VERSION 5.8 ;
BUSBITCHARS "[]" ;
DIVIDERCHAR "/" ;
UNITS
    DATABASE MICRONS 1000 ;
END UNITS

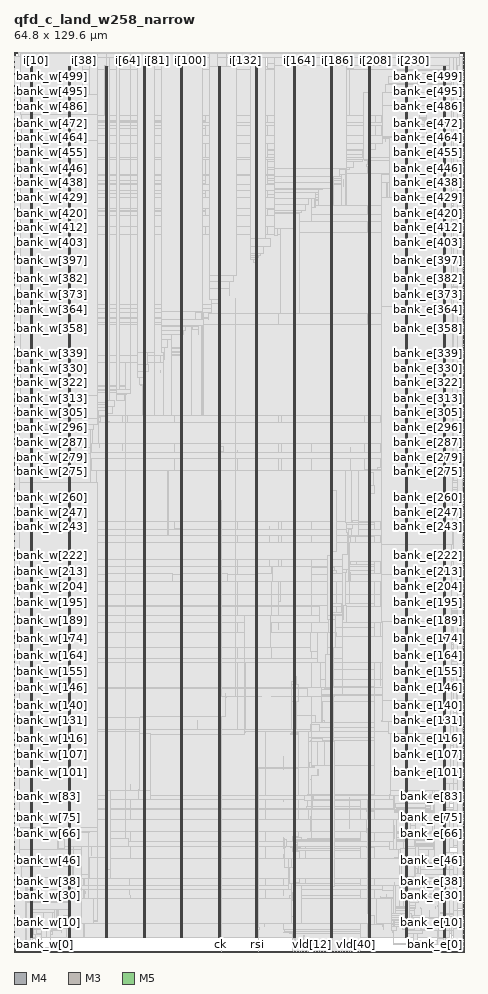
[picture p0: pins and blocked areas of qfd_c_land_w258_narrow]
MACRO qfd_c_land_w258_narrow
  FOREIGN qfd_c_land_w258_narrow 0 0 ;
  CLASS BLOCK ;
  SIZE 64.8 BY 129.6 ;
  PIN bank_e[0]
    DIRECTION OUTPUT ;
    USE SIGNAL ;
    PORT
      LAYER M4 ;
        RECT  64.716 0.672 64.8 0.696 ;
    END
  END bank_e[0]
  PIN bank_e[100]
    DIRECTION OUTPUT ;
    USE SIGNAL ;
    PORT
      LAYER M4 ;
        RECT  64.716 25.584 64.8 25.608 ;
    END
  END bank_e[100]
  PIN bank_e[101]
    DIRECTION OUTPUT ;
    USE SIGNAL ;
    PORT
      LAYER M4 ;
        RECT  64.716 25.824 64.8 25.848 ;
    END
  END bank_e[101]
  PIN bank_e[102]
    DIRECTION OUTPUT ;
    USE SIGNAL ;
    PORT
      LAYER M4 ;
        RECT  64.716 26.064 64.8 26.088 ;
    END
  END bank_e[102]
  PIN bank_e[103]
    DIRECTION OUTPUT ;
    USE SIGNAL ;
    PORT
      LAYER M4 ;
        RECT  64.716 26.304 64.8 26.328 ;
    END
  END bank_e[103]
  PIN bank_e[104]
    DIRECTION OUTPUT ;
    USE SIGNAL ;
    PORT
      LAYER M4 ;
        RECT  64.716 26.544 64.8 26.568 ;
    END
  END bank_e[104]
  PIN bank_e[105]
    DIRECTION OUTPUT ;
    USE SIGNAL ;
    PORT
      LAYER M4 ;
        RECT  64.716 26.784 64.8 26.808 ;
    END
  END bank_e[105]
  PIN bank_e[106]
    DIRECTION OUTPUT ;
    USE SIGNAL ;
    PORT
      LAYER M4 ;
        RECT  64.716 27.072 64.8 27.096 ;
    END
  END bank_e[106]
  PIN bank_e[107]
    DIRECTION OUTPUT ;
    USE SIGNAL ;
    PORT
      LAYER M4 ;
        RECT  64.716 27.312 64.8 27.336 ;
    END
  END bank_e[107]
  PIN bank_e[108]
    DIRECTION OUTPUT ;
    USE SIGNAL ;
    PORT
      LAYER M4 ;
        RECT  64.716 27.552 64.8 27.576 ;
    END
  END bank_e[108]
  PIN bank_e[109]
    DIRECTION OUTPUT ;
    USE SIGNAL ;
    PORT
      LAYER M4 ;
        RECT  64.716 27.792 64.8 27.816 ;
    END
  END bank_e[109]
  PIN bank_e[10]
    DIRECTION OUTPUT ;
    USE SIGNAL ;
    PORT
      LAYER M4 ;
        RECT  64.716 3.12 64.8 3.144 ;
    END
  END bank_e[10]
  PIN bank_e[110]
    DIRECTION OUTPUT ;
    USE SIGNAL ;
    PORT
      LAYER M4 ;
        RECT  64.716 28.032 64.8 28.056 ;
    END
  END bank_e[110]
  PIN bank_e[111]
    DIRECTION OUTPUT ;
    USE SIGNAL ;
    PORT
      LAYER M4 ;
        RECT  64.716 28.32 64.8 28.344 ;
    END
  END bank_e[111]
  PIN bank_e[112]
    DIRECTION OUTPUT ;
    USE SIGNAL ;
    PORT
      LAYER M4 ;
        RECT  64.716 28.56 64.8 28.584 ;
    END
  END bank_e[112]
  PIN bank_e[113]
    DIRECTION OUTPUT ;
    USE SIGNAL ;
    PORT
      LAYER M4 ;
        RECT  64.716 28.8 64.8 28.824 ;
    END
  END bank_e[113]
  PIN bank_e[114]
    DIRECTION OUTPUT ;
    USE SIGNAL ;
    PORT
      LAYER M4 ;
        RECT  64.716 29.04 64.8 29.064 ;
    END
  END bank_e[114]
  PIN bank_e[115]
    DIRECTION OUTPUT ;
    USE SIGNAL ;
    PORT
      LAYER M4 ;
        RECT  64.716 29.28 64.8 29.304 ;
    END
  END bank_e[115]
  PIN bank_e[116]
    DIRECTION OUTPUT ;
    USE SIGNAL ;
    PORT
      LAYER M4 ;
        RECT  64.716 29.568 64.8 29.592 ;
    END
  END bank_e[116]
  PIN bank_e[117]
    DIRECTION OUTPUT ;
    USE SIGNAL ;
    PORT
      LAYER M4 ;
        RECT  64.716 29.808 64.8 29.832 ;
    END
  END bank_e[117]
  PIN bank_e[118]
    DIRECTION OUTPUT ;
    USE SIGNAL ;
    PORT
      LAYER M4 ;
        RECT  64.716 30.048 64.8 30.072 ;
    END
  END bank_e[118]
  PIN bank_e[119]
    DIRECTION OUTPUT ;
    USE SIGNAL ;
    PORT
      LAYER M4 ;
        RECT  64.716 30.288 64.8 30.312 ;
    END
  END bank_e[119]
  PIN bank_e[11]
    DIRECTION OUTPUT ;
    USE SIGNAL ;
    PORT
      LAYER M4 ;
        RECT  64.716 3.408 64.8 3.432 ;
    END
  END bank_e[11]
  PIN bank_e[120]
    DIRECTION OUTPUT ;
    USE SIGNAL ;
    PORT
      LAYER M4 ;
        RECT  64.716 30.528 64.8 30.552 ;
    END
  END bank_e[120]
  PIN bank_e[121]
    DIRECTION OUTPUT ;
    USE SIGNAL ;
    PORT
      LAYER M4 ;
        RECT  64.716 30.768 64.8 30.792 ;
    END
  END bank_e[121]
  PIN bank_e[122]
    DIRECTION OUTPUT ;
    USE SIGNAL ;
    PORT
      LAYER M4 ;
        RECT  64.716 31.056 64.8 31.08 ;
    END
  END bank_e[122]
  PIN bank_e[123]
    DIRECTION OUTPUT ;
    USE SIGNAL ;
    PORT
      LAYER M4 ;
        RECT  64.716 31.296 64.8 31.32 ;
    END
  END bank_e[123]
  PIN bank_e[124]
    DIRECTION OUTPUT ;
    USE SIGNAL ;
    PORT
      LAYER M4 ;
        RECT  64.716 31.536 64.8 31.56 ;
    END
  END bank_e[124]
  PIN bank_e[125]
    DIRECTION OUTPUT ;
    USE SIGNAL ;
    PORT
      LAYER M4 ;
        RECT  64.716 31.776 64.8 31.8 ;
    END
  END bank_e[125]
  PIN bank_e[126]
    DIRECTION OUTPUT ;
    USE SIGNAL ;
    PORT
      LAYER M4 ;
        RECT  64.716 32.016 64.8 32.04 ;
    END
  END bank_e[126]
  PIN bank_e[127]
    DIRECTION OUTPUT ;
    USE SIGNAL ;
    PORT
      LAYER M4 ;
        RECT  64.716 32.304 64.8 32.328 ;
    END
  END bank_e[127]
  PIN bank_e[128]
    DIRECTION OUTPUT ;
    USE SIGNAL ;
    PORT
      LAYER M4 ;
        RECT  64.716 32.544 64.8 32.568 ;
    END
  END bank_e[128]
  PIN bank_e[129]
    DIRECTION OUTPUT ;
    USE SIGNAL ;
    PORT
      LAYER M4 ;
        RECT  64.716 32.784 64.8 32.808 ;
    END
  END bank_e[129]
  PIN bank_e[12]
    DIRECTION OUTPUT ;
    USE SIGNAL ;
    PORT
      LAYER M4 ;
        RECT  64.716 3.648 64.8 3.672 ;
    END
  END bank_e[12]
  PIN bank_e[130]
    DIRECTION OUTPUT ;
    USE SIGNAL ;
    PORT
      LAYER M4 ;
        RECT  64.716 33.024 64.8 33.048 ;
    END
  END bank_e[130]
  PIN bank_e[131]
    DIRECTION OUTPUT ;
    USE SIGNAL ;
    PORT
      LAYER M4 ;
        RECT  64.716 33.264 64.8 33.288 ;
    END
  END bank_e[131]
  PIN bank_e[132]
    DIRECTION OUTPUT ;
    USE SIGNAL ;
    PORT
      LAYER M4 ;
        RECT  64.716 33.552 64.8 33.576 ;
    END
  END bank_e[132]
  PIN bank_e[133]
    DIRECTION OUTPUT ;
    USE SIGNAL ;
    PORT
      LAYER M4 ;
        RECT  64.716 33.792 64.8 33.816 ;
    END
  END bank_e[133]
  PIN bank_e[134]
    DIRECTION OUTPUT ;
    USE SIGNAL ;
    PORT
      LAYER M4 ;
        RECT  64.716 34.032 64.8 34.056 ;
    END
  END bank_e[134]
  PIN bank_e[135]
    DIRECTION OUTPUT ;
    USE SIGNAL ;
    PORT
      LAYER M4 ;
        RECT  64.716 34.272 64.8 34.296 ;
    END
  END bank_e[135]
  PIN bank_e[136]
    DIRECTION OUTPUT ;
    USE SIGNAL ;
    PORT
      LAYER M4 ;
        RECT  64.716 34.512 64.8 34.536 ;
    END
  END bank_e[136]
  PIN bank_e[137]
    DIRECTION OUTPUT ;
    USE SIGNAL ;
    PORT
      LAYER M4 ;
        RECT  64.716 34.752 64.8 34.776 ;
    END
  END bank_e[137]
  PIN bank_e[138]
    DIRECTION OUTPUT ;
    USE SIGNAL ;
    PORT
      LAYER M4 ;
        RECT  64.716 35.04 64.8 35.064 ;
    END
  END bank_e[138]
  PIN bank_e[139]
    DIRECTION OUTPUT ;
    USE SIGNAL ;
    PORT
      LAYER M4 ;
        RECT  64.716 35.28 64.8 35.304 ;
    END
  END bank_e[139]
  PIN bank_e[13]
    DIRECTION OUTPUT ;
    USE SIGNAL ;
    PORT
      LAYER M4 ;
        RECT  64.716 3.888 64.8 3.912 ;
    END
  END bank_e[13]
  PIN bank_e[140]
    DIRECTION OUTPUT ;
    USE SIGNAL ;
    PORT
      LAYER M4 ;
        RECT  64.716 35.52 64.8 35.544 ;
    END
  END bank_e[140]
  PIN bank_e[141]
    DIRECTION OUTPUT ;
    USE SIGNAL ;
    PORT
      LAYER M4 ;
        RECT  64.716 35.76 64.8 35.784 ;
    END
  END bank_e[141]
  PIN bank_e[142]
    DIRECTION OUTPUT ;
    USE SIGNAL ;
    PORT
      LAYER M4 ;
        RECT  64.716 36 64.8 36.024 ;
    END
  END bank_e[142]
  PIN bank_e[143]
    DIRECTION OUTPUT ;
    USE SIGNAL ;
    PORT
      LAYER M4 ;
        RECT  64.716 36.288 64.8 36.312 ;
    END
  END bank_e[143]
  PIN bank_e[144]
    DIRECTION OUTPUT ;
    USE SIGNAL ;
    PORT
      LAYER M4 ;
        RECT  64.716 36.528 64.8 36.552 ;
    END
  END bank_e[144]
  PIN bank_e[145]
    DIRECTION OUTPUT ;
    USE SIGNAL ;
    PORT
      LAYER M4 ;
        RECT  64.716 36.768 64.8 36.792 ;
    END
  END bank_e[145]
  PIN bank_e[146]
    DIRECTION OUTPUT ;
    USE SIGNAL ;
    PORT
      LAYER M4 ;
        RECT  64.716 37.008 64.8 37.032 ;
    END
  END bank_e[146]
  PIN bank_e[147]
    DIRECTION OUTPUT ;
    USE SIGNAL ;
    PORT
      LAYER M4 ;
        RECT  64.716 37.248 64.8 37.272 ;
    END
  END bank_e[147]
  PIN bank_e[148]
    DIRECTION OUTPUT ;
    USE SIGNAL ;
    PORT
      LAYER M4 ;
        RECT  64.716 37.536 64.8 37.56 ;
    END
  END bank_e[148]
  PIN bank_e[149]
    DIRECTION OUTPUT ;
    USE SIGNAL ;
    PORT
      LAYER M4 ;
        RECT  64.716 37.776 64.8 37.8 ;
    END
  END bank_e[149]
  PIN bank_e[14]
    DIRECTION OUTPUT ;
    USE SIGNAL ;
    PORT
      LAYER M4 ;
        RECT  64.716 4.128 64.8 4.152 ;
    END
  END bank_e[14]
  PIN bank_e[150]
    DIRECTION OUTPUT ;
    USE SIGNAL ;
    PORT
      LAYER M4 ;
        RECT  64.716 38.016 64.8 38.04 ;
    END
  END bank_e[150]
  PIN bank_e[151]
    DIRECTION OUTPUT ;
    USE SIGNAL ;
    PORT
      LAYER M4 ;
        RECT  64.716 38.256 64.8 38.28 ;
    END
  END bank_e[151]
  PIN bank_e[152]
    DIRECTION OUTPUT ;
    USE SIGNAL ;
    PORT
      LAYER M4 ;
        RECT  64.716 38.496 64.8 38.52 ;
    END
  END bank_e[152]
  PIN bank_e[153]
    DIRECTION OUTPUT ;
    USE SIGNAL ;
    PORT
      LAYER M4 ;
        RECT  64.716 38.784 64.8 38.808 ;
    END
  END bank_e[153]
  PIN bank_e[154]
    DIRECTION OUTPUT ;
    USE SIGNAL ;
    PORT
      LAYER M4 ;
        RECT  64.716 39.024 64.8 39.048 ;
    END
  END bank_e[154]
  PIN bank_e[155]
    DIRECTION OUTPUT ;
    USE SIGNAL ;
    PORT
      LAYER M4 ;
        RECT  64.716 39.264 64.8 39.288 ;
    END
  END bank_e[155]
  PIN bank_e[156]
    DIRECTION OUTPUT ;
    USE SIGNAL ;
    PORT
      LAYER M4 ;
        RECT  64.716 39.504 64.8 39.528 ;
    END
  END bank_e[156]
  PIN bank_e[157]
    DIRECTION OUTPUT ;
    USE SIGNAL ;
    PORT
      LAYER M4 ;
        RECT  64.716 39.744 64.8 39.768 ;
    END
  END bank_e[157]
  PIN bank_e[158]
    DIRECTION OUTPUT ;
    USE SIGNAL ;
    PORT
      LAYER M4 ;
        RECT  64.716 39.984 64.8 40.008 ;
    END
  END bank_e[158]
  PIN bank_e[159]
    DIRECTION OUTPUT ;
    USE SIGNAL ;
    PORT
      LAYER M4 ;
        RECT  64.716 40.272 64.8 40.296 ;
    END
  END bank_e[159]
  PIN bank_e[15]
    DIRECTION OUTPUT ;
    USE SIGNAL ;
    PORT
      LAYER M4 ;
        RECT  64.716 4.368 64.8 4.392 ;
    END
  END bank_e[15]
  PIN bank_e[160]
    DIRECTION OUTPUT ;
    USE SIGNAL ;
    PORT
      LAYER M4 ;
        RECT  64.716 40.512 64.8 40.536 ;
    END
  END bank_e[160]
  PIN bank_e[161]
    DIRECTION OUTPUT ;
    USE SIGNAL ;
    PORT
      LAYER M4 ;
        RECT  64.716 40.752 64.8 40.776 ;
    END
  END bank_e[161]
  PIN bank_e[162]
    DIRECTION OUTPUT ;
    USE SIGNAL ;
    PORT
      LAYER M4 ;
        RECT  64.716 40.992 64.8 41.016 ;
    END
  END bank_e[162]
  PIN bank_e[163]
    DIRECTION OUTPUT ;
    USE SIGNAL ;
    PORT
      LAYER M4 ;
        RECT  64.716 41.232 64.8 41.256 ;
    END
  END bank_e[163]
  PIN bank_e[164]
    DIRECTION OUTPUT ;
    USE SIGNAL ;
    PORT
      LAYER M4 ;
        RECT  64.716 41.52 64.8 41.544 ;
    END
  END bank_e[164]
  PIN bank_e[165]
    DIRECTION OUTPUT ;
    USE SIGNAL ;
    PORT
      LAYER M4 ;
        RECT  64.716 41.76 64.8 41.784 ;
    END
  END bank_e[165]
  PIN bank_e[166]
    DIRECTION OUTPUT ;
    USE SIGNAL ;
    PORT
      LAYER M4 ;
        RECT  64.716 42 64.8 42.024 ;
    END
  END bank_e[166]
  PIN bank_e[167]
    DIRECTION OUTPUT ;
    USE SIGNAL ;
    PORT
      LAYER M4 ;
        RECT  64.716 42.24 64.8 42.264 ;
    END
  END bank_e[167]
  PIN bank_e[168]
    DIRECTION OUTPUT ;
    USE SIGNAL ;
    PORT
      LAYER M4 ;
        RECT  64.716 42.48 64.8 42.504 ;
    END
  END bank_e[168]
  PIN bank_e[169]
    DIRECTION OUTPUT ;
    USE SIGNAL ;
    PORT
      LAYER M4 ;
        RECT  64.716 42.768 64.8 42.792 ;
    END
  END bank_e[169]
  PIN bank_e[16]
    DIRECTION OUTPUT ;
    USE SIGNAL ;
    PORT
      LAYER M4 ;
        RECT  64.716 4.656 64.8 4.68 ;
    END
  END bank_e[16]
  PIN bank_e[170]
    DIRECTION OUTPUT ;
    USE SIGNAL ;
    PORT
      LAYER M4 ;
        RECT  64.716 43.008 64.8 43.032 ;
    END
  END bank_e[170]
  PIN bank_e[171]
    DIRECTION OUTPUT ;
    USE SIGNAL ;
    PORT
      LAYER M4 ;
        RECT  64.716 43.248 64.8 43.272 ;
    END
  END bank_e[171]
  PIN bank_e[172]
    DIRECTION OUTPUT ;
    USE SIGNAL ;
    PORT
      LAYER M4 ;
        RECT  64.716 43.488 64.8 43.512 ;
    END
  END bank_e[172]
  PIN bank_e[173]
    DIRECTION OUTPUT ;
    USE SIGNAL ;
    PORT
      LAYER M4 ;
        RECT  64.716 43.728 64.8 43.752 ;
    END
  END bank_e[173]
  PIN bank_e[174]
    DIRECTION OUTPUT ;
    USE SIGNAL ;
    PORT
      LAYER M4 ;
        RECT  64.716 43.968 64.8 43.992 ;
    END
  END bank_e[174]
  PIN bank_e[175]
    DIRECTION OUTPUT ;
    USE SIGNAL ;
    PORT
      LAYER M4 ;
        RECT  64.716 44.256 64.8 44.28 ;
    END
  END bank_e[175]
  PIN bank_e[176]
    DIRECTION OUTPUT ;
    USE SIGNAL ;
    PORT
      LAYER M4 ;
        RECT  64.716 44.496 64.8 44.52 ;
    END
  END bank_e[176]
  PIN bank_e[177]
    DIRECTION OUTPUT ;
    USE SIGNAL ;
    PORT
      LAYER M4 ;
        RECT  64.716 44.736 64.8 44.76 ;
    END
  END bank_e[177]
  PIN bank_e[178]
    DIRECTION OUTPUT ;
    USE SIGNAL ;
    PORT
      LAYER M4 ;
        RECT  64.716 44.976 64.8 45 ;
    END
  END bank_e[178]
  PIN bank_e[179]
    DIRECTION OUTPUT ;
    USE SIGNAL ;
    PORT
      LAYER M4 ;
        RECT  64.716 45.216 64.8 45.24 ;
    END
  END bank_e[179]
  PIN bank_e[17]
    DIRECTION OUTPUT ;
    USE SIGNAL ;
    PORT
      LAYER M4 ;
        RECT  64.716 4.896 64.8 4.92 ;
    END
  END bank_e[17]
  PIN bank_e[180]
    DIRECTION OUTPUT ;
    USE SIGNAL ;
    PORT
      LAYER M4 ;
        RECT  64.716 45.504 64.8 45.528 ;
    END
  END bank_e[180]
  PIN bank_e[181]
    DIRECTION OUTPUT ;
    USE SIGNAL ;
    PORT
      LAYER M4 ;
        RECT  64.716 45.744 64.8 45.768 ;
    END
  END bank_e[181]
  PIN bank_e[182]
    DIRECTION OUTPUT ;
    USE SIGNAL ;
    PORT
      LAYER M4 ;
        RECT  64.716 45.984 64.8 46.008 ;
    END
  END bank_e[182]
  PIN bank_e[183]
    DIRECTION OUTPUT ;
    USE SIGNAL ;
    PORT
      LAYER M4 ;
        RECT  64.716 46.224 64.8 46.248 ;
    END
  END bank_e[183]
  PIN bank_e[184]
    DIRECTION OUTPUT ;
    USE SIGNAL ;
    PORT
      LAYER M4 ;
        RECT  64.716 46.464 64.8 46.488 ;
    END
  END bank_e[184]
  PIN bank_e[185]
    DIRECTION OUTPUT ;
    USE SIGNAL ;
    PORT
      LAYER M4 ;
        RECT  64.716 46.752 64.8 46.776 ;
    END
  END bank_e[185]
  PIN bank_e[186]
    DIRECTION OUTPUT ;
    USE SIGNAL ;
    PORT
      LAYER M4 ;
        RECT  64.716 46.992 64.8 47.016 ;
    END
  END bank_e[186]
  PIN bank_e[187]
    DIRECTION OUTPUT ;
    USE SIGNAL ;
    PORT
      LAYER M4 ;
        RECT  64.716 47.232 64.8 47.256 ;
    END
  END bank_e[187]
  PIN bank_e[188]
    DIRECTION OUTPUT ;
    USE SIGNAL ;
    PORT
      LAYER M4 ;
        RECT  64.716 47.472 64.8 47.496 ;
    END
  END bank_e[188]
  PIN bank_e[189]
    DIRECTION OUTPUT ;
    USE SIGNAL ;
    PORT
      LAYER M4 ;
        RECT  64.716 47.712 64.8 47.736 ;
    END
  END bank_e[189]
  PIN bank_e[18]
    DIRECTION OUTPUT ;
    USE SIGNAL ;
    PORT
      LAYER M4 ;
        RECT  64.716 5.136 64.8 5.16 ;
    END
  END bank_e[18]
  PIN bank_e[190]
    DIRECTION OUTPUT ;
    USE SIGNAL ;
    PORT
      LAYER M4 ;
        RECT  64.716 48 64.8 48.024 ;
    END
  END bank_e[190]
  PIN bank_e[191]
    DIRECTION OUTPUT ;
    USE SIGNAL ;
    PORT
      LAYER M4 ;
        RECT  64.716 48.24 64.8 48.264 ;
    END
  END bank_e[191]
  PIN bank_e[192]
    DIRECTION OUTPUT ;
    USE SIGNAL ;
    PORT
      LAYER M4 ;
        RECT  64.716 48.48 64.8 48.504 ;
    END
  END bank_e[192]
  PIN bank_e[193]
    DIRECTION OUTPUT ;
    USE SIGNAL ;
    PORT
      LAYER M4 ;
        RECT  64.716 48.72 64.8 48.744 ;
    END
  END bank_e[193]
  PIN bank_e[194]
    DIRECTION OUTPUT ;
    USE SIGNAL ;
    PORT
      LAYER M4 ;
        RECT  64.716 48.96 64.8 48.984 ;
    END
  END bank_e[194]
  PIN bank_e[195]
    DIRECTION OUTPUT ;
    USE SIGNAL ;
    PORT
      LAYER M4 ;
        RECT  64.716 49.2 64.8 49.224 ;
    END
  END bank_e[195]
  PIN bank_e[196]
    DIRECTION OUTPUT ;
    USE SIGNAL ;
    PORT
      LAYER M4 ;
        RECT  64.716 49.488 64.8 49.512 ;
    END
  END bank_e[196]
  PIN bank_e[197]
    DIRECTION OUTPUT ;
    USE SIGNAL ;
    PORT
      LAYER M4 ;
        RECT  64.716 49.728 64.8 49.752 ;
    END
  END bank_e[197]
  PIN bank_e[198]
    DIRECTION OUTPUT ;
    USE SIGNAL ;
    PORT
      LAYER M4 ;
        RECT  64.716 49.968 64.8 49.992 ;
    END
  END bank_e[198]
  PIN bank_e[199]
    DIRECTION OUTPUT ;
    USE SIGNAL ;
    PORT
      LAYER M4 ;
        RECT  64.716 50.208 64.8 50.232 ;
    END
  END bank_e[199]
  PIN bank_e[19]
    DIRECTION OUTPUT ;
    USE SIGNAL ;
    PORT
      LAYER M4 ;
        RECT  64.716 5.376 64.8 5.4 ;
    END
  END bank_e[19]
  PIN bank_e[1]
    DIRECTION OUTPUT ;
    USE SIGNAL ;
    PORT
      LAYER M4 ;
        RECT  64.716 0.912 64.8 0.936 ;
    END
  END bank_e[1]
  PIN bank_e[200]
    DIRECTION OUTPUT ;
    USE SIGNAL ;
    PORT
      LAYER M4 ;
        RECT  64.716 50.448 64.8 50.472 ;
    END
  END bank_e[200]
  PIN bank_e[201]
    DIRECTION OUTPUT ;
    USE SIGNAL ;
    PORT
      LAYER M4 ;
        RECT  64.716 50.736 64.8 50.76 ;
    END
  END bank_e[201]
  PIN bank_e[202]
    DIRECTION OUTPUT ;
    USE SIGNAL ;
    PORT
      LAYER M4 ;
        RECT  64.716 50.976 64.8 51 ;
    END
  END bank_e[202]
  PIN bank_e[203]
    DIRECTION OUTPUT ;
    USE SIGNAL ;
    PORT
      LAYER M4 ;
        RECT  64.716 51.216 64.8 51.24 ;
    END
  END bank_e[203]
  PIN bank_e[204]
    DIRECTION OUTPUT ;
    USE SIGNAL ;
    PORT
      LAYER M4 ;
        RECT  64.716 51.456 64.8 51.48 ;
    END
  END bank_e[204]
  PIN bank_e[205]
    DIRECTION OUTPUT ;
    USE SIGNAL ;
    PORT
      LAYER M4 ;
        RECT  64.716 51.696 64.8 51.72 ;
    END
  END bank_e[205]
  PIN bank_e[206]
    DIRECTION OUTPUT ;
    USE SIGNAL ;
    PORT
      LAYER M4 ;
        RECT  64.716 51.984 64.8 52.008 ;
    END
  END bank_e[206]
  PIN bank_e[207]
    DIRECTION OUTPUT ;
    USE SIGNAL ;
    PORT
      LAYER M4 ;
        RECT  64.716 52.224 64.8 52.248 ;
    END
  END bank_e[207]
  PIN bank_e[208]
    DIRECTION OUTPUT ;
    USE SIGNAL ;
    PORT
      LAYER M4 ;
        RECT  64.716 52.464 64.8 52.488 ;
    END
  END bank_e[208]
  PIN bank_e[209]
    DIRECTION OUTPUT ;
    USE SIGNAL ;
    PORT
      LAYER M4 ;
        RECT  64.716 52.704 64.8 52.728 ;
    END
  END bank_e[209]
  PIN bank_e[20]
    DIRECTION OUTPUT ;
    USE SIGNAL ;
    PORT
      LAYER M4 ;
        RECT  64.716 5.616 64.8 5.64 ;
    END
  END bank_e[20]
  PIN bank_e[210]
    DIRECTION OUTPUT ;
    USE SIGNAL ;
    PORT
      LAYER M4 ;
        RECT  64.716 52.944 64.8 52.968 ;
    END
  END bank_e[210]
  PIN bank_e[211]
    DIRECTION OUTPUT ;
    USE SIGNAL ;
    PORT
      LAYER M4 ;
        RECT  64.716 53.184 64.8 53.208 ;
    END
  END bank_e[211]
  PIN bank_e[212]
    DIRECTION OUTPUT ;
    USE SIGNAL ;
    PORT
      LAYER M4 ;
        RECT  64.716 53.472 64.8 53.496 ;
    END
  END bank_e[212]
  PIN bank_e[213]
    DIRECTION OUTPUT ;
    USE SIGNAL ;
    PORT
      LAYER M4 ;
        RECT  64.716 53.712 64.8 53.736 ;
    END
  END bank_e[213]
  PIN bank_e[214]
    DIRECTION OUTPUT ;
    USE SIGNAL ;
    PORT
      LAYER M4 ;
        RECT  64.716 53.952 64.8 53.976 ;
    END
  END bank_e[214]
  PIN bank_e[215]
    DIRECTION OUTPUT ;
    USE SIGNAL ;
    PORT
      LAYER M4 ;
        RECT  64.716 54.192 64.8 54.216 ;
    END
  END bank_e[215]
  PIN bank_e[216]
    DIRECTION OUTPUT ;
    USE SIGNAL ;
    PORT
      LAYER M4 ;
        RECT  64.716 54.432 64.8 54.456 ;
    END
  END bank_e[216]
  PIN bank_e[217]
    DIRECTION OUTPUT ;
    USE SIGNAL ;
    PORT
      LAYER M4 ;
        RECT  64.716 54.72 64.8 54.744 ;
    END
  END bank_e[217]
  PIN bank_e[218]
    DIRECTION OUTPUT ;
    USE SIGNAL ;
    PORT
      LAYER M4 ;
        RECT  64.716 54.96 64.8 54.984 ;
    END
  END bank_e[218]
  PIN bank_e[219]
    DIRECTION OUTPUT ;
    USE SIGNAL ;
    PORT
      LAYER M4 ;
        RECT  64.716 55.2 64.8 55.224 ;
    END
  END bank_e[219]
  PIN bank_e[21]
    DIRECTION OUTPUT ;
    USE SIGNAL ;
    PORT
      LAYER M4 ;
        RECT  64.716 5.904 64.8 5.928 ;
    END
  END bank_e[21]
  PIN bank_e[220]
    DIRECTION OUTPUT ;
    USE SIGNAL ;
    PORT
      LAYER M4 ;
        RECT  64.716 55.44 64.8 55.464 ;
    END
  END bank_e[220]
  PIN bank_e[221]
    DIRECTION OUTPUT ;
    USE SIGNAL ;
    PORT
      LAYER M4 ;
        RECT  64.716 55.68 64.8 55.704 ;
    END
  END bank_e[221]
  PIN bank_e[222]
    DIRECTION OUTPUT ;
    USE SIGNAL ;
    PORT
      LAYER M4 ;
        RECT  64.716 55.968 64.8 55.992 ;
    END
  END bank_e[222]
  PIN bank_e[223]
    DIRECTION OUTPUT ;
    USE SIGNAL ;
    PORT
      LAYER M4 ;
        RECT  64.716 56.208 64.8 56.232 ;
    END
  END bank_e[223]
  PIN bank_e[224]
    DIRECTION OUTPUT ;
    USE SIGNAL ;
    PORT
      LAYER M4 ;
        RECT  64.716 56.448 64.8 56.472 ;
    END
  END bank_e[224]
  PIN bank_e[225]
    DIRECTION OUTPUT ;
    USE SIGNAL ;
    PORT
      LAYER M4 ;
        RECT  64.716 56.688 64.8 56.712 ;
    END
  END bank_e[225]
  PIN bank_e[226]
    DIRECTION OUTPUT ;
    USE SIGNAL ;
    PORT
      LAYER M4 ;
        RECT  64.716 56.928 64.8 56.952 ;
    END
  END bank_e[226]
  PIN bank_e[227]
    DIRECTION OUTPUT ;
    USE SIGNAL ;
    PORT
      LAYER M4 ;
        RECT  64.716 57.168 64.8 57.192 ;
    END
  END bank_e[227]
  PIN bank_e[228]
    DIRECTION OUTPUT ;
    USE SIGNAL ;
    PORT
      LAYER M4 ;
        RECT  64.716 57.456 64.8 57.48 ;
    END
  END bank_e[228]
  PIN bank_e[229]
    DIRECTION OUTPUT ;
    USE SIGNAL ;
    PORT
      LAYER M4 ;
        RECT  64.716 57.696 64.8 57.72 ;
    END
  END bank_e[229]
  PIN bank_e[22]
    DIRECTION OUTPUT ;
    USE SIGNAL ;
    PORT
      LAYER M4 ;
        RECT  64.716 6.144 64.8 6.168 ;
    END
  END bank_e[22]
  PIN bank_e[230]
    DIRECTION OUTPUT ;
    USE SIGNAL ;
    PORT
      LAYER M4 ;
        RECT  64.716 57.936 64.8 57.96 ;
    END
  END bank_e[230]
  PIN bank_e[231]
    DIRECTION OUTPUT ;
    USE SIGNAL ;
    PORT
      LAYER M4 ;
        RECT  64.716 58.176 64.8 58.2 ;
    END
  END bank_e[231]
  PIN bank_e[232]
    DIRECTION OUTPUT ;
    USE SIGNAL ;
    PORT
      LAYER M4 ;
        RECT  64.716 58.416 64.8 58.44 ;
    END
  END bank_e[232]
  PIN bank_e[233]
    DIRECTION OUTPUT ;
    USE SIGNAL ;
    PORT
      LAYER M4 ;
        RECT  64.716 58.704 64.8 58.728 ;
    END
  END bank_e[233]
  PIN bank_e[234]
    DIRECTION OUTPUT ;
    USE SIGNAL ;
    PORT
      LAYER M4 ;
        RECT  64.716 58.944 64.8 58.968 ;
    END
  END bank_e[234]
  PIN bank_e[235]
    DIRECTION OUTPUT ;
    USE SIGNAL ;
    PORT
      LAYER M4 ;
        RECT  64.716 59.184 64.8 59.208 ;
    END
  END bank_e[235]
  PIN bank_e[236]
    DIRECTION OUTPUT ;
    USE SIGNAL ;
    PORT
      LAYER M4 ;
        RECT  64.716 59.424 64.8 59.448 ;
    END
  END bank_e[236]
  PIN bank_e[237]
    DIRECTION OUTPUT ;
    USE SIGNAL ;
    PORT
      LAYER M4 ;
        RECT  64.716 59.664 64.8 59.688 ;
    END
  END bank_e[237]
  PIN bank_e[238]
    DIRECTION OUTPUT ;
    USE SIGNAL ;
    PORT
      LAYER M4 ;
        RECT  64.716 59.952 64.8 59.976 ;
    END
  END bank_e[238]
  PIN bank_e[239]
    DIRECTION OUTPUT ;
    USE SIGNAL ;
    PORT
      LAYER M4 ;
        RECT  64.716 60.192 64.8 60.216 ;
    END
  END bank_e[239]
  PIN bank_e[23]
    DIRECTION OUTPUT ;
    USE SIGNAL ;
    PORT
      LAYER M4 ;
        RECT  64.716 6.384 64.8 6.408 ;
    END
  END bank_e[23]
  PIN bank_e[240]
    DIRECTION OUTPUT ;
    USE SIGNAL ;
    PORT
      LAYER M4 ;
        RECT  64.716 60.432 64.8 60.456 ;
    END
  END bank_e[240]
  PIN bank_e[241]
    DIRECTION OUTPUT ;
    USE SIGNAL ;
    PORT
      LAYER M4 ;
        RECT  64.716 60.672 64.8 60.696 ;
    END
  END bank_e[241]
  PIN bank_e[242]
    DIRECTION OUTPUT ;
    USE SIGNAL ;
    PORT
      LAYER M4 ;
        RECT  64.716 60.912 64.8 60.936 ;
    END
  END bank_e[242]
  PIN bank_e[243]
    DIRECTION OUTPUT ;
    USE SIGNAL ;
    PORT
      LAYER M4 ;
        RECT  64.716 61.2 64.8 61.224 ;
    END
  END bank_e[243]
  PIN bank_e[244]
    DIRECTION OUTPUT ;
    USE SIGNAL ;
    PORT
      LAYER M4 ;
        RECT  64.716 61.44 64.8 61.464 ;
    END
  END bank_e[244]
  PIN bank_e[245]
    DIRECTION OUTPUT ;
    USE SIGNAL ;
    PORT
      LAYER M4 ;
        RECT  64.716 61.68 64.8 61.704 ;
    END
  END bank_e[245]
  PIN bank_e[246]
    DIRECTION OUTPUT ;
    USE SIGNAL ;
    PORT
      LAYER M4 ;
        RECT  64.716 61.92 64.8 61.944 ;
    END
  END bank_e[246]
  PIN bank_e[247]
    DIRECTION OUTPUT ;
    USE SIGNAL ;
    PORT
      LAYER M4 ;
        RECT  64.716 62.16 64.8 62.184 ;
    END
  END bank_e[247]
  PIN bank_e[248]
    DIRECTION OUTPUT ;
    USE SIGNAL ;
    PORT
      LAYER M4 ;
        RECT  64.716 62.4 64.8 62.424 ;
    END
  END bank_e[248]
  PIN bank_e[249]
    DIRECTION OUTPUT ;
    USE SIGNAL ;
    PORT
      LAYER M4 ;
        RECT  64.716 62.688 64.8 62.712 ;
    END
  END bank_e[249]
  PIN bank_e[24]
    DIRECTION OUTPUT ;
    USE SIGNAL ;
    PORT
      LAYER M4 ;
        RECT  64.716 6.624 64.8 6.648 ;
    END
  END bank_e[24]
  PIN bank_e[250]
    DIRECTION OUTPUT ;
    USE SIGNAL ;
    PORT
      LAYER M4 ;
        RECT  64.716 62.928 64.8 62.952 ;
    END
  END bank_e[250]
  PIN bank_e[251]
    DIRECTION OUTPUT ;
    USE SIGNAL ;
    PORT
      LAYER M4 ;
        RECT  64.716 63.168 64.8 63.192 ;
    END
  END bank_e[251]
  PIN bank_e[252]
    DIRECTION OUTPUT ;
    USE SIGNAL ;
    PORT
      LAYER M4 ;
        RECT  64.716 63.408 64.8 63.432 ;
    END
  END bank_e[252]
  PIN bank_e[253]
    DIRECTION OUTPUT ;
    USE SIGNAL ;
    PORT
      LAYER M4 ;
        RECT  64.716 63.648 64.8 63.672 ;
    END
  END bank_e[253]
  PIN bank_e[254]
    DIRECTION OUTPUT ;
    USE SIGNAL ;
    PORT
      LAYER M4 ;
        RECT  64.716 63.936 64.8 63.96 ;
    END
  END bank_e[254]
  PIN bank_e[255]
    DIRECTION OUTPUT ;
    USE SIGNAL ;
    PORT
      LAYER M4 ;
        RECT  64.716 64.176 64.8 64.2 ;
    END
  END bank_e[255]
  PIN bank_e[256]
    DIRECTION OUTPUT ;
    USE SIGNAL ;
    PORT
      LAYER M4 ;
        RECT  64.716 64.416 64.8 64.44 ;
    END
  END bank_e[256]
  PIN bank_e[257]
    DIRECTION OUTPUT ;
    USE SIGNAL ;
    PORT
      LAYER M4 ;
        RECT  64.716 64.656 64.8 64.68 ;
    END
  END bank_e[257]
  PIN bank_e[258]
    DIRECTION OUTPUT ;
    USE SIGNAL ;
    PORT
      LAYER M4 ;
        RECT  64.716 64.896 64.8 64.92 ;
    END
  END bank_e[258]
  PIN bank_e[259]
    DIRECTION OUTPUT ;
    USE SIGNAL ;
    PORT
      LAYER M4 ;
        RECT  64.716 65.184 64.8 65.208 ;
    END
  END bank_e[259]
  PIN bank_e[25]
    DIRECTION OUTPUT ;
    USE SIGNAL ;
    PORT
      LAYER M4 ;
        RECT  64.716 6.864 64.8 6.888 ;
    END
  END bank_e[25]
  PIN bank_e[260]
    DIRECTION OUTPUT ;
    USE SIGNAL ;
    PORT
      LAYER M4 ;
        RECT  64.716 65.424 64.8 65.448 ;
    END
  END bank_e[260]
  PIN bank_e[261]
    DIRECTION OUTPUT ;
    USE SIGNAL ;
    PORT
      LAYER M4 ;
        RECT  64.716 65.664 64.8 65.688 ;
    END
  END bank_e[261]
  PIN bank_e[262]
    DIRECTION OUTPUT ;
    USE SIGNAL ;
    PORT
      LAYER M4 ;
        RECT  64.716 65.904 64.8 65.928 ;
    END
  END bank_e[262]
  PIN bank_e[263]
    DIRECTION OUTPUT ;
    USE SIGNAL ;
    PORT
      LAYER M4 ;
        RECT  64.716 66.144 64.8 66.168 ;
    END
  END bank_e[263]
  PIN bank_e[264]
    DIRECTION OUTPUT ;
    USE SIGNAL ;
    PORT
      LAYER M4 ;
        RECT  64.716 66.384 64.8 66.408 ;
    END
  END bank_e[264]
  PIN bank_e[265]
    DIRECTION OUTPUT ;
    USE SIGNAL ;
    PORT
      LAYER M4 ;
        RECT  64.716 66.672 64.8 66.696 ;
    END
  END bank_e[265]
  PIN bank_e[266]
    DIRECTION OUTPUT ;
    USE SIGNAL ;
    PORT
      LAYER M4 ;
        RECT  64.716 66.912 64.8 66.936 ;
    END
  END bank_e[266]
  PIN bank_e[267]
    DIRECTION OUTPUT ;
    USE SIGNAL ;
    PORT
      LAYER M4 ;
        RECT  64.716 67.152 64.8 67.176 ;
    END
  END bank_e[267]
  PIN bank_e[268]
    DIRECTION OUTPUT ;
    USE SIGNAL ;
    PORT
      LAYER M4 ;
        RECT  64.716 67.392 64.8 67.416 ;
    END
  END bank_e[268]
  PIN bank_e[269]
    DIRECTION OUTPUT ;
    USE SIGNAL ;
    PORT
      LAYER M4 ;
        RECT  64.716 67.632 64.8 67.656 ;
    END
  END bank_e[269]
  PIN bank_e[26]
    DIRECTION OUTPUT ;
    USE SIGNAL ;
    PORT
      LAYER M4 ;
        RECT  64.716 7.152 64.8 7.176 ;
    END
  END bank_e[26]
  PIN bank_e[270]
    DIRECTION OUTPUT ;
    USE SIGNAL ;
    PORT
      LAYER M4 ;
        RECT  64.716 67.92 64.8 67.944 ;
    END
  END bank_e[270]
  PIN bank_e[271]
    DIRECTION OUTPUT ;
    USE SIGNAL ;
    PORT
      LAYER M4 ;
        RECT  64.716 68.16 64.8 68.184 ;
    END
  END bank_e[271]
  PIN bank_e[272]
    DIRECTION OUTPUT ;
    USE SIGNAL ;
    PORT
      LAYER M4 ;
        RECT  64.716 68.4 64.8 68.424 ;
    END
  END bank_e[272]
  PIN bank_e[273]
    DIRECTION OUTPUT ;
    USE SIGNAL ;
    PORT
      LAYER M4 ;
        RECT  64.716 68.64 64.8 68.664 ;
    END
  END bank_e[273]
  PIN bank_e[274]
    DIRECTION OUTPUT ;
    USE SIGNAL ;
    PORT
      LAYER M4 ;
        RECT  64.716 68.88 64.8 68.904 ;
    END
  END bank_e[274]
  PIN bank_e[275]
    DIRECTION OUTPUT ;
    USE SIGNAL ;
    PORT
      LAYER M4 ;
        RECT  64.716 69.168 64.8 69.192 ;
    END
  END bank_e[275]
  PIN bank_e[276]
    DIRECTION OUTPUT ;
    USE SIGNAL ;
    PORT
      LAYER M4 ;
        RECT  64.716 69.408 64.8 69.432 ;
    END
  END bank_e[276]
  PIN bank_e[277]
    DIRECTION OUTPUT ;
    USE SIGNAL ;
    PORT
      LAYER M4 ;
        RECT  64.716 69.648 64.8 69.672 ;
    END
  END bank_e[277]
  PIN bank_e[278]
    DIRECTION OUTPUT ;
    USE SIGNAL ;
    PORT
      LAYER M4 ;
        RECT  64.716 69.888 64.8 69.912 ;
    END
  END bank_e[278]
  PIN bank_e[279]
    DIRECTION OUTPUT ;
    USE SIGNAL ;
    PORT
      LAYER M4 ;
        RECT  64.716 70.128 64.8 70.152 ;
    END
  END bank_e[279]
  PIN bank_e[27]
    DIRECTION OUTPUT ;
    USE SIGNAL ;
    PORT
      LAYER M4 ;
        RECT  64.716 7.392 64.8 7.416 ;
    END
  END bank_e[27]
  PIN bank_e[280]
    DIRECTION OUTPUT ;
    USE SIGNAL ;
    PORT
      LAYER M4 ;
        RECT  64.716 70.416 64.8 70.44 ;
    END
  END bank_e[280]
  PIN bank_e[281]
    DIRECTION OUTPUT ;
    USE SIGNAL ;
    PORT
      LAYER M4 ;
        RECT  64.716 70.656 64.8 70.68 ;
    END
  END bank_e[281]
  PIN bank_e[282]
    DIRECTION OUTPUT ;
    USE SIGNAL ;
    PORT
      LAYER M4 ;
        RECT  64.716 70.896 64.8 70.92 ;
    END
  END bank_e[282]
  PIN bank_e[283]
    DIRECTION OUTPUT ;
    USE SIGNAL ;
    PORT
      LAYER M4 ;
        RECT  64.716 71.136 64.8 71.16 ;
    END
  END bank_e[283]
  PIN bank_e[284]
    DIRECTION OUTPUT ;
    USE SIGNAL ;
    PORT
      LAYER M4 ;
        RECT  64.716 71.376 64.8 71.4 ;
    END
  END bank_e[284]
  PIN bank_e[285]
    DIRECTION OUTPUT ;
    USE SIGNAL ;
    PORT
      LAYER M4 ;
        RECT  64.716 71.616 64.8 71.64 ;
    END
  END bank_e[285]
  PIN bank_e[286]
    DIRECTION OUTPUT ;
    USE SIGNAL ;
    PORT
      LAYER M4 ;
        RECT  64.716 71.904 64.8 71.928 ;
    END
  END bank_e[286]
  PIN bank_e[287]
    DIRECTION OUTPUT ;
    USE SIGNAL ;
    PORT
      LAYER M4 ;
        RECT  64.716 72.144 64.8 72.168 ;
    END
  END bank_e[287]
  PIN bank_e[288]
    DIRECTION OUTPUT ;
    USE SIGNAL ;
    PORT
      LAYER M4 ;
        RECT  64.716 72.384 64.8 72.408 ;
    END
  END bank_e[288]
  PIN bank_e[289]
    DIRECTION OUTPUT ;
    USE SIGNAL ;
    PORT
      LAYER M4 ;
        RECT  64.716 72.624 64.8 72.648 ;
    END
  END bank_e[289]
  PIN bank_e[28]
    DIRECTION OUTPUT ;
    USE SIGNAL ;
    PORT
      LAYER M4 ;
        RECT  64.716 7.632 64.8 7.656 ;
    END
  END bank_e[28]
  PIN bank_e[290]
    DIRECTION OUTPUT ;
    USE SIGNAL ;
    PORT
      LAYER M4 ;
        RECT  64.716 72.864 64.8 72.888 ;
    END
  END bank_e[290]
  PIN bank_e[291]
    DIRECTION OUTPUT ;
    USE SIGNAL ;
    PORT
      LAYER M4 ;
        RECT  64.716 73.152 64.8 73.176 ;
    END
  END bank_e[291]
  PIN bank_e[292]
    DIRECTION OUTPUT ;
    USE SIGNAL ;
    PORT
      LAYER M4 ;
        RECT  64.716 73.392 64.8 73.416 ;
    END
  END bank_e[292]
  PIN bank_e[293]
    DIRECTION OUTPUT ;
    USE SIGNAL ;
    PORT
      LAYER M4 ;
        RECT  64.716 73.632 64.8 73.656 ;
    END
  END bank_e[293]
  PIN bank_e[294]
    DIRECTION OUTPUT ;
    USE SIGNAL ;
    PORT
      LAYER M4 ;
        RECT  64.716 73.872 64.8 73.896 ;
    END
  END bank_e[294]
  PIN bank_e[295]
    DIRECTION OUTPUT ;
    USE SIGNAL ;
    PORT
      LAYER M4 ;
        RECT  64.716 74.112 64.8 74.136 ;
    END
  END bank_e[295]
  PIN bank_e[296]
    DIRECTION OUTPUT ;
    USE SIGNAL ;
    PORT
      LAYER M4 ;
        RECT  64.716 74.4 64.8 74.424 ;
    END
  END bank_e[296]
  PIN bank_e[297]
    DIRECTION OUTPUT ;
    USE SIGNAL ;
    PORT
      LAYER M4 ;
        RECT  64.716 74.64 64.8 74.664 ;
    END
  END bank_e[297]
  PIN bank_e[298]
    DIRECTION OUTPUT ;
    USE SIGNAL ;
    PORT
      LAYER M4 ;
        RECT  64.716 74.88 64.8 74.904 ;
    END
  END bank_e[298]
  PIN bank_e[299]
    DIRECTION OUTPUT ;
    USE SIGNAL ;
    PORT
      LAYER M4 ;
        RECT  64.716 75.12 64.8 75.144 ;
    END
  END bank_e[299]
  PIN bank_e[29]
    DIRECTION OUTPUT ;
    USE SIGNAL ;
    PORT
      LAYER M4 ;
        RECT  64.716 7.872 64.8 7.896 ;
    END
  END bank_e[29]
  PIN bank_e[2]
    DIRECTION OUTPUT ;
    USE SIGNAL ;
    PORT
      LAYER M4 ;
        RECT  64.716 1.152 64.8 1.176 ;
    END
  END bank_e[2]
  PIN bank_e[300]
    DIRECTION OUTPUT ;
    USE SIGNAL ;
    PORT
      LAYER M4 ;
        RECT  64.716 75.36 64.8 75.384 ;
    END
  END bank_e[300]
  PIN bank_e[301]
    DIRECTION OUTPUT ;
    USE SIGNAL ;
    PORT
      LAYER M4 ;
        RECT  64.716 75.6 64.8 75.624 ;
    END
  END bank_e[301]
  PIN bank_e[302]
    DIRECTION OUTPUT ;
    USE SIGNAL ;
    PORT
      LAYER M4 ;
        RECT  64.716 75.888 64.8 75.912 ;
    END
  END bank_e[302]
  PIN bank_e[303]
    DIRECTION OUTPUT ;
    USE SIGNAL ;
    PORT
      LAYER M4 ;
        RECT  64.716 76.128 64.8 76.152 ;
    END
  END bank_e[303]
  PIN bank_e[304]
    DIRECTION OUTPUT ;
    USE SIGNAL ;
    PORT
      LAYER M4 ;
        RECT  64.716 76.368 64.8 76.392 ;
    END
  END bank_e[304]
  PIN bank_e[305]
    DIRECTION OUTPUT ;
    USE SIGNAL ;
    PORT
      LAYER M4 ;
        RECT  64.716 76.608 64.8 76.632 ;
    END
  END bank_e[305]
  PIN bank_e[306]
    DIRECTION OUTPUT ;
    USE SIGNAL ;
    PORT
      LAYER M4 ;
        RECT  64.716 76.848 64.8 76.872 ;
    END
  END bank_e[306]
  PIN bank_e[307]
    DIRECTION OUTPUT ;
    USE SIGNAL ;
    PORT
      LAYER M4 ;
        RECT  64.716 77.136 64.8 77.16 ;
    END
  END bank_e[307]
  PIN bank_e[308]
    DIRECTION OUTPUT ;
    USE SIGNAL ;
    PORT
      LAYER M4 ;
        RECT  64.716 77.376 64.8 77.4 ;
    END
  END bank_e[308]
  PIN bank_e[309]
    DIRECTION OUTPUT ;
    USE SIGNAL ;
    PORT
      LAYER M4 ;
        RECT  64.716 77.616 64.8 77.64 ;
    END
  END bank_e[309]
  PIN bank_e[30]
    DIRECTION OUTPUT ;
    USE SIGNAL ;
    PORT
      LAYER M4 ;
        RECT  64.716 8.112 64.8 8.136 ;
    END
  END bank_e[30]
  PIN bank_e[310]
    DIRECTION OUTPUT ;
    USE SIGNAL ;
    PORT
      LAYER M4 ;
        RECT  64.716 77.856 64.8 77.88 ;
    END
  END bank_e[310]
  PIN bank_e[311]
    DIRECTION OUTPUT ;
    USE SIGNAL ;
    PORT
      LAYER M4 ;
        RECT  64.716 78.096 64.8 78.12 ;
    END
  END bank_e[311]
  PIN bank_e[312]
    DIRECTION OUTPUT ;
    USE SIGNAL ;
    PORT
      LAYER M4 ;
        RECT  64.716 78.384 64.8 78.408 ;
    END
  END bank_e[312]
  PIN bank_e[313]
    DIRECTION OUTPUT ;
    USE SIGNAL ;
    PORT
      LAYER M4 ;
        RECT  64.716 78.624 64.8 78.648 ;
    END
  END bank_e[313]
  PIN bank_e[314]
    DIRECTION OUTPUT ;
    USE SIGNAL ;
    PORT
      LAYER M4 ;
        RECT  64.716 78.864 64.8 78.888 ;
    END
  END bank_e[314]
  PIN bank_e[315]
    DIRECTION OUTPUT ;
    USE SIGNAL ;
    PORT
      LAYER M4 ;
        RECT  64.716 79.104 64.8 79.128 ;
    END
  END bank_e[315]
  PIN bank_e[316]
    DIRECTION OUTPUT ;
    USE SIGNAL ;
    PORT
      LAYER M4 ;
        RECT  64.716 79.344 64.8 79.368 ;
    END
  END bank_e[316]
  PIN bank_e[317]
    DIRECTION OUTPUT ;
    USE SIGNAL ;
    PORT
      LAYER M4 ;
        RECT  64.716 79.632 64.8 79.656 ;
    END
  END bank_e[317]
  PIN bank_e[318]
    DIRECTION OUTPUT ;
    USE SIGNAL ;
    PORT
      LAYER M4 ;
        RECT  64.716 79.872 64.8 79.896 ;
    END
  END bank_e[318]
  PIN bank_e[319]
    DIRECTION OUTPUT ;
    USE SIGNAL ;
    PORT
      LAYER M4 ;
        RECT  64.716 80.112 64.8 80.136 ;
    END
  END bank_e[319]
  PIN bank_e[31]
    DIRECTION OUTPUT ;
    USE SIGNAL ;
    PORT
      LAYER M4 ;
        RECT  64.716 8.352 64.8 8.376 ;
    END
  END bank_e[31]
  PIN bank_e[320]
    DIRECTION OUTPUT ;
    USE SIGNAL ;
    PORT
      LAYER M4 ;
        RECT  64.716 80.352 64.8 80.376 ;
    END
  END bank_e[320]
  PIN bank_e[321]
    DIRECTION OUTPUT ;
    USE SIGNAL ;
    PORT
      LAYER M4 ;
        RECT  64.716 80.592 64.8 80.616 ;
    END
  END bank_e[321]
  PIN bank_e[322]
    DIRECTION OUTPUT ;
    USE SIGNAL ;
    PORT
      LAYER M4 ;
        RECT  64.716 80.832 64.8 80.856 ;
    END
  END bank_e[322]
  PIN bank_e[323]
    DIRECTION OUTPUT ;
    USE SIGNAL ;
    PORT
      LAYER M4 ;
        RECT  64.716 81.12 64.8 81.144 ;
    END
  END bank_e[323]
  PIN bank_e[324]
    DIRECTION OUTPUT ;
    USE SIGNAL ;
    PORT
      LAYER M4 ;
        RECT  64.716 81.36 64.8 81.384 ;
    END
  END bank_e[324]
  PIN bank_e[325]
    DIRECTION OUTPUT ;
    USE SIGNAL ;
    PORT
      LAYER M4 ;
        RECT  64.716 81.6 64.8 81.624 ;
    END
  END bank_e[325]
  PIN bank_e[326]
    DIRECTION OUTPUT ;
    USE SIGNAL ;
    PORT
      LAYER M4 ;
        RECT  64.716 81.84 64.8 81.864 ;
    END
  END bank_e[326]
  PIN bank_e[327]
    DIRECTION OUTPUT ;
    USE SIGNAL ;
    PORT
      LAYER M4 ;
        RECT  64.716 82.08 64.8 82.104 ;
    END
  END bank_e[327]
  PIN bank_e[328]
    DIRECTION OUTPUT ;
    USE SIGNAL ;
    PORT
      LAYER M4 ;
        RECT  64.716 82.368 64.8 82.392 ;
    END
  END bank_e[328]
  PIN bank_e[329]
    DIRECTION OUTPUT ;
    USE SIGNAL ;
    PORT
      LAYER M4 ;
        RECT  64.716 82.608 64.8 82.632 ;
    END
  END bank_e[329]
  PIN bank_e[32]
    DIRECTION OUTPUT ;
    USE SIGNAL ;
    PORT
      LAYER M4 ;
        RECT  64.716 8.64 64.8 8.664 ;
    END
  END bank_e[32]
  PIN bank_e[330]
    DIRECTION OUTPUT ;
    USE SIGNAL ;
    PORT
      LAYER M4 ;
        RECT  64.716 82.848 64.8 82.872 ;
    END
  END bank_e[330]
  PIN bank_e[331]
    DIRECTION OUTPUT ;
    USE SIGNAL ;
    PORT
      LAYER M4 ;
        RECT  64.716 83.088 64.8 83.112 ;
    END
  END bank_e[331]
  PIN bank_e[332]
    DIRECTION OUTPUT ;
    USE SIGNAL ;
    PORT
      LAYER M4 ;
        RECT  64.716 83.328 64.8 83.352 ;
    END
  END bank_e[332]
  PIN bank_e[333]
    DIRECTION OUTPUT ;
    USE SIGNAL ;
    PORT
      LAYER M4 ;
        RECT  64.716 83.616 64.8 83.64 ;
    END
  END bank_e[333]
  PIN bank_e[334]
    DIRECTION OUTPUT ;
    USE SIGNAL ;
    PORT
      LAYER M4 ;
        RECT  64.716 83.856 64.8 83.88 ;
    END
  END bank_e[334]
  PIN bank_e[335]
    DIRECTION OUTPUT ;
    USE SIGNAL ;
    PORT
      LAYER M4 ;
        RECT  64.716 84.096 64.8 84.12 ;
    END
  END bank_e[335]
  PIN bank_e[336]
    DIRECTION OUTPUT ;
    USE SIGNAL ;
    PORT
      LAYER M4 ;
        RECT  64.716 84.336 64.8 84.36 ;
    END
  END bank_e[336]
  PIN bank_e[337]
    DIRECTION OUTPUT ;
    USE SIGNAL ;
    PORT
      LAYER M4 ;
        RECT  64.716 84.576 64.8 84.6 ;
    END
  END bank_e[337]
  PIN bank_e[338]
    DIRECTION OUTPUT ;
    USE SIGNAL ;
    PORT
      LAYER M4 ;
        RECT  64.716 84.816 64.8 84.84 ;
    END
  END bank_e[338]
  PIN bank_e[339]
    DIRECTION OUTPUT ;
    USE SIGNAL ;
    PORT
      LAYER M4 ;
        RECT  64.716 85.104 64.8 85.128 ;
    END
  END bank_e[339]
  PIN bank_e[33]
    DIRECTION OUTPUT ;
    USE SIGNAL ;
    PORT
      LAYER M4 ;
        RECT  64.716 8.88 64.8 8.904 ;
    END
  END bank_e[33]
  PIN bank_e[340]
    DIRECTION OUTPUT ;
    USE SIGNAL ;
    PORT
      LAYER M4 ;
        RECT  64.716 85.344 64.8 85.368 ;
    END
  END bank_e[340]
  PIN bank_e[341]
    DIRECTION OUTPUT ;
    USE SIGNAL ;
    PORT
      LAYER M4 ;
        RECT  64.716 85.584 64.8 85.608 ;
    END
  END bank_e[341]
  PIN bank_e[342]
    DIRECTION OUTPUT ;
    USE SIGNAL ;
    PORT
      LAYER M4 ;
        RECT  64.716 85.824 64.8 85.848 ;
    END
  END bank_e[342]
  PIN bank_e[343]
    DIRECTION OUTPUT ;
    USE SIGNAL ;
    PORT
      LAYER M4 ;
        RECT  64.716 86.064 64.8 86.088 ;
    END
  END bank_e[343]
  PIN bank_e[344]
    DIRECTION OUTPUT ;
    USE SIGNAL ;
    PORT
      LAYER M4 ;
        RECT  64.716 86.352 64.8 86.376 ;
    END
  END bank_e[344]
  PIN bank_e[345]
    DIRECTION OUTPUT ;
    USE SIGNAL ;
    PORT
      LAYER M4 ;
        RECT  64.716 86.592 64.8 86.616 ;
    END
  END bank_e[345]
  PIN bank_e[346]
    DIRECTION OUTPUT ;
    USE SIGNAL ;
    PORT
      LAYER M4 ;
        RECT  64.716 86.832 64.8 86.856 ;
    END
  END bank_e[346]
  PIN bank_e[347]
    DIRECTION OUTPUT ;
    USE SIGNAL ;
    PORT
      LAYER M4 ;
        RECT  64.716 87.072 64.8 87.096 ;
    END
  END bank_e[347]
  PIN bank_e[348]
    DIRECTION OUTPUT ;
    USE SIGNAL ;
    PORT
      LAYER M4 ;
        RECT  64.716 87.312 64.8 87.336 ;
    END
  END bank_e[348]
  PIN bank_e[349]
    DIRECTION OUTPUT ;
    USE SIGNAL ;
    PORT
      LAYER M4 ;
        RECT  64.716 87.6 64.8 87.624 ;
    END
  END bank_e[349]
  PIN bank_e[34]
    DIRECTION OUTPUT ;
    USE SIGNAL ;
    PORT
      LAYER M4 ;
        RECT  64.716 9.12 64.8 9.144 ;
    END
  END bank_e[34]
  PIN bank_e[350]
    DIRECTION OUTPUT ;
    USE SIGNAL ;
    PORT
      LAYER M4 ;
        RECT  64.716 87.84 64.8 87.864 ;
    END
  END bank_e[350]
  PIN bank_e[351]
    DIRECTION OUTPUT ;
    USE SIGNAL ;
    PORT
      LAYER M4 ;
        RECT  64.716 88.08 64.8 88.104 ;
    END
  END bank_e[351]
  PIN bank_e[352]
    DIRECTION OUTPUT ;
    USE SIGNAL ;
    PORT
      LAYER M4 ;
        RECT  64.716 88.32 64.8 88.344 ;
    END
  END bank_e[352]
  PIN bank_e[353]
    DIRECTION OUTPUT ;
    USE SIGNAL ;
    PORT
      LAYER M4 ;
        RECT  64.716 88.56 64.8 88.584 ;
    END
  END bank_e[353]
  PIN bank_e[354]
    DIRECTION OUTPUT ;
    USE SIGNAL ;
    PORT
      LAYER M4 ;
        RECT  64.716 88.8 64.8 88.824 ;
    END
  END bank_e[354]
  PIN bank_e[355]
    DIRECTION OUTPUT ;
    USE SIGNAL ;
    PORT
      LAYER M4 ;
        RECT  64.716 89.088 64.8 89.112 ;
    END
  END bank_e[355]
  PIN bank_e[356]
    DIRECTION OUTPUT ;
    USE SIGNAL ;
    PORT
      LAYER M4 ;
        RECT  64.716 89.328 64.8 89.352 ;
    END
  END bank_e[356]
  PIN bank_e[357]
    DIRECTION OUTPUT ;
    USE SIGNAL ;
    PORT
      LAYER M4 ;
        RECT  64.716 89.568 64.8 89.592 ;
    END
  END bank_e[357]
  PIN bank_e[358]
    DIRECTION OUTPUT ;
    USE SIGNAL ;
    PORT
      LAYER M4 ;
        RECT  64.716 89.808 64.8 89.832 ;
    END
  END bank_e[358]
  PIN bank_e[359]
    DIRECTION OUTPUT ;
    USE SIGNAL ;
    PORT
      LAYER M4 ;
        RECT  64.716 90.048 64.8 90.072 ;
    END
  END bank_e[359]
  PIN bank_e[35]
    DIRECTION OUTPUT ;
    USE SIGNAL ;
    PORT
      LAYER M4 ;
        RECT  64.716 9.36 64.8 9.384 ;
    END
  END bank_e[35]
  PIN bank_e[360]
    DIRECTION OUTPUT ;
    USE SIGNAL ;
    PORT
      LAYER M4 ;
        RECT  64.716 90.336 64.8 90.36 ;
    END
  END bank_e[360]
  PIN bank_e[361]
    DIRECTION OUTPUT ;
    USE SIGNAL ;
    PORT
      LAYER M4 ;
        RECT  64.716 90.576 64.8 90.6 ;
    END
  END bank_e[361]
  PIN bank_e[362]
    DIRECTION OUTPUT ;
    USE SIGNAL ;
    PORT
      LAYER M4 ;
        RECT  64.716 90.816 64.8 90.84 ;
    END
  END bank_e[362]
  PIN bank_e[363]
    DIRECTION OUTPUT ;
    USE SIGNAL ;
    PORT
      LAYER M4 ;
        RECT  64.716 91.056 64.8 91.08 ;
    END
  END bank_e[363]
  PIN bank_e[364]
    DIRECTION OUTPUT ;
    USE SIGNAL ;
    PORT
      LAYER M4 ;
        RECT  64.716 91.296 64.8 91.32 ;
    END
  END bank_e[364]
  PIN bank_e[365]
    DIRECTION OUTPUT ;
    USE SIGNAL ;
    PORT
      LAYER M4 ;
        RECT  64.716 91.584 64.8 91.608 ;
    END
  END bank_e[365]
  PIN bank_e[366]
    DIRECTION OUTPUT ;
    USE SIGNAL ;
    PORT
      LAYER M4 ;
        RECT  64.716 91.824 64.8 91.848 ;
    END
  END bank_e[366]
  PIN bank_e[367]
    DIRECTION OUTPUT ;
    USE SIGNAL ;
    PORT
      LAYER M4 ;
        RECT  64.716 92.064 64.8 92.088 ;
    END
  END bank_e[367]
  PIN bank_e[368]
    DIRECTION OUTPUT ;
    USE SIGNAL ;
    PORT
      LAYER M4 ;
        RECT  64.716 92.304 64.8 92.328 ;
    END
  END bank_e[368]
  PIN bank_e[369]
    DIRECTION OUTPUT ;
    USE SIGNAL ;
    PORT
      LAYER M4 ;
        RECT  64.716 92.544 64.8 92.568 ;
    END
  END bank_e[369]
  PIN bank_e[36]
    DIRECTION OUTPUT ;
    USE SIGNAL ;
    PORT
      LAYER M4 ;
        RECT  64.716 9.6 64.8 9.624 ;
    END
  END bank_e[36]
  PIN bank_e[370]
    DIRECTION OUTPUT ;
    USE SIGNAL ;
    PORT
      LAYER M4 ;
        RECT  64.716 92.832 64.8 92.856 ;
    END
  END bank_e[370]
  PIN bank_e[371]
    DIRECTION OUTPUT ;
    USE SIGNAL ;
    PORT
      LAYER M4 ;
        RECT  64.716 93.072 64.8 93.096 ;
    END
  END bank_e[371]
  PIN bank_e[372]
    DIRECTION OUTPUT ;
    USE SIGNAL ;
    PORT
      LAYER M4 ;
        RECT  64.716 93.312 64.8 93.336 ;
    END
  END bank_e[372]
  PIN bank_e[373]
    DIRECTION OUTPUT ;
    USE SIGNAL ;
    PORT
      LAYER M4 ;
        RECT  64.716 93.552 64.8 93.576 ;
    END
  END bank_e[373]
  PIN bank_e[374]
    DIRECTION OUTPUT ;
    USE SIGNAL ;
    PORT
      LAYER M4 ;
        RECT  64.716 93.792 64.8 93.816 ;
    END
  END bank_e[374]
  PIN bank_e[375]
    DIRECTION OUTPUT ;
    USE SIGNAL ;
    PORT
      LAYER M4 ;
        RECT  64.716 94.032 64.8 94.056 ;
    END
  END bank_e[375]
  PIN bank_e[376]
    DIRECTION OUTPUT ;
    USE SIGNAL ;
    PORT
      LAYER M4 ;
        RECT  64.716 94.32 64.8 94.344 ;
    END
  END bank_e[376]
  PIN bank_e[377]
    DIRECTION OUTPUT ;
    USE SIGNAL ;
    PORT
      LAYER M4 ;
        RECT  64.716 94.56 64.8 94.584 ;
    END
  END bank_e[377]
  PIN bank_e[378]
    DIRECTION OUTPUT ;
    USE SIGNAL ;
    PORT
      LAYER M4 ;
        RECT  64.716 94.8 64.8 94.824 ;
    END
  END bank_e[378]
  PIN bank_e[379]
    DIRECTION OUTPUT ;
    USE SIGNAL ;
    PORT
      LAYER M4 ;
        RECT  64.716 95.04 64.8 95.064 ;
    END
  END bank_e[379]
  PIN bank_e[37]
    DIRECTION OUTPUT ;
    USE SIGNAL ;
    PORT
      LAYER M4 ;
        RECT  64.716 9.888 64.8 9.912 ;
    END
  END bank_e[37]
  PIN bank_e[380]
    DIRECTION OUTPUT ;
    USE SIGNAL ;
    PORT
      LAYER M4 ;
        RECT  64.716 95.28 64.8 95.304 ;
    END
  END bank_e[380]
  PIN bank_e[381]
    DIRECTION OUTPUT ;
    USE SIGNAL ;
    PORT
      LAYER M4 ;
        RECT  64.716 95.568 64.8 95.592 ;
    END
  END bank_e[381]
  PIN bank_e[382]
    DIRECTION OUTPUT ;
    USE SIGNAL ;
    PORT
      LAYER M4 ;
        RECT  64.716 95.808 64.8 95.832 ;
    END
  END bank_e[382]
  PIN bank_e[383]
    DIRECTION OUTPUT ;
    USE SIGNAL ;
    PORT
      LAYER M4 ;
        RECT  64.716 96.048 64.8 96.072 ;
    END
  END bank_e[383]
  PIN bank_e[384]
    DIRECTION OUTPUT ;
    USE SIGNAL ;
    PORT
      LAYER M4 ;
        RECT  64.716 96.288 64.8 96.312 ;
    END
  END bank_e[384]
  PIN bank_e[385]
    DIRECTION OUTPUT ;
    USE SIGNAL ;
    PORT
      LAYER M4 ;
        RECT  64.716 96.528 64.8 96.552 ;
    END
  END bank_e[385]
  PIN bank_e[386]
    DIRECTION OUTPUT ;
    USE SIGNAL ;
    PORT
      LAYER M4 ;
        RECT  64.716 96.816 64.8 96.84 ;
    END
  END bank_e[386]
  PIN bank_e[387]
    DIRECTION OUTPUT ;
    USE SIGNAL ;
    PORT
      LAYER M4 ;
        RECT  64.716 97.056 64.8 97.08 ;
    END
  END bank_e[387]
  PIN bank_e[388]
    DIRECTION OUTPUT ;
    USE SIGNAL ;
    PORT
      LAYER M4 ;
        RECT  64.716 97.296 64.8 97.32 ;
    END
  END bank_e[388]
  PIN bank_e[389]
    DIRECTION OUTPUT ;
    USE SIGNAL ;
    PORT
      LAYER M4 ;
        RECT  64.716 97.536 64.8 97.56 ;
    END
  END bank_e[389]
  PIN bank_e[38]
    DIRECTION OUTPUT ;
    USE SIGNAL ;
    PORT
      LAYER M4 ;
        RECT  64.716 10.128 64.8 10.152 ;
    END
  END bank_e[38]
  PIN bank_e[390]
    DIRECTION OUTPUT ;
    USE SIGNAL ;
    PORT
      LAYER M4 ;
        RECT  64.716 97.776 64.8 97.8 ;
    END
  END bank_e[390]
  PIN bank_e[391]
    DIRECTION OUTPUT ;
    USE SIGNAL ;
    PORT
      LAYER M4 ;
        RECT  64.716 98.016 64.8 98.04 ;
    END
  END bank_e[391]
  PIN bank_e[392]
    DIRECTION OUTPUT ;
    USE SIGNAL ;
    PORT
      LAYER M4 ;
        RECT  64.716 98.304 64.8 98.328 ;
    END
  END bank_e[392]
  PIN bank_e[393]
    DIRECTION OUTPUT ;
    USE SIGNAL ;
    PORT
      LAYER M4 ;
        RECT  64.716 98.544 64.8 98.568 ;
    END
  END bank_e[393]
  PIN bank_e[394]
    DIRECTION OUTPUT ;
    USE SIGNAL ;
    PORT
      LAYER M4 ;
        RECT  64.716 98.784 64.8 98.808 ;
    END
  END bank_e[394]
  PIN bank_e[395]
    DIRECTION OUTPUT ;
    USE SIGNAL ;
    PORT
      LAYER M4 ;
        RECT  64.716 99.024 64.8 99.048 ;
    END
  END bank_e[395]
  PIN bank_e[396]
    DIRECTION OUTPUT ;
    USE SIGNAL ;
    PORT
      LAYER M4 ;
        RECT  64.716 99.264 64.8 99.288 ;
    END
  END bank_e[396]
  PIN bank_e[397]
    DIRECTION OUTPUT ;
    USE SIGNAL ;
    PORT
      LAYER M4 ;
        RECT  64.716 99.552 64.8 99.576 ;
    END
  END bank_e[397]
  PIN bank_e[398]
    DIRECTION OUTPUT ;
    USE SIGNAL ;
    PORT
      LAYER M4 ;
        RECT  64.716 99.792 64.8 99.816 ;
    END
  END bank_e[398]
  PIN bank_e[399]
    DIRECTION OUTPUT ;
    USE SIGNAL ;
    PORT
      LAYER M4 ;
        RECT  64.716 100.032 64.8 100.056 ;
    END
  END bank_e[399]
  PIN bank_e[39]
    DIRECTION OUTPUT ;
    USE SIGNAL ;
    PORT
      LAYER M4 ;
        RECT  64.716 10.368 64.8 10.392 ;
    END
  END bank_e[39]
  PIN bank_e[3]
    DIRECTION OUTPUT ;
    USE SIGNAL ;
    PORT
      LAYER M4 ;
        RECT  64.716 1.392 64.8 1.416 ;
    END
  END bank_e[3]
  PIN bank_e[400]
    DIRECTION OUTPUT ;
    USE SIGNAL ;
    PORT
      LAYER M4 ;
        RECT  64.716 100.272 64.8 100.296 ;
    END
  END bank_e[400]
  PIN bank_e[401]
    DIRECTION OUTPUT ;
    USE SIGNAL ;
    PORT
      LAYER M4 ;
        RECT  64.716 100.512 64.8 100.536 ;
    END
  END bank_e[401]
  PIN bank_e[402]
    DIRECTION OUTPUT ;
    USE SIGNAL ;
    PORT
      LAYER M4 ;
        RECT  64.716 100.8 64.8 100.824 ;
    END
  END bank_e[402]
  PIN bank_e[403]
    DIRECTION OUTPUT ;
    USE SIGNAL ;
    PORT
      LAYER M4 ;
        RECT  64.716 101.04 64.8 101.064 ;
    END
  END bank_e[403]
  PIN bank_e[404]
    DIRECTION OUTPUT ;
    USE SIGNAL ;
    PORT
      LAYER M4 ;
        RECT  64.716 101.28 64.8 101.304 ;
    END
  END bank_e[404]
  PIN bank_e[405]
    DIRECTION OUTPUT ;
    USE SIGNAL ;
    PORT
      LAYER M4 ;
        RECT  64.716 101.52 64.8 101.544 ;
    END
  END bank_e[405]
  PIN bank_e[406]
    DIRECTION OUTPUT ;
    USE SIGNAL ;
    PORT
      LAYER M4 ;
        RECT  64.716 101.76 64.8 101.784 ;
    END
  END bank_e[406]
  PIN bank_e[407]
    DIRECTION OUTPUT ;
    USE SIGNAL ;
    PORT
      LAYER M4 ;
        RECT  64.716 102.048 64.8 102.072 ;
    END
  END bank_e[407]
  PIN bank_e[408]
    DIRECTION OUTPUT ;
    USE SIGNAL ;
    PORT
      LAYER M4 ;
        RECT  64.716 102.288 64.8 102.312 ;
    END
  END bank_e[408]
  PIN bank_e[409]
    DIRECTION OUTPUT ;
    USE SIGNAL ;
    PORT
      LAYER M4 ;
        RECT  64.716 102.528 64.8 102.552 ;
    END
  END bank_e[409]
  PIN bank_e[40]
    DIRECTION OUTPUT ;
    USE SIGNAL ;
    PORT
      LAYER M4 ;
        RECT  64.716 10.608 64.8 10.632 ;
    END
  END bank_e[40]
  PIN bank_e[410]
    DIRECTION OUTPUT ;
    USE SIGNAL ;
    PORT
      LAYER M4 ;
        RECT  64.716 102.768 64.8 102.792 ;
    END
  END bank_e[410]
  PIN bank_e[411]
    DIRECTION OUTPUT ;
    USE SIGNAL ;
    PORT
      LAYER M4 ;
        RECT  64.716 103.008 64.8 103.032 ;
    END
  END bank_e[411]
  PIN bank_e[412]
    DIRECTION OUTPUT ;
    USE SIGNAL ;
    PORT
      LAYER M4 ;
        RECT  64.716 103.248 64.8 103.272 ;
    END
  END bank_e[412]
  PIN bank_e[413]
    DIRECTION OUTPUT ;
    USE SIGNAL ;
    PORT
      LAYER M4 ;
        RECT  64.716 103.536 64.8 103.56 ;
    END
  END bank_e[413]
  PIN bank_e[414]
    DIRECTION OUTPUT ;
    USE SIGNAL ;
    PORT
      LAYER M4 ;
        RECT  64.716 103.776 64.8 103.8 ;
    END
  END bank_e[414]
  PIN bank_e[415]
    DIRECTION OUTPUT ;
    USE SIGNAL ;
    PORT
      LAYER M4 ;
        RECT  64.716 104.016 64.8 104.04 ;
    END
  END bank_e[415]
  PIN bank_e[416]
    DIRECTION OUTPUT ;
    USE SIGNAL ;
    PORT
      LAYER M4 ;
        RECT  64.716 104.256 64.8 104.28 ;
    END
  END bank_e[416]
  PIN bank_e[417]
    DIRECTION OUTPUT ;
    USE SIGNAL ;
    PORT
      LAYER M4 ;
        RECT  64.716 104.496 64.8 104.52 ;
    END
  END bank_e[417]
  PIN bank_e[418]
    DIRECTION OUTPUT ;
    USE SIGNAL ;
    PORT
      LAYER M4 ;
        RECT  64.716 104.784 64.8 104.808 ;
    END
  END bank_e[418]
  PIN bank_e[419]
    DIRECTION OUTPUT ;
    USE SIGNAL ;
    PORT
      LAYER M4 ;
        RECT  64.716 105.024 64.8 105.048 ;
    END
  END bank_e[419]
  PIN bank_e[41]
    DIRECTION OUTPUT ;
    USE SIGNAL ;
    PORT
      LAYER M4 ;
        RECT  64.716 10.848 64.8 10.872 ;
    END
  END bank_e[41]
  PIN bank_e[420]
    DIRECTION OUTPUT ;
    USE SIGNAL ;
    PORT
      LAYER M4 ;
        RECT  64.716 105.264 64.8 105.288 ;
    END
  END bank_e[420]
  PIN bank_e[421]
    DIRECTION OUTPUT ;
    USE SIGNAL ;
    PORT
      LAYER M4 ;
        RECT  64.716 105.504 64.8 105.528 ;
    END
  END bank_e[421]
  PIN bank_e[422]
    DIRECTION OUTPUT ;
    USE SIGNAL ;
    PORT
      LAYER M4 ;
        RECT  64.716 105.744 64.8 105.768 ;
    END
  END bank_e[422]
  PIN bank_e[423]
    DIRECTION OUTPUT ;
    USE SIGNAL ;
    PORT
      LAYER M4 ;
        RECT  64.716 106.032 64.8 106.056 ;
    END
  END bank_e[423]
  PIN bank_e[424]
    DIRECTION OUTPUT ;
    USE SIGNAL ;
    PORT
      LAYER M4 ;
        RECT  64.716 106.272 64.8 106.296 ;
    END
  END bank_e[424]
  PIN bank_e[425]
    DIRECTION OUTPUT ;
    USE SIGNAL ;
    PORT
      LAYER M4 ;
        RECT  64.716 106.512 64.8 106.536 ;
    END
  END bank_e[425]
  PIN bank_e[426]
    DIRECTION OUTPUT ;
    USE SIGNAL ;
    PORT
      LAYER M4 ;
        RECT  64.716 106.752 64.8 106.776 ;
    END
  END bank_e[426]
  PIN bank_e[427]
    DIRECTION OUTPUT ;
    USE SIGNAL ;
    PORT
      LAYER M4 ;
        RECT  64.716 106.992 64.8 107.016 ;
    END
  END bank_e[427]
  PIN bank_e[428]
    DIRECTION OUTPUT ;
    USE SIGNAL ;
    PORT
      LAYER M4 ;
        RECT  64.716 107.232 64.8 107.256 ;
    END
  END bank_e[428]
  PIN bank_e[429]
    DIRECTION OUTPUT ;
    USE SIGNAL ;
    PORT
      LAYER M4 ;
        RECT  64.716 107.52 64.8 107.544 ;
    END
  END bank_e[429]
  PIN bank_e[42]
    DIRECTION OUTPUT ;
    USE SIGNAL ;
    PORT
      LAYER M4 ;
        RECT  64.716 11.136 64.8 11.16 ;
    END
  END bank_e[42]
  PIN bank_e[430]
    DIRECTION OUTPUT ;
    USE SIGNAL ;
    PORT
      LAYER M4 ;
        RECT  64.716 107.76 64.8 107.784 ;
    END
  END bank_e[430]
  PIN bank_e[431]
    DIRECTION OUTPUT ;
    USE SIGNAL ;
    PORT
      LAYER M4 ;
        RECT  64.716 108 64.8 108.024 ;
    END
  END bank_e[431]
  PIN bank_e[432]
    DIRECTION OUTPUT ;
    USE SIGNAL ;
    PORT
      LAYER M4 ;
        RECT  64.716 108.24 64.8 108.264 ;
    END
  END bank_e[432]
  PIN bank_e[433]
    DIRECTION OUTPUT ;
    USE SIGNAL ;
    PORT
      LAYER M4 ;
        RECT  64.716 108.48 64.8 108.504 ;
    END
  END bank_e[433]
  PIN bank_e[434]
    DIRECTION OUTPUT ;
    USE SIGNAL ;
    PORT
      LAYER M4 ;
        RECT  64.716 108.768 64.8 108.792 ;
    END
  END bank_e[434]
  PIN bank_e[435]
    DIRECTION OUTPUT ;
    USE SIGNAL ;
    PORT
      LAYER M4 ;
        RECT  64.716 109.008 64.8 109.032 ;
    END
  END bank_e[435]
  PIN bank_e[436]
    DIRECTION OUTPUT ;
    USE SIGNAL ;
    PORT
      LAYER M4 ;
        RECT  64.716 109.248 64.8 109.272 ;
    END
  END bank_e[436]
  PIN bank_e[437]
    DIRECTION OUTPUT ;
    USE SIGNAL ;
    PORT
      LAYER M4 ;
        RECT  64.716 109.488 64.8 109.512 ;
    END
  END bank_e[437]
  PIN bank_e[438]
    DIRECTION OUTPUT ;
    USE SIGNAL ;
    PORT
      LAYER M4 ;
        RECT  64.716 109.728 64.8 109.752 ;
    END
  END bank_e[438]
  PIN bank_e[439]
    DIRECTION OUTPUT ;
    USE SIGNAL ;
    PORT
      LAYER M4 ;
        RECT  64.716 110.016 64.8 110.04 ;
    END
  END bank_e[439]
  PIN bank_e[43]
    DIRECTION OUTPUT ;
    USE SIGNAL ;
    PORT
      LAYER M4 ;
        RECT  64.716 11.376 64.8 11.4 ;
    END
  END bank_e[43]
  PIN bank_e[440]
    DIRECTION OUTPUT ;
    USE SIGNAL ;
    PORT
      LAYER M4 ;
        RECT  64.716 110.256 64.8 110.28 ;
    END
  END bank_e[440]
  PIN bank_e[441]
    DIRECTION OUTPUT ;
    USE SIGNAL ;
    PORT
      LAYER M4 ;
        RECT  64.716 110.496 64.8 110.52 ;
    END
  END bank_e[441]
  PIN bank_e[442]
    DIRECTION OUTPUT ;
    USE SIGNAL ;
    PORT
      LAYER M4 ;
        RECT  64.716 110.736 64.8 110.76 ;
    END
  END bank_e[442]
  PIN bank_e[443]
    DIRECTION OUTPUT ;
    USE SIGNAL ;
    PORT
      LAYER M4 ;
        RECT  64.716 110.976 64.8 111 ;
    END
  END bank_e[443]
  PIN bank_e[444]
    DIRECTION OUTPUT ;
    USE SIGNAL ;
    PORT
      LAYER M4 ;
        RECT  64.716 111.264 64.8 111.288 ;
    END
  END bank_e[444]
  PIN bank_e[445]
    DIRECTION OUTPUT ;
    USE SIGNAL ;
    PORT
      LAYER M4 ;
        RECT  64.716 111.504 64.8 111.528 ;
    END
  END bank_e[445]
  PIN bank_e[446]
    DIRECTION OUTPUT ;
    USE SIGNAL ;
    PORT
      LAYER M4 ;
        RECT  64.716 111.744 64.8 111.768 ;
    END
  END bank_e[446]
  PIN bank_e[447]
    DIRECTION OUTPUT ;
    USE SIGNAL ;
    PORT
      LAYER M4 ;
        RECT  64.716 111.984 64.8 112.008 ;
    END
  END bank_e[447]
  PIN bank_e[448]
    DIRECTION OUTPUT ;
    USE SIGNAL ;
    PORT
      LAYER M4 ;
        RECT  64.716 112.224 64.8 112.248 ;
    END
  END bank_e[448]
  PIN bank_e[449]
    DIRECTION OUTPUT ;
    USE SIGNAL ;
    PORT
      LAYER M4 ;
        RECT  64.716 112.464 64.8 112.488 ;
    END
  END bank_e[449]
  PIN bank_e[44]
    DIRECTION OUTPUT ;
    USE SIGNAL ;
    PORT
      LAYER M4 ;
        RECT  64.716 11.616 64.8 11.64 ;
    END
  END bank_e[44]
  PIN bank_e[450]
    DIRECTION OUTPUT ;
    USE SIGNAL ;
    PORT
      LAYER M4 ;
        RECT  64.716 112.752 64.8 112.776 ;
    END
  END bank_e[450]
  PIN bank_e[451]
    DIRECTION OUTPUT ;
    USE SIGNAL ;
    PORT
      LAYER M4 ;
        RECT  64.716 112.992 64.8 113.016 ;
    END
  END bank_e[451]
  PIN bank_e[452]
    DIRECTION OUTPUT ;
    USE SIGNAL ;
    PORT
      LAYER M4 ;
        RECT  64.716 113.232 64.8 113.256 ;
    END
  END bank_e[452]
  PIN bank_e[453]
    DIRECTION OUTPUT ;
    USE SIGNAL ;
    PORT
      LAYER M4 ;
        RECT  64.716 113.472 64.8 113.496 ;
    END
  END bank_e[453]
  PIN bank_e[454]
    DIRECTION OUTPUT ;
    USE SIGNAL ;
    PORT
      LAYER M4 ;
        RECT  64.716 113.712 64.8 113.736 ;
    END
  END bank_e[454]
  PIN bank_e[455]
    DIRECTION OUTPUT ;
    USE SIGNAL ;
    PORT
      LAYER M4 ;
        RECT  64.716 114 64.8 114.024 ;
    END
  END bank_e[455]
  PIN bank_e[456]
    DIRECTION OUTPUT ;
    USE SIGNAL ;
    PORT
      LAYER M4 ;
        RECT  64.716 114.24 64.8 114.264 ;
    END
  END bank_e[456]
  PIN bank_e[457]
    DIRECTION OUTPUT ;
    USE SIGNAL ;
    PORT
      LAYER M4 ;
        RECT  64.716 114.48 64.8 114.504 ;
    END
  END bank_e[457]
  PIN bank_e[458]
    DIRECTION OUTPUT ;
    USE SIGNAL ;
    PORT
      LAYER M4 ;
        RECT  64.716 114.72 64.8 114.744 ;
    END
  END bank_e[458]
  PIN bank_e[459]
    DIRECTION OUTPUT ;
    USE SIGNAL ;
    PORT
      LAYER M4 ;
        RECT  64.716 114.96 64.8 114.984 ;
    END
  END bank_e[459]
  PIN bank_e[45]
    DIRECTION OUTPUT ;
    USE SIGNAL ;
    PORT
      LAYER M4 ;
        RECT  64.716 11.856 64.8 11.88 ;
    END
  END bank_e[45]
  PIN bank_e[460]
    DIRECTION OUTPUT ;
    USE SIGNAL ;
    PORT
      LAYER M4 ;
        RECT  64.716 115.248 64.8 115.272 ;
    END
  END bank_e[460]
  PIN bank_e[461]
    DIRECTION OUTPUT ;
    USE SIGNAL ;
    PORT
      LAYER M4 ;
        RECT  64.716 115.488 64.8 115.512 ;
    END
  END bank_e[461]
  PIN bank_e[462]
    DIRECTION OUTPUT ;
    USE SIGNAL ;
    PORT
      LAYER M4 ;
        RECT  64.716 115.728 64.8 115.752 ;
    END
  END bank_e[462]
  PIN bank_e[463]
    DIRECTION OUTPUT ;
    USE SIGNAL ;
    PORT
      LAYER M4 ;
        RECT  64.716 115.968 64.8 115.992 ;
    END
  END bank_e[463]
  PIN bank_e[464]
    DIRECTION OUTPUT ;
    USE SIGNAL ;
    PORT
      LAYER M4 ;
        RECT  64.716 116.208 64.8 116.232 ;
    END
  END bank_e[464]
  PIN bank_e[465]
    DIRECTION OUTPUT ;
    USE SIGNAL ;
    PORT
      LAYER M4 ;
        RECT  64.716 116.448 64.8 116.472 ;
    END
  END bank_e[465]
  PIN bank_e[466]
    DIRECTION OUTPUT ;
    USE SIGNAL ;
    PORT
      LAYER M4 ;
        RECT  64.716 116.736 64.8 116.76 ;
    END
  END bank_e[466]
  PIN bank_e[467]
    DIRECTION OUTPUT ;
    USE SIGNAL ;
    PORT
      LAYER M4 ;
        RECT  64.716 116.976 64.8 117 ;
    END
  END bank_e[467]
  PIN bank_e[468]
    DIRECTION OUTPUT ;
    USE SIGNAL ;
    PORT
      LAYER M4 ;
        RECT  64.716 117.216 64.8 117.24 ;
    END
  END bank_e[468]
  PIN bank_e[469]
    DIRECTION OUTPUT ;
    USE SIGNAL ;
    PORT
      LAYER M4 ;
        RECT  64.716 117.456 64.8 117.48 ;
    END
  END bank_e[469]
  PIN bank_e[46]
    DIRECTION OUTPUT ;
    USE SIGNAL ;
    PORT
      LAYER M4 ;
        RECT  64.716 12.096 64.8 12.12 ;
    END
  END bank_e[46]
  PIN bank_e[470]
    DIRECTION OUTPUT ;
    USE SIGNAL ;
    PORT
      LAYER M4 ;
        RECT  64.716 117.696 64.8 117.72 ;
    END
  END bank_e[470]
  PIN bank_e[471]
    DIRECTION OUTPUT ;
    USE SIGNAL ;
    PORT
      LAYER M4 ;
        RECT  64.716 117.984 64.8 118.008 ;
    END
  END bank_e[471]
  PIN bank_e[472]
    DIRECTION OUTPUT ;
    USE SIGNAL ;
    PORT
      LAYER M4 ;
        RECT  64.716 118.224 64.8 118.248 ;
    END
  END bank_e[472]
  PIN bank_e[473]
    DIRECTION OUTPUT ;
    USE SIGNAL ;
    PORT
      LAYER M4 ;
        RECT  64.716 118.464 64.8 118.488 ;
    END
  END bank_e[473]
  PIN bank_e[474]
    DIRECTION OUTPUT ;
    USE SIGNAL ;
    PORT
      LAYER M4 ;
        RECT  64.716 118.704 64.8 118.728 ;
    END
  END bank_e[474]
  PIN bank_e[475]
    DIRECTION OUTPUT ;
    USE SIGNAL ;
    PORT
      LAYER M4 ;
        RECT  64.716 118.944 64.8 118.968 ;
    END
  END bank_e[475]
  PIN bank_e[476]
    DIRECTION OUTPUT ;
    USE SIGNAL ;
    PORT
      LAYER M4 ;
        RECT  64.716 119.232 64.8 119.256 ;
    END
  END bank_e[476]
  PIN bank_e[477]
    DIRECTION OUTPUT ;
    USE SIGNAL ;
    PORT
      LAYER M4 ;
        RECT  64.716 119.472 64.8 119.496 ;
    END
  END bank_e[477]
  PIN bank_e[478]
    DIRECTION OUTPUT ;
    USE SIGNAL ;
    PORT
      LAYER M4 ;
        RECT  64.716 119.712 64.8 119.736 ;
    END
  END bank_e[478]
  PIN bank_e[479]
    DIRECTION OUTPUT ;
    USE SIGNAL ;
    PORT
      LAYER M4 ;
        RECT  64.716 119.952 64.8 119.976 ;
    END
  END bank_e[479]
  PIN bank_e[47]
    DIRECTION OUTPUT ;
    USE SIGNAL ;
    PORT
      LAYER M4 ;
        RECT  64.716 12.336 64.8 12.36 ;
    END
  END bank_e[47]
  PIN bank_e[480]
    DIRECTION OUTPUT ;
    USE SIGNAL ;
    PORT
      LAYER M4 ;
        RECT  64.716 120.192 64.8 120.216 ;
    END
  END bank_e[480]
  PIN bank_e[481]
    DIRECTION OUTPUT ;
    USE SIGNAL ;
    PORT
      LAYER M4 ;
        RECT  64.716 120.432 64.8 120.456 ;
    END
  END bank_e[481]
  PIN bank_e[482]
    DIRECTION OUTPUT ;
    USE SIGNAL ;
    PORT
      LAYER M4 ;
        RECT  64.716 120.72 64.8 120.744 ;
    END
  END bank_e[482]
  PIN bank_e[483]
    DIRECTION OUTPUT ;
    USE SIGNAL ;
    PORT
      LAYER M4 ;
        RECT  64.716 120.96 64.8 120.984 ;
    END
  END bank_e[483]
  PIN bank_e[484]
    DIRECTION OUTPUT ;
    USE SIGNAL ;
    PORT
      LAYER M4 ;
        RECT  64.716 121.2 64.8 121.224 ;
    END
  END bank_e[484]
  PIN bank_e[485]
    DIRECTION OUTPUT ;
    USE SIGNAL ;
    PORT
      LAYER M4 ;
        RECT  64.716 121.44 64.8 121.464 ;
    END
  END bank_e[485]
  PIN bank_e[486]
    DIRECTION OUTPUT ;
    USE SIGNAL ;
    PORT
      LAYER M4 ;
        RECT  64.716 121.68 64.8 121.704 ;
    END
  END bank_e[486]
  PIN bank_e[487]
    DIRECTION OUTPUT ;
    USE SIGNAL ;
    PORT
      LAYER M4 ;
        RECT  64.716 121.968 64.8 121.992 ;
    END
  END bank_e[487]
  PIN bank_e[488]
    DIRECTION OUTPUT ;
    USE SIGNAL ;
    PORT
      LAYER M4 ;
        RECT  64.716 122.208 64.8 122.232 ;
    END
  END bank_e[488]
  PIN bank_e[489]
    DIRECTION OUTPUT ;
    USE SIGNAL ;
    PORT
      LAYER M4 ;
        RECT  64.716 122.448 64.8 122.472 ;
    END
  END bank_e[489]
  PIN bank_e[48]
    DIRECTION OUTPUT ;
    USE SIGNAL ;
    PORT
      LAYER M4 ;
        RECT  64.716 12.624 64.8 12.648 ;
    END
  END bank_e[48]
  PIN bank_e[490]
    DIRECTION OUTPUT ;
    USE SIGNAL ;
    PORT
      LAYER M4 ;
        RECT  64.716 122.688 64.8 122.712 ;
    END
  END bank_e[490]
  PIN bank_e[491]
    DIRECTION OUTPUT ;
    USE SIGNAL ;
    PORT
      LAYER M4 ;
        RECT  64.716 122.928 64.8 122.952 ;
    END
  END bank_e[491]
  PIN bank_e[492]
    DIRECTION OUTPUT ;
    USE SIGNAL ;
    PORT
      LAYER M4 ;
        RECT  64.716 123.216 64.8 123.24 ;
    END
  END bank_e[492]
  PIN bank_e[493]
    DIRECTION OUTPUT ;
    USE SIGNAL ;
    PORT
      LAYER M4 ;
        RECT  64.716 123.456 64.8 123.48 ;
    END
  END bank_e[493]
  PIN bank_e[494]
    DIRECTION OUTPUT ;
    USE SIGNAL ;
    PORT
      LAYER M4 ;
        RECT  64.716 123.696 64.8 123.72 ;
    END
  END bank_e[494]
  PIN bank_e[495]
    DIRECTION OUTPUT ;
    USE SIGNAL ;
    PORT
      LAYER M4 ;
        RECT  64.716 123.936 64.8 123.96 ;
    END
  END bank_e[495]
  PIN bank_e[496]
    DIRECTION OUTPUT ;
    USE SIGNAL ;
    PORT
      LAYER M4 ;
        RECT  64.716 124.176 64.8 124.2 ;
    END
  END bank_e[496]
  PIN bank_e[497]
    DIRECTION OUTPUT ;
    USE SIGNAL ;
    PORT
      LAYER M4 ;
        RECT  64.716 124.464 64.8 124.488 ;
    END
  END bank_e[497]
  PIN bank_e[498]
    DIRECTION OUTPUT ;
    USE SIGNAL ;
    PORT
      LAYER M4 ;
        RECT  64.716 124.704 64.8 124.728 ;
    END
  END bank_e[498]
  PIN bank_e[499]
    DIRECTION OUTPUT ;
    USE SIGNAL ;
    PORT
      LAYER M4 ;
        RECT  64.716 124.944 64.8 124.968 ;
    END
  END bank_e[499]
  PIN bank_e[49]
    DIRECTION OUTPUT ;
    USE SIGNAL ;
    PORT
      LAYER M4 ;
        RECT  64.716 12.864 64.8 12.888 ;
    END
  END bank_e[49]
  PIN bank_e[4]
    DIRECTION OUTPUT ;
    USE SIGNAL ;
    PORT
      LAYER M4 ;
        RECT  64.716 1.632 64.8 1.656 ;
    END
  END bank_e[4]
  PIN bank_e[500]
    DIRECTION OUTPUT ;
    USE SIGNAL ;
    PORT
      LAYER M4 ;
        RECT  64.716 125.184 64.8 125.208 ;
    END
  END bank_e[500]
  PIN bank_e[501]
    DIRECTION OUTPUT ;
    USE SIGNAL ;
    PORT
      LAYER M4 ;
        RECT  64.716 125.424 64.8 125.448 ;
    END
  END bank_e[501]
  PIN bank_e[502]
    DIRECTION OUTPUT ;
    USE SIGNAL ;
    PORT
      LAYER M4 ;
        RECT  64.716 125.664 64.8 125.688 ;
    END
  END bank_e[502]
  PIN bank_e[503]
    DIRECTION OUTPUT ;
    USE SIGNAL ;
    PORT
      LAYER M4 ;
        RECT  64.716 125.952 64.8 125.976 ;
    END
  END bank_e[503]
  PIN bank_e[504]
    DIRECTION OUTPUT ;
    USE SIGNAL ;
    PORT
      LAYER M4 ;
        RECT  64.716 126.192 64.8 126.216 ;
    END
  END bank_e[504]
  PIN bank_e[505]
    DIRECTION OUTPUT ;
    USE SIGNAL ;
    PORT
      LAYER M4 ;
        RECT  64.716 126.432 64.8 126.456 ;
    END
  END bank_e[505]
  PIN bank_e[506]
    DIRECTION OUTPUT ;
    USE SIGNAL ;
    PORT
      LAYER M4 ;
        RECT  64.716 126.672 64.8 126.696 ;
    END
  END bank_e[506]
  PIN bank_e[507]
    DIRECTION OUTPUT ;
    USE SIGNAL ;
    PORT
      LAYER M4 ;
        RECT  64.716 126.912 64.8 126.936 ;
    END
  END bank_e[507]
  PIN bank_e[508]
    DIRECTION OUTPUT ;
    USE SIGNAL ;
    PORT
      LAYER M4 ;
        RECT  64.716 127.2 64.8 127.224 ;
    END
  END bank_e[508]
  PIN bank_e[509]
    DIRECTION OUTPUT ;
    USE SIGNAL ;
    PORT
      LAYER M4 ;
        RECT  64.716 127.44 64.8 127.464 ;
    END
  END bank_e[509]
  PIN bank_e[50]
    DIRECTION OUTPUT ;
    USE SIGNAL ;
    PORT
      LAYER M4 ;
        RECT  64.716 13.104 64.8 13.128 ;
    END
  END bank_e[50]
  PIN bank_e[510]
    DIRECTION OUTPUT ;
    USE SIGNAL ;
    PORT
      LAYER M4 ;
        RECT  64.716 127.68 64.8 127.704 ;
    END
  END bank_e[510]
  PIN bank_e[511]
    DIRECTION OUTPUT ;
    USE SIGNAL ;
    PORT
      LAYER M4 ;
        RECT  64.716 127.92 64.8 127.944 ;
    END
  END bank_e[511]
  PIN bank_e[512]
    DIRECTION OUTPUT ;
    USE SIGNAL ;
    PORT
      LAYER M4 ;
        RECT  64.716 128.16 64.8 128.184 ;
    END
  END bank_e[512]
  PIN bank_e[513]
    DIRECTION OUTPUT ;
    USE SIGNAL ;
    PORT
      LAYER M4 ;
        RECT  64.716 128.448 64.8 128.472 ;
    END
  END bank_e[513]
  PIN bank_e[514]
    DIRECTION OUTPUT ;
    USE SIGNAL ;
    PORT
      LAYER M4 ;
        RECT  64.716 128.688 64.8 128.712 ;
    END
  END bank_e[514]
  PIN bank_e[515]
    DIRECTION OUTPUT ;
    USE SIGNAL ;
    PORT
      LAYER M4 ;
        RECT  64.716 128.928 64.8 128.952 ;
    END
  END bank_e[515]
  PIN bank_e[51]
    DIRECTION OUTPUT ;
    USE SIGNAL ;
    PORT
      LAYER M4 ;
        RECT  64.716 13.344 64.8 13.368 ;
    END
  END bank_e[51]
  PIN bank_e[52]
    DIRECTION OUTPUT ;
    USE SIGNAL ;
    PORT
      LAYER M4 ;
        RECT  64.716 13.584 64.8 13.608 ;
    END
  END bank_e[52]
  PIN bank_e[53]
    DIRECTION OUTPUT ;
    USE SIGNAL ;
    PORT
      LAYER M4 ;
        RECT  64.716 13.872 64.8 13.896 ;
    END
  END bank_e[53]
  PIN bank_e[54]
    DIRECTION OUTPUT ;
    USE SIGNAL ;
    PORT
      LAYER M4 ;
        RECT  64.716 14.112 64.8 14.136 ;
    END
  END bank_e[54]
  PIN bank_e[55]
    DIRECTION OUTPUT ;
    USE SIGNAL ;
    PORT
      LAYER M4 ;
        RECT  64.716 14.352 64.8 14.376 ;
    END
  END bank_e[55]
  PIN bank_e[56]
    DIRECTION OUTPUT ;
    USE SIGNAL ;
    PORT
      LAYER M4 ;
        RECT  64.716 14.592 64.8 14.616 ;
    END
  END bank_e[56]
  PIN bank_e[57]
    DIRECTION OUTPUT ;
    USE SIGNAL ;
    PORT
      LAYER M4 ;
        RECT  64.716 14.832 64.8 14.856 ;
    END
  END bank_e[57]
  PIN bank_e[58]
    DIRECTION OUTPUT ;
    USE SIGNAL ;
    PORT
      LAYER M4 ;
        RECT  64.716 15.12 64.8 15.144 ;
    END
  END bank_e[58]
  PIN bank_e[59]
    DIRECTION OUTPUT ;
    USE SIGNAL ;
    PORT
      LAYER M4 ;
        RECT  64.716 15.36 64.8 15.384 ;
    END
  END bank_e[59]
  PIN bank_e[5]
    DIRECTION OUTPUT ;
    USE SIGNAL ;
    PORT
      LAYER M4 ;
        RECT  64.716 1.92 64.8 1.944 ;
    END
  END bank_e[5]
  PIN bank_e[60]
    DIRECTION OUTPUT ;
    USE SIGNAL ;
    PORT
      LAYER M4 ;
        RECT  64.716 15.6 64.8 15.624 ;
    END
  END bank_e[60]
  PIN bank_e[61]
    DIRECTION OUTPUT ;
    USE SIGNAL ;
    PORT
      LAYER M4 ;
        RECT  64.716 15.84 64.8 15.864 ;
    END
  END bank_e[61]
  PIN bank_e[62]
    DIRECTION OUTPUT ;
    USE SIGNAL ;
    PORT
      LAYER M4 ;
        RECT  64.716 16.08 64.8 16.104 ;
    END
  END bank_e[62]
  PIN bank_e[63]
    DIRECTION OUTPUT ;
    USE SIGNAL ;
    PORT
      LAYER M4 ;
        RECT  64.716 16.368 64.8 16.392 ;
    END
  END bank_e[63]
  PIN bank_e[64]
    DIRECTION OUTPUT ;
    USE SIGNAL ;
    PORT
      LAYER M4 ;
        RECT  64.716 16.608 64.8 16.632 ;
    END
  END bank_e[64]
  PIN bank_e[65]
    DIRECTION OUTPUT ;
    USE SIGNAL ;
    PORT
      LAYER M4 ;
        RECT  64.716 16.848 64.8 16.872 ;
    END
  END bank_e[65]
  PIN bank_e[66]
    DIRECTION OUTPUT ;
    USE SIGNAL ;
    PORT
      LAYER M4 ;
        RECT  64.716 17.088 64.8 17.112 ;
    END
  END bank_e[66]
  PIN bank_e[67]
    DIRECTION OUTPUT ;
    USE SIGNAL ;
    PORT
      LAYER M4 ;
        RECT  64.716 17.328 64.8 17.352 ;
    END
  END bank_e[67]
  PIN bank_e[68]
    DIRECTION OUTPUT ;
    USE SIGNAL ;
    PORT
      LAYER M4 ;
        RECT  64.716 17.568 64.8 17.592 ;
    END
  END bank_e[68]
  PIN bank_e[69]
    DIRECTION OUTPUT ;
    USE SIGNAL ;
    PORT
      LAYER M4 ;
        RECT  64.716 17.856 64.8 17.88 ;
    END
  END bank_e[69]
  PIN bank_e[6]
    DIRECTION OUTPUT ;
    USE SIGNAL ;
    PORT
      LAYER M4 ;
        RECT  64.716 2.16 64.8 2.184 ;
    END
  END bank_e[6]
  PIN bank_e[70]
    DIRECTION OUTPUT ;
    USE SIGNAL ;
    PORT
      LAYER M4 ;
        RECT  64.716 18.096 64.8 18.12 ;
    END
  END bank_e[70]
  PIN bank_e[71]
    DIRECTION OUTPUT ;
    USE SIGNAL ;
    PORT
      LAYER M4 ;
        RECT  64.716 18.336 64.8 18.36 ;
    END
  END bank_e[71]
  PIN bank_e[72]
    DIRECTION OUTPUT ;
    USE SIGNAL ;
    PORT
      LAYER M4 ;
        RECT  64.716 18.576 64.8 18.6 ;
    END
  END bank_e[72]
  PIN bank_e[73]
    DIRECTION OUTPUT ;
    USE SIGNAL ;
    PORT
      LAYER M4 ;
        RECT  64.716 18.816 64.8 18.84 ;
    END
  END bank_e[73]
  PIN bank_e[74]
    DIRECTION OUTPUT ;
    USE SIGNAL ;
    PORT
      LAYER M4 ;
        RECT  64.716 19.104 64.8 19.128 ;
    END
  END bank_e[74]
  PIN bank_e[75]
    DIRECTION OUTPUT ;
    USE SIGNAL ;
    PORT
      LAYER M4 ;
        RECT  64.716 19.344 64.8 19.368 ;
    END
  END bank_e[75]
  PIN bank_e[76]
    DIRECTION OUTPUT ;
    USE SIGNAL ;
    PORT
      LAYER M4 ;
        RECT  64.716 19.584 64.8 19.608 ;
    END
  END bank_e[76]
  PIN bank_e[77]
    DIRECTION OUTPUT ;
    USE SIGNAL ;
    PORT
      LAYER M4 ;
        RECT  64.716 19.824 64.8 19.848 ;
    END
  END bank_e[77]
  PIN bank_e[78]
    DIRECTION OUTPUT ;
    USE SIGNAL ;
    PORT
      LAYER M4 ;
        RECT  64.716 20.064 64.8 20.088 ;
    END
  END bank_e[78]
  PIN bank_e[79]
    DIRECTION OUTPUT ;
    USE SIGNAL ;
    PORT
      LAYER M4 ;
        RECT  64.716 20.352 64.8 20.376 ;
    END
  END bank_e[79]
  PIN bank_e[7]
    DIRECTION OUTPUT ;
    USE SIGNAL ;
    PORT
      LAYER M4 ;
        RECT  64.716 2.4 64.8 2.424 ;
    END
  END bank_e[7]
  PIN bank_e[80]
    DIRECTION OUTPUT ;
    USE SIGNAL ;
    PORT
      LAYER M4 ;
        RECT  64.716 20.592 64.8 20.616 ;
    END
  END bank_e[80]
  PIN bank_e[81]
    DIRECTION OUTPUT ;
    USE SIGNAL ;
    PORT
      LAYER M4 ;
        RECT  64.716 20.832 64.8 20.856 ;
    END
  END bank_e[81]
  PIN bank_e[82]
    DIRECTION OUTPUT ;
    USE SIGNAL ;
    PORT
      LAYER M4 ;
        RECT  64.716 21.072 64.8 21.096 ;
    END
  END bank_e[82]
  PIN bank_e[83]
    DIRECTION OUTPUT ;
    USE SIGNAL ;
    PORT
      LAYER M4 ;
        RECT  64.716 21.312 64.8 21.336 ;
    END
  END bank_e[83]
  PIN bank_e[84]
    DIRECTION OUTPUT ;
    USE SIGNAL ;
    PORT
      LAYER M4 ;
        RECT  64.716 21.552 64.8 21.576 ;
    END
  END bank_e[84]
  PIN bank_e[85]
    DIRECTION OUTPUT ;
    USE SIGNAL ;
    PORT
      LAYER M4 ;
        RECT  64.716 21.84 64.8 21.864 ;
    END
  END bank_e[85]
  PIN bank_e[86]
    DIRECTION OUTPUT ;
    USE SIGNAL ;
    PORT
      LAYER M4 ;
        RECT  64.716 22.08 64.8 22.104 ;
    END
  END bank_e[86]
  PIN bank_e[87]
    DIRECTION OUTPUT ;
    USE SIGNAL ;
    PORT
      LAYER M4 ;
        RECT  64.716 22.32 64.8 22.344 ;
    END
  END bank_e[87]
  PIN bank_e[88]
    DIRECTION OUTPUT ;
    USE SIGNAL ;
    PORT
      LAYER M4 ;
        RECT  64.716 22.56 64.8 22.584 ;
    END
  END bank_e[88]
  PIN bank_e[89]
    DIRECTION OUTPUT ;
    USE SIGNAL ;
    PORT
      LAYER M4 ;
        RECT  64.716 22.8 64.8 22.824 ;
    END
  END bank_e[89]
  PIN bank_e[8]
    DIRECTION OUTPUT ;
    USE SIGNAL ;
    PORT
      LAYER M4 ;
        RECT  64.716 2.64 64.8 2.664 ;
    END
  END bank_e[8]
  PIN bank_e[90]
    DIRECTION OUTPUT ;
    USE SIGNAL ;
    PORT
      LAYER M4 ;
        RECT  64.716 23.088 64.8 23.112 ;
    END
  END bank_e[90]
  PIN bank_e[91]
    DIRECTION OUTPUT ;
    USE SIGNAL ;
    PORT
      LAYER M4 ;
        RECT  64.716 23.328 64.8 23.352 ;
    END
  END bank_e[91]
  PIN bank_e[92]
    DIRECTION OUTPUT ;
    USE SIGNAL ;
    PORT
      LAYER M4 ;
        RECT  64.716 23.568 64.8 23.592 ;
    END
  END bank_e[92]
  PIN bank_e[93]
    DIRECTION OUTPUT ;
    USE SIGNAL ;
    PORT
      LAYER M4 ;
        RECT  64.716 23.808 64.8 23.832 ;
    END
  END bank_e[93]
  PIN bank_e[94]
    DIRECTION OUTPUT ;
    USE SIGNAL ;
    PORT
      LAYER M4 ;
        RECT  64.716 24.048 64.8 24.072 ;
    END
  END bank_e[94]
  PIN bank_e[95]
    DIRECTION OUTPUT ;
    USE SIGNAL ;
    PORT
      LAYER M4 ;
        RECT  64.716 24.336 64.8 24.36 ;
    END
  END bank_e[95]
  PIN bank_e[96]
    DIRECTION OUTPUT ;
    USE SIGNAL ;
    PORT
      LAYER M4 ;
        RECT  64.716 24.576 64.8 24.6 ;
    END
  END bank_e[96]
  PIN bank_e[97]
    DIRECTION OUTPUT ;
    USE SIGNAL ;
    PORT
      LAYER M4 ;
        RECT  64.716 24.816 64.8 24.84 ;
    END
  END bank_e[97]
  PIN bank_e[98]
    DIRECTION OUTPUT ;
    USE SIGNAL ;
    PORT
      LAYER M4 ;
        RECT  64.716 25.056 64.8 25.08 ;
    END
  END bank_e[98]
  PIN bank_e[99]
    DIRECTION OUTPUT ;
    USE SIGNAL ;
    PORT
      LAYER M4 ;
        RECT  64.716 25.296 64.8 25.32 ;
    END
  END bank_e[99]
  PIN bank_e[9]
    DIRECTION OUTPUT ;
    USE SIGNAL ;
    PORT
      LAYER M4 ;
        RECT  64.716 2.88 64.8 2.904 ;
    END
  END bank_e[9]
  PIN bank_w[0]
    DIRECTION OUTPUT ;
    USE SIGNAL ;
    PORT
      LAYER M4 ;
        RECT  0 0.672 0.084 0.696 ;
    END
  END bank_w[0]
  PIN bank_w[100]
    DIRECTION OUTPUT ;
    USE SIGNAL ;
    PORT
      LAYER M4 ;
        RECT  0 25.584 0.084 25.608 ;
    END
  END bank_w[100]
  PIN bank_w[101]
    DIRECTION OUTPUT ;
    USE SIGNAL ;
    PORT
      LAYER M4 ;
        RECT  0 25.824 0.084 25.848 ;
    END
  END bank_w[101]
  PIN bank_w[102]
    DIRECTION OUTPUT ;
    USE SIGNAL ;
    PORT
      LAYER M4 ;
        RECT  0 26.064 0.084 26.088 ;
    END
  END bank_w[102]
  PIN bank_w[103]
    DIRECTION OUTPUT ;
    USE SIGNAL ;
    PORT
      LAYER M4 ;
        RECT  0 26.304 0.084 26.328 ;
    END
  END bank_w[103]
  PIN bank_w[104]
    DIRECTION OUTPUT ;
    USE SIGNAL ;
    PORT
      LAYER M4 ;
        RECT  0 26.544 0.084 26.568 ;
    END
  END bank_w[104]
  PIN bank_w[105]
    DIRECTION OUTPUT ;
    USE SIGNAL ;
    PORT
      LAYER M4 ;
        RECT  0 26.784 0.084 26.808 ;
    END
  END bank_w[105]
  PIN bank_w[106]
    DIRECTION OUTPUT ;
    USE SIGNAL ;
    PORT
      LAYER M4 ;
        RECT  0 27.072 0.084 27.096 ;
    END
  END bank_w[106]
  PIN bank_w[107]
    DIRECTION OUTPUT ;
    USE SIGNAL ;
    PORT
      LAYER M4 ;
        RECT  0 27.312 0.084 27.336 ;
    END
  END bank_w[107]
  PIN bank_w[108]
    DIRECTION OUTPUT ;
    USE SIGNAL ;
    PORT
      LAYER M4 ;
        RECT  0 27.552 0.084 27.576 ;
    END
  END bank_w[108]
  PIN bank_w[109]
    DIRECTION OUTPUT ;
    USE SIGNAL ;
    PORT
      LAYER M4 ;
        RECT  0 27.792 0.084 27.816 ;
    END
  END bank_w[109]
  PIN bank_w[10]
    DIRECTION OUTPUT ;
    USE SIGNAL ;
    PORT
      LAYER M4 ;
        RECT  0 3.12 0.084 3.144 ;
    END
  END bank_w[10]
  PIN bank_w[110]
    DIRECTION OUTPUT ;
    USE SIGNAL ;
    PORT
      LAYER M4 ;
        RECT  0 28.032 0.084 28.056 ;
    END
  END bank_w[110]
  PIN bank_w[111]
    DIRECTION OUTPUT ;
    USE SIGNAL ;
    PORT
      LAYER M4 ;
        RECT  0 28.32 0.084 28.344 ;
    END
  END bank_w[111]
  PIN bank_w[112]
    DIRECTION OUTPUT ;
    USE SIGNAL ;
    PORT
      LAYER M4 ;
        RECT  0 28.56 0.084 28.584 ;
    END
  END bank_w[112]
  PIN bank_w[113]
    DIRECTION OUTPUT ;
    USE SIGNAL ;
    PORT
      LAYER M4 ;
        RECT  0 28.8 0.084 28.824 ;
    END
  END bank_w[113]
  PIN bank_w[114]
    DIRECTION OUTPUT ;
    USE SIGNAL ;
    PORT
      LAYER M4 ;
        RECT  0 29.04 0.084 29.064 ;
    END
  END bank_w[114]
  PIN bank_w[115]
    DIRECTION OUTPUT ;
    USE SIGNAL ;
    PORT
      LAYER M4 ;
        RECT  0 29.28 0.084 29.304 ;
    END
  END bank_w[115]
  PIN bank_w[116]
    DIRECTION OUTPUT ;
    USE SIGNAL ;
    PORT
      LAYER M4 ;
        RECT  0 29.568 0.084 29.592 ;
    END
  END bank_w[116]
  PIN bank_w[117]
    DIRECTION OUTPUT ;
    USE SIGNAL ;
    PORT
      LAYER M4 ;
        RECT  0 29.808 0.084 29.832 ;
    END
  END bank_w[117]
  PIN bank_w[118]
    DIRECTION OUTPUT ;
    USE SIGNAL ;
    PORT
      LAYER M4 ;
        RECT  0 30.048 0.084 30.072 ;
    END
  END bank_w[118]
  PIN bank_w[119]
    DIRECTION OUTPUT ;
    USE SIGNAL ;
    PORT
      LAYER M4 ;
        RECT  0 30.288 0.084 30.312 ;
    END
  END bank_w[119]
  PIN bank_w[11]
    DIRECTION OUTPUT ;
    USE SIGNAL ;
    PORT
      LAYER M4 ;
        RECT  0 3.408 0.084 3.432 ;
    END
  END bank_w[11]
  PIN bank_w[120]
    DIRECTION OUTPUT ;
    USE SIGNAL ;
    PORT
      LAYER M4 ;
        RECT  0 30.528 0.084 30.552 ;
    END
  END bank_w[120]
  PIN bank_w[121]
    DIRECTION OUTPUT ;
    USE SIGNAL ;
    PORT
      LAYER M4 ;
        RECT  0 30.768 0.084 30.792 ;
    END
  END bank_w[121]
  PIN bank_w[122]
    DIRECTION OUTPUT ;
    USE SIGNAL ;
    PORT
      LAYER M4 ;
        RECT  0 31.056 0.084 31.08 ;
    END
  END bank_w[122]
  PIN bank_w[123]
    DIRECTION OUTPUT ;
    USE SIGNAL ;
    PORT
      LAYER M4 ;
        RECT  0 31.296 0.084 31.32 ;
    END
  END bank_w[123]
  PIN bank_w[124]
    DIRECTION OUTPUT ;
    USE SIGNAL ;
    PORT
      LAYER M4 ;
        RECT  0 31.536 0.084 31.56 ;
    END
  END bank_w[124]
  PIN bank_w[125]
    DIRECTION OUTPUT ;
    USE SIGNAL ;
    PORT
      LAYER M4 ;
        RECT  0 31.776 0.084 31.8 ;
    END
  END bank_w[125]
  PIN bank_w[126]
    DIRECTION OUTPUT ;
    USE SIGNAL ;
    PORT
      LAYER M4 ;
        RECT  0 32.016 0.084 32.04 ;
    END
  END bank_w[126]
  PIN bank_w[127]
    DIRECTION OUTPUT ;
    USE SIGNAL ;
    PORT
      LAYER M4 ;
        RECT  0 32.304 0.084 32.328 ;
    END
  END bank_w[127]
  PIN bank_w[128]
    DIRECTION OUTPUT ;
    USE SIGNAL ;
    PORT
      LAYER M4 ;
        RECT  0 32.544 0.084 32.568 ;
    END
  END bank_w[128]
  PIN bank_w[129]
    DIRECTION OUTPUT ;
    USE SIGNAL ;
    PORT
      LAYER M4 ;
        RECT  0 32.784 0.084 32.808 ;
    END
  END bank_w[129]
  PIN bank_w[12]
    DIRECTION OUTPUT ;
    USE SIGNAL ;
    PORT
      LAYER M4 ;
        RECT  0 3.648 0.084 3.672 ;
    END
  END bank_w[12]
  PIN bank_w[130]
    DIRECTION OUTPUT ;
    USE SIGNAL ;
    PORT
      LAYER M4 ;
        RECT  0 33.024 0.084 33.048 ;
    END
  END bank_w[130]
  PIN bank_w[131]
    DIRECTION OUTPUT ;
    USE SIGNAL ;
    PORT
      LAYER M4 ;
        RECT  0 33.264 0.084 33.288 ;
    END
  END bank_w[131]
  PIN bank_w[132]
    DIRECTION OUTPUT ;
    USE SIGNAL ;
    PORT
      LAYER M4 ;
        RECT  0 33.552 0.084 33.576 ;
    END
  END bank_w[132]
  PIN bank_w[133]
    DIRECTION OUTPUT ;
    USE SIGNAL ;
    PORT
      LAYER M4 ;
        RECT  0 33.792 0.084 33.816 ;
    END
  END bank_w[133]
  PIN bank_w[134]
    DIRECTION OUTPUT ;
    USE SIGNAL ;
    PORT
      LAYER M4 ;
        RECT  0 34.032 0.084 34.056 ;
    END
  END bank_w[134]
  PIN bank_w[135]
    DIRECTION OUTPUT ;
    USE SIGNAL ;
    PORT
      LAYER M4 ;
        RECT  0 34.272 0.084 34.296 ;
    END
  END bank_w[135]
  PIN bank_w[136]
    DIRECTION OUTPUT ;
    USE SIGNAL ;
    PORT
      LAYER M4 ;
        RECT  0 34.512 0.084 34.536 ;
    END
  END bank_w[136]
  PIN bank_w[137]
    DIRECTION OUTPUT ;
    USE SIGNAL ;
    PORT
      LAYER M4 ;
        RECT  0 34.752 0.084 34.776 ;
    END
  END bank_w[137]
  PIN bank_w[138]
    DIRECTION OUTPUT ;
    USE SIGNAL ;
    PORT
      LAYER M4 ;
        RECT  0 35.04 0.084 35.064 ;
    END
  END bank_w[138]
  PIN bank_w[139]
    DIRECTION OUTPUT ;
    USE SIGNAL ;
    PORT
      LAYER M4 ;
        RECT  0 35.28 0.084 35.304 ;
    END
  END bank_w[139]
  PIN bank_w[13]
    DIRECTION OUTPUT ;
    USE SIGNAL ;
    PORT
      LAYER M4 ;
        RECT  0 3.888 0.084 3.912 ;
    END
  END bank_w[13]
  PIN bank_w[140]
    DIRECTION OUTPUT ;
    USE SIGNAL ;
    PORT
      LAYER M4 ;
        RECT  0 35.52 0.084 35.544 ;
    END
  END bank_w[140]
  PIN bank_w[141]
    DIRECTION OUTPUT ;
    USE SIGNAL ;
    PORT
      LAYER M4 ;
        RECT  0 35.76 0.084 35.784 ;
    END
  END bank_w[141]
  PIN bank_w[142]
    DIRECTION OUTPUT ;
    USE SIGNAL ;
    PORT
      LAYER M4 ;
        RECT  0 36 0.084 36.024 ;
    END
  END bank_w[142]
  PIN bank_w[143]
    DIRECTION OUTPUT ;
    USE SIGNAL ;
    PORT
      LAYER M4 ;
        RECT  0 36.288 0.084 36.312 ;
    END
  END bank_w[143]
  PIN bank_w[144]
    DIRECTION OUTPUT ;
    USE SIGNAL ;
    PORT
      LAYER M4 ;
        RECT  0 36.528 0.084 36.552 ;
    END
  END bank_w[144]
  PIN bank_w[145]
    DIRECTION OUTPUT ;
    USE SIGNAL ;
    PORT
      LAYER M4 ;
        RECT  0 36.768 0.084 36.792 ;
    END
  END bank_w[145]
  PIN bank_w[146]
    DIRECTION OUTPUT ;
    USE SIGNAL ;
    PORT
      LAYER M4 ;
        RECT  0 37.008 0.084 37.032 ;
    END
  END bank_w[146]
  PIN bank_w[147]
    DIRECTION OUTPUT ;
    USE SIGNAL ;
    PORT
      LAYER M4 ;
        RECT  0 37.248 0.084 37.272 ;
    END
  END bank_w[147]
  PIN bank_w[148]
    DIRECTION OUTPUT ;
    USE SIGNAL ;
    PORT
      LAYER M4 ;
        RECT  0 37.536 0.084 37.56 ;
    END
  END bank_w[148]
  PIN bank_w[149]
    DIRECTION OUTPUT ;
    USE SIGNAL ;
    PORT
      LAYER M4 ;
        RECT  0 37.776 0.084 37.8 ;
    END
  END bank_w[149]
  PIN bank_w[14]
    DIRECTION OUTPUT ;
    USE SIGNAL ;
    PORT
      LAYER M4 ;
        RECT  0 4.128 0.084 4.152 ;
    END
  END bank_w[14]
  PIN bank_w[150]
    DIRECTION OUTPUT ;
    USE SIGNAL ;
    PORT
      LAYER M4 ;
        RECT  0 38.016 0.084 38.04 ;
    END
  END bank_w[150]
  PIN bank_w[151]
    DIRECTION OUTPUT ;
    USE SIGNAL ;
    PORT
      LAYER M4 ;
        RECT  0 38.256 0.084 38.28 ;
    END
  END bank_w[151]
  PIN bank_w[152]
    DIRECTION OUTPUT ;
    USE SIGNAL ;
    PORT
      LAYER M4 ;
        RECT  0 38.496 0.084 38.52 ;
    END
  END bank_w[152]
  PIN bank_w[153]
    DIRECTION OUTPUT ;
    USE SIGNAL ;
    PORT
      LAYER M4 ;
        RECT  0 38.784 0.084 38.808 ;
    END
  END bank_w[153]
  PIN bank_w[154]
    DIRECTION OUTPUT ;
    USE SIGNAL ;
    PORT
      LAYER M4 ;
        RECT  0 39.024 0.084 39.048 ;
    END
  END bank_w[154]
  PIN bank_w[155]
    DIRECTION OUTPUT ;
    USE SIGNAL ;
    PORT
      LAYER M4 ;
        RECT  0 39.264 0.084 39.288 ;
    END
  END bank_w[155]
  PIN bank_w[156]
    DIRECTION OUTPUT ;
    USE SIGNAL ;
    PORT
      LAYER M4 ;
        RECT  0 39.504 0.084 39.528 ;
    END
  END bank_w[156]
  PIN bank_w[157]
    DIRECTION OUTPUT ;
    USE SIGNAL ;
    PORT
      LAYER M4 ;
        RECT  0 39.744 0.084 39.768 ;
    END
  END bank_w[157]
  PIN bank_w[158]
    DIRECTION OUTPUT ;
    USE SIGNAL ;
    PORT
      LAYER M4 ;
        RECT  0 39.984 0.084 40.008 ;
    END
  END bank_w[158]
  PIN bank_w[159]
    DIRECTION OUTPUT ;
    USE SIGNAL ;
    PORT
      LAYER M4 ;
        RECT  0 40.272 0.084 40.296 ;
    END
  END bank_w[159]
  PIN bank_w[15]
    DIRECTION OUTPUT ;
    USE SIGNAL ;
    PORT
      LAYER M4 ;
        RECT  0 4.368 0.084 4.392 ;
    END
  END bank_w[15]
  PIN bank_w[160]
    DIRECTION OUTPUT ;
    USE SIGNAL ;
    PORT
      LAYER M4 ;
        RECT  0 40.512 0.084 40.536 ;
    END
  END bank_w[160]
  PIN bank_w[161]
    DIRECTION OUTPUT ;
    USE SIGNAL ;
    PORT
      LAYER M4 ;
        RECT  0 40.752 0.084 40.776 ;
    END
  END bank_w[161]
  PIN bank_w[162]
    DIRECTION OUTPUT ;
    USE SIGNAL ;
    PORT
      LAYER M4 ;
        RECT  0 40.992 0.084 41.016 ;
    END
  END bank_w[162]
  PIN bank_w[163]
    DIRECTION OUTPUT ;
    USE SIGNAL ;
    PORT
      LAYER M4 ;
        RECT  0 41.232 0.084 41.256 ;
    END
  END bank_w[163]
  PIN bank_w[164]
    DIRECTION OUTPUT ;
    USE SIGNAL ;
    PORT
      LAYER M4 ;
        RECT  0 41.52 0.084 41.544 ;
    END
  END bank_w[164]
  PIN bank_w[165]
    DIRECTION OUTPUT ;
    USE SIGNAL ;
    PORT
      LAYER M4 ;
        RECT  0 41.76 0.084 41.784 ;
    END
  END bank_w[165]
  PIN bank_w[166]
    DIRECTION OUTPUT ;
    USE SIGNAL ;
    PORT
      LAYER M4 ;
        RECT  0 42 0.084 42.024 ;
    END
  END bank_w[166]
  PIN bank_w[167]
    DIRECTION OUTPUT ;
    USE SIGNAL ;
    PORT
      LAYER M4 ;
        RECT  0 42.24 0.084 42.264 ;
    END
  END bank_w[167]
  PIN bank_w[168]
    DIRECTION OUTPUT ;
    USE SIGNAL ;
    PORT
      LAYER M4 ;
        RECT  0 42.48 0.084 42.504 ;
    END
  END bank_w[168]
  PIN bank_w[169]
    DIRECTION OUTPUT ;
    USE SIGNAL ;
    PORT
      LAYER M4 ;
        RECT  0 42.768 0.084 42.792 ;
    END
  END bank_w[169]
  PIN bank_w[16]
    DIRECTION OUTPUT ;
    USE SIGNAL ;
    PORT
      LAYER M4 ;
        RECT  0 4.656 0.084 4.68 ;
    END
  END bank_w[16]
  PIN bank_w[170]
    DIRECTION OUTPUT ;
    USE SIGNAL ;
    PORT
      LAYER M4 ;
        RECT  0 43.008 0.084 43.032 ;
    END
  END bank_w[170]
  PIN bank_w[171]
    DIRECTION OUTPUT ;
    USE SIGNAL ;
    PORT
      LAYER M4 ;
        RECT  0 43.248 0.084 43.272 ;
    END
  END bank_w[171]
  PIN bank_w[172]
    DIRECTION OUTPUT ;
    USE SIGNAL ;
    PORT
      LAYER M4 ;
        RECT  0 43.488 0.084 43.512 ;
    END
  END bank_w[172]
  PIN bank_w[173]
    DIRECTION OUTPUT ;
    USE SIGNAL ;
    PORT
      LAYER M4 ;
        RECT  0 43.728 0.084 43.752 ;
    END
  END bank_w[173]
  PIN bank_w[174]
    DIRECTION OUTPUT ;
    USE SIGNAL ;
    PORT
      LAYER M4 ;
        RECT  0 43.968 0.084 43.992 ;
    END
  END bank_w[174]
  PIN bank_w[175]
    DIRECTION OUTPUT ;
    USE SIGNAL ;
    PORT
      LAYER M4 ;
        RECT  0 44.256 0.084 44.28 ;
    END
  END bank_w[175]
  PIN bank_w[176]
    DIRECTION OUTPUT ;
    USE SIGNAL ;
    PORT
      LAYER M4 ;
        RECT  0 44.496 0.084 44.52 ;
    END
  END bank_w[176]
  PIN bank_w[177]
    DIRECTION OUTPUT ;
    USE SIGNAL ;
    PORT
      LAYER M4 ;
        RECT  0 44.736 0.084 44.76 ;
    END
  END bank_w[177]
  PIN bank_w[178]
    DIRECTION OUTPUT ;
    USE SIGNAL ;
    PORT
      LAYER M4 ;
        RECT  0 44.976 0.084 45 ;
    END
  END bank_w[178]
  PIN bank_w[179]
    DIRECTION OUTPUT ;
    USE SIGNAL ;
    PORT
      LAYER M4 ;
        RECT  0 45.216 0.084 45.24 ;
    END
  END bank_w[179]
  PIN bank_w[17]
    DIRECTION OUTPUT ;
    USE SIGNAL ;
    PORT
      LAYER M4 ;
        RECT  0 4.896 0.084 4.92 ;
    END
  END bank_w[17]
  PIN bank_w[180]
    DIRECTION OUTPUT ;
    USE SIGNAL ;
    PORT
      LAYER M4 ;
        RECT  0 45.504 0.084 45.528 ;
    END
  END bank_w[180]
  PIN bank_w[181]
    DIRECTION OUTPUT ;
    USE SIGNAL ;
    PORT
      LAYER M4 ;
        RECT  0 45.744 0.084 45.768 ;
    END
  END bank_w[181]
  PIN bank_w[182]
    DIRECTION OUTPUT ;
    USE SIGNAL ;
    PORT
      LAYER M4 ;
        RECT  0 45.984 0.084 46.008 ;
    END
  END bank_w[182]
  PIN bank_w[183]
    DIRECTION OUTPUT ;
    USE SIGNAL ;
    PORT
      LAYER M4 ;
        RECT  0 46.224 0.084 46.248 ;
    END
  END bank_w[183]
  PIN bank_w[184]
    DIRECTION OUTPUT ;
    USE SIGNAL ;
    PORT
      LAYER M4 ;
        RECT  0 46.464 0.084 46.488 ;
    END
  END bank_w[184]
  PIN bank_w[185]
    DIRECTION OUTPUT ;
    USE SIGNAL ;
    PORT
      LAYER M4 ;
        RECT  0 46.752 0.084 46.776 ;
    END
  END bank_w[185]
  PIN bank_w[186]
    DIRECTION OUTPUT ;
    USE SIGNAL ;
    PORT
      LAYER M4 ;
        RECT  0 46.992 0.084 47.016 ;
    END
  END bank_w[186]
  PIN bank_w[187]
    DIRECTION OUTPUT ;
    USE SIGNAL ;
    PORT
      LAYER M4 ;
        RECT  0 47.232 0.084 47.256 ;
    END
  END bank_w[187]
  PIN bank_w[188]
    DIRECTION OUTPUT ;
    USE SIGNAL ;
    PORT
      LAYER M4 ;
        RECT  0 47.472 0.084 47.496 ;
    END
  END bank_w[188]
  PIN bank_w[189]
    DIRECTION OUTPUT ;
    USE SIGNAL ;
    PORT
      LAYER M4 ;
        RECT  0 47.712 0.084 47.736 ;
    END
  END bank_w[189]
  PIN bank_w[18]
    DIRECTION OUTPUT ;
    USE SIGNAL ;
    PORT
      LAYER M4 ;
        RECT  0 5.136 0.084 5.16 ;
    END
  END bank_w[18]
  PIN bank_w[190]
    DIRECTION OUTPUT ;
    USE SIGNAL ;
    PORT
      LAYER M4 ;
        RECT  0 48 0.084 48.024 ;
    END
  END bank_w[190]
  PIN bank_w[191]
    DIRECTION OUTPUT ;
    USE SIGNAL ;
    PORT
      LAYER M4 ;
        RECT  0 48.24 0.084 48.264 ;
    END
  END bank_w[191]
  PIN bank_w[192]
    DIRECTION OUTPUT ;
    USE SIGNAL ;
    PORT
      LAYER M4 ;
        RECT  0 48.48 0.084 48.504 ;
    END
  END bank_w[192]
  PIN bank_w[193]
    DIRECTION OUTPUT ;
    USE SIGNAL ;
    PORT
      LAYER M4 ;
        RECT  0 48.72 0.084 48.744 ;
    END
  END bank_w[193]
  PIN bank_w[194]
    DIRECTION OUTPUT ;
    USE SIGNAL ;
    PORT
      LAYER M4 ;
        RECT  0 48.96 0.084 48.984 ;
    END
  END bank_w[194]
  PIN bank_w[195]
    DIRECTION OUTPUT ;
    USE SIGNAL ;
    PORT
      LAYER M4 ;
        RECT  0 49.2 0.084 49.224 ;
    END
  END bank_w[195]
  PIN bank_w[196]
    DIRECTION OUTPUT ;
    USE SIGNAL ;
    PORT
      LAYER M4 ;
        RECT  0 49.488 0.084 49.512 ;
    END
  END bank_w[196]
  PIN bank_w[197]
    DIRECTION OUTPUT ;
    USE SIGNAL ;
    PORT
      LAYER M4 ;
        RECT  0 49.728 0.084 49.752 ;
    END
  END bank_w[197]
  PIN bank_w[198]
    DIRECTION OUTPUT ;
    USE SIGNAL ;
    PORT
      LAYER M4 ;
        RECT  0 49.968 0.084 49.992 ;
    END
  END bank_w[198]
  PIN bank_w[199]
    DIRECTION OUTPUT ;
    USE SIGNAL ;
    PORT
      LAYER M4 ;
        RECT  0 50.208 0.084 50.232 ;
    END
  END bank_w[199]
  PIN bank_w[19]
    DIRECTION OUTPUT ;
    USE SIGNAL ;
    PORT
      LAYER M4 ;
        RECT  0 5.376 0.084 5.4 ;
    END
  END bank_w[19]
  PIN bank_w[1]
    DIRECTION OUTPUT ;
    USE SIGNAL ;
    PORT
      LAYER M4 ;
        RECT  0 0.912 0.084 0.936 ;
    END
  END bank_w[1]
  PIN bank_w[200]
    DIRECTION OUTPUT ;
    USE SIGNAL ;
    PORT
      LAYER M4 ;
        RECT  0 50.448 0.084 50.472 ;
    END
  END bank_w[200]
  PIN bank_w[201]
    DIRECTION OUTPUT ;
    USE SIGNAL ;
    PORT
      LAYER M4 ;
        RECT  0 50.736 0.084 50.76 ;
    END
  END bank_w[201]
  PIN bank_w[202]
    DIRECTION OUTPUT ;
    USE SIGNAL ;
    PORT
      LAYER M4 ;
        RECT  0 50.976 0.084 51 ;
    END
  END bank_w[202]
  PIN bank_w[203]
    DIRECTION OUTPUT ;
    USE SIGNAL ;
    PORT
      LAYER M4 ;
        RECT  0 51.216 0.084 51.24 ;
    END
  END bank_w[203]
  PIN bank_w[204]
    DIRECTION OUTPUT ;
    USE SIGNAL ;
    PORT
      LAYER M4 ;
        RECT  0 51.456 0.084 51.48 ;
    END
  END bank_w[204]
  PIN bank_w[205]
    DIRECTION OUTPUT ;
    USE SIGNAL ;
    PORT
      LAYER M4 ;
        RECT  0 51.696 0.084 51.72 ;
    END
  END bank_w[205]
  PIN bank_w[206]
    DIRECTION OUTPUT ;
    USE SIGNAL ;
    PORT
      LAYER M4 ;
        RECT  0 51.984 0.084 52.008 ;
    END
  END bank_w[206]
  PIN bank_w[207]
    DIRECTION OUTPUT ;
    USE SIGNAL ;
    PORT
      LAYER M4 ;
        RECT  0 52.224 0.084 52.248 ;
    END
  END bank_w[207]
  PIN bank_w[208]
    DIRECTION OUTPUT ;
    USE SIGNAL ;
    PORT
      LAYER M4 ;
        RECT  0 52.464 0.084 52.488 ;
    END
  END bank_w[208]
  PIN bank_w[209]
    DIRECTION OUTPUT ;
    USE SIGNAL ;
    PORT
      LAYER M4 ;
        RECT  0 52.704 0.084 52.728 ;
    END
  END bank_w[209]
  PIN bank_w[20]
    DIRECTION OUTPUT ;
    USE SIGNAL ;
    PORT
      LAYER M4 ;
        RECT  0 5.616 0.084 5.64 ;
    END
  END bank_w[20]
  PIN bank_w[210]
    DIRECTION OUTPUT ;
    USE SIGNAL ;
    PORT
      LAYER M4 ;
        RECT  0 52.944 0.084 52.968 ;
    END
  END bank_w[210]
  PIN bank_w[211]
    DIRECTION OUTPUT ;
    USE SIGNAL ;
    PORT
      LAYER M4 ;
        RECT  0 53.184 0.084 53.208 ;
    END
  END bank_w[211]
  PIN bank_w[212]
    DIRECTION OUTPUT ;
    USE SIGNAL ;
    PORT
      LAYER M4 ;
        RECT  0 53.472 0.084 53.496 ;
    END
  END bank_w[212]
  PIN bank_w[213]
    DIRECTION OUTPUT ;
    USE SIGNAL ;
    PORT
      LAYER M4 ;
        RECT  0 53.712 0.084 53.736 ;
    END
  END bank_w[213]
  PIN bank_w[214]
    DIRECTION OUTPUT ;
    USE SIGNAL ;
    PORT
      LAYER M4 ;
        RECT  0 53.952 0.084 53.976 ;
    END
  END bank_w[214]
  PIN bank_w[215]
    DIRECTION OUTPUT ;
    USE SIGNAL ;
    PORT
      LAYER M4 ;
        RECT  0 54.192 0.084 54.216 ;
    END
  END bank_w[215]
  PIN bank_w[216]
    DIRECTION OUTPUT ;
    USE SIGNAL ;
    PORT
      LAYER M4 ;
        RECT  0 54.432 0.084 54.456 ;
    END
  END bank_w[216]
  PIN bank_w[217]
    DIRECTION OUTPUT ;
    USE SIGNAL ;
    PORT
      LAYER M4 ;
        RECT  0 54.72 0.084 54.744 ;
    END
  END bank_w[217]
  PIN bank_w[218]
    DIRECTION OUTPUT ;
    USE SIGNAL ;
    PORT
      LAYER M4 ;
        RECT  0 54.96 0.084 54.984 ;
    END
  END bank_w[218]
  PIN bank_w[219]
    DIRECTION OUTPUT ;
    USE SIGNAL ;
    PORT
      LAYER M4 ;
        RECT  0 55.2 0.084 55.224 ;
    END
  END bank_w[219]
  PIN bank_w[21]
    DIRECTION OUTPUT ;
    USE SIGNAL ;
    PORT
      LAYER M4 ;
        RECT  0 5.904 0.084 5.928 ;
    END
  END bank_w[21]
  PIN bank_w[220]
    DIRECTION OUTPUT ;
    USE SIGNAL ;
    PORT
      LAYER M4 ;
        RECT  0 55.44 0.084 55.464 ;
    END
  END bank_w[220]
  PIN bank_w[221]
    DIRECTION OUTPUT ;
    USE SIGNAL ;
    PORT
      LAYER M4 ;
        RECT  0 55.68 0.084 55.704 ;
    END
  END bank_w[221]
  PIN bank_w[222]
    DIRECTION OUTPUT ;
    USE SIGNAL ;
    PORT
      LAYER M4 ;
        RECT  0 55.968 0.084 55.992 ;
    END
  END bank_w[222]
  PIN bank_w[223]
    DIRECTION OUTPUT ;
    USE SIGNAL ;
    PORT
      LAYER M4 ;
        RECT  0 56.208 0.084 56.232 ;
    END
  END bank_w[223]
  PIN bank_w[224]
    DIRECTION OUTPUT ;
    USE SIGNAL ;
    PORT
      LAYER M4 ;
        RECT  0 56.448 0.084 56.472 ;
    END
  END bank_w[224]
  PIN bank_w[225]
    DIRECTION OUTPUT ;
    USE SIGNAL ;
    PORT
      LAYER M4 ;
        RECT  0 56.688 0.084 56.712 ;
    END
  END bank_w[225]
  PIN bank_w[226]
    DIRECTION OUTPUT ;
    USE SIGNAL ;
    PORT
      LAYER M4 ;
        RECT  0 56.928 0.084 56.952 ;
    END
  END bank_w[226]
  PIN bank_w[227]
    DIRECTION OUTPUT ;
    USE SIGNAL ;
    PORT
      LAYER M4 ;
        RECT  0 57.168 0.084 57.192 ;
    END
  END bank_w[227]
  PIN bank_w[228]
    DIRECTION OUTPUT ;
    USE SIGNAL ;
    PORT
      LAYER M4 ;
        RECT  0 57.456 0.084 57.48 ;
    END
  END bank_w[228]
  PIN bank_w[229]
    DIRECTION OUTPUT ;
    USE SIGNAL ;
    PORT
      LAYER M4 ;
        RECT  0 57.696 0.084 57.72 ;
    END
  END bank_w[229]
  PIN bank_w[22]
    DIRECTION OUTPUT ;
    USE SIGNAL ;
    PORT
      LAYER M4 ;
        RECT  0 6.144 0.084 6.168 ;
    END
  END bank_w[22]
  PIN bank_w[230]
    DIRECTION OUTPUT ;
    USE SIGNAL ;
    PORT
      LAYER M4 ;
        RECT  0 57.936 0.084 57.96 ;
    END
  END bank_w[230]
  PIN bank_w[231]
    DIRECTION OUTPUT ;
    USE SIGNAL ;
    PORT
      LAYER M4 ;
        RECT  0 58.176 0.084 58.2 ;
    END
  END bank_w[231]
  PIN bank_w[232]
    DIRECTION OUTPUT ;
    USE SIGNAL ;
    PORT
      LAYER M4 ;
        RECT  0 58.416 0.084 58.44 ;
    END
  END bank_w[232]
  PIN bank_w[233]
    DIRECTION OUTPUT ;
    USE SIGNAL ;
    PORT
      LAYER M4 ;
        RECT  0 58.704 0.084 58.728 ;
    END
  END bank_w[233]
  PIN bank_w[234]
    DIRECTION OUTPUT ;
    USE SIGNAL ;
    PORT
      LAYER M4 ;
        RECT  0 58.944 0.084 58.968 ;
    END
  END bank_w[234]
  PIN bank_w[235]
    DIRECTION OUTPUT ;
    USE SIGNAL ;
    PORT
      LAYER M4 ;
        RECT  0 59.184 0.084 59.208 ;
    END
  END bank_w[235]
  PIN bank_w[236]
    DIRECTION OUTPUT ;
    USE SIGNAL ;
    PORT
      LAYER M4 ;
        RECT  0 59.424 0.084 59.448 ;
    END
  END bank_w[236]
  PIN bank_w[237]
    DIRECTION OUTPUT ;
    USE SIGNAL ;
    PORT
      LAYER M4 ;
        RECT  0 59.664 0.084 59.688 ;
    END
  END bank_w[237]
  PIN bank_w[238]
    DIRECTION OUTPUT ;
    USE SIGNAL ;
    PORT
      LAYER M4 ;
        RECT  0 59.952 0.084 59.976 ;
    END
  END bank_w[238]
  PIN bank_w[239]
    DIRECTION OUTPUT ;
    USE SIGNAL ;
    PORT
      LAYER M4 ;
        RECT  0 60.192 0.084 60.216 ;
    END
  END bank_w[239]
  PIN bank_w[23]
    DIRECTION OUTPUT ;
    USE SIGNAL ;
    PORT
      LAYER M4 ;
        RECT  0 6.384 0.084 6.408 ;
    END
  END bank_w[23]
  PIN bank_w[240]
    DIRECTION OUTPUT ;
    USE SIGNAL ;
    PORT
      LAYER M4 ;
        RECT  0 60.432 0.084 60.456 ;
    END
  END bank_w[240]
  PIN bank_w[241]
    DIRECTION OUTPUT ;
    USE SIGNAL ;
    PORT
      LAYER M4 ;
        RECT  0 60.672 0.084 60.696 ;
    END
  END bank_w[241]
  PIN bank_w[242]
    DIRECTION OUTPUT ;
    USE SIGNAL ;
    PORT
      LAYER M4 ;
        RECT  0 60.912 0.084 60.936 ;
    END
  END bank_w[242]
  PIN bank_w[243]
    DIRECTION OUTPUT ;
    USE SIGNAL ;
    PORT
      LAYER M4 ;
        RECT  0 61.2 0.084 61.224 ;
    END
  END bank_w[243]
  PIN bank_w[244]
    DIRECTION OUTPUT ;
    USE SIGNAL ;
    PORT
      LAYER M4 ;
        RECT  0 61.44 0.084 61.464 ;
    END
  END bank_w[244]
  PIN bank_w[245]
    DIRECTION OUTPUT ;
    USE SIGNAL ;
    PORT
      LAYER M4 ;
        RECT  0 61.68 0.084 61.704 ;
    END
  END bank_w[245]
  PIN bank_w[246]
    DIRECTION OUTPUT ;
    USE SIGNAL ;
    PORT
      LAYER M4 ;
        RECT  0 61.92 0.084 61.944 ;
    END
  END bank_w[246]
  PIN bank_w[247]
    DIRECTION OUTPUT ;
    USE SIGNAL ;
    PORT
      LAYER M4 ;
        RECT  0 62.16 0.084 62.184 ;
    END
  END bank_w[247]
  PIN bank_w[248]
    DIRECTION OUTPUT ;
    USE SIGNAL ;
    PORT
      LAYER M4 ;
        RECT  0 62.4 0.084 62.424 ;
    END
  END bank_w[248]
  PIN bank_w[249]
    DIRECTION OUTPUT ;
    USE SIGNAL ;
    PORT
      LAYER M4 ;
        RECT  0 62.688 0.084 62.712 ;
    END
  END bank_w[249]
  PIN bank_w[24]
    DIRECTION OUTPUT ;
    USE SIGNAL ;
    PORT
      LAYER M4 ;
        RECT  0 6.624 0.084 6.648 ;
    END
  END bank_w[24]
  PIN bank_w[250]
    DIRECTION OUTPUT ;
    USE SIGNAL ;
    PORT
      LAYER M4 ;
        RECT  0 62.928 0.084 62.952 ;
    END
  END bank_w[250]
  PIN bank_w[251]
    DIRECTION OUTPUT ;
    USE SIGNAL ;
    PORT
      LAYER M4 ;
        RECT  0 63.168 0.084 63.192 ;
    END
  END bank_w[251]
  PIN bank_w[252]
    DIRECTION OUTPUT ;
    USE SIGNAL ;
    PORT
      LAYER M4 ;
        RECT  0 63.408 0.084 63.432 ;
    END
  END bank_w[252]
  PIN bank_w[253]
    DIRECTION OUTPUT ;
    USE SIGNAL ;
    PORT
      LAYER M4 ;
        RECT  0 63.648 0.084 63.672 ;
    END
  END bank_w[253]
  PIN bank_w[254]
    DIRECTION OUTPUT ;
    USE SIGNAL ;
    PORT
      LAYER M4 ;
        RECT  0 63.936 0.084 63.96 ;
    END
  END bank_w[254]
  PIN bank_w[255]
    DIRECTION OUTPUT ;
    USE SIGNAL ;
    PORT
      LAYER M4 ;
        RECT  0 64.176 0.084 64.2 ;
    END
  END bank_w[255]
  PIN bank_w[256]
    DIRECTION OUTPUT ;
    USE SIGNAL ;
    PORT
      LAYER M4 ;
        RECT  0 64.416 0.084 64.44 ;
    END
  END bank_w[256]
  PIN bank_w[257]
    DIRECTION OUTPUT ;
    USE SIGNAL ;
    PORT
      LAYER M4 ;
        RECT  0 64.656 0.084 64.68 ;
    END
  END bank_w[257]
  PIN bank_w[258]
    DIRECTION OUTPUT ;
    USE SIGNAL ;
    PORT
      LAYER M4 ;
        RECT  0 64.896 0.084 64.92 ;
    END
  END bank_w[258]
  PIN bank_w[259]
    DIRECTION OUTPUT ;
    USE SIGNAL ;
    PORT
      LAYER M4 ;
        RECT  0 65.184 0.084 65.208 ;
    END
  END bank_w[259]
  PIN bank_w[25]
    DIRECTION OUTPUT ;
    USE SIGNAL ;
    PORT
      LAYER M4 ;
        RECT  0 6.864 0.084 6.888 ;
    END
  END bank_w[25]
  PIN bank_w[260]
    DIRECTION OUTPUT ;
    USE SIGNAL ;
    PORT
      LAYER M4 ;
        RECT  0 65.424 0.084 65.448 ;
    END
  END bank_w[260]
  PIN bank_w[261]
    DIRECTION OUTPUT ;
    USE SIGNAL ;
    PORT
      LAYER M4 ;
        RECT  0 65.664 0.084 65.688 ;
    END
  END bank_w[261]
  PIN bank_w[262]
    DIRECTION OUTPUT ;
    USE SIGNAL ;
    PORT
      LAYER M4 ;
        RECT  0 65.904 0.084 65.928 ;
    END
  END bank_w[262]
  PIN bank_w[263]
    DIRECTION OUTPUT ;
    USE SIGNAL ;
    PORT
      LAYER M4 ;
        RECT  0 66.144 0.084 66.168 ;
    END
  END bank_w[263]
  PIN bank_w[264]
    DIRECTION OUTPUT ;
    USE SIGNAL ;
    PORT
      LAYER M4 ;
        RECT  0 66.384 0.084 66.408 ;
    END
  END bank_w[264]
  PIN bank_w[265]
    DIRECTION OUTPUT ;
    USE SIGNAL ;
    PORT
      LAYER M4 ;
        RECT  0 66.672 0.084 66.696 ;
    END
  END bank_w[265]
  PIN bank_w[266]
    DIRECTION OUTPUT ;
    USE SIGNAL ;
    PORT
      LAYER M4 ;
        RECT  0 66.912 0.084 66.936 ;
    END
  END bank_w[266]
  PIN bank_w[267]
    DIRECTION OUTPUT ;
    USE SIGNAL ;
    PORT
      LAYER M4 ;
        RECT  0 67.152 0.084 67.176 ;
    END
  END bank_w[267]
  PIN bank_w[268]
    DIRECTION OUTPUT ;
    USE SIGNAL ;
    PORT
      LAYER M4 ;
        RECT  0 67.392 0.084 67.416 ;
    END
  END bank_w[268]
  PIN bank_w[269]
    DIRECTION OUTPUT ;
    USE SIGNAL ;
    PORT
      LAYER M4 ;
        RECT  0 67.632 0.084 67.656 ;
    END
  END bank_w[269]
  PIN bank_w[26]
    DIRECTION OUTPUT ;
    USE SIGNAL ;
    PORT
      LAYER M4 ;
        RECT  0 7.152 0.084 7.176 ;
    END
  END bank_w[26]
  PIN bank_w[270]
    DIRECTION OUTPUT ;
    USE SIGNAL ;
    PORT
      LAYER M4 ;
        RECT  0 67.92 0.084 67.944 ;
    END
  END bank_w[270]
  PIN bank_w[271]
    DIRECTION OUTPUT ;
    USE SIGNAL ;
    PORT
      LAYER M4 ;
        RECT  0 68.16 0.084 68.184 ;
    END
  END bank_w[271]
  PIN bank_w[272]
    DIRECTION OUTPUT ;
    USE SIGNAL ;
    PORT
      LAYER M4 ;
        RECT  0 68.4 0.084 68.424 ;
    END
  END bank_w[272]
  PIN bank_w[273]
    DIRECTION OUTPUT ;
    USE SIGNAL ;
    PORT
      LAYER M4 ;
        RECT  0 68.64 0.084 68.664 ;
    END
  END bank_w[273]
  PIN bank_w[274]
    DIRECTION OUTPUT ;
    USE SIGNAL ;
    PORT
      LAYER M4 ;
        RECT  0 68.88 0.084 68.904 ;
    END
  END bank_w[274]
  PIN bank_w[275]
    DIRECTION OUTPUT ;
    USE SIGNAL ;
    PORT
      LAYER M4 ;
        RECT  0 69.168 0.084 69.192 ;
    END
  END bank_w[275]
  PIN bank_w[276]
    DIRECTION OUTPUT ;
    USE SIGNAL ;
    PORT
      LAYER M4 ;
        RECT  0 69.408 0.084 69.432 ;
    END
  END bank_w[276]
  PIN bank_w[277]
    DIRECTION OUTPUT ;
    USE SIGNAL ;
    PORT
      LAYER M4 ;
        RECT  0 69.648 0.084 69.672 ;
    END
  END bank_w[277]
  PIN bank_w[278]
    DIRECTION OUTPUT ;
    USE SIGNAL ;
    PORT
      LAYER M4 ;
        RECT  0 69.888 0.084 69.912 ;
    END
  END bank_w[278]
  PIN bank_w[279]
    DIRECTION OUTPUT ;
    USE SIGNAL ;
    PORT
      LAYER M4 ;
        RECT  0 70.128 0.084 70.152 ;
    END
  END bank_w[279]
  PIN bank_w[27]
    DIRECTION OUTPUT ;
    USE SIGNAL ;
    PORT
      LAYER M4 ;
        RECT  0 7.392 0.084 7.416 ;
    END
  END bank_w[27]
  PIN bank_w[280]
    DIRECTION OUTPUT ;
    USE SIGNAL ;
    PORT
      LAYER M4 ;
        RECT  0 70.416 0.084 70.44 ;
    END
  END bank_w[280]
  PIN bank_w[281]
    DIRECTION OUTPUT ;
    USE SIGNAL ;
    PORT
      LAYER M4 ;
        RECT  0 70.656 0.084 70.68 ;
    END
  END bank_w[281]
  PIN bank_w[282]
    DIRECTION OUTPUT ;
    USE SIGNAL ;
    PORT
      LAYER M4 ;
        RECT  0 70.896 0.084 70.92 ;
    END
  END bank_w[282]
  PIN bank_w[283]
    DIRECTION OUTPUT ;
    USE SIGNAL ;
    PORT
      LAYER M4 ;
        RECT  0 71.136 0.084 71.16 ;
    END
  END bank_w[283]
  PIN bank_w[284]
    DIRECTION OUTPUT ;
    USE SIGNAL ;
    PORT
      LAYER M4 ;
        RECT  0 71.376 0.084 71.4 ;
    END
  END bank_w[284]
  PIN bank_w[285]
    DIRECTION OUTPUT ;
    USE SIGNAL ;
    PORT
      LAYER M4 ;
        RECT  0 71.616 0.084 71.64 ;
    END
  END bank_w[285]
  PIN bank_w[286]
    DIRECTION OUTPUT ;
    USE SIGNAL ;
    PORT
      LAYER M4 ;
        RECT  0 71.904 0.084 71.928 ;
    END
  END bank_w[286]
  PIN bank_w[287]
    DIRECTION OUTPUT ;
    USE SIGNAL ;
    PORT
      LAYER M4 ;
        RECT  0 72.144 0.084 72.168 ;
    END
  END bank_w[287]
  PIN bank_w[288]
    DIRECTION OUTPUT ;
    USE SIGNAL ;
    PORT
      LAYER M4 ;
        RECT  0 72.384 0.084 72.408 ;
    END
  END bank_w[288]
  PIN bank_w[289]
    DIRECTION OUTPUT ;
    USE SIGNAL ;
    PORT
      LAYER M4 ;
        RECT  0 72.624 0.084 72.648 ;
    END
  END bank_w[289]
  PIN bank_w[28]
    DIRECTION OUTPUT ;
    USE SIGNAL ;
    PORT
      LAYER M4 ;
        RECT  0 7.632 0.084 7.656 ;
    END
  END bank_w[28]
  PIN bank_w[290]
    DIRECTION OUTPUT ;
    USE SIGNAL ;
    PORT
      LAYER M4 ;
        RECT  0 72.864 0.084 72.888 ;
    END
  END bank_w[290]
  PIN bank_w[291]
    DIRECTION OUTPUT ;
    USE SIGNAL ;
    PORT
      LAYER M4 ;
        RECT  0 73.152 0.084 73.176 ;
    END
  END bank_w[291]
  PIN bank_w[292]
    DIRECTION OUTPUT ;
    USE SIGNAL ;
    PORT
      LAYER M4 ;
        RECT  0 73.392 0.084 73.416 ;
    END
  END bank_w[292]
  PIN bank_w[293]
    DIRECTION OUTPUT ;
    USE SIGNAL ;
    PORT
      LAYER M4 ;
        RECT  0 73.632 0.084 73.656 ;
    END
  END bank_w[293]
  PIN bank_w[294]
    DIRECTION OUTPUT ;
    USE SIGNAL ;
    PORT
      LAYER M4 ;
        RECT  0 73.872 0.084 73.896 ;
    END
  END bank_w[294]
  PIN bank_w[295]
    DIRECTION OUTPUT ;
    USE SIGNAL ;
    PORT
      LAYER M4 ;
        RECT  0 74.112 0.084 74.136 ;
    END
  END bank_w[295]
  PIN bank_w[296]
    DIRECTION OUTPUT ;
    USE SIGNAL ;
    PORT
      LAYER M4 ;
        RECT  0 74.4 0.084 74.424 ;
    END
  END bank_w[296]
  PIN bank_w[297]
    DIRECTION OUTPUT ;
    USE SIGNAL ;
    PORT
      LAYER M4 ;
        RECT  0 74.64 0.084 74.664 ;
    END
  END bank_w[297]
  PIN bank_w[298]
    DIRECTION OUTPUT ;
    USE SIGNAL ;
    PORT
      LAYER M4 ;
        RECT  0 74.88 0.084 74.904 ;
    END
  END bank_w[298]
  PIN bank_w[299]
    DIRECTION OUTPUT ;
    USE SIGNAL ;
    PORT
      LAYER M4 ;
        RECT  0 75.12 0.084 75.144 ;
    END
  END bank_w[299]
  PIN bank_w[29]
    DIRECTION OUTPUT ;
    USE SIGNAL ;
    PORT
      LAYER M4 ;
        RECT  0 7.872 0.084 7.896 ;
    END
  END bank_w[29]
  PIN bank_w[2]
    DIRECTION OUTPUT ;
    USE SIGNAL ;
    PORT
      LAYER M4 ;
        RECT  0 1.152 0.084 1.176 ;
    END
  END bank_w[2]
  PIN bank_w[300]
    DIRECTION OUTPUT ;
    USE SIGNAL ;
    PORT
      LAYER M4 ;
        RECT  0 75.36 0.084 75.384 ;
    END
  END bank_w[300]
  PIN bank_w[301]
    DIRECTION OUTPUT ;
    USE SIGNAL ;
    PORT
      LAYER M4 ;
        RECT  0 75.6 0.084 75.624 ;
    END
  END bank_w[301]
  PIN bank_w[302]
    DIRECTION OUTPUT ;
    USE SIGNAL ;
    PORT
      LAYER M4 ;
        RECT  0 75.888 0.084 75.912 ;
    END
  END bank_w[302]
  PIN bank_w[303]
    DIRECTION OUTPUT ;
    USE SIGNAL ;
    PORT
      LAYER M4 ;
        RECT  0 76.128 0.084 76.152 ;
    END
  END bank_w[303]
  PIN bank_w[304]
    DIRECTION OUTPUT ;
    USE SIGNAL ;
    PORT
      LAYER M4 ;
        RECT  0 76.368 0.084 76.392 ;
    END
  END bank_w[304]
  PIN bank_w[305]
    DIRECTION OUTPUT ;
    USE SIGNAL ;
    PORT
      LAYER M4 ;
        RECT  0 76.608 0.084 76.632 ;
    END
  END bank_w[305]
  PIN bank_w[306]
    DIRECTION OUTPUT ;
    USE SIGNAL ;
    PORT
      LAYER M4 ;
        RECT  0 76.848 0.084 76.872 ;
    END
  END bank_w[306]
  PIN bank_w[307]
    DIRECTION OUTPUT ;
    USE SIGNAL ;
    PORT
      LAYER M4 ;
        RECT  0 77.136 0.084 77.16 ;
    END
  END bank_w[307]
  PIN bank_w[308]
    DIRECTION OUTPUT ;
    USE SIGNAL ;
    PORT
      LAYER M4 ;
        RECT  0 77.376 0.084 77.4 ;
    END
  END bank_w[308]
  PIN bank_w[309]
    DIRECTION OUTPUT ;
    USE SIGNAL ;
    PORT
      LAYER M4 ;
        RECT  0 77.616 0.084 77.64 ;
    END
  END bank_w[309]
  PIN bank_w[30]
    DIRECTION OUTPUT ;
    USE SIGNAL ;
    PORT
      LAYER M4 ;
        RECT  0 8.112 0.084 8.136 ;
    END
  END bank_w[30]
  PIN bank_w[310]
    DIRECTION OUTPUT ;
    USE SIGNAL ;
    PORT
      LAYER M4 ;
        RECT  0 77.856 0.084 77.88 ;
    END
  END bank_w[310]
  PIN bank_w[311]
    DIRECTION OUTPUT ;
    USE SIGNAL ;
    PORT
      LAYER M4 ;
        RECT  0 78.096 0.084 78.12 ;
    END
  END bank_w[311]
  PIN bank_w[312]
    DIRECTION OUTPUT ;
    USE SIGNAL ;
    PORT
      LAYER M4 ;
        RECT  0 78.384 0.084 78.408 ;
    END
  END bank_w[312]
  PIN bank_w[313]
    DIRECTION OUTPUT ;
    USE SIGNAL ;
    PORT
      LAYER M4 ;
        RECT  0 78.624 0.084 78.648 ;
    END
  END bank_w[313]
  PIN bank_w[314]
    DIRECTION OUTPUT ;
    USE SIGNAL ;
    PORT
      LAYER M4 ;
        RECT  0 78.864 0.084 78.888 ;
    END
  END bank_w[314]
  PIN bank_w[315]
    DIRECTION OUTPUT ;
    USE SIGNAL ;
    PORT
      LAYER M4 ;
        RECT  0 79.104 0.084 79.128 ;
    END
  END bank_w[315]
  PIN bank_w[316]
    DIRECTION OUTPUT ;
    USE SIGNAL ;
    PORT
      LAYER M4 ;
        RECT  0 79.344 0.084 79.368 ;
    END
  END bank_w[316]
  PIN bank_w[317]
    DIRECTION OUTPUT ;
    USE SIGNAL ;
    PORT
      LAYER M4 ;
        RECT  0 79.632 0.084 79.656 ;
    END
  END bank_w[317]
  PIN bank_w[318]
    DIRECTION OUTPUT ;
    USE SIGNAL ;
    PORT
      LAYER M4 ;
        RECT  0 79.872 0.084 79.896 ;
    END
  END bank_w[318]
  PIN bank_w[319]
    DIRECTION OUTPUT ;
    USE SIGNAL ;
    PORT
      LAYER M4 ;
        RECT  0 80.112 0.084 80.136 ;
    END
  END bank_w[319]
  PIN bank_w[31]
    DIRECTION OUTPUT ;
    USE SIGNAL ;
    PORT
      LAYER M4 ;
        RECT  0 8.352 0.084 8.376 ;
    END
  END bank_w[31]
  PIN bank_w[320]
    DIRECTION OUTPUT ;
    USE SIGNAL ;
    PORT
      LAYER M4 ;
        RECT  0 80.352 0.084 80.376 ;
    END
  END bank_w[320]
  PIN bank_w[321]
    DIRECTION OUTPUT ;
    USE SIGNAL ;
    PORT
      LAYER M4 ;
        RECT  0 80.592 0.084 80.616 ;
    END
  END bank_w[321]
  PIN bank_w[322]
    DIRECTION OUTPUT ;
    USE SIGNAL ;
    PORT
      LAYER M4 ;
        RECT  0 80.832 0.084 80.856 ;
    END
  END bank_w[322]
  PIN bank_w[323]
    DIRECTION OUTPUT ;
    USE SIGNAL ;
    PORT
      LAYER M4 ;
        RECT  0 81.12 0.084 81.144 ;
    END
  END bank_w[323]
  PIN bank_w[324]
    DIRECTION OUTPUT ;
    USE SIGNAL ;
    PORT
      LAYER M4 ;
        RECT  0 81.36 0.084 81.384 ;
    END
  END bank_w[324]
  PIN bank_w[325]
    DIRECTION OUTPUT ;
    USE SIGNAL ;
    PORT
      LAYER M4 ;
        RECT  0 81.6 0.084 81.624 ;
    END
  END bank_w[325]
  PIN bank_w[326]
    DIRECTION OUTPUT ;
    USE SIGNAL ;
    PORT
      LAYER M4 ;
        RECT  0 81.84 0.084 81.864 ;
    END
  END bank_w[326]
  PIN bank_w[327]
    DIRECTION OUTPUT ;
    USE SIGNAL ;
    PORT
      LAYER M4 ;
        RECT  0 82.08 0.084 82.104 ;
    END
  END bank_w[327]
  PIN bank_w[328]
    DIRECTION OUTPUT ;
    USE SIGNAL ;
    PORT
      LAYER M4 ;
        RECT  0 82.368 0.084 82.392 ;
    END
  END bank_w[328]
  PIN bank_w[329]
    DIRECTION OUTPUT ;
    USE SIGNAL ;
    PORT
      LAYER M4 ;
        RECT  0 82.608 0.084 82.632 ;
    END
  END bank_w[329]
  PIN bank_w[32]
    DIRECTION OUTPUT ;
    USE SIGNAL ;
    PORT
      LAYER M4 ;
        RECT  0 8.64 0.084 8.664 ;
    END
  END bank_w[32]
  PIN bank_w[330]
    DIRECTION OUTPUT ;
    USE SIGNAL ;
    PORT
      LAYER M4 ;
        RECT  0 82.848 0.084 82.872 ;
    END
  END bank_w[330]
  PIN bank_w[331]
    DIRECTION OUTPUT ;
    USE SIGNAL ;
    PORT
      LAYER M4 ;
        RECT  0 83.088 0.084 83.112 ;
    END
  END bank_w[331]
  PIN bank_w[332]
    DIRECTION OUTPUT ;
    USE SIGNAL ;
    PORT
      LAYER M4 ;
        RECT  0 83.328 0.084 83.352 ;
    END
  END bank_w[332]
  PIN bank_w[333]
    DIRECTION OUTPUT ;
    USE SIGNAL ;
    PORT
      LAYER M4 ;
        RECT  0 83.616 0.084 83.64 ;
    END
  END bank_w[333]
  PIN bank_w[334]
    DIRECTION OUTPUT ;
    USE SIGNAL ;
    PORT
      LAYER M4 ;
        RECT  0 83.856 0.084 83.88 ;
    END
  END bank_w[334]
  PIN bank_w[335]
    DIRECTION OUTPUT ;
    USE SIGNAL ;
    PORT
      LAYER M4 ;
        RECT  0 84.096 0.084 84.12 ;
    END
  END bank_w[335]
  PIN bank_w[336]
    DIRECTION OUTPUT ;
    USE SIGNAL ;
    PORT
      LAYER M4 ;
        RECT  0 84.336 0.084 84.36 ;
    END
  END bank_w[336]
  PIN bank_w[337]
    DIRECTION OUTPUT ;
    USE SIGNAL ;
    PORT
      LAYER M4 ;
        RECT  0 84.576 0.084 84.6 ;
    END
  END bank_w[337]
  PIN bank_w[338]
    DIRECTION OUTPUT ;
    USE SIGNAL ;
    PORT
      LAYER M4 ;
        RECT  0 84.816 0.084 84.84 ;
    END
  END bank_w[338]
  PIN bank_w[339]
    DIRECTION OUTPUT ;
    USE SIGNAL ;
    PORT
      LAYER M4 ;
        RECT  0 85.104 0.084 85.128 ;
    END
  END bank_w[339]
  PIN bank_w[33]
    DIRECTION OUTPUT ;
    USE SIGNAL ;
    PORT
      LAYER M4 ;
        RECT  0 8.88 0.084 8.904 ;
    END
  END bank_w[33]
  PIN bank_w[340]
    DIRECTION OUTPUT ;
    USE SIGNAL ;
    PORT
      LAYER M4 ;
        RECT  0 85.344 0.084 85.368 ;
    END
  END bank_w[340]
  PIN bank_w[341]
    DIRECTION OUTPUT ;
    USE SIGNAL ;
    PORT
      LAYER M4 ;
        RECT  0 85.584 0.084 85.608 ;
    END
  END bank_w[341]
  PIN bank_w[342]
    DIRECTION OUTPUT ;
    USE SIGNAL ;
    PORT
      LAYER M4 ;
        RECT  0 85.824 0.084 85.848 ;
    END
  END bank_w[342]
  PIN bank_w[343]
    DIRECTION OUTPUT ;
    USE SIGNAL ;
    PORT
      LAYER M4 ;
        RECT  0 86.064 0.084 86.088 ;
    END
  END bank_w[343]
  PIN bank_w[344]
    DIRECTION OUTPUT ;
    USE SIGNAL ;
    PORT
      LAYER M4 ;
        RECT  0 86.352 0.084 86.376 ;
    END
  END bank_w[344]
  PIN bank_w[345]
    DIRECTION OUTPUT ;
    USE SIGNAL ;
    PORT
      LAYER M4 ;
        RECT  0 86.592 0.084 86.616 ;
    END
  END bank_w[345]
  PIN bank_w[346]
    DIRECTION OUTPUT ;
    USE SIGNAL ;
    PORT
      LAYER M4 ;
        RECT  0 86.832 0.084 86.856 ;
    END
  END bank_w[346]
  PIN bank_w[347]
    DIRECTION OUTPUT ;
    USE SIGNAL ;
    PORT
      LAYER M4 ;
        RECT  0 87.072 0.084 87.096 ;
    END
  END bank_w[347]
  PIN bank_w[348]
    DIRECTION OUTPUT ;
    USE SIGNAL ;
    PORT
      LAYER M4 ;
        RECT  0 87.312 0.084 87.336 ;
    END
  END bank_w[348]
  PIN bank_w[349]
    DIRECTION OUTPUT ;
    USE SIGNAL ;
    PORT
      LAYER M4 ;
        RECT  0 87.6 0.084 87.624 ;
    END
  END bank_w[349]
  PIN bank_w[34]
    DIRECTION OUTPUT ;
    USE SIGNAL ;
    PORT
      LAYER M4 ;
        RECT  0 9.12 0.084 9.144 ;
    END
  END bank_w[34]
  PIN bank_w[350]
    DIRECTION OUTPUT ;
    USE SIGNAL ;
    PORT
      LAYER M4 ;
        RECT  0 87.84 0.084 87.864 ;
    END
  END bank_w[350]
  PIN bank_w[351]
    DIRECTION OUTPUT ;
    USE SIGNAL ;
    PORT
      LAYER M4 ;
        RECT  0 88.08 0.084 88.104 ;
    END
  END bank_w[351]
  PIN bank_w[352]
    DIRECTION OUTPUT ;
    USE SIGNAL ;
    PORT
      LAYER M4 ;
        RECT  0 88.32 0.084 88.344 ;
    END
  END bank_w[352]
  PIN bank_w[353]
    DIRECTION OUTPUT ;
    USE SIGNAL ;
    PORT
      LAYER M4 ;
        RECT  0 88.56 0.084 88.584 ;
    END
  END bank_w[353]
  PIN bank_w[354]
    DIRECTION OUTPUT ;
    USE SIGNAL ;
    PORT
      LAYER M4 ;
        RECT  0 88.8 0.084 88.824 ;
    END
  END bank_w[354]
  PIN bank_w[355]
    DIRECTION OUTPUT ;
    USE SIGNAL ;
    PORT
      LAYER M4 ;
        RECT  0 89.088 0.084 89.112 ;
    END
  END bank_w[355]
  PIN bank_w[356]
    DIRECTION OUTPUT ;
    USE SIGNAL ;
    PORT
      LAYER M4 ;
        RECT  0 89.328 0.084 89.352 ;
    END
  END bank_w[356]
  PIN bank_w[357]
    DIRECTION OUTPUT ;
    USE SIGNAL ;
    PORT
      LAYER M4 ;
        RECT  0 89.568 0.084 89.592 ;
    END
  END bank_w[357]
  PIN bank_w[358]
    DIRECTION OUTPUT ;
    USE SIGNAL ;
    PORT
      LAYER M4 ;
        RECT  0 89.808 0.084 89.832 ;
    END
  END bank_w[358]
  PIN bank_w[359]
    DIRECTION OUTPUT ;
    USE SIGNAL ;
    PORT
      LAYER M4 ;
        RECT  0 90.048 0.084 90.072 ;
    END
  END bank_w[359]
  PIN bank_w[35]
    DIRECTION OUTPUT ;
    USE SIGNAL ;
    PORT
      LAYER M4 ;
        RECT  0 9.36 0.084 9.384 ;
    END
  END bank_w[35]
  PIN bank_w[360]
    DIRECTION OUTPUT ;
    USE SIGNAL ;
    PORT
      LAYER M4 ;
        RECT  0 90.336 0.084 90.36 ;
    END
  END bank_w[360]
  PIN bank_w[361]
    DIRECTION OUTPUT ;
    USE SIGNAL ;
    PORT
      LAYER M4 ;
        RECT  0 90.576 0.084 90.6 ;
    END
  END bank_w[361]
  PIN bank_w[362]
    DIRECTION OUTPUT ;
    USE SIGNAL ;
    PORT
      LAYER M4 ;
        RECT  0 90.816 0.084 90.84 ;
    END
  END bank_w[362]
  PIN bank_w[363]
    DIRECTION OUTPUT ;
    USE SIGNAL ;
    PORT
      LAYER M4 ;
        RECT  0 91.056 0.084 91.08 ;
    END
  END bank_w[363]
  PIN bank_w[364]
    DIRECTION OUTPUT ;
    USE SIGNAL ;
    PORT
      LAYER M4 ;
        RECT  0 91.296 0.084 91.32 ;
    END
  END bank_w[364]
  PIN bank_w[365]
    DIRECTION OUTPUT ;
    USE SIGNAL ;
    PORT
      LAYER M4 ;
        RECT  0 91.584 0.084 91.608 ;
    END
  END bank_w[365]
  PIN bank_w[366]
    DIRECTION OUTPUT ;
    USE SIGNAL ;
    PORT
      LAYER M4 ;
        RECT  0 91.824 0.084 91.848 ;
    END
  END bank_w[366]
  PIN bank_w[367]
    DIRECTION OUTPUT ;
    USE SIGNAL ;
    PORT
      LAYER M4 ;
        RECT  0 92.064 0.084 92.088 ;
    END
  END bank_w[367]
  PIN bank_w[368]
    DIRECTION OUTPUT ;
    USE SIGNAL ;
    PORT
      LAYER M4 ;
        RECT  0 92.304 0.084 92.328 ;
    END
  END bank_w[368]
  PIN bank_w[369]
    DIRECTION OUTPUT ;
    USE SIGNAL ;
    PORT
      LAYER M4 ;
        RECT  0 92.544 0.084 92.568 ;
    END
  END bank_w[369]
  PIN bank_w[36]
    DIRECTION OUTPUT ;
    USE SIGNAL ;
    PORT
      LAYER M4 ;
        RECT  0 9.6 0.084 9.624 ;
    END
  END bank_w[36]
  PIN bank_w[370]
    DIRECTION OUTPUT ;
    USE SIGNAL ;
    PORT
      LAYER M4 ;
        RECT  0 92.832 0.084 92.856 ;
    END
  END bank_w[370]
  PIN bank_w[371]
    DIRECTION OUTPUT ;
    USE SIGNAL ;
    PORT
      LAYER M4 ;
        RECT  0 93.072 0.084 93.096 ;
    END
  END bank_w[371]
  PIN bank_w[372]
    DIRECTION OUTPUT ;
    USE SIGNAL ;
    PORT
      LAYER M4 ;
        RECT  0 93.312 0.084 93.336 ;
    END
  END bank_w[372]
  PIN bank_w[373]
    DIRECTION OUTPUT ;
    USE SIGNAL ;
    PORT
      LAYER M4 ;
        RECT  0 93.552 0.084 93.576 ;
    END
  END bank_w[373]
  PIN bank_w[374]
    DIRECTION OUTPUT ;
    USE SIGNAL ;
    PORT
      LAYER M4 ;
        RECT  0 93.792 0.084 93.816 ;
    END
  END bank_w[374]
  PIN bank_w[375]
    DIRECTION OUTPUT ;
    USE SIGNAL ;
    PORT
      LAYER M4 ;
        RECT  0 94.032 0.084 94.056 ;
    END
  END bank_w[375]
  PIN bank_w[376]
    DIRECTION OUTPUT ;
    USE SIGNAL ;
    PORT
      LAYER M4 ;
        RECT  0 94.32 0.084 94.344 ;
    END
  END bank_w[376]
  PIN bank_w[377]
    DIRECTION OUTPUT ;
    USE SIGNAL ;
    PORT
      LAYER M4 ;
        RECT  0 94.56 0.084 94.584 ;
    END
  END bank_w[377]
  PIN bank_w[378]
    DIRECTION OUTPUT ;
    USE SIGNAL ;
    PORT
      LAYER M4 ;
        RECT  0 94.8 0.084 94.824 ;
    END
  END bank_w[378]
  PIN bank_w[379]
    DIRECTION OUTPUT ;
    USE SIGNAL ;
    PORT
      LAYER M4 ;
        RECT  0 95.04 0.084 95.064 ;
    END
  END bank_w[379]
  PIN bank_w[37]
    DIRECTION OUTPUT ;
    USE SIGNAL ;
    PORT
      LAYER M4 ;
        RECT  0 9.888 0.084 9.912 ;
    END
  END bank_w[37]
  PIN bank_w[380]
    DIRECTION OUTPUT ;
    USE SIGNAL ;
    PORT
      LAYER M4 ;
        RECT  0 95.28 0.084 95.304 ;
    END
  END bank_w[380]
  PIN bank_w[381]
    DIRECTION OUTPUT ;
    USE SIGNAL ;
    PORT
      LAYER M4 ;
        RECT  0 95.568 0.084 95.592 ;
    END
  END bank_w[381]
  PIN bank_w[382]
    DIRECTION OUTPUT ;
    USE SIGNAL ;
    PORT
      LAYER M4 ;
        RECT  0 95.808 0.084 95.832 ;
    END
  END bank_w[382]
  PIN bank_w[383]
    DIRECTION OUTPUT ;
    USE SIGNAL ;
    PORT
      LAYER M4 ;
        RECT  0 96.048 0.084 96.072 ;
    END
  END bank_w[383]
  PIN bank_w[384]
    DIRECTION OUTPUT ;
    USE SIGNAL ;
    PORT
      LAYER M4 ;
        RECT  0 96.288 0.084 96.312 ;
    END
  END bank_w[384]
  PIN bank_w[385]
    DIRECTION OUTPUT ;
    USE SIGNAL ;
    PORT
      LAYER M4 ;
        RECT  0 96.528 0.084 96.552 ;
    END
  END bank_w[385]
  PIN bank_w[386]
    DIRECTION OUTPUT ;
    USE SIGNAL ;
    PORT
      LAYER M4 ;
        RECT  0 96.816 0.084 96.84 ;
    END
  END bank_w[386]
  PIN bank_w[387]
    DIRECTION OUTPUT ;
    USE SIGNAL ;
    PORT
      LAYER M4 ;
        RECT  0 97.056 0.084 97.08 ;
    END
  END bank_w[387]
  PIN bank_w[388]
    DIRECTION OUTPUT ;
    USE SIGNAL ;
    PORT
      LAYER M4 ;
        RECT  0 97.296 0.084 97.32 ;
    END
  END bank_w[388]
  PIN bank_w[389]
    DIRECTION OUTPUT ;
    USE SIGNAL ;
    PORT
      LAYER M4 ;
        RECT  0 97.536 0.084 97.56 ;
    END
  END bank_w[389]
  PIN bank_w[38]
    DIRECTION OUTPUT ;
    USE SIGNAL ;
    PORT
      LAYER M4 ;
        RECT  0 10.128 0.084 10.152 ;
    END
  END bank_w[38]
  PIN bank_w[390]
    DIRECTION OUTPUT ;
    USE SIGNAL ;
    PORT
      LAYER M4 ;
        RECT  0 97.776 0.084 97.8 ;
    END
  END bank_w[390]
  PIN bank_w[391]
    DIRECTION OUTPUT ;
    USE SIGNAL ;
    PORT
      LAYER M4 ;
        RECT  0 98.016 0.084 98.04 ;
    END
  END bank_w[391]
  PIN bank_w[392]
    DIRECTION OUTPUT ;
    USE SIGNAL ;
    PORT
      LAYER M4 ;
        RECT  0 98.304 0.084 98.328 ;
    END
  END bank_w[392]
  PIN bank_w[393]
    DIRECTION OUTPUT ;
    USE SIGNAL ;
    PORT
      LAYER M4 ;
        RECT  0 98.544 0.084 98.568 ;
    END
  END bank_w[393]
  PIN bank_w[394]
    DIRECTION OUTPUT ;
    USE SIGNAL ;
    PORT
      LAYER M4 ;
        RECT  0 98.784 0.084 98.808 ;
    END
  END bank_w[394]
  PIN bank_w[395]
    DIRECTION OUTPUT ;
    USE SIGNAL ;
    PORT
      LAYER M4 ;
        RECT  0 99.024 0.084 99.048 ;
    END
  END bank_w[395]
  PIN bank_w[396]
    DIRECTION OUTPUT ;
    USE SIGNAL ;
    PORT
      LAYER M4 ;
        RECT  0 99.264 0.084 99.288 ;
    END
  END bank_w[396]
  PIN bank_w[397]
    DIRECTION OUTPUT ;
    USE SIGNAL ;
    PORT
      LAYER M4 ;
        RECT  0 99.552 0.084 99.576 ;
    END
  END bank_w[397]
  PIN bank_w[398]
    DIRECTION OUTPUT ;
    USE SIGNAL ;
    PORT
      LAYER M4 ;
        RECT  0 99.792 0.084 99.816 ;
    END
  END bank_w[398]
  PIN bank_w[399]
    DIRECTION OUTPUT ;
    USE SIGNAL ;
    PORT
      LAYER M4 ;
        RECT  0 100.032 0.084 100.056 ;
    END
  END bank_w[399]
  PIN bank_w[39]
    DIRECTION OUTPUT ;
    USE SIGNAL ;
    PORT
      LAYER M4 ;
        RECT  0 10.368 0.084 10.392 ;
    END
  END bank_w[39]
  PIN bank_w[3]
    DIRECTION OUTPUT ;
    USE SIGNAL ;
    PORT
      LAYER M4 ;
        RECT  0 1.392 0.084 1.416 ;
    END
  END bank_w[3]
  PIN bank_w[400]
    DIRECTION OUTPUT ;
    USE SIGNAL ;
    PORT
      LAYER M4 ;
        RECT  0 100.272 0.084 100.296 ;
    END
  END bank_w[400]
  PIN bank_w[401]
    DIRECTION OUTPUT ;
    USE SIGNAL ;
    PORT
      LAYER M4 ;
        RECT  0 100.512 0.084 100.536 ;
    END
  END bank_w[401]
  PIN bank_w[402]
    DIRECTION OUTPUT ;
    USE SIGNAL ;
    PORT
      LAYER M4 ;
        RECT  0 100.8 0.084 100.824 ;
    END
  END bank_w[402]
  PIN bank_w[403]
    DIRECTION OUTPUT ;
    USE SIGNAL ;
    PORT
      LAYER M4 ;
        RECT  0 101.04 0.084 101.064 ;
    END
  END bank_w[403]
  PIN bank_w[404]
    DIRECTION OUTPUT ;
    USE SIGNAL ;
    PORT
      LAYER M4 ;
        RECT  0 101.28 0.084 101.304 ;
    END
  END bank_w[404]
  PIN bank_w[405]
    DIRECTION OUTPUT ;
    USE SIGNAL ;
    PORT
      LAYER M4 ;
        RECT  0 101.52 0.084 101.544 ;
    END
  END bank_w[405]
  PIN bank_w[406]
    DIRECTION OUTPUT ;
    USE SIGNAL ;
    PORT
      LAYER M4 ;
        RECT  0 101.76 0.084 101.784 ;
    END
  END bank_w[406]
  PIN bank_w[407]
    DIRECTION OUTPUT ;
    USE SIGNAL ;
    PORT
      LAYER M4 ;
        RECT  0 102.048 0.084 102.072 ;
    END
  END bank_w[407]
  PIN bank_w[408]
    DIRECTION OUTPUT ;
    USE SIGNAL ;
    PORT
      LAYER M4 ;
        RECT  0 102.288 0.084 102.312 ;
    END
  END bank_w[408]
  PIN bank_w[409]
    DIRECTION OUTPUT ;
    USE SIGNAL ;
    PORT
      LAYER M4 ;
        RECT  0 102.528 0.084 102.552 ;
    END
  END bank_w[409]
  PIN bank_w[40]
    DIRECTION OUTPUT ;
    USE SIGNAL ;
    PORT
      LAYER M4 ;
        RECT  0 10.608 0.084 10.632 ;
    END
  END bank_w[40]
  PIN bank_w[410]
    DIRECTION OUTPUT ;
    USE SIGNAL ;
    PORT
      LAYER M4 ;
        RECT  0 102.768 0.084 102.792 ;
    END
  END bank_w[410]
  PIN bank_w[411]
    DIRECTION OUTPUT ;
    USE SIGNAL ;
    PORT
      LAYER M4 ;
        RECT  0 103.008 0.084 103.032 ;
    END
  END bank_w[411]
  PIN bank_w[412]
    DIRECTION OUTPUT ;
    USE SIGNAL ;
    PORT
      LAYER M4 ;
        RECT  0 103.248 0.084 103.272 ;
    END
  END bank_w[412]
  PIN bank_w[413]
    DIRECTION OUTPUT ;
    USE SIGNAL ;
    PORT
      LAYER M4 ;
        RECT  0 103.536 0.084 103.56 ;
    END
  END bank_w[413]
  PIN bank_w[414]
    DIRECTION OUTPUT ;
    USE SIGNAL ;
    PORT
      LAYER M4 ;
        RECT  0 103.776 0.084 103.8 ;
    END
  END bank_w[414]
  PIN bank_w[415]
    DIRECTION OUTPUT ;
    USE SIGNAL ;
    PORT
      LAYER M4 ;
        RECT  0 104.016 0.084 104.04 ;
    END
  END bank_w[415]
  PIN bank_w[416]
    DIRECTION OUTPUT ;
    USE SIGNAL ;
    PORT
      LAYER M4 ;
        RECT  0 104.256 0.084 104.28 ;
    END
  END bank_w[416]
  PIN bank_w[417]
    DIRECTION OUTPUT ;
    USE SIGNAL ;
    PORT
      LAYER M4 ;
        RECT  0 104.496 0.084 104.52 ;
    END
  END bank_w[417]
  PIN bank_w[418]
    DIRECTION OUTPUT ;
    USE SIGNAL ;
    PORT
      LAYER M4 ;
        RECT  0 104.784 0.084 104.808 ;
    END
  END bank_w[418]
  PIN bank_w[419]
    DIRECTION OUTPUT ;
    USE SIGNAL ;
    PORT
      LAYER M4 ;
        RECT  0 105.024 0.084 105.048 ;
    END
  END bank_w[419]
  PIN bank_w[41]
    DIRECTION OUTPUT ;
    USE SIGNAL ;
    PORT
      LAYER M4 ;
        RECT  0 10.848 0.084 10.872 ;
    END
  END bank_w[41]
  PIN bank_w[420]
    DIRECTION OUTPUT ;
    USE SIGNAL ;
    PORT
      LAYER M4 ;
        RECT  0 105.264 0.084 105.288 ;
    END
  END bank_w[420]
  PIN bank_w[421]
    DIRECTION OUTPUT ;
    USE SIGNAL ;
    PORT
      LAYER M4 ;
        RECT  0 105.504 0.084 105.528 ;
    END
  END bank_w[421]
  PIN bank_w[422]
    DIRECTION OUTPUT ;
    USE SIGNAL ;
    PORT
      LAYER M4 ;
        RECT  0 105.744 0.084 105.768 ;
    END
  END bank_w[422]
  PIN bank_w[423]
    DIRECTION OUTPUT ;
    USE SIGNAL ;
    PORT
      LAYER M4 ;
        RECT  0 106.032 0.084 106.056 ;
    END
  END bank_w[423]
  PIN bank_w[424]
    DIRECTION OUTPUT ;
    USE SIGNAL ;
    PORT
      LAYER M4 ;
        RECT  0 106.272 0.084 106.296 ;
    END
  END bank_w[424]
  PIN bank_w[425]
    DIRECTION OUTPUT ;
    USE SIGNAL ;
    PORT
      LAYER M4 ;
        RECT  0 106.512 0.084 106.536 ;
    END
  END bank_w[425]
  PIN bank_w[426]
    DIRECTION OUTPUT ;
    USE SIGNAL ;
    PORT
      LAYER M4 ;
        RECT  0 106.752 0.084 106.776 ;
    END
  END bank_w[426]
  PIN bank_w[427]
    DIRECTION OUTPUT ;
    USE SIGNAL ;
    PORT
      LAYER M4 ;
        RECT  0 106.992 0.084 107.016 ;
    END
  END bank_w[427]
  PIN bank_w[428]
    DIRECTION OUTPUT ;
    USE SIGNAL ;
    PORT
      LAYER M4 ;
        RECT  0 107.232 0.084 107.256 ;
    END
  END bank_w[428]
  PIN bank_w[429]
    DIRECTION OUTPUT ;
    USE SIGNAL ;
    PORT
      LAYER M4 ;
        RECT  0 107.52 0.084 107.544 ;
    END
  END bank_w[429]
  PIN bank_w[42]
    DIRECTION OUTPUT ;
    USE SIGNAL ;
    PORT
      LAYER M4 ;
        RECT  0 11.136 0.084 11.16 ;
    END
  END bank_w[42]
  PIN bank_w[430]
    DIRECTION OUTPUT ;
    USE SIGNAL ;
    PORT
      LAYER M4 ;
        RECT  0 107.76 0.084 107.784 ;
    END
  END bank_w[430]
  PIN bank_w[431]
    DIRECTION OUTPUT ;
    USE SIGNAL ;
    PORT
      LAYER M4 ;
        RECT  0 108 0.084 108.024 ;
    END
  END bank_w[431]
  PIN bank_w[432]
    DIRECTION OUTPUT ;
    USE SIGNAL ;
    PORT
      LAYER M4 ;
        RECT  0 108.24 0.084 108.264 ;
    END
  END bank_w[432]
  PIN bank_w[433]
    DIRECTION OUTPUT ;
    USE SIGNAL ;
    PORT
      LAYER M4 ;
        RECT  0 108.48 0.084 108.504 ;
    END
  END bank_w[433]
  PIN bank_w[434]
    DIRECTION OUTPUT ;
    USE SIGNAL ;
    PORT
      LAYER M4 ;
        RECT  0 108.768 0.084 108.792 ;
    END
  END bank_w[434]
  PIN bank_w[435]
    DIRECTION OUTPUT ;
    USE SIGNAL ;
    PORT
      LAYER M4 ;
        RECT  0 109.008 0.084 109.032 ;
    END
  END bank_w[435]
  PIN bank_w[436]
    DIRECTION OUTPUT ;
    USE SIGNAL ;
    PORT
      LAYER M4 ;
        RECT  0 109.248 0.084 109.272 ;
    END
  END bank_w[436]
  PIN bank_w[437]
    DIRECTION OUTPUT ;
    USE SIGNAL ;
    PORT
      LAYER M4 ;
        RECT  0 109.488 0.084 109.512 ;
    END
  END bank_w[437]
  PIN bank_w[438]
    DIRECTION OUTPUT ;
    USE SIGNAL ;
    PORT
      LAYER M4 ;
        RECT  0 109.728 0.084 109.752 ;
    END
  END bank_w[438]
  PIN bank_w[439]
    DIRECTION OUTPUT ;
    USE SIGNAL ;
    PORT
      LAYER M4 ;
        RECT  0 110.016 0.084 110.04 ;
    END
  END bank_w[439]
  PIN bank_w[43]
    DIRECTION OUTPUT ;
    USE SIGNAL ;
    PORT
      LAYER M4 ;
        RECT  0 11.376 0.084 11.4 ;
    END
  END bank_w[43]
  PIN bank_w[440]
    DIRECTION OUTPUT ;
    USE SIGNAL ;
    PORT
      LAYER M4 ;
        RECT  0 110.256 0.084 110.28 ;
    END
  END bank_w[440]
  PIN bank_w[441]
    DIRECTION OUTPUT ;
    USE SIGNAL ;
    PORT
      LAYER M4 ;
        RECT  0 110.496 0.084 110.52 ;
    END
  END bank_w[441]
  PIN bank_w[442]
    DIRECTION OUTPUT ;
    USE SIGNAL ;
    PORT
      LAYER M4 ;
        RECT  0 110.736 0.084 110.76 ;
    END
  END bank_w[442]
  PIN bank_w[443]
    DIRECTION OUTPUT ;
    USE SIGNAL ;
    PORT
      LAYER M4 ;
        RECT  0 110.976 0.084 111 ;
    END
  END bank_w[443]
  PIN bank_w[444]
    DIRECTION OUTPUT ;
    USE SIGNAL ;
    PORT
      LAYER M4 ;
        RECT  0 111.264 0.084 111.288 ;
    END
  END bank_w[444]
  PIN bank_w[445]
    DIRECTION OUTPUT ;
    USE SIGNAL ;
    PORT
      LAYER M4 ;
        RECT  0 111.504 0.084 111.528 ;
    END
  END bank_w[445]
  PIN bank_w[446]
    DIRECTION OUTPUT ;
    USE SIGNAL ;
    PORT
      LAYER M4 ;
        RECT  0 111.744 0.084 111.768 ;
    END
  END bank_w[446]
  PIN bank_w[447]
    DIRECTION OUTPUT ;
    USE SIGNAL ;
    PORT
      LAYER M4 ;
        RECT  0 111.984 0.084 112.008 ;
    END
  END bank_w[447]
  PIN bank_w[448]
    DIRECTION OUTPUT ;
    USE SIGNAL ;
    PORT
      LAYER M4 ;
        RECT  0 112.224 0.084 112.248 ;
    END
  END bank_w[448]
  PIN bank_w[449]
    DIRECTION OUTPUT ;
    USE SIGNAL ;
    PORT
      LAYER M4 ;
        RECT  0 112.464 0.084 112.488 ;
    END
  END bank_w[449]
  PIN bank_w[44]
    DIRECTION OUTPUT ;
    USE SIGNAL ;
    PORT
      LAYER M4 ;
        RECT  0 11.616 0.084 11.64 ;
    END
  END bank_w[44]
  PIN bank_w[450]
    DIRECTION OUTPUT ;
    USE SIGNAL ;
    PORT
      LAYER M4 ;
        RECT  0 112.752 0.084 112.776 ;
    END
  END bank_w[450]
  PIN bank_w[451]
    DIRECTION OUTPUT ;
    USE SIGNAL ;
    PORT
      LAYER M4 ;
        RECT  0 112.992 0.084 113.016 ;
    END
  END bank_w[451]
  PIN bank_w[452]
    DIRECTION OUTPUT ;
    USE SIGNAL ;
    PORT
      LAYER M4 ;
        RECT  0 113.232 0.084 113.256 ;
    END
  END bank_w[452]
  PIN bank_w[453]
    DIRECTION OUTPUT ;
    USE SIGNAL ;
    PORT
      LAYER M4 ;
        RECT  0 113.472 0.084 113.496 ;
    END
  END bank_w[453]
  PIN bank_w[454]
    DIRECTION OUTPUT ;
    USE SIGNAL ;
    PORT
      LAYER M4 ;
        RECT  0 113.712 0.084 113.736 ;
    END
  END bank_w[454]
  PIN bank_w[455]
    DIRECTION OUTPUT ;
    USE SIGNAL ;
    PORT
      LAYER M4 ;
        RECT  0 114 0.084 114.024 ;
    END
  END bank_w[455]
  PIN bank_w[456]
    DIRECTION OUTPUT ;
    USE SIGNAL ;
    PORT
      LAYER M4 ;
        RECT  0 114.24 0.084 114.264 ;
    END
  END bank_w[456]
  PIN bank_w[457]
    DIRECTION OUTPUT ;
    USE SIGNAL ;
    PORT
      LAYER M4 ;
        RECT  0 114.48 0.084 114.504 ;
    END
  END bank_w[457]
  PIN bank_w[458]
    DIRECTION OUTPUT ;
    USE SIGNAL ;
    PORT
      LAYER M4 ;
        RECT  0 114.72 0.084 114.744 ;
    END
  END bank_w[458]
  PIN bank_w[459]
    DIRECTION OUTPUT ;
    USE SIGNAL ;
    PORT
      LAYER M4 ;
        RECT  0 114.96 0.084 114.984 ;
    END
  END bank_w[459]
  PIN bank_w[45]
    DIRECTION OUTPUT ;
    USE SIGNAL ;
    PORT
      LAYER M4 ;
        RECT  0 11.856 0.084 11.88 ;
    END
  END bank_w[45]
  PIN bank_w[460]
    DIRECTION OUTPUT ;
    USE SIGNAL ;
    PORT
      LAYER M4 ;
        RECT  0 115.248 0.084 115.272 ;
    END
  END bank_w[460]
  PIN bank_w[461]
    DIRECTION OUTPUT ;
    USE SIGNAL ;
    PORT
      LAYER M4 ;
        RECT  0 115.488 0.084 115.512 ;
    END
  END bank_w[461]
  PIN bank_w[462]
    DIRECTION OUTPUT ;
    USE SIGNAL ;
    PORT
      LAYER M4 ;
        RECT  0 115.728 0.084 115.752 ;
    END
  END bank_w[462]
  PIN bank_w[463]
    DIRECTION OUTPUT ;
    USE SIGNAL ;
    PORT
      LAYER M4 ;
        RECT  0 115.968 0.084 115.992 ;
    END
  END bank_w[463]
  PIN bank_w[464]
    DIRECTION OUTPUT ;
    USE SIGNAL ;
    PORT
      LAYER M4 ;
        RECT  0 116.208 0.084 116.232 ;
    END
  END bank_w[464]
  PIN bank_w[465]
    DIRECTION OUTPUT ;
    USE SIGNAL ;
    PORT
      LAYER M4 ;
        RECT  0 116.448 0.084 116.472 ;
    END
  END bank_w[465]
  PIN bank_w[466]
    DIRECTION OUTPUT ;
    USE SIGNAL ;
    PORT
      LAYER M4 ;
        RECT  0 116.736 0.084 116.76 ;
    END
  END bank_w[466]
  PIN bank_w[467]
    DIRECTION OUTPUT ;
    USE SIGNAL ;
    PORT
      LAYER M4 ;
        RECT  0 116.976 0.084 117 ;
    END
  END bank_w[467]
  PIN bank_w[468]
    DIRECTION OUTPUT ;
    USE SIGNAL ;
    PORT
      LAYER M4 ;
        RECT  0 117.216 0.084 117.24 ;
    END
  END bank_w[468]
  PIN bank_w[469]
    DIRECTION OUTPUT ;
    USE SIGNAL ;
    PORT
      LAYER M4 ;
        RECT  0 117.456 0.084 117.48 ;
    END
  END bank_w[469]
  PIN bank_w[46]
    DIRECTION OUTPUT ;
    USE SIGNAL ;
    PORT
      LAYER M4 ;
        RECT  0 12.096 0.084 12.12 ;
    END
  END bank_w[46]
  PIN bank_w[470]
    DIRECTION OUTPUT ;
    USE SIGNAL ;
    PORT
      LAYER M4 ;
        RECT  0 117.696 0.084 117.72 ;
    END
  END bank_w[470]
  PIN bank_w[471]
    DIRECTION OUTPUT ;
    USE SIGNAL ;
    PORT
      LAYER M4 ;
        RECT  0 117.984 0.084 118.008 ;
    END
  END bank_w[471]
  PIN bank_w[472]
    DIRECTION OUTPUT ;
    USE SIGNAL ;
    PORT
      LAYER M4 ;
        RECT  0 118.224 0.084 118.248 ;
    END
  END bank_w[472]
  PIN bank_w[473]
    DIRECTION OUTPUT ;
    USE SIGNAL ;
    PORT
      LAYER M4 ;
        RECT  0 118.464 0.084 118.488 ;
    END
  END bank_w[473]
  PIN bank_w[474]
    DIRECTION OUTPUT ;
    USE SIGNAL ;
    PORT
      LAYER M4 ;
        RECT  0 118.704 0.084 118.728 ;
    END
  END bank_w[474]
  PIN bank_w[475]
    DIRECTION OUTPUT ;
    USE SIGNAL ;
    PORT
      LAYER M4 ;
        RECT  0 118.944 0.084 118.968 ;
    END
  END bank_w[475]
  PIN bank_w[476]
    DIRECTION OUTPUT ;
    USE SIGNAL ;
    PORT
      LAYER M4 ;
        RECT  0 119.232 0.084 119.256 ;
    END
  END bank_w[476]
  PIN bank_w[477]
    DIRECTION OUTPUT ;
    USE SIGNAL ;
    PORT
      LAYER M4 ;
        RECT  0 119.472 0.084 119.496 ;
    END
  END bank_w[477]
  PIN bank_w[478]
    DIRECTION OUTPUT ;
    USE SIGNAL ;
    PORT
      LAYER M4 ;
        RECT  0 119.712 0.084 119.736 ;
    END
  END bank_w[478]
  PIN bank_w[479]
    DIRECTION OUTPUT ;
    USE SIGNAL ;
    PORT
      LAYER M4 ;
        RECT  0 119.952 0.084 119.976 ;
    END
  END bank_w[479]
  PIN bank_w[47]
    DIRECTION OUTPUT ;
    USE SIGNAL ;
    PORT
      LAYER M4 ;
        RECT  0 12.336 0.084 12.36 ;
    END
  END bank_w[47]
  PIN bank_w[480]
    DIRECTION OUTPUT ;
    USE SIGNAL ;
    PORT
      LAYER M4 ;
        RECT  0 120.192 0.084 120.216 ;
    END
  END bank_w[480]
  PIN bank_w[481]
    DIRECTION OUTPUT ;
    USE SIGNAL ;
    PORT
      LAYER M4 ;
        RECT  0 120.432 0.084 120.456 ;
    END
  END bank_w[481]
  PIN bank_w[482]
    DIRECTION OUTPUT ;
    USE SIGNAL ;
    PORT
      LAYER M4 ;
        RECT  0 120.72 0.084 120.744 ;
    END
  END bank_w[482]
  PIN bank_w[483]
    DIRECTION OUTPUT ;
    USE SIGNAL ;
    PORT
      LAYER M4 ;
        RECT  0 120.96 0.084 120.984 ;
    END
  END bank_w[483]
  PIN bank_w[484]
    DIRECTION OUTPUT ;
    USE SIGNAL ;
    PORT
      LAYER M4 ;
        RECT  0 121.2 0.084 121.224 ;
    END
  END bank_w[484]
  PIN bank_w[485]
    DIRECTION OUTPUT ;
    USE SIGNAL ;
    PORT
      LAYER M4 ;
        RECT  0 121.44 0.084 121.464 ;
    END
  END bank_w[485]
  PIN bank_w[486]
    DIRECTION OUTPUT ;
    USE SIGNAL ;
    PORT
      LAYER M4 ;
        RECT  0 121.68 0.084 121.704 ;
    END
  END bank_w[486]
  PIN bank_w[487]
    DIRECTION OUTPUT ;
    USE SIGNAL ;
    PORT
      LAYER M4 ;
        RECT  0 121.968 0.084 121.992 ;
    END
  END bank_w[487]
  PIN bank_w[488]
    DIRECTION OUTPUT ;
    USE SIGNAL ;
    PORT
      LAYER M4 ;
        RECT  0 122.208 0.084 122.232 ;
    END
  END bank_w[488]
  PIN bank_w[489]
    DIRECTION OUTPUT ;
    USE SIGNAL ;
    PORT
      LAYER M4 ;
        RECT  0 122.448 0.084 122.472 ;
    END
  END bank_w[489]
  PIN bank_w[48]
    DIRECTION OUTPUT ;
    USE SIGNAL ;
    PORT
      LAYER M4 ;
        RECT  0 12.624 0.084 12.648 ;
    END
  END bank_w[48]
  PIN bank_w[490]
    DIRECTION OUTPUT ;
    USE SIGNAL ;
    PORT
      LAYER M4 ;
        RECT  0 122.688 0.084 122.712 ;
    END
  END bank_w[490]
  PIN bank_w[491]
    DIRECTION OUTPUT ;
    USE SIGNAL ;
    PORT
      LAYER M4 ;
        RECT  0 122.928 0.084 122.952 ;
    END
  END bank_w[491]
  PIN bank_w[492]
    DIRECTION OUTPUT ;
    USE SIGNAL ;
    PORT
      LAYER M4 ;
        RECT  0 123.216 0.084 123.24 ;
    END
  END bank_w[492]
  PIN bank_w[493]
    DIRECTION OUTPUT ;
    USE SIGNAL ;
    PORT
      LAYER M4 ;
        RECT  0 123.456 0.084 123.48 ;
    END
  END bank_w[493]
  PIN bank_w[494]
    DIRECTION OUTPUT ;
    USE SIGNAL ;
    PORT
      LAYER M4 ;
        RECT  0 123.696 0.084 123.72 ;
    END
  END bank_w[494]
  PIN bank_w[495]
    DIRECTION OUTPUT ;
    USE SIGNAL ;
    PORT
      LAYER M4 ;
        RECT  0 123.936 0.084 123.96 ;
    END
  END bank_w[495]
  PIN bank_w[496]
    DIRECTION OUTPUT ;
    USE SIGNAL ;
    PORT
      LAYER M4 ;
        RECT  0 124.176 0.084 124.2 ;
    END
  END bank_w[496]
  PIN bank_w[497]
    DIRECTION OUTPUT ;
    USE SIGNAL ;
    PORT
      LAYER M4 ;
        RECT  0 124.464 0.084 124.488 ;
    END
  END bank_w[497]
  PIN bank_w[498]
    DIRECTION OUTPUT ;
    USE SIGNAL ;
    PORT
      LAYER M4 ;
        RECT  0 124.704 0.084 124.728 ;
    END
  END bank_w[498]
  PIN bank_w[499]
    DIRECTION OUTPUT ;
    USE SIGNAL ;
    PORT
      LAYER M4 ;
        RECT  0 124.944 0.084 124.968 ;
    END
  END bank_w[499]
  PIN bank_w[49]
    DIRECTION OUTPUT ;
    USE SIGNAL ;
    PORT
      LAYER M4 ;
        RECT  0 12.864 0.084 12.888 ;
    END
  END bank_w[49]
  PIN bank_w[4]
    DIRECTION OUTPUT ;
    USE SIGNAL ;
    PORT
      LAYER M4 ;
        RECT  0 1.632 0.084 1.656 ;
    END
  END bank_w[4]
  PIN bank_w[500]
    DIRECTION OUTPUT ;
    USE SIGNAL ;
    PORT
      LAYER M4 ;
        RECT  0 125.184 0.084 125.208 ;
    END
  END bank_w[500]
  PIN bank_w[501]
    DIRECTION OUTPUT ;
    USE SIGNAL ;
    PORT
      LAYER M4 ;
        RECT  0 125.424 0.084 125.448 ;
    END
  END bank_w[501]
  PIN bank_w[502]
    DIRECTION OUTPUT ;
    USE SIGNAL ;
    PORT
      LAYER M4 ;
        RECT  0 125.664 0.084 125.688 ;
    END
  END bank_w[502]
  PIN bank_w[503]
    DIRECTION OUTPUT ;
    USE SIGNAL ;
    PORT
      LAYER M4 ;
        RECT  0 125.952 0.084 125.976 ;
    END
  END bank_w[503]
  PIN bank_w[504]
    DIRECTION OUTPUT ;
    USE SIGNAL ;
    PORT
      LAYER M4 ;
        RECT  0 126.192 0.084 126.216 ;
    END
  END bank_w[504]
  PIN bank_w[505]
    DIRECTION OUTPUT ;
    USE SIGNAL ;
    PORT
      LAYER M4 ;
        RECT  0 126.432 0.084 126.456 ;
    END
  END bank_w[505]
  PIN bank_w[506]
    DIRECTION OUTPUT ;
    USE SIGNAL ;
    PORT
      LAYER M4 ;
        RECT  0 126.672 0.084 126.696 ;
    END
  END bank_w[506]
  PIN bank_w[507]
    DIRECTION OUTPUT ;
    USE SIGNAL ;
    PORT
      LAYER M4 ;
        RECT  0 126.912 0.084 126.936 ;
    END
  END bank_w[507]
  PIN bank_w[508]
    DIRECTION OUTPUT ;
    USE SIGNAL ;
    PORT
      LAYER M4 ;
        RECT  0 127.2 0.084 127.224 ;
    END
  END bank_w[508]
  PIN bank_w[509]
    DIRECTION OUTPUT ;
    USE SIGNAL ;
    PORT
      LAYER M4 ;
        RECT  0 127.44 0.084 127.464 ;
    END
  END bank_w[509]
  PIN bank_w[50]
    DIRECTION OUTPUT ;
    USE SIGNAL ;
    PORT
      LAYER M4 ;
        RECT  0 13.104 0.084 13.128 ;
    END
  END bank_w[50]
  PIN bank_w[510]
    DIRECTION OUTPUT ;
    USE SIGNAL ;
    PORT
      LAYER M4 ;
        RECT  0 127.68 0.084 127.704 ;
    END
  END bank_w[510]
  PIN bank_w[511]
    DIRECTION OUTPUT ;
    USE SIGNAL ;
    PORT
      LAYER M4 ;
        RECT  0 127.92 0.084 127.944 ;
    END
  END bank_w[511]
  PIN bank_w[512]
    DIRECTION OUTPUT ;
    USE SIGNAL ;
    PORT
      LAYER M4 ;
        RECT  0 128.16 0.084 128.184 ;
    END
  END bank_w[512]
  PIN bank_w[513]
    DIRECTION OUTPUT ;
    USE SIGNAL ;
    PORT
      LAYER M4 ;
        RECT  0 128.448 0.084 128.472 ;
    END
  END bank_w[513]
  PIN bank_w[514]
    DIRECTION OUTPUT ;
    USE SIGNAL ;
    PORT
      LAYER M4 ;
        RECT  0 128.688 0.084 128.712 ;
    END
  END bank_w[514]
  PIN bank_w[515]
    DIRECTION OUTPUT ;
    USE SIGNAL ;
    PORT
      LAYER M4 ;
        RECT  0 128.928 0.084 128.952 ;
    END
  END bank_w[515]
  PIN bank_w[51]
    DIRECTION OUTPUT ;
    USE SIGNAL ;
    PORT
      LAYER M4 ;
        RECT  0 13.344 0.084 13.368 ;
    END
  END bank_w[51]
  PIN bank_w[52]
    DIRECTION OUTPUT ;
    USE SIGNAL ;
    PORT
      LAYER M4 ;
        RECT  0 13.584 0.084 13.608 ;
    END
  END bank_w[52]
  PIN bank_w[53]
    DIRECTION OUTPUT ;
    USE SIGNAL ;
    PORT
      LAYER M4 ;
        RECT  0 13.872 0.084 13.896 ;
    END
  END bank_w[53]
  PIN bank_w[54]
    DIRECTION OUTPUT ;
    USE SIGNAL ;
    PORT
      LAYER M4 ;
        RECT  0 14.112 0.084 14.136 ;
    END
  END bank_w[54]
  PIN bank_w[55]
    DIRECTION OUTPUT ;
    USE SIGNAL ;
    PORT
      LAYER M4 ;
        RECT  0 14.352 0.084 14.376 ;
    END
  END bank_w[55]
  PIN bank_w[56]
    DIRECTION OUTPUT ;
    USE SIGNAL ;
    PORT
      LAYER M4 ;
        RECT  0 14.592 0.084 14.616 ;
    END
  END bank_w[56]
  PIN bank_w[57]
    DIRECTION OUTPUT ;
    USE SIGNAL ;
    PORT
      LAYER M4 ;
        RECT  0 14.832 0.084 14.856 ;
    END
  END bank_w[57]
  PIN bank_w[58]
    DIRECTION OUTPUT ;
    USE SIGNAL ;
    PORT
      LAYER M4 ;
        RECT  0 15.12 0.084 15.144 ;
    END
  END bank_w[58]
  PIN bank_w[59]
    DIRECTION OUTPUT ;
    USE SIGNAL ;
    PORT
      LAYER M4 ;
        RECT  0 15.36 0.084 15.384 ;
    END
  END bank_w[59]
  PIN bank_w[5]
    DIRECTION OUTPUT ;
    USE SIGNAL ;
    PORT
      LAYER M4 ;
        RECT  0 1.92 0.084 1.944 ;
    END
  END bank_w[5]
  PIN bank_w[60]
    DIRECTION OUTPUT ;
    USE SIGNAL ;
    PORT
      LAYER M4 ;
        RECT  0 15.6 0.084 15.624 ;
    END
  END bank_w[60]
  PIN bank_w[61]
    DIRECTION OUTPUT ;
    USE SIGNAL ;
    PORT
      LAYER M4 ;
        RECT  0 15.84 0.084 15.864 ;
    END
  END bank_w[61]
  PIN bank_w[62]
    DIRECTION OUTPUT ;
    USE SIGNAL ;
    PORT
      LAYER M4 ;
        RECT  0 16.08 0.084 16.104 ;
    END
  END bank_w[62]
  PIN bank_w[63]
    DIRECTION OUTPUT ;
    USE SIGNAL ;
    PORT
      LAYER M4 ;
        RECT  0 16.368 0.084 16.392 ;
    END
  END bank_w[63]
  PIN bank_w[64]
    DIRECTION OUTPUT ;
    USE SIGNAL ;
    PORT
      LAYER M4 ;
        RECT  0 16.608 0.084 16.632 ;
    END
  END bank_w[64]
  PIN bank_w[65]
    DIRECTION OUTPUT ;
    USE SIGNAL ;
    PORT
      LAYER M4 ;
        RECT  0 16.848 0.084 16.872 ;
    END
  END bank_w[65]
  PIN bank_w[66]
    DIRECTION OUTPUT ;
    USE SIGNAL ;
    PORT
      LAYER M4 ;
        RECT  0 17.088 0.084 17.112 ;
    END
  END bank_w[66]
  PIN bank_w[67]
    DIRECTION OUTPUT ;
    USE SIGNAL ;
    PORT
      LAYER M4 ;
        RECT  0 17.328 0.084 17.352 ;
    END
  END bank_w[67]
  PIN bank_w[68]
    DIRECTION OUTPUT ;
    USE SIGNAL ;
    PORT
      LAYER M4 ;
        RECT  0 17.568 0.084 17.592 ;
    END
  END bank_w[68]
  PIN bank_w[69]
    DIRECTION OUTPUT ;
    USE SIGNAL ;
    PORT
      LAYER M4 ;
        RECT  0 17.856 0.084 17.88 ;
    END
  END bank_w[69]
  PIN bank_w[6]
    DIRECTION OUTPUT ;
    USE SIGNAL ;
    PORT
      LAYER M4 ;
        RECT  0 2.16 0.084 2.184 ;
    END
  END bank_w[6]
  PIN bank_w[70]
    DIRECTION OUTPUT ;
    USE SIGNAL ;
    PORT
      LAYER M4 ;
        RECT  0 18.096 0.084 18.12 ;
    END
  END bank_w[70]
  PIN bank_w[71]
    DIRECTION OUTPUT ;
    USE SIGNAL ;
    PORT
      LAYER M4 ;
        RECT  0 18.336 0.084 18.36 ;
    END
  END bank_w[71]
  PIN bank_w[72]
    DIRECTION OUTPUT ;
    USE SIGNAL ;
    PORT
      LAYER M4 ;
        RECT  0 18.576 0.084 18.6 ;
    END
  END bank_w[72]
  PIN bank_w[73]
    DIRECTION OUTPUT ;
    USE SIGNAL ;
    PORT
      LAYER M4 ;
        RECT  0 18.816 0.084 18.84 ;
    END
  END bank_w[73]
  PIN bank_w[74]
    DIRECTION OUTPUT ;
    USE SIGNAL ;
    PORT
      LAYER M4 ;
        RECT  0 19.104 0.084 19.128 ;
    END
  END bank_w[74]
  PIN bank_w[75]
    DIRECTION OUTPUT ;
    USE SIGNAL ;
    PORT
      LAYER M4 ;
        RECT  0 19.344 0.084 19.368 ;
    END
  END bank_w[75]
  PIN bank_w[76]
    DIRECTION OUTPUT ;
    USE SIGNAL ;
    PORT
      LAYER M4 ;
        RECT  0 19.584 0.084 19.608 ;
    END
  END bank_w[76]
  PIN bank_w[77]
    DIRECTION OUTPUT ;
    USE SIGNAL ;
    PORT
      LAYER M4 ;
        RECT  0 19.824 0.084 19.848 ;
    END
  END bank_w[77]
  PIN bank_w[78]
    DIRECTION OUTPUT ;
    USE SIGNAL ;
    PORT
      LAYER M4 ;
        RECT  0 20.064 0.084 20.088 ;
    END
  END bank_w[78]
  PIN bank_w[79]
    DIRECTION OUTPUT ;
    USE SIGNAL ;
    PORT
      LAYER M4 ;
        RECT  0 20.352 0.084 20.376 ;
    END
  END bank_w[79]
  PIN bank_w[7]
    DIRECTION OUTPUT ;
    USE SIGNAL ;
    PORT
      LAYER M4 ;
        RECT  0 2.4 0.084 2.424 ;
    END
  END bank_w[7]
  PIN bank_w[80]
    DIRECTION OUTPUT ;
    USE SIGNAL ;
    PORT
      LAYER M4 ;
        RECT  0 20.592 0.084 20.616 ;
    END
  END bank_w[80]
  PIN bank_w[81]
    DIRECTION OUTPUT ;
    USE SIGNAL ;
    PORT
      LAYER M4 ;
        RECT  0 20.832 0.084 20.856 ;
    END
  END bank_w[81]
  PIN bank_w[82]
    DIRECTION OUTPUT ;
    USE SIGNAL ;
    PORT
      LAYER M4 ;
        RECT  0 21.072 0.084 21.096 ;
    END
  END bank_w[82]
  PIN bank_w[83]
    DIRECTION OUTPUT ;
    USE SIGNAL ;
    PORT
      LAYER M4 ;
        RECT  0 21.312 0.084 21.336 ;
    END
  END bank_w[83]
  PIN bank_w[84]
    DIRECTION OUTPUT ;
    USE SIGNAL ;
    PORT
      LAYER M4 ;
        RECT  0 21.552 0.084 21.576 ;
    END
  END bank_w[84]
  PIN bank_w[85]
    DIRECTION OUTPUT ;
    USE SIGNAL ;
    PORT
      LAYER M4 ;
        RECT  0 21.84 0.084 21.864 ;
    END
  END bank_w[85]
  PIN bank_w[86]
    DIRECTION OUTPUT ;
    USE SIGNAL ;
    PORT
      LAYER M4 ;
        RECT  0 22.08 0.084 22.104 ;
    END
  END bank_w[86]
  PIN bank_w[87]
    DIRECTION OUTPUT ;
    USE SIGNAL ;
    PORT
      LAYER M4 ;
        RECT  0 22.32 0.084 22.344 ;
    END
  END bank_w[87]
  PIN bank_w[88]
    DIRECTION OUTPUT ;
    USE SIGNAL ;
    PORT
      LAYER M4 ;
        RECT  0 22.56 0.084 22.584 ;
    END
  END bank_w[88]
  PIN bank_w[89]
    DIRECTION OUTPUT ;
    USE SIGNAL ;
    PORT
      LAYER M4 ;
        RECT  0 22.8 0.084 22.824 ;
    END
  END bank_w[89]
  PIN bank_w[8]
    DIRECTION OUTPUT ;
    USE SIGNAL ;
    PORT
      LAYER M4 ;
        RECT  0 2.64 0.084 2.664 ;
    END
  END bank_w[8]
  PIN bank_w[90]
    DIRECTION OUTPUT ;
    USE SIGNAL ;
    PORT
      LAYER M4 ;
        RECT  0 23.088 0.084 23.112 ;
    END
  END bank_w[90]
  PIN bank_w[91]
    DIRECTION OUTPUT ;
    USE SIGNAL ;
    PORT
      LAYER M4 ;
        RECT  0 23.328 0.084 23.352 ;
    END
  END bank_w[91]
  PIN bank_w[92]
    DIRECTION OUTPUT ;
    USE SIGNAL ;
    PORT
      LAYER M4 ;
        RECT  0 23.568 0.084 23.592 ;
    END
  END bank_w[92]
  PIN bank_w[93]
    DIRECTION OUTPUT ;
    USE SIGNAL ;
    PORT
      LAYER M4 ;
        RECT  0 23.808 0.084 23.832 ;
    END
  END bank_w[93]
  PIN bank_w[94]
    DIRECTION OUTPUT ;
    USE SIGNAL ;
    PORT
      LAYER M4 ;
        RECT  0 24.048 0.084 24.072 ;
    END
  END bank_w[94]
  PIN bank_w[95]
    DIRECTION OUTPUT ;
    USE SIGNAL ;
    PORT
      LAYER M4 ;
        RECT  0 24.336 0.084 24.36 ;
    END
  END bank_w[95]
  PIN bank_w[96]
    DIRECTION OUTPUT ;
    USE SIGNAL ;
    PORT
      LAYER M4 ;
        RECT  0 24.576 0.084 24.6 ;
    END
  END bank_w[96]
  PIN bank_w[97]
    DIRECTION OUTPUT ;
    USE SIGNAL ;
    PORT
      LAYER M4 ;
        RECT  0 24.816 0.084 24.84 ;
    END
  END bank_w[97]
  PIN bank_w[98]
    DIRECTION OUTPUT ;
    USE SIGNAL ;
    PORT
      LAYER M4 ;
        RECT  0 25.056 0.084 25.08 ;
    END
  END bank_w[98]
  PIN bank_w[99]
    DIRECTION OUTPUT ;
    USE SIGNAL ;
    PORT
      LAYER M4 ;
        RECT  0 25.296 0.084 25.32 ;
    END
  END bank_w[99]
  PIN bank_w[9]
    DIRECTION OUTPUT ;
    USE SIGNAL ;
    PORT
      LAYER M4 ;
        RECT  0 2.88 0.084 2.904 ;
    END
  END bank_w[9]
  PIN ck
    DIRECTION INPUT ;
    USE SIGNAL ;
    PORT
      LAYER M3 ;
        RECT  29.7 0 29.718 0.038 ;
    END
  END ck
  PIN i[0]
    DIRECTION INPUT ;
    USE SIGNAL ;
    PORT
      LAYER M3 ;
        RECT  0.648 129.562 0.666 129.6 ;
    END
  END i[0]
  PIN i[100]
    DIRECTION INPUT ;
    USE SIGNAL ;
    PORT
      LAYER M3 ;
        RECT  25.344 129.562 25.362 129.6 ;
    END
  END i[100]
  PIN i[101]
    DIRECTION INPUT ;
    USE SIGNAL ;
    PORT
      LAYER M5 ;
        RECT  25.584 129.516 25.608 129.6 ;
    END
  END i[101]
  PIN i[102]
    DIRECTION INPUT ;
    USE SIGNAL ;
    PORT
      LAYER M3 ;
        RECT  25.848 129.562 25.866 129.6 ;
    END
  END i[102]
  PIN i[103]
    DIRECTION INPUT ;
    USE SIGNAL ;
    PORT
      LAYER M5 ;
        RECT  26.112 129.516 26.136 129.6 ;
    END
  END i[103]
  PIN i[104]
    DIRECTION INPUT ;
    USE SIGNAL ;
    PORT
      LAYER M3 ;
        RECT  26.352 129.562 26.37 129.6 ;
    END
  END i[104]
  PIN i[105]
    DIRECTION INPUT ;
    USE SIGNAL ;
    PORT
      LAYER M5 ;
        RECT  26.592 129.516 26.616 129.6 ;
    END
  END i[105]
  PIN i[106]
    DIRECTION INPUT ;
    USE SIGNAL ;
    PORT
      LAYER M3 ;
        RECT  26.82 129.562 26.838 129.6 ;
    END
  END i[106]
  PIN i[107]
    DIRECTION INPUT ;
    USE SIGNAL ;
    PORT
      LAYER M5 ;
        RECT  27.072 129.516 27.096 129.6 ;
    END
  END i[107]
  PIN i[108]
    DIRECTION INPUT ;
    USE SIGNAL ;
    PORT
      LAYER M3 ;
        RECT  27.324 129.562 27.342 129.6 ;
    END
  END i[108]
  PIN i[109]
    DIRECTION INPUT ;
    USE SIGNAL ;
    PORT
      LAYER M5 ;
        RECT  27.552 129.516 27.576 129.6 ;
    END
  END i[109]
  PIN i[10]
    DIRECTION INPUT ;
    USE SIGNAL ;
    PORT
      LAYER M3 ;
        RECT  3.132 129.562 3.15 129.6 ;
    END
  END i[10]
  PIN i[110]
    DIRECTION INPUT ;
    USE SIGNAL ;
    PORT
      LAYER M3 ;
        RECT  27.828 129.562 27.846 129.6 ;
    END
  END i[110]
  PIN i[111]
    DIRECTION INPUT ;
    USE SIGNAL ;
    PORT
      LAYER M5 ;
        RECT  28.08 129.516 28.104 129.6 ;
    END
  END i[111]
  PIN i[112]
    DIRECTION INPUT ;
    USE SIGNAL ;
    PORT
      LAYER M3 ;
        RECT  28.332 129.562 28.35 129.6 ;
    END
  END i[112]
  PIN i[113]
    DIRECTION INPUT ;
    USE SIGNAL ;
    PORT
      LAYER M5 ;
        RECT  28.56 129.516 28.584 129.6 ;
    END
  END i[113]
  PIN i[114]
    DIRECTION INPUT ;
    USE SIGNAL ;
    PORT
      LAYER M3 ;
        RECT  28.8 129.562 28.818 129.6 ;
    END
  END i[114]
  PIN i[115]
    DIRECTION INPUT ;
    USE SIGNAL ;
    PORT
      LAYER M5 ;
        RECT  29.04 129.516 29.064 129.6 ;
    END
  END i[115]
  PIN i[116]
    DIRECTION INPUT ;
    USE SIGNAL ;
    PORT
      LAYER M3 ;
        RECT  29.304 129.562 29.322 129.6 ;
    END
  END i[116]
  PIN i[117]
    DIRECTION INPUT ;
    USE SIGNAL ;
    PORT
      LAYER M5 ;
        RECT  29.568 129.516 29.592 129.6 ;
    END
  END i[117]
  PIN i[118]
    DIRECTION INPUT ;
    USE SIGNAL ;
    PORT
      LAYER M3 ;
        RECT  29.808 129.562 29.826 129.6 ;
    END
  END i[118]
  PIN i[119]
    DIRECTION INPUT ;
    USE SIGNAL ;
    PORT
      LAYER M5 ;
        RECT  30.048 129.516 30.072 129.6 ;
    END
  END i[119]
  PIN i[11]
    DIRECTION INPUT ;
    USE SIGNAL ;
    PORT
      LAYER M5 ;
        RECT  3.36 129.516 3.384 129.6 ;
    END
  END i[11]
  PIN i[120]
    DIRECTION INPUT ;
    USE SIGNAL ;
    PORT
      LAYER M3 ;
        RECT  30.276 129.562 30.294 129.6 ;
    END
  END i[120]
  PIN i[121]
    DIRECTION INPUT ;
    USE SIGNAL ;
    PORT
      LAYER M5 ;
        RECT  30.528 129.516 30.552 129.6 ;
    END
  END i[121]
  PIN i[122]
    DIRECTION INPUT ;
    USE SIGNAL ;
    PORT
      LAYER M3 ;
        RECT  30.78 129.562 30.798 129.6 ;
    END
  END i[122]
  PIN i[123]
    DIRECTION INPUT ;
    USE SIGNAL ;
    PORT
      LAYER M5 ;
        RECT  31.008 129.516 31.032 129.6 ;
    END
  END i[123]
  PIN i[124]
    DIRECTION INPUT ;
    USE SIGNAL ;
    PORT
      LAYER M3 ;
        RECT  31.284 129.562 31.302 129.6 ;
    END
  END i[124]
  PIN i[125]
    DIRECTION INPUT ;
    USE SIGNAL ;
    PORT
      LAYER M5 ;
        RECT  31.536 129.516 31.56 129.6 ;
    END
  END i[125]
  PIN i[126]
    DIRECTION INPUT ;
    USE SIGNAL ;
    PORT
      LAYER M3 ;
        RECT  31.788 129.562 31.806 129.6 ;
    END
  END i[126]
  PIN i[127]
    DIRECTION INPUT ;
    USE SIGNAL ;
    PORT
      LAYER M5 ;
        RECT  32.016 129.516 32.04 129.6 ;
    END
  END i[127]
  PIN i[128]
    DIRECTION INPUT ;
    USE SIGNAL ;
    PORT
      LAYER M3 ;
        RECT  32.256 129.562 32.274 129.6 ;
    END
  END i[128]
  PIN i[129]
    DIRECTION INPUT ;
    USE SIGNAL ;
    PORT
      LAYER M5 ;
        RECT  32.496 129.516 32.52 129.6 ;
    END
  END i[129]
  PIN i[12]
    DIRECTION INPUT ;
    USE SIGNAL ;
    PORT
      LAYER M3 ;
        RECT  3.636 129.562 3.654 129.6 ;
    END
  END i[12]
  PIN i[130]
    DIRECTION INPUT ;
    USE SIGNAL ;
    PORT
      LAYER M3 ;
        RECT  32.76 129.562 32.778 129.6 ;
    END
  END i[130]
  PIN i[131]
    DIRECTION INPUT ;
    USE SIGNAL ;
    PORT
      LAYER M5 ;
        RECT  33.024 129.516 33.048 129.6 ;
    END
  END i[131]
  PIN i[132]
    DIRECTION INPUT ;
    USE SIGNAL ;
    PORT
      LAYER M3 ;
        RECT  33.264 129.562 33.282 129.6 ;
    END
  END i[132]
  PIN i[133]
    DIRECTION INPUT ;
    USE SIGNAL ;
    PORT
      LAYER M5 ;
        RECT  33.504 129.516 33.528 129.6 ;
    END
  END i[133]
  PIN i[134]
    DIRECTION INPUT ;
    USE SIGNAL ;
    PORT
      LAYER M3 ;
        RECT  33.732 129.562 33.75 129.6 ;
    END
  END i[134]
  PIN i[135]
    DIRECTION INPUT ;
    USE SIGNAL ;
    PORT
      LAYER M5 ;
        RECT  33.984 129.516 34.008 129.6 ;
    END
  END i[135]
  PIN i[136]
    DIRECTION INPUT ;
    USE SIGNAL ;
    PORT
      LAYER M3 ;
        RECT  34.236 129.562 34.254 129.6 ;
    END
  END i[136]
  PIN i[137]
    DIRECTION INPUT ;
    USE SIGNAL ;
    PORT
      LAYER M5 ;
        RECT  34.464 129.516 34.488 129.6 ;
    END
  END i[137]
  PIN i[138]
    DIRECTION INPUT ;
    USE SIGNAL ;
    PORT
      LAYER M3 ;
        RECT  34.74 129.562 34.758 129.6 ;
    END
  END i[138]
  PIN i[139]
    DIRECTION INPUT ;
    USE SIGNAL ;
    PORT
      LAYER M5 ;
        RECT  34.992 129.516 35.016 129.6 ;
    END
  END i[139]
  PIN i[13]
    DIRECTION INPUT ;
    USE SIGNAL ;
    PORT
      LAYER M5 ;
        RECT  3.84 129.516 3.864 129.6 ;
    END
  END i[13]
  PIN i[140]
    DIRECTION INPUT ;
    USE SIGNAL ;
    PORT
      LAYER M3 ;
        RECT  35.244 129.562 35.262 129.6 ;
    END
  END i[140]
  PIN i[141]
    DIRECTION INPUT ;
    USE SIGNAL ;
    PORT
      LAYER M5 ;
        RECT  35.472 129.516 35.496 129.6 ;
    END
  END i[141]
  PIN i[142]
    DIRECTION INPUT ;
    USE SIGNAL ;
    PORT
      LAYER M3 ;
        RECT  35.712 129.562 35.73 129.6 ;
    END
  END i[142]
  PIN i[143]
    DIRECTION INPUT ;
    USE SIGNAL ;
    PORT
      LAYER M5 ;
        RECT  35.952 129.516 35.976 129.6 ;
    END
  END i[143]
  PIN i[144]
    DIRECTION INPUT ;
    USE SIGNAL ;
    PORT
      LAYER M3 ;
        RECT  36.216 129.562 36.234 129.6 ;
    END
  END i[144]
  PIN i[145]
    DIRECTION INPUT ;
    USE SIGNAL ;
    PORT
      LAYER M5 ;
        RECT  36.48 129.516 36.504 129.6 ;
    END
  END i[145]
  PIN i[146]
    DIRECTION INPUT ;
    USE SIGNAL ;
    PORT
      LAYER M3 ;
        RECT  36.72 129.562 36.738 129.6 ;
    END
  END i[146]
  PIN i[147]
    DIRECTION INPUT ;
    USE SIGNAL ;
    PORT
      LAYER M5 ;
        RECT  36.96 129.516 36.984 129.6 ;
    END
  END i[147]
  PIN i[148]
    DIRECTION INPUT ;
    USE SIGNAL ;
    PORT
      LAYER M3 ;
        RECT  37.224 129.562 37.242 129.6 ;
    END
  END i[148]
  PIN i[149]
    DIRECTION INPUT ;
    USE SIGNAL ;
    PORT
      LAYER M5 ;
        RECT  37.44 129.516 37.464 129.6 ;
    END
  END i[149]
  PIN i[14]
    DIRECTION INPUT ;
    USE SIGNAL ;
    PORT
      LAYER M3 ;
        RECT  4.104 129.562 4.122 129.6 ;
    END
  END i[14]
  PIN i[150]
    DIRECTION INPUT ;
    USE SIGNAL ;
    PORT
      LAYER M3 ;
        RECT  37.692 129.562 37.71 129.6 ;
    END
  END i[150]
  PIN i[151]
    DIRECTION INPUT ;
    USE SIGNAL ;
    PORT
      LAYER M5 ;
        RECT  37.968 129.516 37.992 129.6 ;
    END
  END i[151]
  PIN i[152]
    DIRECTION INPUT ;
    USE SIGNAL ;
    PORT
      LAYER M3 ;
        RECT  38.196 129.562 38.214 129.6 ;
    END
  END i[152]
  PIN i[153]
    DIRECTION INPUT ;
    USE SIGNAL ;
    PORT
      LAYER M5 ;
        RECT  38.448 129.516 38.472 129.6 ;
    END
  END i[153]
  PIN i[154]
    DIRECTION INPUT ;
    USE SIGNAL ;
    PORT
      LAYER M3 ;
        RECT  38.7 129.562 38.718 129.6 ;
    END
  END i[154]
  PIN i[155]
    DIRECTION INPUT ;
    USE SIGNAL ;
    PORT
      LAYER M5 ;
        RECT  38.928 129.516 38.952 129.6 ;
    END
  END i[155]
  PIN i[156]
    DIRECTION INPUT ;
    USE SIGNAL ;
    PORT
      LAYER M3 ;
        RECT  39.168 129.562 39.186 129.6 ;
    END
  END i[156]
  PIN i[157]
    DIRECTION INPUT ;
    USE SIGNAL ;
    PORT
      LAYER M5 ;
        RECT  39.408 129.516 39.432 129.6 ;
    END
  END i[157]
  PIN i[158]
    DIRECTION INPUT ;
    USE SIGNAL ;
    PORT
      LAYER M3 ;
        RECT  39.672 129.562 39.69 129.6 ;
    END
  END i[158]
  PIN i[159]
    DIRECTION INPUT ;
    USE SIGNAL ;
    PORT
      LAYER M5 ;
        RECT  39.936 129.516 39.96 129.6 ;
    END
  END i[159]
  PIN i[15]
    DIRECTION INPUT ;
    USE SIGNAL ;
    PORT
      LAYER M5 ;
        RECT  4.368 129.516 4.392 129.6 ;
    END
  END i[15]
  PIN i[160]
    DIRECTION INPUT ;
    USE SIGNAL ;
    PORT
      LAYER M3 ;
        RECT  40.176 129.562 40.194 129.6 ;
    END
  END i[160]
  PIN i[161]
    DIRECTION INPUT ;
    USE SIGNAL ;
    PORT
      LAYER M5 ;
        RECT  40.416 129.516 40.44 129.6 ;
    END
  END i[161]
  PIN i[162]
    DIRECTION INPUT ;
    USE SIGNAL ;
    PORT
      LAYER M3 ;
        RECT  40.68 129.562 40.698 129.6 ;
    END
  END i[162]
  PIN i[163]
    DIRECTION INPUT ;
    USE SIGNAL ;
    PORT
      LAYER M5 ;
        RECT  40.896 129.516 40.92 129.6 ;
    END
  END i[163]
  PIN i[164]
    DIRECTION INPUT ;
    USE SIGNAL ;
    PORT
      LAYER M3 ;
        RECT  41.148 129.562 41.166 129.6 ;
    END
  END i[164]
  PIN i[165]
    DIRECTION INPUT ;
    USE SIGNAL ;
    PORT
      LAYER M5 ;
        RECT  41.424 129.516 41.448 129.6 ;
    END
  END i[165]
  PIN i[166]
    DIRECTION INPUT ;
    USE SIGNAL ;
    PORT
      LAYER M3 ;
        RECT  41.652 129.562 41.67 129.6 ;
    END
  END i[166]
  PIN i[167]
    DIRECTION INPUT ;
    USE SIGNAL ;
    PORT
      LAYER M5 ;
        RECT  41.904 129.516 41.928 129.6 ;
    END
  END i[167]
  PIN i[168]
    DIRECTION INPUT ;
    USE SIGNAL ;
    PORT
      LAYER M3 ;
        RECT  42.156 129.562 42.174 129.6 ;
    END
  END i[168]
  PIN i[169]
    DIRECTION INPUT ;
    USE SIGNAL ;
    PORT
      LAYER M5 ;
        RECT  42.384 129.516 42.408 129.6 ;
    END
  END i[169]
  PIN i[16]
    DIRECTION INPUT ;
    USE SIGNAL ;
    PORT
      LAYER M3 ;
        RECT  4.608 129.562 4.626 129.6 ;
    END
  END i[16]
  PIN i[170]
    DIRECTION INPUT ;
    USE SIGNAL ;
    PORT
      LAYER M3 ;
        RECT  42.624 129.562 42.642 129.6 ;
    END
  END i[170]
  PIN i[171]
    DIRECTION INPUT ;
    USE SIGNAL ;
    PORT
      LAYER M5 ;
        RECT  42.864 129.516 42.888 129.6 ;
    END
  END i[171]
  PIN i[172]
    DIRECTION INPUT ;
    USE SIGNAL ;
    PORT
      LAYER M3 ;
        RECT  43.128 129.562 43.146 129.6 ;
    END
  END i[172]
  PIN i[173]
    DIRECTION INPUT ;
    USE SIGNAL ;
    PORT
      LAYER M5 ;
        RECT  43.392 129.516 43.416 129.6 ;
    END
  END i[173]
  PIN i[174]
    DIRECTION INPUT ;
    USE SIGNAL ;
    PORT
      LAYER M3 ;
        RECT  43.632 129.562 43.65 129.6 ;
    END
  END i[174]
  PIN i[175]
    DIRECTION INPUT ;
    USE SIGNAL ;
    PORT
      LAYER M5 ;
        RECT  43.872 129.516 43.896 129.6 ;
    END
  END i[175]
  PIN i[176]
    DIRECTION INPUT ;
    USE SIGNAL ;
    PORT
      LAYER M3 ;
        RECT  44.136 129.562 44.154 129.6 ;
    END
  END i[176]
  PIN i[177]
    DIRECTION INPUT ;
    USE SIGNAL ;
    PORT
      LAYER M5 ;
        RECT  44.352 129.516 44.376 129.6 ;
    END
  END i[177]
  PIN i[178]
    DIRECTION INPUT ;
    USE SIGNAL ;
    PORT
      LAYER M3 ;
        RECT  44.604 129.562 44.622 129.6 ;
    END
  END i[178]
  PIN i[179]
    DIRECTION INPUT ;
    USE SIGNAL ;
    PORT
      LAYER M5 ;
        RECT  44.88 129.516 44.904 129.6 ;
    END
  END i[179]
  PIN i[17]
    DIRECTION INPUT ;
    USE SIGNAL ;
    PORT
      LAYER M5 ;
        RECT  4.848 129.516 4.872 129.6 ;
    END
  END i[17]
  PIN i[180]
    DIRECTION INPUT ;
    USE SIGNAL ;
    PORT
      LAYER M3 ;
        RECT  45.108 129.562 45.126 129.6 ;
    END
  END i[180]
  PIN i[181]
    DIRECTION INPUT ;
    USE SIGNAL ;
    PORT
      LAYER M5 ;
        RECT  45.36 129.516 45.384 129.6 ;
    END
  END i[181]
  PIN i[182]
    DIRECTION INPUT ;
    USE SIGNAL ;
    PORT
      LAYER M3 ;
        RECT  45.612 129.562 45.63 129.6 ;
    END
  END i[182]
  PIN i[183]
    DIRECTION INPUT ;
    USE SIGNAL ;
    PORT
      LAYER M5 ;
        RECT  45.84 129.516 45.864 129.6 ;
    END
  END i[183]
  PIN i[184]
    DIRECTION INPUT ;
    USE SIGNAL ;
    PORT
      LAYER M3 ;
        RECT  46.116 129.562 46.134 129.6 ;
    END
  END i[184]
  PIN i[185]
    DIRECTION INPUT ;
    USE SIGNAL ;
    PORT
      LAYER M5 ;
        RECT  46.32 129.516 46.344 129.6 ;
    END
  END i[185]
  PIN i[186]
    DIRECTION INPUT ;
    USE SIGNAL ;
    PORT
      LAYER M3 ;
        RECT  46.584 129.562 46.602 129.6 ;
    END
  END i[186]
  PIN i[187]
    DIRECTION INPUT ;
    USE SIGNAL ;
    PORT
      LAYER M5 ;
        RECT  46.848 129.516 46.872 129.6 ;
    END
  END i[187]
  PIN i[188]
    DIRECTION INPUT ;
    USE SIGNAL ;
    PORT
      LAYER M3 ;
        RECT  47.088 129.562 47.106 129.6 ;
    END
  END i[188]
  PIN i[189]
    DIRECTION INPUT ;
    USE SIGNAL ;
    PORT
      LAYER M5 ;
        RECT  47.328 129.516 47.352 129.6 ;
    END
  END i[189]
  PIN i[18]
    DIRECTION INPUT ;
    USE SIGNAL ;
    PORT
      LAYER M3 ;
        RECT  5.112 129.562 5.13 129.6 ;
    END
  END i[18]
  PIN i[190]
    DIRECTION INPUT ;
    USE SIGNAL ;
    PORT
      LAYER M3 ;
        RECT  47.592 129.562 47.61 129.6 ;
    END
  END i[190]
  PIN i[191]
    DIRECTION INPUT ;
    USE SIGNAL ;
    PORT
      LAYER M5 ;
        RECT  47.808 129.516 47.832 129.6 ;
    END
  END i[191]
  PIN i[192]
    DIRECTION INPUT ;
    USE SIGNAL ;
    PORT
      LAYER M3 ;
        RECT  48.06 129.562 48.078 129.6 ;
    END
  END i[192]
  PIN i[193]
    DIRECTION INPUT ;
    USE SIGNAL ;
    PORT
      LAYER M5 ;
        RECT  48.336 129.516 48.36 129.6 ;
    END
  END i[193]
  PIN i[194]
    DIRECTION INPUT ;
    USE SIGNAL ;
    PORT
      LAYER M3 ;
        RECT  48.564 129.562 48.582 129.6 ;
    END
  END i[194]
  PIN i[195]
    DIRECTION INPUT ;
    USE SIGNAL ;
    PORT
      LAYER M5 ;
        RECT  48.816 129.516 48.84 129.6 ;
    END
  END i[195]
  PIN i[196]
    DIRECTION INPUT ;
    USE SIGNAL ;
    PORT
      LAYER M3 ;
        RECT  49.068 129.562 49.086 129.6 ;
    END
  END i[196]
  PIN i[197]
    DIRECTION INPUT ;
    USE SIGNAL ;
    PORT
      LAYER M5 ;
        RECT  49.296 129.516 49.32 129.6 ;
    END
  END i[197]
  PIN i[198]
    DIRECTION INPUT ;
    USE SIGNAL ;
    PORT
      LAYER M3 ;
        RECT  49.572 129.562 49.59 129.6 ;
    END
  END i[198]
  PIN i[199]
    DIRECTION INPUT ;
    USE SIGNAL ;
    PORT
      LAYER M5 ;
        RECT  49.824 129.516 49.848 129.6 ;
    END
  END i[199]
  PIN i[19]
    DIRECTION INPUT ;
    USE SIGNAL ;
    PORT
      LAYER M5 ;
        RECT  5.328 129.516 5.352 129.6 ;
    END
  END i[19]
  PIN i[1]
    DIRECTION INPUT ;
    USE SIGNAL ;
    PORT
      LAYER M5 ;
        RECT  0.912 129.516 0.936 129.6 ;
    END
  END i[1]
  PIN i[200]
    DIRECTION INPUT ;
    USE SIGNAL ;
    PORT
      LAYER M3 ;
        RECT  50.04 129.562 50.058 129.6 ;
    END
  END i[200]
  PIN i[201]
    DIRECTION INPUT ;
    USE SIGNAL ;
    PORT
      LAYER M5 ;
        RECT  50.304 129.516 50.328 129.6 ;
    END
  END i[201]
  PIN i[202]
    DIRECTION INPUT ;
    USE SIGNAL ;
    PORT
      LAYER M3 ;
        RECT  50.544 129.562 50.562 129.6 ;
    END
  END i[202]
  PIN i[203]
    DIRECTION INPUT ;
    USE SIGNAL ;
    PORT
      LAYER M5 ;
        RECT  50.784 129.516 50.808 129.6 ;
    END
  END i[203]
  PIN i[204]
    DIRECTION INPUT ;
    USE SIGNAL ;
    PORT
      LAYER M3 ;
        RECT  51.048 129.562 51.066 129.6 ;
    END
  END i[204]
  PIN i[205]
    DIRECTION INPUT ;
    USE SIGNAL ;
    PORT
      LAYER M5 ;
        RECT  51.264 129.516 51.288 129.6 ;
    END
  END i[205]
  PIN i[206]
    DIRECTION INPUT ;
    USE SIGNAL ;
    PORT
      LAYER M3 ;
        RECT  51.516 129.562 51.534 129.6 ;
    END
  END i[206]
  PIN i[207]
    DIRECTION INPUT ;
    USE SIGNAL ;
    PORT
      LAYER M5 ;
        RECT  51.792 129.516 51.816 129.6 ;
    END
  END i[207]
  PIN i[208]
    DIRECTION INPUT ;
    USE SIGNAL ;
    PORT
      LAYER M3 ;
        RECT  52.02 129.562 52.038 129.6 ;
    END
  END i[208]
  PIN i[209]
    DIRECTION INPUT ;
    USE SIGNAL ;
    PORT
      LAYER M5 ;
        RECT  52.272 129.516 52.296 129.6 ;
    END
  END i[209]
  PIN i[20]
    DIRECTION INPUT ;
    USE SIGNAL ;
    PORT
      LAYER M3 ;
        RECT  5.58 129.562 5.598 129.6 ;
    END
  END i[20]
  PIN i[210]
    DIRECTION INPUT ;
    USE SIGNAL ;
    PORT
      LAYER M3 ;
        RECT  52.524 129.562 52.542 129.6 ;
    END
  END i[210]
  PIN i[211]
    DIRECTION INPUT ;
    USE SIGNAL ;
    PORT
      LAYER M5 ;
        RECT  52.752 129.516 52.776 129.6 ;
    END
  END i[211]
  PIN i[212]
    DIRECTION INPUT ;
    USE SIGNAL ;
    PORT
      LAYER M3 ;
        RECT  53.028 129.562 53.046 129.6 ;
    END
  END i[212]
  PIN i[213]
    DIRECTION INPUT ;
    USE SIGNAL ;
    PORT
      LAYER M5 ;
        RECT  53.28 129.516 53.304 129.6 ;
    END
  END i[213]
  PIN i[214]
    DIRECTION INPUT ;
    USE SIGNAL ;
    PORT
      LAYER M3 ;
        RECT  53.496 129.562 53.514 129.6 ;
    END
  END i[214]
  PIN i[215]
    DIRECTION INPUT ;
    USE SIGNAL ;
    PORT
      LAYER M5 ;
        RECT  53.76 129.516 53.784 129.6 ;
    END
  END i[215]
  PIN i[216]
    DIRECTION INPUT ;
    USE SIGNAL ;
    PORT
      LAYER M3 ;
        RECT  54 129.562 54.018 129.6 ;
    END
  END i[216]
  PIN i[217]
    DIRECTION INPUT ;
    USE SIGNAL ;
    PORT
      LAYER M5 ;
        RECT  54.24 129.516 54.264 129.6 ;
    END
  END i[217]
  PIN i[218]
    DIRECTION INPUT ;
    USE SIGNAL ;
    PORT
      LAYER M3 ;
        RECT  54.504 129.562 54.522 129.6 ;
    END
  END i[218]
  PIN i[219]
    DIRECTION INPUT ;
    USE SIGNAL ;
    PORT
      LAYER M5 ;
        RECT  54.72 129.516 54.744 129.6 ;
    END
  END i[219]
  PIN i[21]
    DIRECTION INPUT ;
    USE SIGNAL ;
    PORT
      LAYER M5 ;
        RECT  5.856 129.516 5.88 129.6 ;
    END
  END i[21]
  PIN i[220]
    DIRECTION INPUT ;
    USE SIGNAL ;
    PORT
      LAYER M3 ;
        RECT  54.972 129.562 54.99 129.6 ;
    END
  END i[220]
  PIN i[221]
    DIRECTION INPUT ;
    USE SIGNAL ;
    PORT
      LAYER M5 ;
        RECT  55.248 129.516 55.272 129.6 ;
    END
  END i[221]
  PIN i[222]
    DIRECTION INPUT ;
    USE SIGNAL ;
    PORT
      LAYER M3 ;
        RECT  55.476 129.562 55.494 129.6 ;
    END
  END i[222]
  PIN i[223]
    DIRECTION INPUT ;
    USE SIGNAL ;
    PORT
      LAYER M5 ;
        RECT  55.728 129.516 55.752 129.6 ;
    END
  END i[223]
  PIN i[224]
    DIRECTION INPUT ;
    USE SIGNAL ;
    PORT
      LAYER M3 ;
        RECT  55.98 129.562 55.998 129.6 ;
    END
  END i[224]
  PIN i[225]
    DIRECTION INPUT ;
    USE SIGNAL ;
    PORT
      LAYER M5 ;
        RECT  56.208 129.516 56.232 129.6 ;
    END
  END i[225]
  PIN i[226]
    DIRECTION INPUT ;
    USE SIGNAL ;
    PORT
      LAYER M3 ;
        RECT  56.484 129.562 56.502 129.6 ;
    END
  END i[226]
  PIN i[227]
    DIRECTION INPUT ;
    USE SIGNAL ;
    PORT
      LAYER M5 ;
        RECT  56.736 129.516 56.76 129.6 ;
    END
  END i[227]
  PIN i[228]
    DIRECTION INPUT ;
    USE SIGNAL ;
    PORT
      LAYER M3 ;
        RECT  56.952 129.562 56.97 129.6 ;
    END
  END i[228]
  PIN i[229]
    DIRECTION INPUT ;
    USE SIGNAL ;
    PORT
      LAYER M5 ;
        RECT  57.216 129.516 57.24 129.6 ;
    END
  END i[229]
  PIN i[22]
    DIRECTION INPUT ;
    USE SIGNAL ;
    PORT
      LAYER M3 ;
        RECT  6.084 129.562 6.102 129.6 ;
    END
  END i[22]
  PIN i[230]
    DIRECTION INPUT ;
    USE SIGNAL ;
    PORT
      LAYER M3 ;
        RECT  57.456 129.562 57.474 129.6 ;
    END
  END i[230]
  PIN i[231]
    DIRECTION INPUT ;
    USE SIGNAL ;
    PORT
      LAYER M5 ;
        RECT  57.696 129.516 57.72 129.6 ;
    END
  END i[231]
  PIN i[232]
    DIRECTION INPUT ;
    USE SIGNAL ;
    PORT
      LAYER M3 ;
        RECT  57.96 129.562 57.978 129.6 ;
    END
  END i[232]
  PIN i[233]
    DIRECTION INPUT ;
    USE SIGNAL ;
    PORT
      LAYER M5 ;
        RECT  58.176 129.516 58.2 129.6 ;
    END
  END i[233]
  PIN i[234]
    DIRECTION INPUT ;
    USE SIGNAL ;
    PORT
      LAYER M3 ;
        RECT  58.464 129.562 58.482 129.6 ;
    END
  END i[234]
  PIN i[235]
    DIRECTION INPUT ;
    USE SIGNAL ;
    PORT
      LAYER M5 ;
        RECT  58.704 129.516 58.728 129.6 ;
    END
  END i[235]
  PIN i[236]
    DIRECTION INPUT ;
    USE SIGNAL ;
    PORT
      LAYER M3 ;
        RECT  58.932 129.562 58.95 129.6 ;
    END
  END i[236]
  PIN i[237]
    DIRECTION INPUT ;
    USE SIGNAL ;
    PORT
      LAYER M5 ;
        RECT  59.184 129.516 59.208 129.6 ;
    END
  END i[237]
  PIN i[238]
    DIRECTION INPUT ;
    USE SIGNAL ;
    PORT
      LAYER M3 ;
        RECT  59.436 129.562 59.454 129.6 ;
    END
  END i[238]
  PIN i[239]
    DIRECTION INPUT ;
    USE SIGNAL ;
    PORT
      LAYER M5 ;
        RECT  59.664 129.516 59.688 129.6 ;
    END
  END i[239]
  PIN i[23]
    DIRECTION INPUT ;
    USE SIGNAL ;
    PORT
      LAYER M5 ;
        RECT  6.336 129.516 6.36 129.6 ;
    END
  END i[23]
  PIN i[240]
    DIRECTION INPUT ;
    USE SIGNAL ;
    PORT
      LAYER M3 ;
        RECT  59.94 129.562 59.958 129.6 ;
    END
  END i[240]
  PIN i[241]
    DIRECTION INPUT ;
    USE SIGNAL ;
    PORT
      LAYER M5 ;
        RECT  60.192 129.516 60.216 129.6 ;
    END
  END i[241]
  PIN i[242]
    DIRECTION INPUT ;
    USE SIGNAL ;
    PORT
      LAYER M3 ;
        RECT  60.408 129.562 60.426 129.6 ;
    END
  END i[242]
  PIN i[243]
    DIRECTION INPUT ;
    USE SIGNAL ;
    PORT
      LAYER M5 ;
        RECT  60.672 129.516 60.696 129.6 ;
    END
  END i[243]
  PIN i[244]
    DIRECTION INPUT ;
    USE SIGNAL ;
    PORT
      LAYER M3 ;
        RECT  60.912 129.562 60.93 129.6 ;
    END
  END i[244]
  PIN i[245]
    DIRECTION INPUT ;
    USE SIGNAL ;
    PORT
      LAYER M5 ;
        RECT  61.152 129.516 61.176 129.6 ;
    END
  END i[245]
  PIN i[246]
    DIRECTION INPUT ;
    USE SIGNAL ;
    PORT
      LAYER M3 ;
        RECT  61.416 129.562 61.434 129.6 ;
    END
  END i[246]
  PIN i[247]
    DIRECTION INPUT ;
    USE SIGNAL ;
    PORT
      LAYER M5 ;
        RECT  61.632 129.516 61.656 129.6 ;
    END
  END i[247]
  PIN i[248]
    DIRECTION INPUT ;
    USE SIGNAL ;
    PORT
      LAYER M3 ;
        RECT  61.92 129.562 61.938 129.6 ;
    END
  END i[248]
  PIN i[249]
    DIRECTION INPUT ;
    USE SIGNAL ;
    PORT
      LAYER M5 ;
        RECT  62.16 129.516 62.184 129.6 ;
    END
  END i[249]
  PIN i[24]
    DIRECTION INPUT ;
    USE SIGNAL ;
    PORT
      LAYER M3 ;
        RECT  6.588 129.562 6.606 129.6 ;
    END
  END i[24]
  PIN i[250]
    DIRECTION INPUT ;
    USE SIGNAL ;
    PORT
      LAYER M3 ;
        RECT  62.388 129.562 62.406 129.6 ;
    END
  END i[250]
  PIN i[251]
    DIRECTION INPUT ;
    USE SIGNAL ;
    PORT
      LAYER M5 ;
        RECT  62.64 129.516 62.664 129.6 ;
    END
  END i[251]
  PIN i[252]
    DIRECTION INPUT ;
    USE SIGNAL ;
    PORT
      LAYER M3 ;
        RECT  62.892 129.562 62.91 129.6 ;
    END
  END i[252]
  PIN i[253]
    DIRECTION INPUT ;
    USE SIGNAL ;
    PORT
      LAYER M5 ;
        RECT  63.12 129.516 63.144 129.6 ;
    END
  END i[253]
  PIN i[254]
    DIRECTION INPUT ;
    USE SIGNAL ;
    PORT
      LAYER M3 ;
        RECT  63.396 129.562 63.414 129.6 ;
    END
  END i[254]
  PIN i[255]
    DIRECTION INPUT ;
    USE SIGNAL ;
    PORT
      LAYER M5 ;
        RECT  63.648 129.516 63.672 129.6 ;
    END
  END i[255]
  PIN i[256]
    DIRECTION INPUT ;
    USE SIGNAL ;
    PORT
      LAYER M3 ;
        RECT  63.864 129.562 63.882 129.6 ;
    END
  END i[256]
  PIN i[257]
    DIRECTION INPUT ;
    USE SIGNAL ;
    PORT
      LAYER M5 ;
        RECT  64.128 129.516 64.152 129.6 ;
    END
  END i[257]
  PIN i[25]
    DIRECTION INPUT ;
    USE SIGNAL ;
    PORT
      LAYER M5 ;
        RECT  6.816 129.516 6.84 129.6 ;
    END
  END i[25]
  PIN i[26]
    DIRECTION INPUT ;
    USE SIGNAL ;
    PORT
      LAYER M3 ;
        RECT  7.092 129.562 7.11 129.6 ;
    END
  END i[26]
  PIN i[27]
    DIRECTION INPUT ;
    USE SIGNAL ;
    PORT
      LAYER M5 ;
        RECT  7.344 129.516 7.368 129.6 ;
    END
  END i[27]
  PIN i[28]
    DIRECTION INPUT ;
    USE SIGNAL ;
    PORT
      LAYER M3 ;
        RECT  7.56 129.562 7.578 129.6 ;
    END
  END i[28]
  PIN i[29]
    DIRECTION INPUT ;
    USE SIGNAL ;
    PORT
      LAYER M5 ;
        RECT  7.824 129.516 7.848 129.6 ;
    END
  END i[29]
  PIN i[2]
    DIRECTION INPUT ;
    USE SIGNAL ;
    PORT
      LAYER M3 ;
        RECT  1.152 129.562 1.17 129.6 ;
    END
  END i[2]
  PIN i[30]
    DIRECTION INPUT ;
    USE SIGNAL ;
    PORT
      LAYER M3 ;
        RECT  8.064 129.562 8.082 129.6 ;
    END
  END i[30]
  PIN i[31]
    DIRECTION INPUT ;
    USE SIGNAL ;
    PORT
      LAYER M5 ;
        RECT  8.304 129.516 8.328 129.6 ;
    END
  END i[31]
  PIN i[32]
    DIRECTION INPUT ;
    USE SIGNAL ;
    PORT
      LAYER M3 ;
        RECT  8.568 129.562 8.586 129.6 ;
    END
  END i[32]
  PIN i[33]
    DIRECTION INPUT ;
    USE SIGNAL ;
    PORT
      LAYER M5 ;
        RECT  8.784 129.516 8.808 129.6 ;
    END
  END i[33]
  PIN i[34]
    DIRECTION INPUT ;
    USE SIGNAL ;
    PORT
      LAYER M3 ;
        RECT  9.036 129.562 9.054 129.6 ;
    END
  END i[34]
  PIN i[35]
    DIRECTION INPUT ;
    USE SIGNAL ;
    PORT
      LAYER M5 ;
        RECT  9.312 129.516 9.336 129.6 ;
    END
  END i[35]
  PIN i[36]
    DIRECTION INPUT ;
    USE SIGNAL ;
    PORT
      LAYER M3 ;
        RECT  9.54 129.562 9.558 129.6 ;
    END
  END i[36]
  PIN i[37]
    DIRECTION INPUT ;
    USE SIGNAL ;
    PORT
      LAYER M5 ;
        RECT  9.792 129.516 9.816 129.6 ;
    END
  END i[37]
  PIN i[38]
    DIRECTION INPUT ;
    USE SIGNAL ;
    PORT
      LAYER M3 ;
        RECT  10.044 129.562 10.062 129.6 ;
    END
  END i[38]
  PIN i[39]
    DIRECTION INPUT ;
    USE SIGNAL ;
    PORT
      LAYER M5 ;
        RECT  10.272 129.516 10.296 129.6 ;
    END
  END i[39]
  PIN i[3]
    DIRECTION INPUT ;
    USE SIGNAL ;
    PORT
      LAYER M5 ;
        RECT  1.392 129.516 1.416 129.6 ;
    END
  END i[3]
  PIN i[40]
    DIRECTION INPUT ;
    USE SIGNAL ;
    PORT
      LAYER M3 ;
        RECT  10.548 129.562 10.566 129.6 ;
    END
  END i[40]
  PIN i[41]
    DIRECTION INPUT ;
    USE SIGNAL ;
    PORT
      LAYER M5 ;
        RECT  10.8 129.516 10.824 129.6 ;
    END
  END i[41]
  PIN i[42]
    DIRECTION INPUT ;
    USE SIGNAL ;
    PORT
      LAYER M3 ;
        RECT  11.016 129.562 11.034 129.6 ;
    END
  END i[42]
  PIN i[43]
    DIRECTION INPUT ;
    USE SIGNAL ;
    PORT
      LAYER M5 ;
        RECT  11.28 129.516 11.304 129.6 ;
    END
  END i[43]
  PIN i[44]
    DIRECTION INPUT ;
    USE SIGNAL ;
    PORT
      LAYER M3 ;
        RECT  11.52 129.562 11.538 129.6 ;
    END
  END i[44]
  PIN i[45]
    DIRECTION INPUT ;
    USE SIGNAL ;
    PORT
      LAYER M5 ;
        RECT  11.76 129.516 11.784 129.6 ;
    END
  END i[45]
  PIN i[46]
    DIRECTION INPUT ;
    USE SIGNAL ;
    PORT
      LAYER M3 ;
        RECT  12.024 129.562 12.042 129.6 ;
    END
  END i[46]
  PIN i[47]
    DIRECTION INPUT ;
    USE SIGNAL ;
    PORT
      LAYER M5 ;
        RECT  12.24 129.516 12.264 129.6 ;
    END
  END i[47]
  PIN i[48]
    DIRECTION INPUT ;
    USE SIGNAL ;
    PORT
      LAYER M3 ;
        RECT  12.492 129.562 12.51 129.6 ;
    END
  END i[48]
  PIN i[49]
    DIRECTION INPUT ;
    USE SIGNAL ;
    PORT
      LAYER M5 ;
        RECT  12.768 129.516 12.792 129.6 ;
    END
  END i[49]
  PIN i[4]
    DIRECTION INPUT ;
    USE SIGNAL ;
    PORT
      LAYER M3 ;
        RECT  1.656 129.562 1.674 129.6 ;
    END
  END i[4]
  PIN i[50]
    DIRECTION INPUT ;
    USE SIGNAL ;
    PORT
      LAYER M3 ;
        RECT  12.996 129.562 13.014 129.6 ;
    END
  END i[50]
  PIN i[51]
    DIRECTION INPUT ;
    USE SIGNAL ;
    PORT
      LAYER M5 ;
        RECT  13.248 129.516 13.272 129.6 ;
    END
  END i[51]
  PIN i[52]
    DIRECTION INPUT ;
    USE SIGNAL ;
    PORT
      LAYER M3 ;
        RECT  13.5 129.562 13.518 129.6 ;
    END
  END i[52]
  PIN i[53]
    DIRECTION INPUT ;
    USE SIGNAL ;
    PORT
      LAYER M5 ;
        RECT  13.728 129.516 13.752 129.6 ;
    END
  END i[53]
  PIN i[54]
    DIRECTION INPUT ;
    USE SIGNAL ;
    PORT
      LAYER M3 ;
        RECT  14.004 129.562 14.022 129.6 ;
    END
  END i[54]
  PIN i[55]
    DIRECTION INPUT ;
    USE SIGNAL ;
    PORT
      LAYER M5 ;
        RECT  14.256 129.516 14.28 129.6 ;
    END
  END i[55]
  PIN i[56]
    DIRECTION INPUT ;
    USE SIGNAL ;
    PORT
      LAYER M3 ;
        RECT  14.472 129.562 14.49 129.6 ;
    END
  END i[56]
  PIN i[57]
    DIRECTION INPUT ;
    USE SIGNAL ;
    PORT
      LAYER M5 ;
        RECT  14.736 129.516 14.76 129.6 ;
    END
  END i[57]
  PIN i[58]
    DIRECTION INPUT ;
    USE SIGNAL ;
    PORT
      LAYER M3 ;
        RECT  14.976 129.562 14.994 129.6 ;
    END
  END i[58]
  PIN i[59]
    DIRECTION INPUT ;
    USE SIGNAL ;
    PORT
      LAYER M5 ;
        RECT  15.216 129.516 15.24 129.6 ;
    END
  END i[59]
  PIN i[5]
    DIRECTION INPUT ;
    USE SIGNAL ;
    PORT
      LAYER M5 ;
        RECT  1.872 129.516 1.896 129.6 ;
    END
  END i[5]
  PIN i[60]
    DIRECTION INPUT ;
    USE SIGNAL ;
    PORT
      LAYER M3 ;
        RECT  15.48 129.562 15.498 129.6 ;
    END
  END i[60]
  PIN i[61]
    DIRECTION INPUT ;
    USE SIGNAL ;
    PORT
      LAYER M5 ;
        RECT  15.696 129.516 15.72 129.6 ;
    END
  END i[61]
  PIN i[62]
    DIRECTION INPUT ;
    USE SIGNAL ;
    PORT
      LAYER M3 ;
        RECT  15.984 129.562 16.002 129.6 ;
    END
  END i[62]
  PIN i[63]
    DIRECTION INPUT ;
    USE SIGNAL ;
    PORT
      LAYER M5 ;
        RECT  16.224 129.516 16.248 129.6 ;
    END
  END i[63]
  PIN i[64]
    DIRECTION INPUT ;
    USE SIGNAL ;
    PORT
      LAYER M3 ;
        RECT  16.452 129.562 16.47 129.6 ;
    END
  END i[64]
  PIN i[65]
    DIRECTION INPUT ;
    USE SIGNAL ;
    PORT
      LAYER M5 ;
        RECT  16.704 129.516 16.728 129.6 ;
    END
  END i[65]
  PIN i[66]
    DIRECTION INPUT ;
    USE SIGNAL ;
    PORT
      LAYER M3 ;
        RECT  16.956 129.562 16.974 129.6 ;
    END
  END i[66]
  PIN i[67]
    DIRECTION INPUT ;
    USE SIGNAL ;
    PORT
      LAYER M5 ;
        RECT  17.184 129.516 17.208 129.6 ;
    END
  END i[67]
  PIN i[68]
    DIRECTION INPUT ;
    USE SIGNAL ;
    PORT
      LAYER M3 ;
        RECT  17.46 129.562 17.478 129.6 ;
    END
  END i[68]
  PIN i[69]
    DIRECTION INPUT ;
    USE SIGNAL ;
    PORT
      LAYER M5 ;
        RECT  17.712 129.516 17.736 129.6 ;
    END
  END i[69]
  PIN i[6]
    DIRECTION INPUT ;
    USE SIGNAL ;
    PORT
      LAYER M3 ;
        RECT  2.124 129.562 2.142 129.6 ;
    END
  END i[6]
  PIN i[70]
    DIRECTION INPUT ;
    USE SIGNAL ;
    PORT
      LAYER M3 ;
        RECT  17.928 129.562 17.946 129.6 ;
    END
  END i[70]
  PIN i[71]
    DIRECTION INPUT ;
    USE SIGNAL ;
    PORT
      LAYER M5 ;
        RECT  18.192 129.516 18.216 129.6 ;
    END
  END i[71]
  PIN i[72]
    DIRECTION INPUT ;
    USE SIGNAL ;
    PORT
      LAYER M3 ;
        RECT  18.432 129.562 18.45 129.6 ;
    END
  END i[72]
  PIN i[73]
    DIRECTION INPUT ;
    USE SIGNAL ;
    PORT
      LAYER M5 ;
        RECT  18.672 129.516 18.696 129.6 ;
    END
  END i[73]
  PIN i[74]
    DIRECTION INPUT ;
    USE SIGNAL ;
    PORT
      LAYER M3 ;
        RECT  18.936 129.562 18.954 129.6 ;
    END
  END i[74]
  PIN i[75]
    DIRECTION INPUT ;
    USE SIGNAL ;
    PORT
      LAYER M5 ;
        RECT  19.152 129.516 19.176 129.6 ;
    END
  END i[75]
  PIN i[76]
    DIRECTION INPUT ;
    USE SIGNAL ;
    PORT
      LAYER M3 ;
        RECT  19.44 129.562 19.458 129.6 ;
    END
  END i[76]
  PIN i[77]
    DIRECTION INPUT ;
    USE SIGNAL ;
    PORT
      LAYER M5 ;
        RECT  19.68 129.516 19.704 129.6 ;
    END
  END i[77]
  PIN i[78]
    DIRECTION INPUT ;
    USE SIGNAL ;
    PORT
      LAYER M3 ;
        RECT  19.908 129.562 19.926 129.6 ;
    END
  END i[78]
  PIN i[79]
    DIRECTION INPUT ;
    USE SIGNAL ;
    PORT
      LAYER M5 ;
        RECT  20.16 129.516 20.184 129.6 ;
    END
  END i[79]
  PIN i[7]
    DIRECTION INPUT ;
    USE SIGNAL ;
    PORT
      LAYER M5 ;
        RECT  2.4 129.516 2.424 129.6 ;
    END
  END i[7]
  PIN i[80]
    DIRECTION INPUT ;
    USE SIGNAL ;
    PORT
      LAYER M3 ;
        RECT  20.412 129.562 20.43 129.6 ;
    END
  END i[80]
  PIN i[81]
    DIRECTION INPUT ;
    USE SIGNAL ;
    PORT
      LAYER M5 ;
        RECT  20.64 129.516 20.664 129.6 ;
    END
  END i[81]
  PIN i[82]
    DIRECTION INPUT ;
    USE SIGNAL ;
    PORT
      LAYER M3 ;
        RECT  20.916 129.562 20.934 129.6 ;
    END
  END i[82]
  PIN i[83]
    DIRECTION INPUT ;
    USE SIGNAL ;
    PORT
      LAYER M5 ;
        RECT  21.168 129.516 21.192 129.6 ;
    END
  END i[83]
  PIN i[84]
    DIRECTION INPUT ;
    USE SIGNAL ;
    PORT
      LAYER M3 ;
        RECT  21.384 129.562 21.402 129.6 ;
    END
  END i[84]
  PIN i[85]
    DIRECTION INPUT ;
    USE SIGNAL ;
    PORT
      LAYER M5 ;
        RECT  21.648 129.516 21.672 129.6 ;
    END
  END i[85]
  PIN i[86]
    DIRECTION INPUT ;
    USE SIGNAL ;
    PORT
      LAYER M3 ;
        RECT  21.888 129.562 21.906 129.6 ;
    END
  END i[86]
  PIN i[87]
    DIRECTION INPUT ;
    USE SIGNAL ;
    PORT
      LAYER M5 ;
        RECT  22.128 129.516 22.152 129.6 ;
    END
  END i[87]
  PIN i[88]
    DIRECTION INPUT ;
    USE SIGNAL ;
    PORT
      LAYER M3 ;
        RECT  22.392 129.562 22.41 129.6 ;
    END
  END i[88]
  PIN i[89]
    DIRECTION INPUT ;
    USE SIGNAL ;
    PORT
      LAYER M5 ;
        RECT  22.656 129.516 22.68 129.6 ;
    END
  END i[89]
  PIN i[8]
    DIRECTION INPUT ;
    USE SIGNAL ;
    PORT
      LAYER M3 ;
        RECT  2.628 129.562 2.646 129.6 ;
    END
  END i[8]
  PIN i[90]
    DIRECTION INPUT ;
    USE SIGNAL ;
    PORT
      LAYER M3 ;
        RECT  22.896 129.562 22.914 129.6 ;
    END
  END i[90]
  PIN i[91]
    DIRECTION INPUT ;
    USE SIGNAL ;
    PORT
      LAYER M5 ;
        RECT  23.136 129.516 23.16 129.6 ;
    END
  END i[91]
  PIN i[92]
    DIRECTION INPUT ;
    USE SIGNAL ;
    PORT
      LAYER M3 ;
        RECT  23.364 129.562 23.382 129.6 ;
    END
  END i[92]
  PIN i[93]
    DIRECTION INPUT ;
    USE SIGNAL ;
    PORT
      LAYER M5 ;
        RECT  23.616 129.516 23.64 129.6 ;
    END
  END i[93]
  PIN i[94]
    DIRECTION INPUT ;
    USE SIGNAL ;
    PORT
      LAYER M3 ;
        RECT  23.868 129.562 23.886 129.6 ;
    END
  END i[94]
  PIN i[95]
    DIRECTION INPUT ;
    USE SIGNAL ;
    PORT
      LAYER M5 ;
        RECT  24.096 129.516 24.12 129.6 ;
    END
  END i[95]
  PIN i[96]
    DIRECTION INPUT ;
    USE SIGNAL ;
    PORT
      LAYER M3 ;
        RECT  24.372 129.562 24.39 129.6 ;
    END
  END i[96]
  PIN i[97]
    DIRECTION INPUT ;
    USE SIGNAL ;
    PORT
      LAYER M5 ;
        RECT  24.624 129.516 24.648 129.6 ;
    END
  END i[97]
  PIN i[98]
    DIRECTION INPUT ;
    USE SIGNAL ;
    PORT
      LAYER M3 ;
        RECT  24.876 129.562 24.894 129.6 ;
    END
  END i[98]
  PIN i[99]
    DIRECTION INPUT ;
    USE SIGNAL ;
    PORT
      LAYER M5 ;
        RECT  25.104 129.516 25.128 129.6 ;
    END
  END i[99]
  PIN i[9]
    DIRECTION INPUT ;
    USE SIGNAL ;
    PORT
      LAYER M5 ;
        RECT  2.88 129.516 2.904 129.6 ;
    END
  END i[9]
  PIN rsi
    DIRECTION INPUT ;
    USE SIGNAL ;
    PORT
      LAYER M3 ;
        RECT  35.1 0 35.118 0.038 ;
    END
  END rsi
  PIN vld[0]
    DIRECTION OUTPUT ;
    USE SIGNAL ;
    PORT
      LAYER M3 ;
        RECT  40.104 0 40.122 0.038 ;
    END
  END vld[0]
  PIN vld[10]
    DIRECTION OUTPUT ;
    USE SIGNAL ;
    PORT
      LAYER M3 ;
        RECT  42.372 0 42.39 0.038 ;
    END
  END vld[10]
  PIN vld[11]
    DIRECTION OUTPUT ;
    USE SIGNAL ;
    PORT
      LAYER M5 ;
        RECT  42.624 0 42.648 0.084 ;
    END
  END vld[11]
  PIN vld[12]
    DIRECTION OUTPUT ;
    USE SIGNAL ;
    PORT
      LAYER M3 ;
        RECT  42.84 0 42.858 0.038 ;
    END
  END vld[12]
  PIN vld[13]
    DIRECTION OUTPUT ;
    USE SIGNAL ;
    PORT
      LAYER M5 ;
        RECT  43.056 0 43.08 0.084 ;
    END
  END vld[13]
  PIN vld[14]
    DIRECTION OUTPUT ;
    USE SIGNAL ;
    PORT
      LAYER M3 ;
        RECT  43.272 0 43.29 0.038 ;
    END
  END vld[14]
  PIN vld[15]
    DIRECTION OUTPUT ;
    USE SIGNAL ;
    PORT
      LAYER M5 ;
        RECT  43.488 0 43.512 0.084 ;
    END
  END vld[15]
  PIN vld[16]
    DIRECTION OUTPUT ;
    USE SIGNAL ;
    PORT
      LAYER M3 ;
        RECT  43.74 0 43.758 0.038 ;
    END
  END vld[16]
  PIN vld[17]
    DIRECTION OUTPUT ;
    USE SIGNAL ;
    PORT
      LAYER M5 ;
        RECT  43.968 0 43.992 0.084 ;
    END
  END vld[17]
  PIN vld[18]
    DIRECTION OUTPUT ;
    USE SIGNAL ;
    PORT
      LAYER M3 ;
        RECT  44.208 0 44.226 0.038 ;
    END
  END vld[18]
  PIN vld[19]
    DIRECTION OUTPUT ;
    USE SIGNAL ;
    PORT
      LAYER M5 ;
        RECT  44.4 0 44.424 0.084 ;
    END
  END vld[19]
  PIN vld[1]
    DIRECTION OUTPUT ;
    USE SIGNAL ;
    PORT
      LAYER M5 ;
        RECT  40.32 0 40.344 0.084 ;
    END
  END vld[1]
  PIN vld[20]
    DIRECTION OUTPUT ;
    USE SIGNAL ;
    PORT
      LAYER M3 ;
        RECT  44.64 0 44.658 0.038 ;
    END
  END vld[20]
  PIN vld[21]
    DIRECTION OUTPUT ;
    USE SIGNAL ;
    PORT
      LAYER M5 ;
        RECT  44.88 0 44.904 0.084 ;
    END
  END vld[21]
  PIN vld[22]
    DIRECTION OUTPUT ;
    USE SIGNAL ;
    PORT
      LAYER M3 ;
        RECT  45.108 0 45.126 0.038 ;
    END
  END vld[22]
  PIN vld[23]
    DIRECTION OUTPUT ;
    USE SIGNAL ;
    PORT
      LAYER M5 ;
        RECT  45.312 0 45.336 0.084 ;
    END
  END vld[23]
  PIN vld[24]
    DIRECTION OUTPUT ;
    USE SIGNAL ;
    PORT
      LAYER M3 ;
        RECT  45.576 0 45.594 0.038 ;
    END
  END vld[24]
  PIN vld[25]
    DIRECTION OUTPUT ;
    USE SIGNAL ;
    PORT
      LAYER M5 ;
        RECT  45.792 0 45.816 0.084 ;
    END
  END vld[25]
  PIN vld[26]
    DIRECTION OUTPUT ;
    USE SIGNAL ;
    PORT
      LAYER M3 ;
        RECT  46.008 0 46.026 0.038 ;
    END
  END vld[26]
  PIN vld[27]
    DIRECTION OUTPUT ;
    USE SIGNAL ;
    PORT
      LAYER M5 ;
        RECT  46.224 0 46.248 0.084 ;
    END
  END vld[27]
  PIN vld[28]
    DIRECTION OUTPUT ;
    USE SIGNAL ;
    PORT
      LAYER M3 ;
        RECT  46.476 0 46.494 0.038 ;
    END
  END vld[28]
  PIN vld[29]
    DIRECTION OUTPUT ;
    USE SIGNAL ;
    PORT
      LAYER M5 ;
        RECT  46.704 0 46.728 0.084 ;
    END
  END vld[29]
  PIN vld[2]
    DIRECTION OUTPUT ;
    USE SIGNAL ;
    PORT
      LAYER M3 ;
        RECT  40.572 0 40.59 0.038 ;
    END
  END vld[2]
  PIN vld[30]
    DIRECTION OUTPUT ;
    USE SIGNAL ;
    PORT
      LAYER M3 ;
        RECT  46.908 0 46.926 0.038 ;
    END
  END vld[30]
  PIN vld[31]
    DIRECTION OUTPUT ;
    USE SIGNAL ;
    PORT
      LAYER M5 ;
        RECT  47.136 0 47.16 0.084 ;
    END
  END vld[31]
  PIN vld[32]
    DIRECTION OUTPUT ;
    USE SIGNAL ;
    PORT
      LAYER M3 ;
        RECT  47.376 0 47.394 0.038 ;
    END
  END vld[32]
  PIN vld[33]
    DIRECTION OUTPUT ;
    USE SIGNAL ;
    PORT
      LAYER M5 ;
        RECT  47.616 0 47.64 0.084 ;
    END
  END vld[33]
  PIN vld[34]
    DIRECTION OUTPUT ;
    USE SIGNAL ;
    PORT
      LAYER M3 ;
        RECT  47.844 0 47.862 0.038 ;
    END
  END vld[34]
  PIN vld[35]
    DIRECTION OUTPUT ;
    USE SIGNAL ;
    PORT
      LAYER M5 ;
        RECT  48.048 0 48.072 0.084 ;
    END
  END vld[35]
  PIN vld[36]
    DIRECTION OUTPUT ;
    USE SIGNAL ;
    PORT
      LAYER M3 ;
        RECT  48.276 0 48.294 0.038 ;
    END
  END vld[36]
  PIN vld[37]
    DIRECTION OUTPUT ;
    USE SIGNAL ;
    PORT
      LAYER M5 ;
        RECT  48.528 0 48.552 0.084 ;
    END
  END vld[37]
  PIN vld[38]
    DIRECTION OUTPUT ;
    USE SIGNAL ;
    PORT
      LAYER M3 ;
        RECT  48.744 0 48.762 0.038 ;
    END
  END vld[38]
  PIN vld[39]
    DIRECTION OUTPUT ;
    USE SIGNAL ;
    PORT
      LAYER M5 ;
        RECT  48.96 0 48.984 0.084 ;
    END
  END vld[39]
  PIN vld[3]
    DIRECTION OUTPUT ;
    USE SIGNAL ;
    PORT
      LAYER M5 ;
        RECT  40.8 0 40.824 0.084 ;
    END
  END vld[3]
  PIN vld[40]
    DIRECTION OUTPUT ;
    USE SIGNAL ;
    PORT
      LAYER M3 ;
        RECT  49.212 0 49.23 0.038 ;
    END
  END vld[40]
  PIN vld[41]
    DIRECTION OUTPUT ;
    USE SIGNAL ;
    PORT
      LAYER M5 ;
        RECT  49.44 0 49.464 0.084 ;
    END
  END vld[41]
  PIN vld[42]
    DIRECTION OUTPUT ;
    USE SIGNAL ;
    PORT
      LAYER M3 ;
        RECT  49.644 0 49.662 0.038 ;
    END
  END vld[42]
  PIN vld[43]
    DIRECTION OUTPUT ;
    USE SIGNAL ;
    PORT
      LAYER M5 ;
        RECT  49.872 0 49.896 0.084 ;
    END
  END vld[43]
  PIN vld[4]
    DIRECTION OUTPUT ;
    USE SIGNAL ;
    PORT
      LAYER M3 ;
        RECT  41.004 0 41.022 0.038 ;
    END
  END vld[4]
  PIN vld[5]
    DIRECTION OUTPUT ;
    USE SIGNAL ;
    PORT
      LAYER M5 ;
        RECT  41.232 0 41.256 0.084 ;
    END
  END vld[5]
  PIN vld[6]
    DIRECTION OUTPUT ;
    USE SIGNAL ;
    PORT
      LAYER M3 ;
        RECT  41.472 0 41.49 0.038 ;
    END
  END vld[6]
  PIN vld[7]
    DIRECTION OUTPUT ;
    USE SIGNAL ;
    PORT
      LAYER M5 ;
        RECT  41.712 0 41.736 0.084 ;
    END
  END vld[7]
  PIN vld[8]
    DIRECTION OUTPUT ;
    USE SIGNAL ;
    PORT
      LAYER M3 ;
        RECT  41.94 0 41.958 0.038 ;
    END
  END vld[8]
  PIN vld[9]
    DIRECTION OUTPUT ;
    USE SIGNAL ;
    PORT
      LAYER M5 ;
        RECT  42.144 0 42.168 0.084 ;
    END
  END vld[9]
  PIN VDD
    DIRECTION INOUT ;
    USE POWER ;
    PORT
      LAYER M5 ;
        RECT  61.992 2.151 62.112 127.449 ;
        RECT  56.592 2.151 56.712 127.449 ;
        RECT  51.192 2.151 51.312 127.449 ;
        RECT  45.792 2.151 45.912 127.449 ;
        RECT  40.392 2.151 40.512 127.449 ;
        RECT  34.992 2.151 35.112 127.449 ;
        RECT  29.592 2.151 29.712 127.449 ;
        RECT  24.192 2.151 24.312 127.449 ;
        RECT  18.792 2.151 18.912 127.449 ;
        RECT  13.392 2.151 13.512 127.449 ;
        RECT  7.992 2.151 8.112 127.449 ;
        RECT  2.592 2.151 2.712 127.449 ;
    END
  END VDD
  PIN VSS
    DIRECTION INOUT ;
    USE GROUND ;
    PORT
      LAYER M5 ;
        RECT  61.8 2.137 61.92 127.463 ;
        RECT  56.4 2.137 56.52 127.463 ;
        RECT  51 2.137 51.12 127.463 ;
        RECT  45.6 2.137 45.72 127.463 ;
        RECT  40.2 2.137 40.32 127.463 ;
        RECT  34.8 2.137 34.92 127.463 ;
        RECT  29.4 2.137 29.52 127.463 ;
        RECT  24 2.137 24.12 127.463 ;
        RECT  18.6 2.137 18.72 127.463 ;
        RECT  13.2 2.137 13.32 127.463 ;
        RECT  7.8 2.137 7.92 127.463 ;
        RECT  2.4 2.137 2.52 127.463 ;
    END
  END VSS
  OBS
    LAYER RVTN ;
     RECT  2.16 2.16 62.64 2.295 ;
     RECT  2.16 2.565 62.64 2.835 ;
     RECT  2.16 3.105 62.64 3.375 ;
     RECT  2.16 3.645 62.64 3.915 ;
     RECT  2.16 4.185 62.64 4.455 ;
     RECT  2.16 4.725 62.64 4.995 ;
     RECT  2.16 5.265 62.64 5.535 ;
     RECT  2.16 5.805 62.64 6.075 ;
     RECT  2.16 6.345 62.64 6.615 ;
     RECT  2.16 6.885 62.64 7.155 ;
     RECT  2.16 7.425 62.64 7.695 ;
     RECT  2.16 7.965 62.64 8.235 ;
     RECT  2.16 8.505 62.64 8.775 ;
     RECT  2.16 9.045 62.64 9.315 ;
     RECT  2.16 9.585 62.64 9.855 ;
     RECT  2.16 10.125 62.64 10.395 ;
     RECT  2.16 10.665 62.64 10.935 ;
     RECT  2.16 11.205 62.64 11.475 ;
     RECT  2.16 11.745 62.64 12.015 ;
     RECT  2.16 12.285 62.64 12.555 ;
     RECT  2.16 12.825 62.64 13.095 ;
     RECT  2.16 13.365 62.64 13.635 ;
     RECT  2.16 13.905 62.64 14.175 ;
     RECT  2.16 14.445 62.64 14.715 ;
     RECT  2.16 14.985 62.64 15.255 ;
     RECT  2.16 15.525 62.64 15.795 ;
     RECT  2.16 16.065 62.64 16.335 ;
     RECT  2.16 16.605 62.64 16.875 ;
     RECT  2.16 17.145 62.64 17.415 ;
     RECT  2.16 17.685 62.64 17.955 ;
     RECT  2.16 18.225 62.64 18.495 ;
     RECT  2.16 18.765 62.64 19.035 ;
     RECT  2.16 19.305 62.64 19.575 ;
     RECT  2.16 19.845 62.64 20.115 ;
     RECT  2.16 20.385 62.64 20.655 ;
     RECT  2.16 20.925 62.64 21.195 ;
     RECT  2.16 21.465 62.64 21.735 ;
     RECT  2.16 22.005 62.64 22.275 ;
     RECT  2.16 22.545 62.64 22.815 ;
     RECT  2.16 23.085 62.64 23.355 ;
     RECT  2.16 23.625 62.64 23.895 ;
     RECT  2.16 24.165 62.64 24.435 ;
     RECT  2.16 24.705 62.64 24.975 ;
     RECT  2.16 25.245 62.64 25.515 ;
     RECT  2.16 25.785 62.64 26.055 ;
     RECT  2.16 26.325 62.64 26.595 ;
     RECT  2.16 26.865 62.64 27.135 ;
     RECT  2.16 27.405 62.64 27.675 ;
     RECT  2.16 27.945 62.64 28.215 ;
     RECT  2.16 28.485 62.64 28.755 ;
     RECT  2.16 29.025 62.64 29.295 ;
     RECT  2.16 29.565 62.64 29.835 ;
     RECT  2.16 30.105 62.64 30.375 ;
     RECT  2.16 30.645 62.64 30.915 ;
     RECT  2.16 31.185 62.64 31.455 ;
     RECT  2.16 31.725 62.64 31.995 ;
     RECT  2.16 32.265 62.64 32.535 ;
     RECT  2.16 32.805 62.64 33.075 ;
     RECT  2.16 33.345 62.64 33.615 ;
     RECT  2.16 33.885 62.64 34.155 ;
     RECT  2.16 34.425 62.64 34.695 ;
     RECT  2.16 34.965 62.64 35.235 ;
     RECT  2.16 35.505 62.64 35.775 ;
     RECT  2.16 36.045 62.64 36.315 ;
     RECT  2.16 36.585 62.64 36.855 ;
     RECT  2.16 37.125 62.64 37.395 ;
     RECT  2.16 37.665 62.64 37.935 ;
     RECT  2.16 38.205 62.64 38.475 ;
     RECT  2.16 38.745 62.64 39.015 ;
     RECT  2.16 39.285 62.64 39.555 ;
     RECT  2.16 39.825 62.64 40.095 ;
     RECT  2.16 40.365 62.64 40.635 ;
     RECT  2.16 40.905 62.64 41.175 ;
     RECT  2.16 41.445 62.64 41.715 ;
     RECT  2.16 41.985 62.64 42.255 ;
     RECT  2.16 42.525 62.64 42.795 ;
     RECT  2.16 43.065 62.64 43.335 ;
     RECT  2.16 43.605 62.64 43.875 ;
     RECT  2.16 44.145 62.64 44.415 ;
     RECT  2.16 44.685 62.64 44.955 ;
     RECT  2.16 45.225 62.64 45.495 ;
     RECT  2.16 45.765 62.64 46.035 ;
     RECT  2.16 46.305 62.64 46.575 ;
     RECT  2.16 46.845 62.64 47.115 ;
     RECT  2.16 47.385 62.64 47.655 ;
     RECT  2.16 47.925 62.64 48.195 ;
     RECT  2.16 48.465 62.64 48.735 ;
     RECT  2.16 49.005 62.64 49.275 ;
     RECT  2.16 49.545 62.64 49.815 ;
     RECT  2.16 50.085 62.64 50.355 ;
     RECT  2.16 50.625 62.64 50.895 ;
     RECT  2.16 51.165 62.64 51.435 ;
     RECT  2.16 51.705 62.64 51.975 ;
     RECT  2.16 52.245 62.64 52.515 ;
     RECT  2.16 52.785 62.64 53.055 ;
     RECT  2.16 53.325 62.64 53.595 ;
     RECT  2.16 53.865 62.64 54.135 ;
     RECT  2.16 54.405 62.64 54.675 ;
     RECT  2.16 54.945 62.64 55.215 ;
     RECT  2.16 55.485 62.64 55.755 ;
     RECT  2.16 56.025 62.64 56.295 ;
     RECT  2.16 56.565 62.64 56.835 ;
     RECT  2.16 57.105 62.64 57.375 ;
     RECT  2.16 57.645 62.64 57.915 ;
     RECT  2.16 58.185 62.64 58.455 ;
     RECT  2.16 58.725 62.64 58.995 ;
     RECT  2.16 59.265 62.64 59.535 ;
     RECT  2.16 59.805 62.64 60.075 ;
     RECT  2.16 60.345 62.64 60.615 ;
     RECT  2.16 60.885 62.64 61.155 ;
     RECT  2.16 61.425 62.64 61.695 ;
     RECT  2.16 61.965 62.64 62.235 ;
     RECT  2.16 62.505 62.64 62.775 ;
     RECT  2.16 63.045 62.64 63.315 ;
     RECT  2.16 63.585 62.64 63.855 ;
     RECT  2.16 64.125 62.64 64.395 ;
     RECT  2.16 64.665 62.64 64.935 ;
     RECT  2.16 65.205 62.64 65.475 ;
     RECT  2.16 65.745 62.64 66.015 ;
     RECT  2.16 66.285 62.64 66.555 ;
     RECT  2.16 66.825 62.64 67.095 ;
     RECT  2.16 67.365 62.64 67.635 ;
     RECT  2.16 67.905 62.64 68.175 ;
     RECT  2.16 68.445 62.64 68.715 ;
     RECT  2.16 68.985 62.64 69.255 ;
     RECT  2.16 69.525 62.64 69.795 ;
     RECT  2.16 70.065 62.64 70.335 ;
     RECT  2.16 70.605 62.64 70.875 ;
     RECT  2.16 71.145 62.64 71.415 ;
     RECT  2.16 71.685 62.64 71.955 ;
     RECT  2.16 72.225 62.64 72.495 ;
     RECT  2.16 72.765 62.64 73.035 ;
     RECT  2.16 73.305 62.64 73.575 ;
     RECT  2.16 73.845 62.64 74.115 ;
     RECT  2.16 74.385 62.64 74.655 ;
     RECT  2.16 74.925 62.64 75.195 ;
     RECT  2.16 75.465 62.64 75.735 ;
     RECT  2.16 76.005 62.64 76.275 ;
     RECT  2.16 76.545 62.64 76.815 ;
     RECT  2.16 77.085 62.64 77.355 ;
     RECT  2.16 77.625 62.64 77.895 ;
     RECT  2.16 78.165 62.64 78.435 ;
     RECT  2.16 78.705 62.64 78.975 ;
     RECT  2.16 79.245 62.64 79.515 ;
     RECT  2.16 79.785 62.64 80.055 ;
     RECT  2.16 80.325 62.64 80.595 ;
     RECT  2.16 80.865 62.64 81.135 ;
     RECT  2.16 81.405 62.64 81.675 ;
     RECT  2.16 81.945 62.64 82.215 ;
     RECT  2.16 82.485 62.64 82.755 ;
     RECT  2.16 83.025 62.64 83.295 ;
     RECT  2.16 83.565 62.64 83.835 ;
     RECT  2.16 84.105 62.64 84.375 ;
     RECT  2.16 84.645 62.64 84.915 ;
     RECT  2.16 85.185 62.64 85.455 ;
     RECT  2.16 85.725 62.64 85.995 ;
     RECT  2.16 86.265 62.64 86.535 ;
     RECT  2.16 86.805 62.64 87.075 ;
     RECT  2.16 87.345 62.64 87.615 ;
     RECT  2.16 87.885 62.64 88.155 ;
     RECT  2.16 88.425 62.64 88.695 ;
     RECT  2.16 88.965 62.64 89.235 ;
     RECT  2.16 89.505 62.64 89.775 ;
     RECT  2.16 90.045 62.64 90.315 ;
     RECT  2.16 90.585 62.64 90.855 ;
     RECT  2.16 91.125 62.64 91.395 ;
     RECT  2.16 91.665 62.64 91.935 ;
     RECT  2.16 92.205 62.64 92.475 ;
     RECT  2.16 92.745 62.64 93.015 ;
     RECT  2.16 93.285 62.64 93.555 ;
     RECT  2.16 93.825 62.64 94.095 ;
     RECT  2.16 94.365 62.64 94.635 ;
     RECT  2.16 94.905 62.64 95.175 ;
     RECT  2.16 95.445 62.64 95.715 ;
     RECT  2.16 95.985 62.64 96.255 ;
     RECT  2.16 96.525 62.64 96.795 ;
     RECT  2.16 97.065 62.64 97.335 ;
     RECT  2.16 97.605 62.64 97.875 ;
     RECT  2.16 98.145 62.64 98.415 ;
     RECT  2.16 98.685 62.64 98.955 ;
     RECT  2.16 99.225 62.64 99.495 ;
     RECT  2.16 99.765 62.64 100.035 ;
     RECT  2.16 100.305 62.64 100.575 ;
     RECT  2.16 100.845 62.64 101.115 ;
     RECT  2.16 101.385 62.64 101.655 ;
     RECT  2.16 101.925 62.64 102.195 ;
     RECT  2.16 102.465 62.64 102.735 ;
     RECT  2.16 103.005 62.64 103.275 ;
     RECT  2.16 103.545 62.64 103.815 ;
     RECT  2.16 104.085 62.64 104.355 ;
     RECT  2.16 104.625 62.64 104.895 ;
     RECT  2.16 105.165 62.64 105.435 ;
     RECT  2.16 105.705 62.64 105.975 ;
     RECT  2.16 106.245 62.64 106.515 ;
     RECT  2.16 106.785 62.64 107.055 ;
     RECT  2.16 107.325 62.64 107.595 ;
     RECT  2.16 107.865 62.64 108.135 ;
     RECT  2.16 108.405 62.64 108.675 ;
     RECT  2.16 108.945 62.64 109.215 ;
     RECT  2.16 109.485 62.64 109.755 ;
     RECT  2.16 110.025 62.64 110.295 ;
     RECT  2.16 110.565 62.64 110.835 ;
     RECT  2.16 111.105 62.64 111.375 ;
     RECT  2.16 111.645 62.64 111.915 ;
     RECT  2.16 112.185 62.64 112.455 ;
     RECT  2.16 112.725 62.64 112.995 ;
     RECT  2.16 113.265 62.64 113.535 ;
     RECT  2.16 113.805 62.64 114.075 ;
     RECT  2.16 114.345 62.64 114.615 ;
     RECT  2.16 114.885 62.64 115.155 ;
     RECT  2.16 115.425 62.64 115.695 ;
     RECT  2.16 115.965 62.64 116.235 ;
     RECT  2.16 116.505 62.64 116.775 ;
     RECT  2.16 117.045 62.64 117.315 ;
     RECT  2.16 117.585 62.64 117.855 ;
     RECT  2.16 118.125 62.64 118.395 ;
     RECT  2.16 118.665 62.64 118.935 ;
     RECT  2.16 119.205 62.64 119.475 ;
     RECT  2.16 119.745 62.64 120.015 ;
     RECT  2.16 120.285 62.64 120.555 ;
     RECT  2.16 120.825 62.64 121.095 ;
     RECT  2.16 121.365 62.64 121.635 ;
     RECT  2.16 121.905 62.64 122.175 ;
     RECT  2.16 122.445 62.64 122.715 ;
     RECT  2.16 122.985 62.64 123.255 ;
     RECT  2.16 123.525 62.64 123.795 ;
     RECT  2.16 124.065 62.64 124.335 ;
     RECT  2.16 124.605 62.64 124.875 ;
     RECT  2.16 125.145 62.64 125.415 ;
     RECT  2.16 125.685 62.64 125.955 ;
     RECT  2.16 126.225 62.64 126.495 ;
     RECT  2.16 126.765 62.64 127.035 ;
     RECT  2.16 127.305 62.64 127.44 ;
    LAYER RVTP ;
     RECT  2.16 2.295 62.64 2.565 ;
     RECT  2.16 2.835 62.64 3.105 ;
     RECT  2.16 3.375 62.64 3.645 ;
     RECT  2.16 3.915 62.64 4.185 ;
     RECT  2.16 4.455 62.64 4.725 ;
     RECT  2.16 4.995 62.64 5.265 ;
     RECT  2.16 5.535 62.64 5.805 ;
     RECT  2.16 6.075 62.64 6.345 ;
     RECT  2.16 6.615 62.64 6.885 ;
     RECT  2.16 7.155 62.64 7.425 ;
     RECT  2.16 7.695 62.64 7.965 ;
     RECT  2.16 8.235 62.64 8.505 ;
     RECT  2.16 8.775 62.64 9.045 ;
     RECT  2.16 9.315 62.64 9.585 ;
     RECT  2.16 9.855 62.64 10.125 ;
     RECT  2.16 10.395 62.64 10.665 ;
     RECT  2.16 10.935 62.64 11.205 ;
     RECT  2.16 11.475 62.64 11.745 ;
     RECT  2.16 12.015 62.64 12.285 ;
     RECT  2.16 12.555 62.64 12.825 ;
     RECT  2.16 13.095 62.64 13.365 ;
     RECT  2.16 13.635 62.64 13.905 ;
     RECT  2.16 14.175 62.64 14.445 ;
     RECT  2.16 14.715 62.64 14.985 ;
     RECT  2.16 15.255 62.64 15.525 ;
     RECT  2.16 15.795 62.64 16.065 ;
     RECT  2.16 16.335 62.64 16.605 ;
     RECT  2.16 16.875 62.64 17.145 ;
     RECT  2.16 17.415 62.64 17.685 ;
     RECT  2.16 17.955 62.64 18.225 ;
     RECT  2.16 18.495 62.64 18.765 ;
     RECT  2.16 19.035 62.64 19.305 ;
     RECT  2.16 19.575 62.64 19.845 ;
     RECT  2.16 20.115 62.64 20.385 ;
     RECT  2.16 20.655 62.64 20.925 ;
     RECT  2.16 21.195 62.64 21.465 ;
     RECT  2.16 21.735 62.64 22.005 ;
     RECT  2.16 22.275 62.64 22.545 ;
     RECT  2.16 22.815 62.64 23.085 ;
     RECT  2.16 23.355 62.64 23.625 ;
     RECT  2.16 23.895 62.64 24.165 ;
     RECT  2.16 24.435 62.64 24.705 ;
     RECT  2.16 24.975 62.64 25.245 ;
     RECT  2.16 25.515 62.64 25.785 ;
     RECT  2.16 26.055 62.64 26.325 ;
     RECT  2.16 26.595 62.64 26.865 ;
     RECT  2.16 27.135 62.64 27.405 ;
     RECT  2.16 27.675 62.64 27.945 ;
     RECT  2.16 28.215 62.64 28.485 ;
     RECT  2.16 28.755 62.64 29.025 ;
     RECT  2.16 29.295 62.64 29.565 ;
     RECT  2.16 29.835 62.64 30.105 ;
     RECT  2.16 30.375 62.64 30.645 ;
     RECT  2.16 30.915 62.64 31.185 ;
     RECT  2.16 31.455 62.64 31.725 ;
     RECT  2.16 31.995 62.64 32.265 ;
     RECT  2.16 32.535 62.64 32.805 ;
     RECT  2.16 33.075 62.64 33.345 ;
     RECT  2.16 33.615 62.64 33.885 ;
     RECT  2.16 34.155 62.64 34.425 ;
     RECT  2.16 34.695 62.64 34.965 ;
     RECT  2.16 35.235 62.64 35.505 ;
     RECT  2.16 35.775 62.64 36.045 ;
     RECT  2.16 36.315 62.64 36.585 ;
     RECT  2.16 36.855 62.64 37.125 ;
     RECT  2.16 37.395 62.64 37.665 ;
     RECT  2.16 37.935 62.64 38.205 ;
     RECT  2.16 38.475 62.64 38.745 ;
     RECT  2.16 39.015 62.64 39.285 ;
     RECT  2.16 39.555 62.64 39.825 ;
     RECT  2.16 40.095 62.64 40.365 ;
     RECT  2.16 40.635 62.64 40.905 ;
     RECT  2.16 41.175 62.64 41.445 ;
     RECT  2.16 41.715 62.64 41.985 ;
     RECT  2.16 42.255 62.64 42.525 ;
     RECT  2.16 42.795 62.64 43.065 ;
     RECT  2.16 43.335 62.64 43.605 ;
     RECT  2.16 43.875 62.64 44.145 ;
     RECT  2.16 44.415 62.64 44.685 ;
     RECT  2.16 44.955 62.64 45.225 ;
     RECT  2.16 45.495 62.64 45.765 ;
     RECT  2.16 46.035 62.64 46.305 ;
     RECT  2.16 46.575 62.64 46.845 ;
     RECT  2.16 47.115 62.64 47.385 ;
     RECT  2.16 47.655 62.64 47.925 ;
     RECT  2.16 48.195 62.64 48.465 ;
     RECT  2.16 48.735 62.64 49.005 ;
     RECT  2.16 49.275 62.64 49.545 ;
     RECT  2.16 49.815 62.64 50.085 ;
     RECT  2.16 50.355 62.64 50.625 ;
     RECT  2.16 50.895 62.64 51.165 ;
     RECT  2.16 51.435 62.64 51.705 ;
     RECT  2.16 51.975 62.64 52.245 ;
     RECT  2.16 52.515 62.64 52.785 ;
     RECT  2.16 53.055 62.64 53.325 ;
     RECT  2.16 53.595 62.64 53.865 ;
     RECT  2.16 54.135 62.64 54.405 ;
     RECT  2.16 54.675 62.64 54.945 ;
     RECT  2.16 55.215 62.64 55.485 ;
     RECT  2.16 55.755 62.64 56.025 ;
     RECT  2.16 56.295 62.64 56.565 ;
     RECT  2.16 56.835 62.64 57.105 ;
     RECT  2.16 57.375 62.64 57.645 ;
     RECT  2.16 57.915 62.64 58.185 ;
     RECT  2.16 58.455 62.64 58.725 ;
     RECT  2.16 58.995 62.64 59.265 ;
     RECT  2.16 59.535 62.64 59.805 ;
     RECT  2.16 60.075 62.64 60.345 ;
     RECT  2.16 60.615 62.64 60.885 ;
     RECT  2.16 61.155 62.64 61.425 ;
     RECT  2.16 61.695 62.64 61.965 ;
     RECT  2.16 62.235 62.64 62.505 ;
     RECT  2.16 62.775 62.64 63.045 ;
     RECT  2.16 63.315 62.64 63.585 ;
     RECT  2.16 63.855 62.64 64.125 ;
     RECT  2.16 64.395 62.64 64.665 ;
     RECT  2.16 64.935 62.64 65.205 ;
     RECT  2.16 65.475 62.64 65.745 ;
     RECT  2.16 66.015 62.64 66.285 ;
     RECT  2.16 66.555 62.64 66.825 ;
     RECT  2.16 67.095 62.64 67.365 ;
     RECT  2.16 67.635 62.64 67.905 ;
     RECT  2.16 68.175 62.64 68.445 ;
     RECT  2.16 68.715 62.64 68.985 ;
     RECT  2.16 69.255 62.64 69.525 ;
     RECT  2.16 69.795 62.64 70.065 ;
     RECT  2.16 70.335 62.64 70.605 ;
     RECT  2.16 70.875 62.64 71.145 ;
     RECT  2.16 71.415 62.64 71.685 ;
     RECT  2.16 71.955 62.64 72.225 ;
     RECT  2.16 72.495 62.64 72.765 ;
     RECT  2.16 73.035 62.64 73.305 ;
     RECT  2.16 73.575 62.64 73.845 ;
     RECT  2.16 74.115 62.64 74.385 ;
     RECT  2.16 74.655 62.64 74.925 ;
     RECT  2.16 75.195 62.64 75.465 ;
     RECT  2.16 75.735 62.64 76.005 ;
     RECT  2.16 76.275 62.64 76.545 ;
     RECT  2.16 76.815 62.64 77.085 ;
     RECT  2.16 77.355 62.64 77.625 ;
     RECT  2.16 77.895 62.64 78.165 ;
     RECT  2.16 78.435 62.64 78.705 ;
     RECT  2.16 78.975 62.64 79.245 ;
     RECT  2.16 79.515 62.64 79.785 ;
     RECT  2.16 80.055 62.64 80.325 ;
     RECT  2.16 80.595 62.64 80.865 ;
     RECT  2.16 81.135 62.64 81.405 ;
     RECT  2.16 81.675 62.64 81.945 ;
     RECT  2.16 82.215 62.64 82.485 ;
     RECT  2.16 82.755 62.64 83.025 ;
     RECT  2.16 83.295 62.64 83.565 ;
     RECT  2.16 83.835 62.64 84.105 ;
     RECT  2.16 84.375 62.64 84.645 ;
     RECT  2.16 84.915 62.64 85.185 ;
     RECT  2.16 85.455 62.64 85.725 ;
     RECT  2.16 85.995 62.64 86.265 ;
     RECT  2.16 86.535 62.64 86.805 ;
     RECT  2.16 87.075 62.64 87.345 ;
     RECT  2.16 87.615 62.64 87.885 ;
     RECT  2.16 88.155 62.64 88.425 ;
     RECT  2.16 88.695 62.64 88.965 ;
     RECT  2.16 89.235 62.64 89.505 ;
     RECT  2.16 89.775 62.64 90.045 ;
     RECT  2.16 90.315 62.64 90.585 ;
     RECT  2.16 90.855 62.64 91.125 ;
     RECT  2.16 91.395 62.64 91.665 ;
     RECT  2.16 91.935 62.64 92.205 ;
     RECT  2.16 92.475 62.64 92.745 ;
     RECT  2.16 93.015 62.64 93.285 ;
     RECT  2.16 93.555 62.64 93.825 ;
     RECT  2.16 94.095 62.64 94.365 ;
     RECT  2.16 94.635 62.64 94.905 ;
     RECT  2.16 95.175 62.64 95.445 ;
     RECT  2.16 95.715 62.64 95.985 ;
     RECT  2.16 96.255 62.64 96.525 ;
     RECT  2.16 96.795 62.64 97.065 ;
     RECT  2.16 97.335 62.64 97.605 ;
     RECT  2.16 97.875 62.64 98.145 ;
     RECT  2.16 98.415 62.64 98.685 ;
     RECT  2.16 98.955 62.64 99.225 ;
     RECT  2.16 99.495 62.64 99.765 ;
     RECT  2.16 100.035 62.64 100.305 ;
     RECT  2.16 100.575 62.64 100.845 ;
     RECT  2.16 101.115 62.64 101.385 ;
     RECT  2.16 101.655 62.64 101.925 ;
     RECT  2.16 102.195 62.64 102.465 ;
     RECT  2.16 102.735 62.64 103.005 ;
     RECT  2.16 103.275 62.64 103.545 ;
     RECT  2.16 103.815 62.64 104.085 ;
     RECT  2.16 104.355 62.64 104.625 ;
     RECT  2.16 104.895 62.64 105.165 ;
     RECT  2.16 105.435 62.64 105.705 ;
     RECT  2.16 105.975 62.64 106.245 ;
     RECT  2.16 106.515 62.64 106.785 ;
     RECT  2.16 107.055 62.64 107.325 ;
     RECT  2.16 107.595 62.64 107.865 ;
     RECT  2.16 108.135 62.64 108.405 ;
     RECT  2.16 108.675 62.64 108.945 ;
     RECT  2.16 109.215 62.64 109.485 ;
     RECT  2.16 109.755 62.64 110.025 ;
     RECT  2.16 110.295 62.64 110.565 ;
     RECT  2.16 110.835 62.64 111.105 ;
     RECT  2.16 111.375 62.64 111.645 ;
     RECT  2.16 111.915 62.64 112.185 ;
     RECT  2.16 112.455 62.64 112.725 ;
     RECT  2.16 112.995 62.64 113.265 ;
     RECT  2.16 113.535 62.64 113.805 ;
     RECT  2.16 114.075 62.64 114.345 ;
     RECT  2.16 114.615 62.64 114.885 ;
     RECT  2.16 115.155 62.64 115.425 ;
     RECT  2.16 115.695 62.64 115.965 ;
     RECT  2.16 116.235 62.64 116.505 ;
     RECT  2.16 116.775 62.64 117.045 ;
     RECT  2.16 117.315 62.64 117.585 ;
     RECT  2.16 117.855 62.64 118.125 ;
     RECT  2.16 118.395 62.64 118.665 ;
     RECT  2.16 118.935 62.64 119.205 ;
     RECT  2.16 119.475 62.64 119.745 ;
     RECT  2.16 120.015 62.64 120.285 ;
     RECT  2.16 120.555 62.64 120.825 ;
     RECT  2.16 121.095 62.64 121.365 ;
     RECT  2.16 121.635 62.64 121.905 ;
     RECT  2.16 122.175 62.64 122.445 ;
     RECT  2.16 122.715 62.64 122.985 ;
     RECT  2.16 123.255 62.64 123.525 ;
     RECT  2.16 123.795 62.64 124.065 ;
     RECT  2.16 124.335 62.64 124.605 ;
     RECT  2.16 124.875 62.64 125.145 ;
     RECT  2.16 125.415 62.64 125.685 ;
     RECT  2.16 125.955 62.64 126.225 ;
     RECT  2.16 126.495 62.64 126.765 ;
     RECT  2.16 127.035 62.64 127.305 ;
    LAYER M1 ;
     RECT  2.16 2.151 62.64 127.449 ;
    LAYER M2 ;
     RECT  0.031 8.82 0.103 8.838 ;
     RECT  0.103 60.696 0.139 60.714 ;
     RECT  0.103 22.788 0.463 22.806 ;
     RECT  0.103 44.586 0.463 44.604 ;
     RECT  0.103 46.926 0.463 46.944 ;
     RECT  0.103 48.276 0.463 48.294 ;
     RECT  0.103 80.604 0.463 80.622 ;
     RECT  0.463 26.37 0.535 26.388 ;
     RECT  0.463 42.336 0.535 42.354 ;
     RECT  0.463 54.261 0.535 54.279 ;
     RECT  0.103 67.104 0.535 67.122 ;
     RECT  0.103 69.336 0.535 69.354 ;
     RECT  0.463 70.236 0.535 70.254 ;
     RECT  0.463 79.956 0.535 80.622 ;
     RECT  0.103 101.826 0.535 101.844 ;
     RECT  0.499 115.596 0.535 115.614 ;
     RECT  0.499 117.756 0.535 117.774 ;
     RECT  0.499 119.016 0.535 119.034 ;
     RECT  0.103 121.176 0.535 121.194 ;
     RECT  0.499 123.534 0.535 123.552 ;
     RECT  0.535 26.064 0.563 26.388 ;
     RECT  0.463 40.986 0.563 41.004 ;
     RECT  0.535 42.156 0.563 42.354 ;
     RECT  0.463 44.586 0.563 45.054 ;
     RECT  0.463 46.926 0.563 48.294 ;
     RECT  0.463 53.028 0.563 53.046 ;
     RECT  0.535 54.036 0.563 54.279 ;
     RECT  0.535 69.336 0.563 70.254 ;
     RECT  0.463 76.986 0.563 77.004 ;
     RECT  0.535 79.686 0.563 80.622 ;
     RECT  0.535 20.664 0.571 20.682 ;
     RECT  0.535 90.594 1.075 91.188 ;
     RECT  0.463 22.788 1.111 22.842 ;
     RECT  0.563 69.336 1.147 69.786 ;
     RECT  1.147 68.994 1.247 69.786 ;
     RECT  0.535 123.534 1.399 125.208 ;
     RECT  1.075 28.458 1.687 28.476 ;
     RECT  1.075 90.594 1.687 91.35 ;
     RECT  1.247 68.994 1.939 69.624 ;
     RECT  0.563 79.686 2.047 79.704 ;
     RECT  0.535 83.268 2.047 83.286 ;
     RECT  1.111 86.238 2.047 86.256 ;
     RECT  0.535 87.084 2.047 87.102 ;
     RECT  0.535 95.148 2.047 95.166 ;
     RECT  2.083 70.956 2.155 70.974 ;
     RECT  1.543 3.186 2.16 3.204 ;
     RECT  0.535 6.156 2.16 6.174 ;
     RECT  0.103 8.046 2.16 8.064 ;
     RECT  0.103 8.82 2.16 8.874 ;
     RECT  0.103 12.636 2.16 12.654 ;
     RECT  0.571 20.664 2.16 21.294 ;
     RECT  1.111 22.788 2.16 23.076 ;
     RECT  0.535 25.056 2.16 25.074 ;
     RECT  0.563 26.064 2.16 26.082 ;
     RECT  1.687 28.458 2.16 29.052 ;
     RECT  0.103 31.896 2.16 31.914 ;
     RECT  0.103 36.126 2.16 36.144 ;
     RECT  0.563 42.156 2.16 42.174 ;
     RECT  0.563 44.586 2.16 44.604 ;
     RECT  0.563 46.926 2.16 47.304 ;
     RECT  0.563 48.276 2.16 48.294 ;
     RECT  0.563 54.036 2.16 54.054 ;
     RECT  0.103 55.224 2.16 55.242 ;
     RECT  0.103 56.916 2.16 56.934 ;
     RECT  0.139 60.696 2.16 60.984 ;
     RECT  0.103 61.776 2.16 61.794 ;
     RECT  0.103 64.746 2.16 66.114 ;
     RECT  0.535 67.104 2.16 67.824 ;
     RECT  1.939 68.724 2.16 69.624 ;
     RECT  2.155 70.65 2.16 70.974 ;
     RECT  1.723 74.088 2.16 74.106 ;
     RECT  1.723 75.006 2.16 75.024 ;
     RECT  1.831 76.086 2.16 76.104 ;
     RECT  2.047 79.524 2.16 79.704 ;
     RECT  0.563 80.604 2.16 80.622 ;
     RECT  2.047 82.656 2.16 83.286 ;
     RECT  0.535 84.276 2.16 84.294 ;
     RECT  2.047 86.238 2.16 87.102 ;
     RECT  0.535 88.326 2.16 88.344 ;
     RECT  0.535 89.316 2.16 89.334 ;
     RECT  1.687 90.594 2.16 91.494 ;
     RECT  2.047 94.536 2.16 95.202 ;
     RECT  0.535 97.416 2.16 97.434 ;
     RECT  0.535 99.036 2.16 99.054 ;
     RECT  0.535 100.116 2.16 100.134 ;
     RECT  0.535 101.394 2.16 101.844 ;
     RECT  0.535 103.716 2.16 103.734 ;
     RECT  0.535 105.984 2.16 106.002 ;
     RECT  0.535 107.676 2.16 107.694 ;
     RECT  0.535 108.846 2.16 109.854 ;
     RECT  0.535 113.886 2.16 116.262 ;
     RECT  0.535 117.126 2.16 117.954 ;
     RECT  0.535 119.016 2.16 120.204 ;
     RECT  0.535 121.176 2.16 121.932 ;
     RECT  1.399 123.534 2.16 125.946 ;
     RECT  1.687 126.774 2.16 126.792 ;
     RECT  2.16 2.151 2.263 127.449 ;
     RECT  2.263 2.151 4.631 127.944 ;
     RECT  4.631 2.151 7.555 127.449 ;
     RECT  7.555 2.151 8.059 127.719 ;
     RECT  8.563 128.781 9.095 128.799 ;
     RECT  8.059 2.151 10.039 127.764 ;
     RECT  10.039 2.151 10.139 127.8 ;
     RECT  15.871 128.826 16.007 128.844 ;
     RECT  30.739 128.826 30.803 128.844 ;
     RECT  35.095 0.036 35.195 0.054 ;
     RECT  38.083 128.826 38.219 128.844 ;
     RECT  41.107 0.036 41.963 0.054 ;
     RECT  10.139 2.151 45.607 127.449 ;
     RECT  45.607 2.151 45.779 127.53 ;
     RECT  47.335 0.036 47.399 0.054 ;
     RECT  45.779 2.151 50.935 127.449 ;
     RECT  50.935 2.151 51.071 127.53 ;
     RECT  56.479 129.546 56.579 129.564 ;
     RECT  51.071 2.151 61.159 127.449 ;
     RECT  61.159 2.151 62.64 127.566 ;
     RECT  62.64 15.03 62.699 66.474 ;
     RECT  62.64 85.536 62.699 121.464 ;
     RECT  62.64 122.454 62.699 127.566 ;
     RECT  62.699 15.03 62.735 30.096 ;
     RECT  62.699 30.96 62.735 44.064 ;
     RECT  62.699 45.036 62.735 51.894 ;
     RECT  62.64 73.854 62.735 81.234 ;
     RECT  62.64 82.296 62.735 84.744 ;
     RECT  62.699 85.536 62.735 110.016 ;
     RECT  62.735 89.316 62.771 101.448 ;
     RECT  62.735 48.816 62.807 51.894 ;
     RECT  62.64 2.646 63.275 12.474 ;
     RECT  62.735 15.03 63.275 20.376 ;
     RECT  62.735 21.366 63.275 30.096 ;
     RECT  62.735 31.086 63.275 44.064 ;
     RECT  62.807 48.906 63.275 51.894 ;
     RECT  62.699 53.226 63.275 66.474 ;
     RECT  62.64 67.266 63.275 69.444 ;
     RECT  62.64 70.416 63.275 72.594 ;
     RECT  62.735 82.296 63.275 84.366 ;
     RECT  62.771 89.316 63.275 99.864 ;
     RECT  63.275 22.356 63.311 29.286 ;
     RECT  63.275 31.086 63.311 33.678 ;
     RECT  63.275 34.776 63.311 43.794 ;
     RECT  62.735 45.036 63.311 48.024 ;
     RECT  62.735 75.204 63.311 81.234 ;
     RECT  62.735 85.806 63.311 88.074 ;
     RECT  63.275 89.316 63.311 91.188 ;
     RECT  63.275 92.016 63.311 93.852 ;
     RECT  62.735 102.204 63.311 107.424 ;
     RECT  62.735 108.414 63.311 109.674 ;
     RECT  62.699 110.844 63.311 121.464 ;
     RECT  62.699 122.454 63.311 127.494 ;
     RECT  63.311 111.006 63.347 111.024 ;
     RECT  63.311 112.626 63.347 121.464 ;
     RECT  63.311 39.681 63.383 43.794 ;
     RECT  63.311 78.516 63.383 78.696 ;
     RECT  63.311 92.286 63.383 93.852 ;
     RECT  63.275 94.608 63.383 99.864 ;
     RECT  63.311 124.506 63.383 125.712 ;
     RECT  63.275 2.646 63.815 11.304 ;
     RECT  63.275 12.294 63.815 12.474 ;
     RECT  62.64 13.266 63.815 13.824 ;
     RECT  63.275 60.966 63.815 66.474 ;
     RECT  63.815 2.646 63.851 8.064 ;
     RECT  63.815 9.216 63.851 11.304 ;
     RECT  63.815 12.294 63.851 12.312 ;
     RECT  63.815 13.266 63.851 13.734 ;
     RECT  63.275 15.03 63.851 20.214 ;
     RECT  63.275 21.366 63.851 21.564 ;
     RECT  63.311 22.356 63.851 28.854 ;
     RECT  63.275 30.078 63.851 30.096 ;
     RECT  63.311 31.086 63.851 32.454 ;
     RECT  63.311 33.282 63.851 33.678 ;
     RECT  63.311 34.776 63.851 36.882 ;
     RECT  63.311 37.71 63.851 38.934 ;
     RECT  63.383 39.726 63.851 43.794 ;
     RECT  63.311 45.036 63.851 45.324 ;
     RECT  63.311 46.386 63.851 48.024 ;
     RECT  63.275 49.176 63.851 49.608 ;
     RECT  63.275 53.334 63.851 59.994 ;
     RECT  63.815 60.966 63.851 63.144 ;
     RECT  63.815 64.026 63.851 66.474 ;
     RECT  63.275 67.266 63.851 69.354 ;
     RECT  62.735 73.854 63.851 74.448 ;
     RECT  63.311 75.204 63.851 75.384 ;
     RECT  63.311 89.856 63.851 91.188 ;
     RECT  63.383 92.286 63.851 92.304 ;
     RECT  63.383 94.608 63.851 97.704 ;
     RECT  63.383 98.586 63.851 99.864 ;
     RECT  63.311 102.366 63.851 107.01 ;
     RECT  63.347 113.616 63.851 120.474 ;
     RECT  63.311 122.454 63.851 122.472 ;
     RECT  63.383 124.506 63.851 125.334 ;
     RECT  63.851 10.836 63.887 11.304 ;
     RECT  63.851 15.966 63.887 18.864 ;
     RECT  63.851 23.526 63.887 23.724 ;
     RECT  63.851 25.29 63.887 26.964 ;
     RECT  63.851 31.896 63.887 31.914 ;
     RECT  63.851 33.426 63.887 33.678 ;
     RECT  63.851 36.054 63.887 36.234 ;
     RECT  63.851 39.726 63.887 41.436 ;
     RECT  63.851 43.308 63.887 43.794 ;
     RECT  63.851 47.466 63.887 48.024 ;
     RECT  63.851 53.334 63.887 54.594 ;
     RECT  63.851 55.386 63.887 59.994 ;
     RECT  63.851 67.338 63.887 69.282 ;
     RECT  63.311 76.176 63.887 76.194 ;
     RECT  63.311 77.094 63.887 77.769 ;
     RECT  63.383 78.516 63.887 78.534 ;
     RECT  63.311 79.686 63.887 81.234 ;
     RECT  63.275 83.034 63.887 84.366 ;
     RECT  63.311 87.696 63.887 87.984 ;
     RECT  63.851 90.936 63.887 91.188 ;
     RECT  63.383 93.096 63.887 93.852 ;
     RECT  63.851 94.608 63.887 95.508 ;
     RECT  63.851 96.426 63.887 96.444 ;
     RECT  63.851 97.686 63.887 97.704 ;
     RECT  63.851 99.306 63.887 99.864 ;
     RECT  62.771 100.746 63.887 101.448 ;
     RECT  63.851 103.626 63.887 105.354 ;
     RECT  63.851 106.29 63.887 107.01 ;
     RECT  63.311 109.026 63.887 109.674 ;
     RECT  63.347 112.626 63.887 112.644 ;
     RECT  63.851 113.616 63.887 116.064 ;
     RECT  63.851 116.856 63.887 118.89 ;
     RECT  63.851 120.186 63.887 120.204 ;
     RECT  63.347 121.446 63.887 121.464 ;
     RECT  63.311 123.228 63.887 123.714 ;
     RECT  63.851 125.316 63.887 125.334 ;
     RECT  63.311 127.206 63.887 127.494 ;
     RECT  63.887 84.348 63.895 84.366 ;
     RECT  63.887 56.106 63.923 59.994 ;
     RECT  63.851 64.566 63.923 66.474 ;
     RECT  63.887 104.436 63.923 105.354 ;
     RECT  63.887 118.872 63.923 118.89 ;
     RECT  63.887 123.426 63.923 123.444 ;
     RECT  63.851 124.506 63.923 124.524 ;
     RECT  63.887 40.536 63.959 41.436 ;
     RECT  63.851 102.546 63.959 102.654 ;
     RECT  63.887 103.626 63.959 103.644 ;
     RECT  63.923 104.436 63.959 104.454 ;
     RECT  63.887 127.476 63.959 127.494 ;
     RECT  63.859 128.241 63.959 128.259 ;
     RECT  63.923 64.566 63.995 65.394 ;
     RECT  63.895 84.348 63.995 84.942 ;
     RECT  63.887 94.608 63.995 94.626 ;
     RECT  63.959 102.636 63.995 102.654 ;
     RECT  63.923 105.336 63.995 105.354 ;
     RECT  63.887 77.634 64.067 77.769 ;
     RECT  63.995 84.348 64.067 84.87 ;
     RECT  63.851 3.006 64.643 5.364 ;
     RECT  64.643 3.006 64.679 4.014 ;
     RECT  64.643 4.896 64.679 5.364 ;
     RECT  63.851 6.318 64.679 8.064 ;
     RECT  63.887 10.836 64.679 11.034 ;
     RECT  63.851 15.03 64.679 15.174 ;
     RECT  63.887 15.966 64.679 16.164 ;
     RECT  63.887 17.082 64.679 18.864 ;
     RECT  63.851 20.088 64.679 20.214 ;
     RECT  63.959 41.382 64.679 41.436 ;
     RECT  63.851 49.446 64.679 49.608 ;
     RECT  63.851 61.2 64.679 63.108 ;
     RECT  63.923 66.186 64.679 66.474 ;
     RECT  63.275 72.036 64.679 72.594 ;
     RECT  64.679 3.456 64.715 4.014 ;
     RECT  64.679 4.896 64.715 4.914 ;
     RECT  64.679 6.318 64.715 7.074 ;
     RECT  64.679 8.046 64.715 8.064 ;
     RECT  63.851 9.864 64.715 9.882 ;
     RECT  64.679 11.016 64.715 11.034 ;
     RECT  64.679 15.156 64.715 15.174 ;
     RECT  64.679 15.966 64.715 15.984 ;
     RECT  64.679 17.082 64.715 18.684 ;
     RECT  64.679 20.196 64.715 20.214 ;
     RECT  63.851 21.366 64.715 21.384 ;
     RECT  63.851 22.356 64.715 22.374 ;
     RECT  63.887 23.526 64.715 23.544 ;
     RECT  63.887 26.37 64.715 26.964 ;
     RECT  63.851 28.566 64.715 28.854 ;
     RECT  63.851 31.086 64.715 31.104 ;
     RECT  63.887 36.054 64.715 36.072 ;
     RECT  63.851 37.71 64.715 38.16 ;
     RECT  63.959 40.536 64.715 40.554 ;
     RECT  64.679 41.418 64.715 41.436 ;
     RECT  63.887 43.776 64.715 43.794 ;
     RECT  63.851 45.306 64.715 45.324 ;
     RECT  64.679 49.446 64.715 49.464 ;
     RECT  63.275 50.436 64.715 51.894 ;
     RECT  63.887 54.036 64.715 54.594 ;
     RECT  63.923 56.106 64.715 56.52 ;
     RECT  63.923 57.546 64.715 59.994 ;
     RECT  64.679 61.2 64.715 61.884 ;
     RECT  64.679 62.631 64.715 62.649 ;
     RECT  63.995 64.566 64.715 64.584 ;
     RECT  63.995 65.376 64.715 65.394 ;
     RECT  64.679 66.456 64.715 66.474 ;
     RECT  63.887 68.886 64.715 68.904 ;
     RECT  63.275 70.416 64.715 70.434 ;
     RECT  64.679 72.036 64.715 72.252 ;
     RECT  63.851 73.854 64.715 73.872 ;
     RECT  63.851 75.204 64.715 75.222 ;
     RECT  63.887 83.106 64.715 83.124 ;
     RECT  64.067 84.348 64.715 84.366 ;
     RECT  63.311 86.346 64.715 86.904 ;
     RECT  63.887 91.17 64.715 91.188 ;
     RECT  63.887 93.096 64.715 93.114 ;
     RECT  63.887 99.81 64.715 99.828 ;
     RECT  63.887 101.43 64.715 101.448 ;
     RECT  63.887 106.29 64.715 106.308 ;
     RECT  63.887 114.516 64.715 114.534 ;
     RECT  63.887 117.324 64.715 117.342 ;
    LAYER M3 ;
     RECT  35.1 0.012 35.118 0.031 ;
     RECT  35.1 0.031 35.19 0.059 ;
     RECT  40.104 0.012 49.662 0.091 ;
     RECT  29.7 0.012 29.718 0.125 ;
     RECT  58.104 1.387 58.122 1.627 ;
     RECT  2.304 1.627 2.322 1.915 ;
     RECT  3.132 0.907 3.15 1.915 ;
     RECT  35.172 0.059 35.19 2.143 ;
     RECT  1.548 1.147 1.566 2.155 ;
     RECT  2.304 1.915 3.15 2.155 ;
     RECT  62.964 0.907 62.982 2.395 ;
     RECT  63.828 2.155 63.846 2.395 ;
     RECT  7.815 2.143 7.905 2.413 ;
     RECT  13.215 2.143 13.305 2.413 ;
     RECT  18.615 2.143 18.705 2.413 ;
     RECT  24.015 2.143 24.105 2.413 ;
     RECT  29.415 2.143 29.505 2.413 ;
     RECT  51.015 2.143 51.105 2.413 ;
     RECT  56.415 2.143 56.505 2.413 ;
     RECT  61.815 2.143 61.905 2.413 ;
     RECT  1.548 2.155 3.15 2.491 ;
     RECT  3.924 1.387 3.942 2.491 ;
     RECT  0.108 2.395 0.126 2.525 ;
     RECT  5.292 0.667 5.31 2.533 ;
     RECT  40.104 0.091 49.914 2.605 ;
     RECT  56.415 2.413 56.697 2.605 ;
     RECT  57.528 1.627 58.122 2.605 ;
     RECT  64.692 0.667 64.71 2.635 ;
     RECT  56.415 2.605 58.122 2.641 ;
     RECT  1.548 2.491 3.942 2.669 ;
     RECT  54.612 1.147 54.63 2.803 ;
     RECT  5.292 2.533 5.526 2.911 ;
     RECT  38.88 2.827 38.898 3.001 ;
     RECT  39.672 2.605 49.914 3.001 ;
     RECT  56.415 2.641 58.77 3.029 ;
     RECT  60.948 1.915 60.966 3.029 ;
     RECT  64.656 2.635 64.71 3.029 ;
     RECT  54.504 2.803 54.63 3.073 ;
     RECT  5.292 2.911 5.598 3.109 ;
     RECT  5.076 3.109 5.598 3.145 ;
     RECT  6.804 2.803 6.822 3.145 ;
     RECT  54.504 3.073 55.098 3.145 ;
     RECT  58.572 3.029 58.77 3.145 ;
     RECT  2.415 2.669 3.942 3.181 ;
     RECT  5.076 3.145 6.822 3.181 ;
     RECT  34.815 2.143 35.19 3.181 ;
     RECT  38.88 3.001 49.914 3.181 ;
     RECT  1.548 2.669 1.566 3.209 ;
     RECT  56.415 3.029 57.654 3.271 ;
     RECT  58.572 3.145 59.274 3.299 ;
     RECT  2.415 3.181 6.93 3.403 ;
     RECT  53.136 3.271 53.154 3.451 ;
     RECT  61.815 2.413 62.097 3.451 ;
     RECT  34.815 3.181 35.298 3.569 ;
     RECT  61.815 3.451 62.19 3.569 ;
     RECT  62.964 2.395 63.846 3.569 ;
     RECT  2.304 3.403 6.966 3.677 ;
     RECT  58.572 3.299 58.734 3.677 ;
     RECT  2.34 3.677 6.966 3.685 ;
     RECT  7.815 2.413 8.097 3.685 ;
     RECT  53.136 3.451 53.262 3.721 ;
     RECT  54.396 3.145 55.098 3.721 ;
     RECT  55.872 3.271 57.654 3.721 ;
     RECT  64.692 3.029 64.71 3.883 ;
     RECT  2.34 3.685 8.097 3.947 ;
     RECT  34.815 3.569 35.154 3.965 ;
     RECT  52.2 3.931 52.218 3.991 ;
     RECT  53.1 3.721 53.262 3.991 ;
     RECT  54.396 3.721 57.654 3.991 ;
     RECT  58.572 3.677 58.626 3.991 ;
     RECT  52.2 3.991 53.262 4.081 ;
     RECT  62.964 3.569 63.27 4.109 ;
     RECT  61.815 3.569 62.097 4.189 ;
     RECT  38.808 3.181 49.914 4.219 ;
     RECT  52.2 4.081 53.622 4.225 ;
     RECT  54.396 3.991 58.626 4.225 ;
     RECT  51.015 2.413 51.297 4.261 ;
     RECT  61.416 4.189 62.097 4.289 ;
     RECT  64.656 3.883 64.71 4.363 ;
     RECT  36.036 3.721 36.054 4.379 ;
     RECT  62.964 4.109 62.982 4.379 ;
     RECT  52.2 4.225 58.626 4.495 ;
     RECT  16.74 4.423 16.974 4.523 ;
     RECT  38.772 4.219 49.914 4.621 ;
     RECT  50.724 4.261 51.297 4.621 ;
     RECT  52.092 4.495 58.626 4.621 ;
     RECT  9.252 4.459 9.27 4.649 ;
     RECT  64.62 4.363 64.71 4.649 ;
     RECT  34.815 3.965 35.097 4.699 ;
     RECT  8.964 4.693 8.982 4.729 ;
     RECT  13.215 2.413 13.497 4.792 ;
     RECT  24.015 2.413 24.297 4.792 ;
     RECT  34.776 4.699 35.097 4.792 ;
     RECT  8.892 4.729 8.982 4.829 ;
     RECT  13.104 4.792 13.497 4.829 ;
     RECT  23.904 4.792 24.297 4.829 ;
     RECT  34.704 4.792 35.097 4.829 ;
     RECT  64.656 4.649 64.71 4.919 ;
     RECT  38.448 4.621 49.914 4.942 ;
     RECT  50.724 4.621 58.626 4.973 ;
     RECT  2.376 3.947 8.097 5.131 ;
     RECT  61.815 4.289 62.097 5.131 ;
     RECT  50.94 4.973 58.626 5.189 ;
     RECT  53.028 5.189 57.69 5.261 ;
     RECT  59.868 4.765 59.886 5.341 ;
     RECT  39.06 4.942 49.914 5.369 ;
     RECT  64.656 4.919 64.674 5.369 ;
     RECT  61.815 5.131 62.694 5.371 ;
     RECT  63.828 4.651 63.846 5.371 ;
     RECT  59.796 5.341 59.886 5.459 ;
     RECT  0.108 4.363 0.126 5.501 ;
     RECT  61.815 5.371 63.846 5.503 ;
     RECT  61.416 5.503 63.846 5.567 ;
     RECT  61.416 5.567 62.097 5.639 ;
     RECT  2.304 5.131 8.097 5.881 ;
     RECT  59.868 5.459 59.886 5.909 ;
     RECT  2.268 5.881 8.097 5.933 ;
     RECT  63.252 5.567 63.846 5.999 ;
     RECT  50.94 5.189 52.11 6.007 ;
     RECT  50.94 6.007 52.326 6.043 ;
     RECT  53.136 5.261 57.69 6.043 ;
     RECT  50.724 6.043 57.69 6.241 ;
     RECT  58.608 5.189 58.626 6.241 ;
     RECT  58.536 6.241 58.626 6.269 ;
     RECT  63.252 5.999 63.27 6.269 ;
     RECT  0.54 6.151 0.558 6.413 ;
     RECT  58.536 6.269 58.554 6.413 ;
     RECT  50.724 6.241 57.762 6.421 ;
     RECT  60.696 6.313 60.714 6.539 ;
     RECT  50.724 6.421 57.834 6.701 ;
     RECT  0.108 6.619 0.126 6.715 ;
     RECT  2.304 5.933 8.097 6.719 ;
     RECT  60.948 6.547 60.966 6.719 ;
     RECT  0.036 6.715 0.126 6.749 ;
     RECT  2.34 6.719 8.097 6.809 ;
     RECT  64.692 6.139 64.71 6.859 ;
     RECT  51.015 6.701 57.834 7.195 ;
     RECT  51.015 7.195 58.194 7.349 ;
     RECT  63.828 7.147 63.846 7.387 ;
     RECT  64.656 6.859 64.71 7.529 ;
     RECT  63.252 7.387 63.846 7.619 ;
     RECT  51.015 7.349 57.33 7.691 ;
     RECT  60.336 7.501 60.354 7.735 ;
     RECT  61.815 5.639 62.097 7.735 ;
     RECT  60.12 7.735 61.074 7.861 ;
     RECT  0.036 6.749 0.054 7.867 ;
     RECT  52.74 7.691 57.33 7.889 ;
     RECT  52.74 7.889 52.758 7.925 ;
     RECT  2.415 6.809 8.097 8.041 ;
     RECT  8.964 4.829 8.982 8.041 ;
     RECT  58.176 7.349 58.194 8.041 ;
     RECT  59.4 7.861 61.074 8.041 ;
     RECT  64.692 7.529 64.71 8.069 ;
     RECT  16.74 4.523 16.758 8.159 ;
     RECT  39.6 5.369 49.914 8.159 ;
     RECT  54.684 7.889 57.33 8.159 ;
     RECT  63.252 7.619 63.27 8.159 ;
     RECT  38.808 8.167 38.826 8.239 ;
     RECT  58.176 8.041 61.074 8.275 ;
     RECT  61.815 7.735 62.298 8.275 ;
     RECT  53.604 7.889 53.694 8.303 ;
     RECT  54.684 8.159 54.774 8.333 ;
     RECT  57.852 8.275 62.298 8.339 ;
     RECT  0.036 7.867 0.126 8.347 ;
     RECT  0.036 8.347 0.162 8.477 ;
     RECT  57.852 8.339 62.154 8.525 ;
     RECT  38.772 8.239 38.826 8.537 ;
     RECT  54.72 8.333 54.738 8.537 ;
     RECT  2.415 8.041 8.982 8.635 ;
     RECT  10.26 8.437 10.278 8.699 ;
     RECT  0.036 8.477 0.126 8.843 ;
     RECT  55.548 8.159 57.114 8.971 ;
     RECT  57.852 8.525 62.097 8.971 ;
     RECT  53.028 8.827 53.046 9.053 ;
     RECT  39.924 8.159 49.914 9.067 ;
     RECT  55.548 8.971 62.097 9.149 ;
     RECT  55.62 9.149 62.097 9.239 ;
     RECT  0.108 8.843 0.126 9.293 ;
     RECT  59.868 9.239 62.097 9.355 ;
     RECT  39.852 9.067 49.914 9.499 ;
     RECT  59.868 9.355 62.298 9.509 ;
     RECT  2.304 8.635 8.982 9.617 ;
     RECT  2.412 9.617 8.982 9.653 ;
     RECT  55.62 9.239 59.13 9.779 ;
     RECT  39.6 9.499 49.914 9.815 ;
     RECT  38.808 8.537 38.826 9.859 ;
     RECT  5.724 9.653 8.982 9.931 ;
     RECT  54.792 9.787 54.81 9.931 ;
     RECT  38.772 9.859 38.826 9.959 ;
     RECT  39.6 9.815 41.13 9.965 ;
     RECT  54.72 9.931 54.81 10.049 ;
     RECT  56.415 9.779 59.13 10.093 ;
     RECT  59.868 9.509 62.226 10.093 ;
     RECT  63.792 8.347 63.846 10.319 ;
     RECT  36.252 4.531 36.27 10.471 ;
     RECT  36.216 10.471 36.27 10.589 ;
     RECT  56.415 10.093 62.226 10.589 ;
     RECT  64.692 9.595 64.71 10.603 ;
     RECT  34.815 4.829 35.097 10.705 ;
     RECT  5.724 9.931 9.018 10.741 ;
     RECT  10.188 8.851 10.206 10.741 ;
     RECT  56.415 10.589 62.097 10.741 ;
     RECT  2.412 9.653 4.77 10.831 ;
     RECT  64.656 10.603 64.71 10.859 ;
     RECT  2.304 10.831 4.77 10.867 ;
     RECT  5.724 10.741 10.206 10.867 ;
     RECT  2.304 10.867 10.206 10.903 ;
     RECT  34.815 10.705 35.37 10.931 ;
     RECT  2.304 10.903 10.818 11.039 ;
     RECT  64.692 10.859 64.71 11.039 ;
     RECT  63.828 10.319 63.846 11.131 ;
     RECT  56.304 10.741 62.097 11.165 ;
     RECT  55.296 10.669 55.314 11.237 ;
     RECT  63.252 11.131 63.846 11.281 ;
     RECT  63.252 11.281 63.882 11.405 ;
     RECT  36.252 10.589 36.27 11.407 ;
     RECT  36.18 11.407 36.27 11.435 ;
     RECT  14.868 11.641 14.886 11.749 ;
     RECT  13.215 4.829 13.497 11.821 ;
     RECT  56.415 11.165 62.097 11.821 ;
     RECT  63.252 11.405 63.846 11.821 ;
     RECT  56.415 11.821 63.846 11.885 ;
     RECT  14.868 11.749 14.922 11.911 ;
     RECT  14.868 11.911 14.958 11.939 ;
     RECT  16.596 8.275 16.614 11.975 ;
     RECT  14.94 11.939 14.958 11.981 ;
     RECT  37.764 10.741 37.782 12.187 ;
     RECT  37.62 12.187 37.782 12.209 ;
     RECT  37.62 12.209 37.638 12.245 ;
     RECT  38.808 9.959 38.826 12.289 ;
     RECT  2.304 11.039 10.206 12.317 ;
     RECT  38.808 12.289 39.15 12.389 ;
     RECT  63.252 11.885 63.846 12.389 ;
     RECT  2.34 12.317 10.206 12.479 ;
     RECT  56.415 11.885 62.298 12.523 ;
     RECT  0.108 11.611 0.126 12.659 ;
     RECT  55.692 12.523 62.298 12.749 ;
     RECT  54.72 12.361 54.738 12.757 ;
     RECT  55.692 12.749 62.097 12.757 ;
     RECT  2.415 12.479 10.206 13.099 ;
     RECT  11.376 12.757 11.394 13.099 ;
     RECT  2.415 13.099 11.394 13.127 ;
     RECT  54.72 12.757 62.097 13.325 ;
     RECT  13.215 11.821 14.094 13.469 ;
     RECT  2.415 13.127 10.89 13.559 ;
     RECT  54.72 13.325 55.422 13.631 ;
     RECT  5.616 13.559 10.89 13.661 ;
     RECT  63.792 12.389 63.846 13.739 ;
     RECT  56.16 13.325 62.097 13.829 ;
     RECT  63.792 13.739 63.81 13.829 ;
     RECT  38.808 12.389 38.826 13.973 ;
     RECT  2.415 13.559 4.77 14.347 ;
     RECT  61.815 13.829 62.097 14.347 ;
     RECT  56.16 13.829 61.002 14.369 ;
     RECT  40.215 9.965 41.13 14.485 ;
     RECT  55.404 13.631 55.422 14.521 ;
     RECT  40.032 14.485 41.13 14.611 ;
     RECT  42.012 9.815 49.914 14.611 ;
     RECT  56.268 14.369 61.002 14.639 ;
     RECT  61.815 14.347 62.19 14.765 ;
     RECT  2.304 14.347 4.77 14.791 ;
     RECT  5.616 13.661 10.206 14.791 ;
     RECT  64.692 14.587 64.71 14.827 ;
     RECT  54.108 14.827 54.126 14.881 ;
     RECT  55.332 14.521 55.422 14.881 ;
     RECT  40.032 14.611 49.914 14.945 ;
     RECT  0.108 14.827 0.126 15.005 ;
     RECT  64.656 14.827 64.71 15.053 ;
     RECT  38.88 14.875 38.898 15.061 ;
     RECT  40.032 14.945 41.202 15.061 ;
     RECT  51.015 7.691 51.966 15.061 ;
     RECT  39.816 15.061 41.202 15.215 ;
     RECT  56.268 14.639 60.462 15.223 ;
     RECT  38.88 15.061 39.042 15.259 ;
     RECT  37.296 15.259 37.314 15.331 ;
     RECT  54.108 14.881 55.422 15.331 ;
     RECT  56.16 15.223 60.462 15.331 ;
     RECT  63.828 15.115 63.846 15.355 ;
     RECT  40.032 15.215 41.202 15.359 ;
     RECT  63.252 15.355 63.846 15.359 ;
     RECT  2.304 14.791 10.206 15.421 ;
     RECT  11.088 13.945 11.106 15.421 ;
     RECT  54.108 15.331 60.462 15.493 ;
     RECT  53.964 15.493 60.462 15.533 ;
     RECT  2.304 15.421 11.106 15.629 ;
     RECT  54.072 15.533 60.462 15.629 ;
     RECT  37.296 15.331 37.386 15.691 ;
     RECT  38.664 15.259 39.042 15.691 ;
     RECT  37.224 15.691 39.042 15.719 ;
     RECT  50.724 15.061 51.966 15.719 ;
     RECT  38.052 15.719 39.042 15.755 ;
     RECT  64.692 15.053 64.71 15.835 ;
     RECT  2.415 15.629 11.106 15.863 ;
     RECT  37.224 15.719 37.242 15.899 ;
     RECT  64.656 15.835 64.71 15.989 ;
     RECT  40.104 15.359 41.202 16.069 ;
     RECT  41.94 14.945 49.914 16.069 ;
     RECT  54.72 15.629 60.462 16.105 ;
     RECT  61.815 14.765 62.097 16.105 ;
     RECT  40.104 16.069 49.914 16.133 ;
     RECT  38.772 15.755 39.042 16.169 ;
     RECT  64.656 15.989 64.674 16.169 ;
     RECT  38.844 16.169 39.042 16.219 ;
     RECT  38.844 16.219 39.222 16.259 ;
     RECT  42.192 16.133 49.914 16.259 ;
     RECT  54.72 16.105 62.097 16.259 ;
     RECT  42.228 16.259 49.914 16.331 ;
     RECT  61.092 16.259 62.097 16.363 ;
     RECT  63.252 15.359 63.27 16.363 ;
     RECT  38.844 16.259 38.934 16.367 ;
     RECT  40.104 16.133 41.454 16.439 ;
     RECT  61.092 16.363 63.27 16.439 ;
     RECT  38.844 16.367 38.862 16.529 ;
     RECT  61.092 16.439 62.694 16.529 ;
     RECT  54.72 16.259 60.282 16.555 ;
     RECT  2.415 15.863 10.206 16.603 ;
     RECT  40.104 16.439 40.914 16.637 ;
     RECT  63.864 16.807 63.882 16.877 ;
     RECT  54.612 16.555 60.282 17.069 ;
     RECT  61.092 16.529 62.097 17.077 ;
     RECT  51.015 15.719 51.966 17.179 ;
     RECT  54.612 17.069 60.21 17.179 ;
     RECT  1.116 17.083 1.134 17.213 ;
     RECT  13.215 13.469 13.497 17.227 ;
     RECT  24.015 4.829 24.297 17.311 ;
     RECT  34.815 10.931 35.097 17.311 ;
     RECT  60.948 17.077 62.097 17.323 ;
     RECT  13.104 17.227 13.497 17.339 ;
     RECT  23.904 17.311 24.297 17.357 ;
     RECT  34.704 17.311 35.097 17.357 ;
     RECT  54.144 17.179 60.21 17.375 ;
     RECT  60.948 17.323 62.694 17.609 ;
     RECT  60.948 17.609 62.097 17.645 ;
     RECT  42.84 16.331 49.914 17.689 ;
     RECT  50.724 17.179 51.966 17.789 ;
     RECT  50.796 17.789 51.966 17.915 ;
     RECT  42.768 17.689 49.914 18.121 ;
     RECT  54.18 17.375 60.21 18.149 ;
     RECT  54.252 18.149 60.21 18.185 ;
     RECT  61.092 17.645 62.097 18.329 ;
     RECT  64.692 17.077 64.71 18.571 ;
     RECT  64.656 18.571 64.71 18.689 ;
     RECT  0.108 17.083 0.126 18.749 ;
     RECT  54.72 18.185 60.21 18.761 ;
     RECT  55.188 18.761 55.422 18.797 ;
     RECT  56.232 18.761 60.21 18.841 ;
     RECT  64.656 18.689 64.674 18.869 ;
     RECT  56.232 18.841 60.786 18.959 ;
     RECT  2.304 16.603 10.206 18.967 ;
     RECT  11.088 15.863 11.106 18.967 ;
     RECT  63.828 18.331 63.846 19.099 ;
     RECT  2.304 18.967 11.106 19.139 ;
     RECT  63.792 19.099 63.846 19.229 ;
     RECT  61.815 18.329 62.097 19.345 ;
     RECT  2.415 19.139 11.106 19.373 ;
     RECT  61.524 19.345 62.097 19.499 ;
     RECT  63.828 19.229 63.846 20.039 ;
     RECT  56.415 18.959 60.678 20.047 ;
     RECT  2.415 19.373 10.206 20.059 ;
     RECT  64.692 19.579 64.71 20.059 ;
     RECT  55.404 18.797 55.422 20.083 ;
     RECT  61.815 19.499 62.097 20.083 ;
     RECT  64.656 20.059 64.71 20.111 ;
     RECT  51.015 17.915 51.966 20.191 ;
     RECT  56.415 20.047 60.858 20.191 ;
     RECT  64.692 20.111 64.71 20.219 ;
     RECT  54.72 20.083 55.422 20.281 ;
     RECT  56.304 20.191 60.858 20.281 ;
     RECT  63.252 20.344 63.27 20.381 ;
     RECT  54.72 20.281 60.858 20.389 ;
     RECT  61.815 20.083 62.154 20.389 ;
     RECT  50.724 20.191 51.966 20.417 ;
     RECT  42.444 18.121 49.914 20.461 ;
     RECT  54.72 20.389 60.966 20.489 ;
     RECT  41.796 20.461 49.914 20.525 ;
     RECT  61.74 20.389 62.154 20.581 ;
     RECT  54.72 20.489 60.678 20.624 ;
     RECT  61.74 20.581 62.73 20.861 ;
     RECT  54.756 20.624 60.678 20.885 ;
     RECT  42.084 20.525 49.914 20.957 ;
     RECT  61.74 20.861 62.097 20.965 ;
     RECT  0.54 20.659 0.558 21.067 ;
     RECT  54.756 20.885 60.57 21.101 ;
     RECT  55.152 21.101 60.57 21.119 ;
     RECT  61.524 20.965 62.097 21.119 ;
     RECT  55.404 21.119 60.57 21.155 ;
     RECT  0.54 21.067 0.594 21.299 ;
     RECT  63.828 21.307 63.846 21.547 ;
     RECT  2.304 20.059 10.206 21.695 ;
     RECT  42.192 20.957 49.914 21.787 ;
     RECT  41.904 21.787 49.914 21.839 ;
     RECT  38.772 21.739 38.79 21.965 ;
     RECT  0.54 21.299 0.558 21.979 ;
     RECT  11.088 19.373 11.106 22.045 ;
     RECT  55.404 21.155 60.534 22.045 ;
     RECT  41.976 21.839 49.914 22.205 ;
     RECT  2.376 21.695 10.206 22.271 ;
     RECT  55.404 22.045 60.678 22.279 ;
     RECT  64.692 21.067 64.71 22.379 ;
     RECT  42.192 22.205 49.914 22.441 ;
     RECT  51.015 20.417 51.966 22.441 ;
     RECT  55.152 22.279 60.678 22.459 ;
     RECT  55.044 22.459 60.678 22.505 ;
     RECT  2.376 22.271 9.918 22.555 ;
     RECT  61.815 21.119 62.097 22.555 ;
     RECT  63.252 21.547 63.846 22.577 ;
     RECT  55.188 22.505 60.678 22.585 ;
     RECT  61.815 22.555 62.154 22.649 ;
     RECT  61.815 22.649 62.097 22.711 ;
     RECT  42.192 22.441 51.966 22.739 ;
     RECT  55.188 22.585 60.822 22.739 ;
     RECT  61.776 22.711 62.097 22.747 ;
     RECT  0.108 21.979 0.558 22.829 ;
     RECT  60.984 22.747 62.097 23.009 ;
     RECT  0.468 22.829 0.558 23.053 ;
     RECT  18.615 2.413 18.897 23.161 ;
     RECT  17.964 23.161 18.897 23.357 ;
     RECT  55.404 22.739 60.246 23.521 ;
     RECT  60.984 23.009 61.002 23.521 ;
     RECT  64.692 23.323 64.71 23.549 ;
     RECT  55.404 23.521 61.002 23.665 ;
     RECT  63.828 22.577 63.846 23.701 ;
     RECT  11.088 22.045 11.43 23.819 ;
     RECT  63.828 23.701 63.882 23.837 ;
     RECT  55.368 23.665 61.002 23.855 ;
     RECT  55.404 23.855 61.002 23.971 ;
     RECT  16.74 12.091 16.758 24.089 ;
     RECT  61.815 23.009 62.097 24.241 ;
     RECT  55.404 23.971 61.038 24.503 ;
     RECT  59.256 24.503 61.038 24.701 ;
     RECT  2.304 22.555 9.918 24.809 ;
     RECT  0.468 23.053 1.134 24.811 ;
     RECT  61.815 24.241 62.73 24.811 ;
     RECT  63.828 23.837 63.846 24.811 ;
     RECT  0.108 24.811 1.134 24.989 ;
     RECT  55.404 24.503 58.158 25.007 ;
     RECT  61.815 24.811 63.846 25.051 ;
     RECT  0.18 24.989 1.134 25.085 ;
     RECT  61.56 25.051 63.846 25.085 ;
     RECT  56.16 25.007 58.158 25.102 ;
     RECT  59.256 24.701 60.75 25.285 ;
     RECT  63.252 25.085 63.846 25.285 ;
     RECT  56.415 25.102 58.158 25.321 ;
     RECT  58.932 25.285 60.75 25.321 ;
     RECT  0.468 25.085 1.134 25.483 ;
     RECT  56.415 25.321 60.75 25.519 ;
     RECT  61.56 25.085 62.097 25.519 ;
     RECT  0.468 25.483 1.17 25.613 ;
     RECT  63.252 25.285 63.882 25.709 ;
     RECT  2.415 24.809 9.918 25.861 ;
     RECT  2.376 25.861 9.918 26.015 ;
     RECT  56.415 25.519 62.097 26.123 ;
     RECT  38.844 26.221 38.862 26.329 ;
     RECT  58.716 26.123 62.097 26.329 ;
     RECT  63.828 25.709 63.882 26.333 ;
     RECT  0.468 25.613 1.134 26.393 ;
     RECT  34.815 17.357 35.097 26.401 ;
     RECT  38.808 26.329 38.862 26.401 ;
     RECT  63.828 26.333 63.846 26.429 ;
     RECT  40.176 16.637 40.914 26.491 ;
     RECT  37.548 26.491 37.566 26.555 ;
     RECT  55.404 25.007 55.422 26.563 ;
     RECT  58.716 26.329 62.73 26.573 ;
     RECT  34.776 26.401 35.097 26.591 ;
     RECT  38.664 26.401 38.862 26.591 ;
     RECT  40.104 26.491 40.914 26.621 ;
     RECT  38.772 26.591 38.862 26.699 ;
     RECT  54.792 26.563 55.422 26.699 ;
     RECT  42.444 22.739 51.966 26.789 ;
     RECT  58.716 26.573 62.298 26.825 ;
     RECT  43.668 26.789 43.758 26.861 ;
     RECT  2.412 26.015 9.918 26.905 ;
     RECT  56.415 26.123 57.942 26.941 ;
     RECT  58.716 26.825 58.734 26.941 ;
     RECT  64.692 26.059 64.71 26.969 ;
     RECT  63.288 27.061 63.306 27.307 ;
     RECT  59.508 26.825 62.298 27.329 ;
     RECT  63.288 27.307 63.846 27.547 ;
     RECT  59.508 27.329 62.097 27.643 ;
     RECT  56.415 26.941 58.734 27.751 ;
     RECT  59.472 27.643 62.097 27.751 ;
     RECT  63.252 27.547 63.846 27.869 ;
     RECT  56.415 27.751 62.097 27.931 ;
     RECT  63.252 27.869 63.27 28.139 ;
     RECT  38.844 26.699 38.862 28.175 ;
     RECT  56.376 27.931 62.097 28.409 ;
     RECT  56.415 28.409 62.097 28.525 ;
     RECT  2.304 26.905 9.918 28.552 ;
     RECT  64.692 28.315 64.71 28.555 ;
     RECT  64.656 28.555 64.71 28.751 ;
     RECT  56.415 28.525 62.694 28.859 ;
     RECT  64.692 28.751 64.71 28.859 ;
     RECT  0.54 26.393 1.134 29.029 ;
     RECT  2.268 28.552 9.918 29.029 ;
     RECT  63.252 29.029 63.306 29.309 ;
     RECT  63.252 29.309 63.27 29.597 ;
     RECT  56.415 28.859 62.097 29.797 ;
     RECT  56.415 29.797 62.73 29.837 ;
     RECT  63.828 30.043 63.846 30.101 ;
     RECT  43.704 26.861 43.722 30.415 ;
     RECT  44.64 26.789 51.966 30.415 ;
     RECT  0.54 29.029 9.918 30.523 ;
     RECT  56.415 29.837 62.694 30.569 ;
     RECT  56.415 30.569 60.534 30.749 ;
     RECT  56.415 30.749 60.426 30.845 ;
     RECT  61.272 30.569 62.694 30.875 ;
     RECT  42.444 26.789 42.894 30.955 ;
     RECT  43.704 30.415 51.966 30.955 ;
     RECT  61.815 30.875 62.694 30.955 ;
     RECT  63.828 30.859 63.846 31.051 ;
     RECT  64.692 30.523 64.71 31.109 ;
     RECT  40.176 26.621 40.914 31.351 ;
     RECT  25.74 31.381 25.758 31.421 ;
     RECT  56.415 30.845 60.21 31.472 ;
     RECT  39.816 31.351 40.914 31.523 ;
     RECT  26.676 31.351 26.694 31.531 ;
     RECT  26.424 31.531 26.694 31.559 ;
     RECT  61.815 30.955 62.73 31.559 ;
     RECT  33.084 31.387 33.102 31.621 ;
     RECT  56.376 31.472 60.21 31.621 ;
     RECT  63.792 31.051 63.846 31.621 ;
     RECT  33.084 31.621 33.318 31.649 ;
     RECT  36.18 11.435 36.198 31.649 ;
     RECT  39.996 31.523 40.914 31.649 ;
     RECT  56.34 31.621 60.21 31.661 ;
     RECT  42.444 30.955 51.966 31.721 ;
     RECT  63.288 31.621 63.846 31.805 ;
     RECT  63.828 31.805 63.846 31.891 ;
     RECT  56.376 31.661 60.21 31.999 ;
     RECT  61.815 31.559 62.097 31.999 ;
     RECT  0.108 30.523 9.918 32.045 ;
     RECT  63.828 31.891 63.882 32.045 ;
     RECT  42.768 31.721 51.966 32.333 ;
     RECT  56.376 31.999 62.097 32.341 ;
     RECT  56.376 32.341 62.262 32.431 ;
     RECT  63.828 32.045 63.846 32.459 ;
     RECT  56.304 32.431 62.262 32.539 ;
     RECT  55.404 26.699 55.422 32.575 ;
     RECT  56.304 32.539 62.694 32.575 ;
     RECT  55.404 32.575 62.694 32.773 ;
     RECT  55.404 32.773 63.306 32.813 ;
     RECT  42.804 32.333 51.966 32.999 ;
     RECT  55.404 32.813 62.73 32.999 ;
     RECT  42.804 32.999 44.658 33.035 ;
     RECT  44.316 33.035 44.658 33.053 ;
     RECT  55.404 32.999 60.678 33.053 ;
     RECT  61.452 32.999 62.73 33.053 ;
     RECT  26.424 31.559 26.442 33.305 ;
     RECT  44.352 33.053 44.658 33.305 ;
     RECT  63.828 33.259 63.846 33.305 ;
     RECT  44.352 33.305 44.406 33.449 ;
     RECT  61.452 33.053 62.694 33.611 ;
     RECT  0.54 32.045 9.918 33.643 ;
     RECT  55.404 33.053 60.606 33.787 ;
     RECT  63.864 33.421 63.882 33.821 ;
     RECT  54.72 33.787 60.606 33.917 ;
     RECT  61.632 33.611 62.694 33.989 ;
     RECT  42.804 33.035 43.47 34.079 ;
     RECT  41.472 34.051 41.49 34.109 ;
     RECT  42.804 34.079 42.894 34.109 ;
     RECT  0.108 33.643 9.918 34.157 ;
     RECT  55.404 33.917 60.606 34.159 ;
     RECT  61.632 33.989 62.097 34.465 ;
     RECT  55.404 34.159 60.678 34.501 ;
     RECT  61.524 34.465 62.097 34.501 ;
     RECT  55.404 34.501 62.097 34.619 ;
     RECT  63.252 34.027 63.27 34.619 ;
     RECT  55.404 34.619 61.038 34.691 ;
     RECT  61.815 34.619 62.097 34.771 ;
     RECT  56.304 34.691 61.038 35.473 ;
     RECT  61.815 34.771 62.694 35.473 ;
     RECT  55.404 34.691 55.422 35.581 ;
     RECT  56.304 35.473 62.694 35.581 ;
     RECT  63.792 34.747 63.846 35.609 ;
     RECT  55.404 35.581 62.694 35.735 ;
     RECT  55.404 35.735 61.074 36.077 ;
     RECT  64.692 35.995 64.71 36.077 ;
     RECT  0.54 34.157 9.918 36.121 ;
     RECT  39.996 31.649 40.734 36.121 ;
     RECT  44.388 33.449 44.406 36.121 ;
     RECT  45.54 32.999 51.966 36.121 ;
     RECT  63.828 35.609 63.846 36.211 ;
     RECT  55.404 36.077 60.642 36.235 ;
     RECT  0.108 36.121 9.918 36.317 ;
     RECT  63.828 36.211 63.882 36.317 ;
     RECT  61.815 35.735 62.694 36.355 ;
     RECT  54.72 36.235 60.642 36.365 ;
     RECT  42.876 34.109 42.894 36.517 ;
     RECT  0.54 36.317 9.918 36.625 ;
     RECT  29.415 2.413 29.697 36.751 ;
     RECT  30.492 36.715 30.51 36.751 ;
     RECT  34.815 26.591 35.097 36.751 ;
     RECT  56.16 36.365 60.642 36.779 ;
     RECT  37.116 36.751 37.134 36.797 ;
     RECT  29.415 36.751 30.51 36.845 ;
     RECT  34.815 36.751 35.586 36.845 ;
     RECT  63.828 36.317 63.846 36.887 ;
     RECT  44.28 36.121 51.966 36.895 ;
     RECT  56.304 36.779 60.642 36.895 ;
     RECT  61.815 36.355 62.838 36.895 ;
     RECT  0.54 36.625 10.17 37.021 ;
     RECT  11.088 23.819 11.106 37.021 ;
     RECT  54.72 36.365 55.422 37.037 ;
     RECT  56.304 36.895 62.838 37.037 ;
     RECT  43.992 36.895 51.966 37.049 ;
     RECT  42.768 36.517 42.894 37.057 ;
     RECT  42.264 37.057 42.894 37.133 ;
     RECT  62.82 37.037 62.838 37.201 ;
     RECT  30.492 36.845 30.51 37.229 ;
     RECT  62.82 37.201 63.306 37.277 ;
     RECT  0.54 37.021 11.106 37.319 ;
     RECT  0.54 37.319 10.17 37.589 ;
     RECT  56.304 37.037 62.097 37.939 ;
     RECT  62.82 37.277 62.838 37.939 ;
     RECT  56.304 37.939 62.838 38.005 ;
     RECT  44.136 37.049 51.966 38.129 ;
     RECT  44.928 38.129 51.966 38.165 ;
     RECT  64.692 37.531 64.71 38.165 ;
     RECT  45.108 38.165 51.966 38.189 ;
     RECT  39.996 36.121 41.022 38.471 ;
     RECT  56.304 38.005 63.306 38.491 ;
     RECT  56.304 38.491 63.846 38.669 ;
     RECT  39.996 38.471 40.734 38.939 ;
     RECT  61.815 38.669 63.846 38.939 ;
     RECT  44.136 38.129 44.154 39.211 ;
     RECT  45.36 38.189 51.966 39.211 ;
     RECT  56.304 38.669 61.038 39.211 ;
     RECT  44.136 39.211 51.966 39.251 ;
     RECT  56.232 39.211 61.038 39.251 ;
     RECT  0.54 37.589 10.098 39.317 ;
     RECT  56.304 39.251 61.038 39.595 ;
     RECT  61.815 38.939 63.378 39.595 ;
     RECT  40.215 38.939 40.734 39.623 ;
     RECT  56.304 39.595 63.378 39.721 ;
     RECT  56.304 39.721 63.882 40.301 ;
     RECT  54 38.911 54.018 40.531 ;
     RECT  55.404 37.037 55.422 40.531 ;
     RECT  56.304 40.301 63.306 40.603 ;
     RECT  54 40.531 55.422 40.675 ;
     RECT  56.16 40.603 63.306 40.675 ;
     RECT  45.36 39.251 51.966 40.739 ;
     RECT  54 40.675 63.306 40.739 ;
     RECT  0.54 39.317 9.954 40.891 ;
     RECT  0.108 40.891 9.954 41.021 ;
     RECT  55.404 40.739 63.306 41.215 ;
     RECT  55.404 41.215 63.954 41.227 ;
     RECT  64.692 40.507 64.71 41.227 ;
     RECT  55.404 41.227 64.71 41.405 ;
     RECT  64.692 41.405 64.71 41.441 ;
     RECT  55.404 41.405 63.954 41.783 ;
     RECT  56.232 41.783 63.954 41.789 ;
     RECT  44.136 39.251 44.154 42.053 ;
     RECT  33.3 31.649 33.318 42.139 ;
     RECT  33.156 42.139 33.318 42.151 ;
     RECT  34.815 36.845 35.097 42.151 ;
     RECT  33.156 42.151 35.097 42.179 ;
     RECT  36.072 42.025 36.09 42.179 ;
     RECT  33.696 42.179 35.097 42.251 ;
     RECT  0.468 41.021 9.954 42.359 ;
     RECT  56.304 41.789 63.954 42.755 ;
     RECT  42.876 37.133 42.894 43.231 ;
     RECT  43.704 42.763 43.722 43.259 ;
     RECT  42.768 43.231 42.894 43.325 ;
     RECT  55.404 41.783 55.422 43.645 ;
     RECT  56.304 42.755 60.714 43.645 ;
     RECT  61.452 42.755 63.954 43.645 ;
     RECT  0.54 42.359 9.954 43.723 ;
     RECT  64.692 43.243 64.71 43.799 ;
     RECT  11.088 37.319 11.106 44.587 ;
     RECT  0.108 43.723 9.954 44.609 ;
     RECT  64.692 44.971 64.71 45.329 ;
     RECT  45.615 40.739 51.966 45.455 ;
     RECT  45.615 45.455 46.53 45.491 ;
     RECT  55.404 43.645 63.954 45.595 ;
     RECT  0.468 44.609 9.954 45.733 ;
     RECT  10.8 44.587 11.106 45.733 ;
     RECT  45.615 45.491 46.422 45.931 ;
     RECT  45.108 45.931 46.422 45.959 ;
     RECT  45.108 45.959 46.35 45.995 ;
     RECT  45.615 45.995 46.35 46.013 ;
     RECT  45.615 46.013 46.206 46.031 ;
     RECT  0.468 45.733 11.106 46.139 ;
     RECT  54.9 45.595 63.954 46.229 ;
     RECT  0.468 46.139 10.314 46.301 ;
     RECT  37.008 42.061 37.026 46.381 ;
     RECT  45.615 46.031 46.17 46.499 ;
     RECT  36.72 46.381 37.026 46.571 ;
     RECT  0.468 46.301 9.954 46.747 ;
     RECT  47.34 45.455 51.966 46.747 ;
     RECT  0.108 46.747 9.954 46.949 ;
     RECT  0.144 46.949 9.954 47.021 ;
     RECT  54 40.739 54.018 47.461 ;
     RECT  55.368 46.229 63.954 47.461 ;
     RECT  47.268 46.747 51.966 47.659 ;
     RECT  54 47.461 63.954 47.759 ;
     RECT  55.296 47.759 63.954 47.789 ;
     RECT  45.615 46.499 45.897 47.821 ;
     RECT  46.764 47.659 51.966 47.821 ;
     RECT  0.468 47.021 9.954 48.235 ;
     RECT  0.108 48.235 9.954 48.299 ;
     RECT  45.615 47.821 51.966 48.475 ;
     RECT  45 48.475 51.966 48.659 ;
     RECT  44.064 48.805 44.082 48.811 ;
     RECT  44.064 48.811 44.226 48.845 ;
     RECT  54 47.759 54.018 48.901 ;
     RECT  55.404 47.789 63.954 48.901 ;
     RECT  44.208 48.845 44.226 48.929 ;
     RECT  45.615 48.659 51.966 48.929 ;
     RECT  0.54 48.299 9.954 48.937 ;
     RECT  11.088 46.139 11.106 48.937 ;
     RECT  54 48.901 54.27 49.081 ;
     RECT  55.332 48.901 63.954 49.081 ;
     RECT  54 49.081 63.954 49.109 ;
     RECT  54 49.109 60.282 49.207 ;
     RECT  53.64 49.207 60.282 49.243 ;
     RECT  53.532 49.243 60.282 49.28 ;
     RECT  53.64 49.28 60.282 49.379 ;
     RECT  61.38 49.109 63.954 49.468 ;
     RECT  64.692 49.195 64.71 49.468 ;
     RECT  61.38 49.468 64.71 49.469 ;
     RECT  53.712 49.379 60.282 49.505 ;
     RECT  61.38 49.469 64.674 49.613 ;
     RECT  53.964 49.505 60.282 49.649 ;
     RECT  13.215 17.339 13.497 49.711 ;
     RECT  24.015 17.357 24.297 49.711 ;
     RECT  34.815 42.251 35.097 49.711 ;
     RECT  45.615 48.929 46.458 49.711 ;
     RECT  47.196 48.929 51.966 49.711 ;
     RECT  13.104 49.711 13.497 49.757 ;
     RECT  23.904 49.711 24.297 49.757 ;
     RECT  34.704 49.711 35.097 49.757 ;
     RECT  45.504 49.711 51.966 49.757 ;
     RECT  61.38 49.613 63.954 49.775 ;
     RECT  0.54 48.937 11.106 49.867 ;
     RECT  42.876 43.325 42.894 49.891 ;
     RECT  0.108 49.867 11.106 49.997 ;
     RECT  42.804 49.891 42.894 50.081 ;
     RECT  45.615 49.757 51.966 50.117 ;
     RECT  45.615 50.117 47.394 50.141 ;
     RECT  38.016 46.381 38.034 50.431 ;
     RECT  47.376 50.141 47.394 50.459 ;
     RECT  54 49.649 60.282 50.935 ;
     RECT  54 50.935 60.462 51.601 ;
     RECT  61.452 49.775 63.954 51.601 ;
     RECT  64.692 50.203 64.71 51.899 ;
     RECT  54 51.601 63.954 52.583 ;
     RECT  0.54 49.997 11.106 53.023 ;
     RECT  54 52.583 60.282 53.365 ;
     RECT  0.468 53.023 11.106 53.371 ;
     RECT  0.108 53.371 11.106 53.501 ;
     RECT  48.276 50.117 51.966 53.563 ;
     RECT  47.88 53.563 51.966 53.635 ;
     RECT  54 53.365 60.462 53.699 ;
     RECT  47.736 53.635 51.966 53.755 ;
     RECT  45.615 50.141 46.422 53.941 ;
     RECT  0.468 53.501 11.106 54.059 ;
     RECT  47.556 53.755 51.966 54.095 ;
     RECT  54 53.699 60.282 54.103 ;
     RECT  42.876 50.081 42.894 54.379 ;
     RECT  10.836 54.059 11.106 54.509 ;
     RECT  22.824 54.379 22.842 54.509 ;
     RECT  30.78 54.379 30.798 54.509 ;
     RECT  42.768 54.379 42.894 54.509 ;
     RECT  45.615 53.941 46.782 54.509 ;
     RECT  64.692 53.947 64.71 54.599 ;
     RECT  45.615 54.509 46.422 54.869 ;
     RECT  47.736 54.095 51.966 54.869 ;
     RECT  0.468 54.059 9.954 54.949 ;
     RECT  34.815 49.757 35.097 54.949 ;
     RECT  38.016 50.431 38.43 54.949 ;
     RECT  0.468 54.949 10.098 54.955 ;
     RECT  37.008 46.571 37.026 54.985 ;
     RECT  38.016 54.949 38.574 54.985 ;
     RECT  37.008 54.985 38.574 55.021 ;
     RECT  34.776 54.949 35.097 55.139 ;
     RECT  37.008 55.021 38.61 55.211 ;
     RECT  0.108 54.955 10.098 55.247 ;
     RECT  53.604 54.103 60.282 55.255 ;
     RECT  61.452 52.583 63.954 55.255 ;
     RECT  53.604 55.255 63.954 55.319 ;
     RECT  45.615 54.869 46.17 55.381 ;
     RECT  45.036 55.381 46.17 55.409 ;
     RECT  47.772 54.869 51.966 55.445 ;
     RECT  45.036 55.409 45.897 55.469 ;
     RECT  37.008 55.211 38.538 55.489 ;
     RECT  36.756 55.489 38.538 55.517 ;
     RECT  0.54 55.247 10.098 55.525 ;
     RECT  11.088 54.509 11.106 55.525 ;
     RECT  0.54 55.525 11.106 55.751 ;
     RECT  47.916 55.445 51.966 55.751 ;
     RECT  0.54 55.751 10.242 55.859 ;
     RECT  45.18 55.469 45.897 55.985 ;
     RECT  47.916 55.751 48.51 55.985 ;
     RECT  47.916 55.985 48.438 56.129 ;
     RECT  54 55.319 63.954 56.335 ;
     RECT  13.215 49.757 13.497 56.632 ;
     RECT  24.015 49.757 24.297 56.632 ;
     RECT  34.815 55.139 35.097 56.632 ;
     RECT  13.104 56.632 13.497 56.669 ;
     RECT  23.904 56.632 24.297 56.669 ;
     RECT  34.704 56.632 35.097 56.669 ;
     RECT  45.504 55.985 45.897 56.669 ;
     RECT  0.54 55.859 10.098 56.911 ;
     RECT  0.108 56.911 10.098 56.957 ;
     RECT  45.615 56.669 45.897 57.115 ;
     RECT  0.54 56.957 10.098 57.403 ;
     RECT  11.088 55.751 11.106 57.403 ;
     RECT  52.74 38.443 52.758 57.403 ;
     RECT  53.748 56.335 63.954 57.403 ;
     RECT  0.54 57.403 11.106 57.581 ;
     RECT  45.615 57.115 46.422 57.677 ;
     RECT  46.764 57.835 46.782 57.965 ;
     RECT  52.74 57.403 63.954 58.157 ;
     RECT  11.088 57.581 11.106 58.555 ;
     RECT  49.284 55.751 51.966 58.693 ;
     RECT  53.748 58.157 63.954 58.721 ;
     RECT  0.54 57.581 10.098 58.843 ;
     RECT  10.836 58.555 11.106 58.843 ;
     RECT  0.54 58.843 11.106 58.973 ;
     RECT  0.54 58.973 10.098 59.659 ;
     RECT  48.42 56.129 48.438 59.707 ;
     RECT  47.988 59.707 48.438 59.845 ;
     RECT  49.212 58.693 51.966 59.845 ;
     RECT  64.692 55.963 64.71 59.999 ;
     RECT  47.988 59.845 51.966 60.475 ;
     RECT  46.872 60.427 46.89 60.539 ;
     RECT  47.808 60.475 51.966 60.539 ;
     RECT  24.015 56.669 24.297 60.547 ;
     RECT  23.76 60.547 24.297 60.583 ;
     RECT  18.615 23.357 18.897 60.691 ;
     RECT  23.364 60.583 24.297 60.691 ;
     RECT  0.108 59.659 10.098 60.781 ;
     RECT  11.088 58.973 11.106 60.781 ;
     RECT  18.615 60.691 18.954 60.809 ;
     RECT  46.764 60.691 46.782 60.881 ;
     RECT  23.292 60.691 24.297 60.925 ;
     RECT  53.748 58.721 63.918 61.123 ;
     RECT  36.756 55.517 36.774 61.259 ;
     RECT  22.284 61.231 22.302 61.349 ;
     RECT  45.615 57.677 45.897 61.357 ;
     RECT  48.312 60.539 51.966 61.501 ;
     RECT  22.14 61.501 22.158 61.565 ;
     RECT  48.276 61.501 51.966 61.867 ;
     RECT  47.772 61.867 51.966 61.889 ;
     RECT  64.692 60.907 64.71 61.915 ;
     RECT  47.772 61.889 48.87 61.925 ;
     RECT  49.644 61.889 51.966 62.159 ;
     RECT  48.276 61.925 48.726 62.189 ;
     RECT  48.276 62.189 48.582 62.195 ;
     RECT  49.644 62.159 49.662 62.195 ;
     RECT  0.108 60.781 11.106 62.477 ;
     RECT  64.656 61.915 64.71 62.654 ;
     RECT  53.496 61.123 63.918 62.707 ;
     RECT  64.656 62.654 64.674 62.707 ;
     RECT  0.108 62.477 10.134 62.843 ;
     RECT  53.496 62.707 64.674 63.113 ;
     RECT  13.215 56.669 13.497 63.643 ;
     RECT  13.104 63.643 13.497 63.689 ;
     RECT  23.04 60.925 24.297 63.751 ;
     RECT  45.615 61.357 46.206 63.779 ;
     RECT  52.74 58.157 52.758 63.787 ;
     RECT  53.496 63.113 63.954 63.787 ;
     RECT  23.04 63.751 24.318 63.821 ;
     RECT  25.128 63.781 25.146 63.821 ;
     RECT  52.74 63.787 63.954 63.824 ;
     RECT  54 63.824 63.954 64.975 ;
     RECT  64.692 64.411 64.71 64.975 ;
     RECT  32.184 31.657 32.202 64.987 ;
     RECT  52.74 63.824 52.758 65.011 ;
     RECT  54 64.975 64.71 65.011 ;
     RECT  31.5 64.987 32.202 65.129 ;
     RECT  50.436 62.159 51.966 65.245 ;
     RECT  52.74 65.011 64.71 65.245 ;
     RECT  13.215 63.689 13.497 65.272 ;
     RECT  34.815 56.669 35.097 65.272 ;
     RECT  45.615 63.779 45.897 65.272 ;
     RECT  50.436 65.245 64.71 65.399 ;
     RECT  0.108 62.843 10.098 65.515 ;
     RECT  11.088 62.477 11.106 65.515 ;
     RECT  13.104 65.272 13.497 65.849 ;
     RECT  34.704 65.272 35.097 65.849 ;
     RECT  45.504 65.272 45.897 65.849 ;
     RECT  0.108 65.515 11.106 66.173 ;
     RECT  50.436 65.399 64.674 66.245 ;
     RECT  48.276 62.195 48.438 66.479 ;
     RECT  64.692 66.379 64.71 66.479 ;
     RECT  46.8 66.475 46.818 66.487 ;
     RECT  46.8 66.487 47.142 66.515 ;
     RECT  50.436 66.245 63.954 66.551 ;
     RECT  47.124 66.515 47.142 66.557 ;
     RECT  50.436 66.551 60.534 66.701 ;
     RECT  0.468 66.173 11.106 66.907 ;
     RECT  58.644 66.701 60.534 66.929 ;
     RECT  0.108 66.907 11.106 67.127 ;
     RECT  58.68 66.929 60.534 67.441 ;
     RECT  34.815 65.849 35.097 67.525 ;
     RECT  13.215 65.849 13.497 67.531 ;
     RECT  45.615 65.849 45.897 67.531 ;
     RECT  34.704 67.525 35.097 67.565 ;
     RECT  58.68 67.441 60.642 67.567 ;
     RECT  61.524 66.551 63.954 67.567 ;
     RECT  13.104 67.531 13.497 67.568 ;
     RECT  45.504 67.531 45.897 67.568 ;
     RECT  58.68 67.567 63.954 67.949 ;
     RECT  64.692 68.872 64.71 68.909 ;
     RECT  58.68 67.949 60.786 68.917 ;
     RECT  61.524 67.949 63.954 68.917 ;
     RECT  0.468 67.127 11.106 69.163 ;
     RECT  50.436 66.701 57.906 69.251 ;
     RECT  0.108 69.163 11.106 69.359 ;
     RECT  0.144 69.359 11.106 69.437 ;
     RECT  50.436 69.251 53.19 69.521 ;
     RECT  53.928 69.251 57.906 69.719 ;
     RECT  52.38 69.521 53.19 69.755 ;
     RECT  52.74 69.755 53.19 69.989 ;
     RECT  52.74 69.989 53.082 70.025 ;
     RECT  54 69.719 57.906 70.105 ;
     RECT  58.68 68.917 63.954 70.105 ;
     RECT  0.468 69.437 11.106 70.259 ;
     RECT  64.692 70.411 64.71 70.448 ;
     RECT  0.54 70.259 11.106 71.611 ;
     RECT  54 70.105 63.954 71.725 ;
     RECT  29.415 36.845 29.697 72.031 ;
     RECT  32.184 65.129 32.202 72.149 ;
     RECT  53.604 71.725 63.954 72.257 ;
     RECT  0.108 71.611 11.106 72.509 ;
     RECT  54 72.257 63.954 72.571 ;
     RECT  64.692 72.031 64.71 72.571 ;
     RECT  54 72.571 64.71 72.653 ;
     RECT  48.42 66.479 48.438 72.689 ;
     RECT  29.415 72.031 30.222 72.797 ;
     RECT  54 72.653 64.674 72.893 ;
     RECT  0.54 72.509 11.106 73.075 ;
     RECT  0.54 73.075 11.178 73.229 ;
     RECT  23.04 63.821 24.297 73.345 ;
     RECT  13.215 67.568 13.497 73.471 ;
     RECT  15.66 72.157 15.678 73.471 ;
     RECT  34.815 67.565 35.097 73.471 ;
     RECT  45.615 67.568 45.897 73.471 ;
     RECT  22.824 73.345 24.297 73.499 ;
     RECT  30.78 73.345 30.798 73.499 ;
     RECT  42.876 54.509 42.894 73.499 ;
     RECT  13.104 73.471 13.497 73.517 ;
     RECT  34.704 73.471 35.097 73.517 ;
     RECT  45.504 73.471 45.897 73.517 ;
     RECT  64.692 73.849 64.71 73.901 ;
     RECT  0.54 73.229 10.854 74.929 ;
     RECT  64.692 75.199 64.71 75.389 ;
     RECT  13.215 73.517 13.497 75.541 ;
     RECT  0.54 74.929 11.466 76.027 ;
     RECT  12.348 72.697 12.366 76.075 ;
     RECT  0.108 76.027 11.466 76.157 ;
     RECT  0.54 76.157 11.466 76.315 ;
     RECT  12.348 76.075 12.402 76.315 ;
     RECT  0.54 76.315 12.402 76.351 ;
     RECT  13.215 75.541 13.698 76.379 ;
     RECT  54 72.893 63.954 76.445 ;
     RECT  58.68 76.445 63.954 76.505 ;
     RECT  0.54 76.351 12.438 76.981 ;
     RECT  0.468 76.981 12.438 77.125 ;
     RECT  13.215 76.379 13.497 77.125 ;
     RECT  54 76.445 57.942 77.251 ;
     RECT  58.68 76.505 60.426 77.251 ;
     RECT  52.74 70.025 52.758 77.279 ;
     RECT  54 77.251 60.426 77.395 ;
     RECT  61.452 76.505 63.954 77.395 ;
     RECT  50.436 69.521 51.297 77.431 ;
     RECT  54 77.395 63.954 77.611 ;
     RECT  53.964 77.611 63.954 77.629 ;
     RECT  0.468 77.125 13.497 77.645 ;
     RECT  53.964 77.629 64.062 77.657 ;
     RECT  4.068 77.645 13.497 77.659 ;
     RECT  54 77.657 64.062 77.774 ;
     RECT  50.436 77.431 51.894 77.819 ;
     RECT  54 77.774 64.026 77.891 ;
     RECT  4.068 77.659 13.842 77.963 ;
     RECT  54 77.891 60.498 78.089 ;
     RECT  4.14 77.963 13.842 78.367 ;
     RECT  15.66 73.471 16.326 78.403 ;
     RECT  15.372 78.403 16.326 78.439 ;
     RECT  54.144 78.089 60.498 78.637 ;
     RECT  61.452 77.891 64.026 78.637 ;
     RECT  54.144 78.637 64.026 78.667 ;
     RECT  0.468 77.645 3.258 78.673 ;
     RECT  54.144 78.667 64.638 78.701 ;
     RECT  0.468 78.673 3.33 78.781 ;
     RECT  4.14 78.367 14.166 78.781 ;
     RECT  15.156 78.439 16.326 78.781 ;
     RECT  61.452 78.701 64.638 78.893 ;
     RECT  54.144 78.701 60.498 78.899 ;
     RECT  0.468 78.781 16.326 79.099 ;
     RECT  0.108 79.099 16.326 79.229 ;
     RECT  0.18 79.229 16.326 79.373 ;
     RECT  0.468 79.373 16.326 79.475 ;
     RECT  4.104 79.475 16.326 79.709 ;
     RECT  4.14 79.709 16.326 80.329 ;
     RECT  0.468 79.475 3.33 80.587 ;
     RECT  0.108 80.587 3.33 80.627 ;
     RECT  0.54 80.627 3.33 80.797 ;
     RECT  4.14 80.329 16.434 80.797 ;
     RECT  0.54 80.797 16.434 81.019 ;
     RECT  0.54 81.019 16.866 81.067 ;
     RECT  18.615 60.809 18.897 81.307 ;
     RECT  0.54 81.067 17.334 81.403 ;
     RECT  18.615 81.307 18.99 81.437 ;
     RECT  0.54 81.403 17.658 81.509 ;
     RECT  0.54 81.509 17.55 81.629 ;
     RECT  54.144 78.899 60.426 81.679 ;
     RECT  61.452 78.893 63.99 81.679 ;
     RECT  54.144 81.679 63.99 81.779 ;
     RECT  54.144 81.779 60.426 81.841 ;
     RECT  18.615 81.437 18.897 82.111 ;
     RECT  53.604 81.841 60.426 82.139 ;
     RECT  4.14 81.629 17.55 82.255 ;
     RECT  18.432 82.111 18.897 82.255 ;
     RECT  0.54 81.629 3.33 82.267 ;
     RECT  0.108 82.267 3.33 82.397 ;
     RECT  54.144 82.139 60.426 82.561 ;
     RECT  61.452 81.779 63.99 82.843 ;
     RECT  4.14 82.255 18.897 82.939 ;
     RECT  19.944 82.921 19.962 82.939 ;
     RECT  50.436 77.819 51.297 82.949 ;
     RECT  0.54 82.397 3.33 83.029 ;
     RECT  4.14 82.939 19.962 83.029 ;
     RECT  54.144 82.561 60.462 83.029 ;
     RECT  61.452 82.843 64.71 83.029 ;
     RECT  54.144 83.029 64.71 83.129 ;
     RECT  0.54 83.029 19.962 83.275 ;
     RECT  0.54 83.275 20.07 83.291 ;
     RECT  0.648 83.291 20.07 83.611 ;
     RECT  21.06 83.323 21.078 83.611 ;
     RECT  54.144 83.129 63.99 83.759 ;
     RECT  54.144 83.759 60.642 83.795 ;
     RECT  0.648 83.611 21.078 84.001 ;
     RECT  0.648 84.001 21.654 84.077 ;
     RECT  0.648 84.077 21.078 84.271 ;
     RECT  34.815 73.517 35.097 84.271 ;
     RECT  45.615 73.517 45.897 84.271 ;
     RECT  34.704 84.271 35.097 84.317 ;
     RECT  45.504 84.271 45.897 84.317 ;
     RECT  61.452 83.759 63.99 84.343 ;
     RECT  0.54 84.271 21.078 84.605 ;
     RECT  61.452 84.343 64.71 84.605 ;
     RECT  54.144 83.795 60.57 84.883 ;
     RECT  61.452 84.605 64.062 84.883 ;
     RECT  61.416 84.883 64.062 84.941 ;
     RECT  54.144 84.883 60.642 84.991 ;
     RECT  61.416 84.941 63.99 84.991 ;
     RECT  54.144 84.991 63.99 85.517 ;
     RECT  23.04 73.499 24.297 85.915 ;
     RECT  21.816 84.811 21.834 86.059 ;
     RECT  22.86 85.915 24.297 86.059 ;
     RECT  0.648 84.605 21.078 86.299 ;
     RECT  21.816 86.059 24.297 86.299 ;
     RECT  54.144 85.517 60.57 86.305 ;
     RECT  0.648 86.299 24.297 86.333 ;
     RECT  54.144 86.305 60.606 86.341 ;
     RECT  61.452 85.517 63.99 86.341 ;
     RECT  4.032 86.333 24.297 86.431 ;
     RECT  34.815 84.317 35.097 86.431 ;
     RECT  45.615 84.317 45.897 86.431 ;
     RECT  4.032 86.431 24.498 86.467 ;
     RECT  51.015 82.949 51.297 86.827 ;
     RECT  54.144 86.341 60.714 86.845 ;
     RECT  61.452 86.341 64.71 86.845 ;
     RECT  4.032 86.467 24.57 86.875 ;
     RECT  54.144 86.845 64.71 86.909 ;
     RECT  34.704 86.431 35.097 87.005 ;
     RECT  50.904 86.827 51.297 87.005 ;
     RECT  45.504 86.431 45.897 87.008 ;
     RECT  0.648 86.333 3.258 87.079 ;
     RECT  26.748 86.971 26.766 87.101 ;
     RECT  4.032 86.875 24.606 87.151 ;
     RECT  0.54 87.079 3.258 87.341 ;
     RECT  3.996 87.151 24.606 87.511 ;
     RECT  3.996 87.511 25.074 87.581 ;
     RECT  54.144 86.909 63.99 87.683 ;
     RECT  0.648 87.341 3.258 87.781 ;
     RECT  3.996 87.581 24.606 87.781 ;
     RECT  0.648 87.781 24.606 87.821 ;
     RECT  0.648 87.821 24.498 88.321 ;
     RECT  54.144 87.683 60.426 88.429 ;
     RECT  61.452 87.683 63.99 88.429 ;
     RECT  38.016 55.517 38.538 88.529 ;
     RECT  0.54 88.321 24.498 88.651 ;
     RECT  0.144 88.651 24.498 88.663 ;
     RECT  25.632 88.591 25.65 88.663 ;
     RECT  26.712 88.699 26.73 88.771 ;
     RECT  0.144 88.663 25.65 88.829 ;
     RECT  26.712 88.771 26.802 88.891 ;
     RECT  26.532 88.891 26.802 88.925 ;
     RECT  34.815 87.005 35.097 89.125 ;
     RECT  0.54 88.829 25.65 89.131 ;
     RECT  26.532 88.925 26.55 89.131 ;
     RECT  45.615 87.008 45.897 89.131 ;
     RECT  34.704 89.125 35.097 89.165 ;
     RECT  45.504 89.131 45.897 89.168 ;
     RECT  27.324 89.401 27.342 89.453 ;
     RECT  0.54 89.131 26.55 89.597 ;
     RECT  0.648 89.597 26.55 90.013 ;
     RECT  0.648 90.013 27.09 90.077 ;
     RECT  30.744 89.947 30.762 90.077 ;
     RECT  27.864 90.043 27.882 90.149 ;
     RECT  0.648 90.077 27.018 90.589 ;
     RECT  54.144 88.429 63.99 91.165 ;
     RECT  0.54 90.589 27.018 91.195 ;
     RECT  27.936 91.129 27.954 91.195 ;
     RECT  0.54 91.195 27.954 91.325 ;
     RECT  54.144 91.165 64.71 91.325 ;
     RECT  0.648 91.325 27.954 91.435 ;
     RECT  0.648 91.435 28.026 91.499 ;
     RECT  2.088 91.499 28.026 91.903 ;
     RECT  0.648 91.499 1.17 92.059 ;
     RECT  0.108 92.059 1.17 92.237 ;
     RECT  2.088 91.903 28.674 92.713 ;
     RECT  29.415 72.797 29.697 92.713 ;
     RECT  54.144 91.325 63.99 92.827 ;
     RECT  34.815 89.165 35.097 92.911 ;
     RECT  45.615 89.168 45.897 92.911 ;
     RECT  54.144 92.827 64.71 93.119 ;
     RECT  2.088 92.713 29.697 93.181 ;
     RECT  45.504 92.911 45.897 93.389 ;
     RECT  2.088 93.181 30.222 93.451 ;
     RECT  34.704 92.911 35.097 93.485 ;
     RECT  2.088 93.451 30.762 93.739 ;
     RECT  2.088 93.739 30.87 93.785 ;
     RECT  34.815 93.485 35.097 93.991 ;
     RECT  2.088 93.785 30.222 94.061 ;
     RECT  33.444 94.075 33.462 94.289 ;
     RECT  34.815 93.991 35.19 94.301 ;
     RECT  31.068 94.261 31.266 94.411 ;
     RECT  2.088 94.061 27.594 94.531 ;
     RECT  28.332 94.061 30.222 94.603 ;
     RECT  31.068 94.411 31.338 94.603 ;
     RECT  54.144 93.119 63.99 94.631 ;
     RECT  0.648 92.237 1.17 95.143 ;
     RECT  2.052 94.531 27.594 95.207 ;
     RECT  28.332 94.603 31.338 95.227 ;
     RECT  28.332 95.227 31.374 95.341 ;
     RECT  51.015 87.005 51.297 95.371 ;
     RECT  42.768 95.419 42.786 95.549 ;
     RECT  34.815 94.301 35.097 95.605 ;
     RECT  45.615 93.389 45.897 95.611 ;
     RECT  54.144 94.631 60.426 95.611 ;
     RECT  50.904 95.371 51.297 95.645 ;
     RECT  54.144 95.611 60.498 95.719 ;
     RECT  61.452 94.631 63.954 95.719 ;
     RECT  0.54 95.143 1.17 95.803 ;
     RECT  0.108 95.803 1.17 95.981 ;
     RECT  45.504 95.611 45.897 96.089 ;
     RECT  34.704 95.605 35.097 96.125 ;
     RECT  28.332 95.341 31.95 96.331 ;
     RECT  34.815 96.125 35.097 96.427 ;
     RECT  51.015 95.645 51.297 96.427 ;
     RECT  34.815 96.427 35.19 96.557 ;
     RECT  50.724 96.427 51.297 96.557 ;
     RECT  28.332 96.331 32.238 96.601 ;
     RECT  33.012 95.647 33.03 96.601 ;
     RECT  34.815 96.557 35.097 96.997 ;
     RECT  28.332 96.601 33.03 97.003 ;
     RECT  28.332 97.003 33.102 97.051 ;
     RECT  28.332 97.051 33.606 97.141 ;
     RECT  0.648 95.981 1.17 97.411 ;
     RECT  34.74 96.997 35.097 97.501 ;
     RECT  28.332 97.141 33.966 97.573 ;
     RECT  34.704 97.501 35.097 97.573 ;
     RECT  64.692 97.771 64.71 97.901 ;
     RECT  0.54 97.411 1.17 97.915 ;
     RECT  28.332 97.573 35.097 98.041 ;
     RECT  28.332 98.041 35.334 98.609 ;
     RECT  0.108 97.915 1.17 98.813 ;
     RECT  0.54 98.813 1.17 99.293 ;
     RECT  28.332 98.609 35.19 99.463 ;
     RECT  36.504 99.391 36.522 99.547 ;
     RECT  36.504 99.547 36.918 99.571 ;
     RECT  28.332 99.463 35.442 99.661 ;
     RECT  36.216 99.571 36.918 99.661 ;
     RECT  28.332 99.661 36.918 99.689 ;
     RECT  64.692 99.787 64.71 99.833 ;
     RECT  54.144 95.719 63.954 100.103 ;
     RECT  0.648 99.293 1.17 100.111 ;
     RECT  28.332 99.689 36.522 100.507 ;
     RECT  0.54 100.111 1.17 100.541 ;
     RECT  28.332 100.507 37.026 100.544 ;
     RECT  54.144 100.103 60.642 100.921 ;
     RECT  61.452 100.103 63.954 100.921 ;
     RECT  38.016 88.529 38.034 101.191 ;
     RECT  2.124 95.207 27.594 101.213 ;
     RECT  28.332 100.544 36.702 101.317 ;
     RECT  0.648 100.541 1.17 101.389 ;
     RECT  64.692 101.275 64.71 101.453 ;
     RECT  37.944 101.191 38.754 101.461 ;
     RECT  54.144 100.921 63.954 101.549 ;
     RECT  45.615 96.089 45.897 101.551 ;
     RECT  54.144 101.549 62.514 101.579 ;
     RECT  0.54 101.389 1.17 101.755 ;
     RECT  28.332 101.317 37.026 101.821 ;
     RECT  37.836 101.461 38.754 101.821 ;
     RECT  3.708 101.213 27.594 101.965 ;
     RECT  28.332 101.821 38.754 102.029 ;
     RECT  51.015 96.557 51.297 102.091 ;
     RECT  45.504 101.551 45.897 102.128 ;
     RECT  0.108 101.755 1.17 102.221 ;
     RECT  2.124 101.213 2.898 102.271 ;
     RECT  3.672 101.965 27.594 102.271 ;
     RECT  54.144 101.579 62.298 102.361 ;
     RECT  63.288 101.549 63.954 102.361 ;
     RECT  50.904 102.091 51.297 102.413 ;
     RECT  54.144 102.361 63.954 102.533 ;
     RECT  63.252 102.533 63.954 102.631 ;
     RECT  63.252 102.631 63.99 102.803 ;
     RECT  36.468 102.029 38.754 102.901 ;
     RECT  2.124 102.271 27.594 102.929 ;
     RECT  36.468 102.901 39.33 103.009 ;
     RECT  40.215 39.623 40.497 103.009 ;
     RECT  54.144 102.533 62.19 103.28 ;
     RECT  63.828 102.803 63.99 103.531 ;
     RECT  63.252 103.531 63.99 103.577 ;
     RECT  0.648 102.221 1.17 103.711 ;
     RECT  54.144 103.28 62.154 104.009 ;
     RECT  0.54 103.711 1.17 104.395 ;
     RECT  36.468 103.009 40.497 104.521 ;
     RECT  63.288 103.577 63.99 104.525 ;
     RECT  36.468 104.521 41.13 104.573 ;
     RECT  2.124 102.929 2.862 104.701 ;
     RECT  3.744 102.929 27.594 104.701 ;
     RECT  2.124 104.701 27.594 104.855 ;
     RECT  54.144 104.009 62.097 104.875 ;
     RECT  0.108 104.395 1.17 105.053 ;
     RECT  41.58 105.211 41.598 105.241 ;
     RECT  63.864 104.525 63.99 105.359 ;
     RECT  41.58 105.241 42.03 105.403 ;
     RECT  2.124 104.855 3.186 105.437 ;
     RECT  41.58 105.403 42.642 105.44 ;
     RECT  63.864 105.359 63.918 105.499 ;
     RECT  2.124 105.437 2.898 105.503 ;
     RECT  54.144 104.875 62.406 105.511 ;
     RECT  63.252 105.499 63.918 105.511 ;
     RECT  3.996 104.855 27.594 105.595 ;
     RECT  3.924 105.595 27.594 105.637 ;
     RECT  36.468 104.573 40.806 105.673 ;
     RECT  41.58 105.44 42.03 105.673 ;
     RECT  54.144 105.511 63.918 105.773 ;
     RECT  61.815 105.773 63.918 105.809 ;
     RECT  3.816 105.637 27.594 105.869 ;
     RECT  61.815 105.809 62.154 105.935 ;
     RECT  0.648 105.053 1.17 105.979 ;
     RECT  54.144 105.773 61.074 106.169 ;
     RECT  54.144 106.169 61.002 106.205 ;
     RECT  64.692 106.267 64.71 106.313 ;
     RECT  3.924 105.869 27.594 106.681 ;
     RECT  61.815 105.935 62.097 106.681 ;
     RECT  63.288 105.809 63.918 106.681 ;
     RECT  54.144 106.205 60.822 106.753 ;
     RECT  0.54 105.979 1.17 106.795 ;
     RECT  2.124 105.503 2.862 106.825 ;
     RECT  3.888 106.681 27.594 106.825 ;
     RECT  36.468 105.673 42.03 106.951 ;
     RECT  53.64 106.753 60.822 106.979 ;
     RECT  0.144 106.795 1.17 107.021 ;
     RECT  36.468 106.951 42.786 107.221 ;
     RECT  54.144 106.979 60.822 107.221 ;
     RECT  54.144 107.221 61.038 107.329 ;
     RECT  61.815 106.681 63.918 107.329 ;
     RECT  54.144 107.329 63.918 107.429 ;
     RECT  61.815 107.429 63.918 107.549 ;
     RECT  36.468 107.221 43.398 107.761 ;
     RECT  0.54 107.021 1.17 108.029 ;
     RECT  54.144 107.429 61.038 108.131 ;
     RECT  46.728 108.043 46.746 108.173 ;
     RECT  61.02 108.131 61.038 108.239 ;
     RECT  36.468 107.761 43.758 108.283 ;
     RECT  61.815 107.549 62.73 108.409 ;
     RECT  63.9 107.549 63.918 108.409 ;
     RECT  2.124 106.825 27.594 108.473 ;
     RECT  36.468 108.283 43.83 108.619 ;
     RECT  36.468 108.619 44.082 108.679 ;
     RECT  0.648 108.029 1.17 108.841 ;
     RECT  61.815 108.409 63.918 109.037 ;
     RECT  54.144 108.131 60.282 109.111 ;
     RECT  36.468 108.679 44.37 109.147 ;
     RECT  45.615 102.128 45.897 109.147 ;
     RECT  54.144 109.111 60.318 109.183 ;
     RECT  54.144 109.183 60.354 109.219 ;
     RECT  2.124 108.473 4.374 109.255 ;
     RECT  5.112 108.473 27.594 109.255 ;
     RECT  61.815 109.037 62.097 109.291 ;
     RECT  54.144 109.219 60.534 109.417 ;
     RECT  61.272 109.291 62.097 109.417 ;
     RECT  0.54 108.841 1.17 109.531 ;
     RECT  0.144 109.531 1.17 109.757 ;
     RECT  63.288 109.037 63.918 109.757 ;
     RECT  2.124 109.255 27.594 109.787 ;
     RECT  36.468 109.147 45.897 109.819 ;
     RECT  54.144 109.417 62.097 109.831 ;
     RECT  0.54 109.757 1.17 110.045 ;
     RECT  2.124 109.787 2.898 110.399 ;
     RECT  36.468 109.819 46.026 110.461 ;
     RECT  54.144 109.831 62.73 110.525 ;
     RECT  3.708 109.787 27.594 110.641 ;
     RECT  36.468 110.461 46.782 110.641 ;
     RECT  63.864 109.757 63.918 110.731 ;
     RECT  3.636 110.641 27.594 111.065 ;
     RECT  36.468 110.641 47.286 111.163 ;
     RECT  54.144 110.525 62.097 111.299 ;
     RECT  0.648 110.045 1.17 111.403 ;
     RECT  36.468 111.163 47.502 111.451 ;
     RECT  61.308 111.299 62.097 111.451 ;
     RECT  63.252 110.731 63.918 111.451 ;
     RECT  0.108 111.403 1.17 111.533 ;
     RECT  51.015 102.413 51.297 111.613 ;
     RECT  50.724 111.613 51.297 111.713 ;
     RECT  36.468 111.451 48.186 111.839 ;
     RECT  54.144 111.299 60.462 111.839 ;
     RECT  0.144 111.533 1.17 111.965 ;
     RECT  61.308 111.451 63.918 111.983 ;
     RECT  2.124 110.399 2.862 111.991 ;
     RECT  3.708 111.065 27.594 111.991 ;
     RECT  58.68 111.839 59.166 112.145 ;
     RECT  60.264 111.839 60.462 112.531 ;
     RECT  60.264 112.531 60.642 112.685 ;
     RECT  36.468 111.839 47.934 112.693 ;
     RECT  54.144 111.839 57.474 112.801 ;
     RECT  58.68 112.145 58.698 112.801 ;
     RECT  36.468 112.693 48.294 112.999 ;
     RECT  54.144 112.801 58.698 113.027 ;
     RECT  36.468 112.999 48.618 113.035 ;
     RECT  51.015 111.713 51.297 113.161 ;
     RECT  50.724 113.161 51.297 113.333 ;
     RECT  61.815 111.983 63.918 113.501 ;
     RECT  36.468 113.035 48.906 113.845 ;
     RECT  49.644 113.809 49.662 113.845 ;
     RECT  0.648 111.965 1.17 113.881 ;
     RECT  36.468 113.845 49.662 113.881 ;
     RECT  54.216 113.027 58.698 113.971 ;
     RECT  60.264 112.685 60.282 113.995 ;
     RECT  63.288 113.501 63.918 114.029 ;
     RECT  54.216 113.971 59.346 114.035 ;
     RECT  61.815 113.501 62.154 114.043 ;
     RECT  61.56 114.043 62.154 114.269 ;
     RECT  54.252 114.035 59.346 114.305 ;
     RECT  54.288 114.305 59.346 114.376 ;
     RECT  60.264 113.995 60.426 114.376 ;
     RECT  0.54 113.881 1.17 114.379 ;
     RECT  54.288 114.376 60.426 114.413 ;
     RECT  0.108 114.379 1.17 114.509 ;
     RECT  64.692 114.475 64.71 114.539 ;
     RECT  61.815 114.269 62.154 114.691 ;
     RECT  61.815 114.691 62.73 114.749 ;
     RECT  36.468 113.881 50.13 114.781 ;
     RECT  59.796 114.413 60.426 114.809 ;
     RECT  51.015 113.333 51.297 114.925 ;
     RECT  54.288 114.413 58.878 115.079 ;
     RECT  51.015 114.925 51.318 115.123 ;
     RECT  61.815 114.749 62.154 115.147 ;
     RECT  0.144 114.509 1.17 115.277 ;
     RECT  36.468 114.781 50.202 115.393 ;
     RECT  51.015 115.123 51.354 115.393 ;
     RECT  36.468 115.393 51.354 115.501 ;
     RECT  61.632 115.147 62.154 115.663 ;
     RECT  54.288 115.079 58.806 115.691 ;
     RECT  61.308 115.663 62.154 115.709 ;
     RECT  63.864 114.029 63.918 115.963 ;
     RECT  0.504 115.277 1.17 115.997 ;
     RECT  54.324 115.691 58.806 116.041 ;
     RECT  63.828 115.963 63.918 116.159 ;
     RECT  54.324 116.041 59.274 116.299 ;
     RECT  60.408 114.809 60.426 116.311 ;
     RECT  61.815 115.709 62.154 116.401 ;
     RECT  36.468 115.501 52.038 116.437 ;
     RECT  61.815 116.401 62.694 116.477 ;
     RECT  54.324 116.299 59.382 116.509 ;
     RECT  54.288 116.509 59.382 116.699 ;
     RECT  54.288 116.699 58.986 116.843 ;
     RECT  60.408 116.311 60.786 116.851 ;
     RECT  60.192 116.851 60.966 116.879 ;
     RECT  53.424 116.707 53.442 117.085 ;
     RECT  60.948 116.879 60.966 117.113 ;
     RECT  61.815 116.477 62.478 117.239 ;
     RECT  54.288 116.843 56.697 117.247 ;
     RECT  61.815 117.239 62.37 117.247 ;
     RECT  64.692 117.211 64.71 117.347 ;
     RECT  2.124 111.991 27.594 117.581 ;
     RECT  52.884 117.085 53.442 117.589 ;
     RECT  54.18 117.247 56.697 117.589 ;
     RECT  2.124 117.581 4.302 117.653 ;
     RECT  63.864 116.159 63.918 117.661 ;
     RECT  0.54 115.997 1.17 117.751 ;
     RECT  52.884 117.589 56.697 117.787 ;
     RECT  57.564 116.843 58.986 117.787 ;
     RECT  52.884 117.787 58.986 117.859 ;
     RECT  61.38 117.247 62.37 117.979 ;
     RECT  61.38 117.979 62.514 118.129 ;
     RECT  0.504 117.751 1.17 118.253 ;
     RECT  60.192 116.879 60.21 118.291 ;
     RECT  61.02 118.129 62.514 118.291 ;
     RECT  60.192 118.291 62.514 118.327 ;
     RECT  63.288 117.661 63.918 118.327 ;
     RECT  52.884 117.859 59.094 118.355 ;
     RECT  60.192 118.327 63.918 118.435 ;
     RECT  2.124 117.653 4.158 118.499 ;
     RECT  5.112 117.581 27.594 118.597 ;
     RECT  60.156 118.435 63.918 118.597 ;
     RECT  4.788 118.597 27.594 118.637 ;
     RECT  59.868 118.597 63.918 118.733 ;
     RECT  59.868 118.733 62.097 118.859 ;
     RECT  57.852 118.355 59.094 118.895 ;
     RECT  63.252 118.733 63.918 118.895 ;
     RECT  0.648 118.253 1.17 119.011 ;
     RECT  2.124 118.499 4.05 119.129 ;
     RECT  58.068 118.895 59.094 119.129 ;
     RECT  58.14 119.129 59.094 119.137 ;
     RECT  2.124 119.129 2.898 119.309 ;
     RECT  3.636 119.129 4.05 119.479 ;
     RECT  52.884 118.355 56.826 119.479 ;
     RECT  0.504 119.011 1.17 119.501 ;
     RECT  3.636 119.479 4.194 119.551 ;
     RECT  5.112 118.637 27.594 119.551 ;
     RECT  3.636 119.551 27.594 119.669 ;
     RECT  3.636 119.669 4.266 119.705 ;
     RECT  58.14 119.137 59.13 119.707 ;
     RECT  59.94 118.859 62.097 119.707 ;
     RECT  3.636 119.705 4.23 119.741 ;
     RECT  63.252 118.895 63.846 119.741 ;
     RECT  58.14 119.707 62.097 119.821 ;
     RECT  52.884 119.479 57.186 119.983 ;
     RECT  52.884 119.983 57.222 120.019 ;
     RECT  58.14 119.821 62.766 120.019 ;
     RECT  63.828 119.741 63.846 120.181 ;
     RECT  52.884 120.019 62.766 120.221 ;
     RECT  3.636 119.741 4.194 120.631 ;
     RECT  5.112 119.669 27.594 120.631 ;
     RECT  52.884 120.221 62.73 120.989 ;
     RECT  63.828 120.181 63.882 121.099 ;
     RECT  0.54 119.501 1.17 121.171 ;
     RECT  0.108 121.171 1.17 121.229 ;
     RECT  63.288 121.099 63.882 121.229 ;
     RECT  3.636 120.631 27.594 121.469 ;
     RECT  63.324 121.229 63.882 121.469 ;
     RECT  63.864 121.469 63.882 121.709 ;
     RECT  52.884 120.989 62.514 121.997 ;
     RECT  0.54 121.229 1.17 122.237 ;
     RECT  63.252 122.203 63.27 122.44 ;
     RECT  63.252 122.44 63.846 122.477 ;
     RECT  5.004 121.469 27.594 122.485 ;
     RECT  3.636 121.469 4.05 122.611 ;
     RECT  63.252 122.477 63.306 122.639 ;
     RECT  52.884 121.997 62.334 122.717 ;
     RECT  3.636 122.611 4.122 122.791 ;
     RECT  4.932 122.485 27.594 122.791 ;
     RECT  63.288 122.639 63.306 123.223 ;
     RECT  63.288 123.223 63.882 123.245 ;
     RECT  2.124 119.309 2.862 123.295 ;
     RECT  3.636 122.791 27.594 123.295 ;
     RECT  63.864 123.245 63.882 123.421 ;
     RECT  0.648 122.237 1.17 123.529 ;
     RECT  52.884 122.717 62.097 123.601 ;
     RECT  2.124 123.295 27.594 123.629 ;
     RECT  0.504 123.529 1.17 123.965 ;
     RECT  52.884 123.601 62.298 124.105 ;
     RECT  63.864 123.421 63.918 124.141 ;
     RECT  63.288 124.141 63.918 124.205 ;
     RECT  52.848 124.105 62.298 124.411 ;
     RECT  2.124 123.629 2.862 124.609 ;
     RECT  3.636 123.629 27.594 124.609 ;
     RECT  36.468 116.437 52.074 124.645 ;
     RECT  52.848 124.411 62.514 124.645 ;
     RECT  36.468 124.645 62.514 124.681 ;
     RECT  36.468 124.681 62.73 124.733 ;
     RECT  2.124 124.609 27.594 124.835 ;
     RECT  36.468 124.733 62.514 124.973 ;
     RECT  63.864 124.205 63.918 125.179 ;
     RECT  63.828 125.179 63.918 125.185 ;
     RECT  63.324 125.185 63.918 125.453 ;
     RECT  2.124 124.835 2.862 125.689 ;
     RECT  0.54 123.965 1.17 125.693 ;
     RECT  63.324 125.453 63.882 125.693 ;
     RECT  36.468 124.973 62.097 125.725 ;
     RECT  63.324 125.693 63.378 125.725 ;
     RECT  2.124 125.689 2.898 125.761 ;
     RECT  3.636 124.835 27.594 125.761 ;
     RECT  0.648 125.693 1.17 125.923 ;
     RECT  2.124 125.761 27.594 125.923 ;
     RECT  36.468 125.725 63.378 126.461 ;
     RECT  0.648 125.923 27.594 126.535 ;
     RECT  28.332 102.029 35.73 126.535 ;
     RECT  0.648 126.535 35.73 126.811 ;
     RECT  0.108 126.811 35.73 126.941 ;
     RECT  0.648 126.941 35.73 127.103 ;
     RECT  0.648 127.103 8.097 127.187 ;
     RECT  36.468 126.461 63.306 127.201 ;
     RECT  36.468 127.201 63.882 127.229 ;
     RECT  64.62 127.195 64.638 127.291 ;
     RECT  64.62 127.291 64.71 127.469 ;
     RECT  61.164 127.229 63.882 127.471 ;
     RECT  64.62 127.469 64.638 127.471 ;
     RECT  61.164 127.471 64.638 127.517 ;
     RECT  61.164 127.517 63.954 127.535 ;
     RECT  61.164 127.535 61.182 127.571 ;
     RECT  0.648 127.187 8.082 127.709 ;
     RECT  61.92 127.535 63.954 127.757 ;
     RECT  36.468 127.229 60.426 127.949 ;
     RECT  63.864 127.757 63.954 128.264 ;
     RECT  0.648 127.709 2.358 128.717 ;
     RECT  3.132 127.709 8.082 128.776 ;
     RECT  9.036 127.103 35.73 128.776 ;
     RECT  2.124 128.717 2.358 128.827 ;
     RECT  3.132 128.776 35.73 128.827 ;
     RECT  36.468 127.949 58.95 128.827 ;
     RECT  59.94 127.949 60.426 128.827 ;
     RECT  61.92 127.757 62.91 128.875 ;
     RECT  63.864 128.264 63.882 128.875 ;
     RECT  0.648 128.717 1.17 129.499 ;
     RECT  2.124 128.827 35.73 129.499 ;
     RECT  36.468 128.827 60.93 129.499 ;
     RECT  61.92 128.875 63.882 129.499 ;
     RECT  0.648 129.499 63.882 129.581 ;
    LAYER M4 ;
     RECT  0.025 6.72 0.06 6.744 ;
     RECT  0.06 0.672 1.645 128.952 ;
     RECT  1.645 0.672 1.763 129.528 ;
     RECT  1.763 0.672 2.435 129.48 ;
     RECT  2.435 0.672 2.657 128.952 ;
     RECT  2.657 0.672 2.704 127.944 ;
     RECT  2.704 0.672 2.729 5.736 ;
     RECT  2.729 2.496 2.765 5.736 ;
     RECT  2.704 58.176 2.765 119.736 ;
     RECT  2.704 125.184 2.765 127.944 ;
     RECT  2.704 21.984 2.819 56.76 ;
     RECT  2.704 6.72 2.837 16.392 ;
     RECT  2.819 21.984 2.86 27.816 ;
     RECT  2.765 85.104 2.867 119.736 ;
     RECT  2.86 21.984 2.945 27.72 ;
     RECT  2.819 28.8 2.963 56.76 ;
     RECT  2.837 6.72 2.981 16.248 ;
     RECT  2.867 85.104 3.196 117.816 ;
     RECT  2.765 2.496 3.269 3.288 ;
     RECT  2.704 17.376 3.269 20.856 ;
     RECT  2.945 26.64 3.395 27.72 ;
     RECT  2.657 128.928 3.413 128.952 ;
     RECT  3.269 3.264 3.449 3.288 ;
     RECT  2.765 127.92 3.557 127.944 ;
     RECT  2.981 6.72 3.58 11.304 ;
     RECT  3.196 87.6 3.665 117.816 ;
     RECT  3.269 19.584 3.781 20.856 ;
     RECT  2.945 21.984 3.781 25.608 ;
     RECT  2.765 4.416 3.829 5.736 ;
     RECT  2.765 125.184 3.845 126.84 ;
     RECT  3.781 19.584 3.917 25.608 ;
     RECT  2.963 37.152 3.917 56.76 ;
     RECT  3.829 3.408 3.925 5.736 ;
     RECT  3.58 6.72 3.925 7.656 ;
     RECT  2.729 0.672 3.953 1.416 ;
     RECT  3.665 87.6 3.953 117.672 ;
     RECT  2.765 58.176 3.98 84.12 ;
     RECT  3.196 85.104 3.98 85.992 ;
     RECT  3.917 19.584 3.989 23.928 ;
     RECT  3.917 40.08 4.025 54.744 ;
     RECT  3.917 56.208 4.025 56.76 ;
     RECT  3.953 108.384 4.025 117.672 ;
     RECT  2.704 120.768 4.025 124.152 ;
     RECT  4.025 122.448 4.061 124.152 ;
     RECT  3.98 58.176 4.165 85.992 ;
     RECT  2.867 118.944 4.241 119.736 ;
     RECT  4.165 58.176 4.261 86.616 ;
     RECT  3.953 87.6 4.261 107.304 ;
     RECT  3.58 9.264 4.309 11.304 ;
     RECT  2.981 12.288 4.309 16.248 ;
     RECT  3.917 24.96 4.313 25.608 ;
     RECT  2.963 28.8 4.345 36.072 ;
     RECT  3.917 37.152 4.345 39.048 ;
     RECT  3.269 17.376 4.357 18.216 ;
     RECT  3.989 19.584 4.357 23.88 ;
     RECT  4.025 108.384 4.385 117.624 ;
     RECT  4.309 9.264 4.457 16.248 ;
     RECT  4.357 17.376 4.547 23.88 ;
     RECT  4.313 25.104 4.547 25.608 ;
     RECT  4.025 120.768 4.565 121.464 ;
     RECT  4.261 58.176 4.601 107.304 ;
     RECT  4.601 101.376 4.637 107.304 ;
     RECT  4.547 25.44 4.705 25.608 ;
     RECT  3.395 26.736 4.705 27.72 ;
     RECT  4.025 45.552 4.709 54.744 ;
     RECT  4.241 118.944 4.748 119.64 ;
     RECT  4.061 123.648 4.777 124.152 ;
     RECT  3.845 125.184 4.777 126.696 ;
     RECT  4.025 56.736 4.789 56.76 ;
     RECT  4.601 58.176 4.789 100.296 ;
     RECT  4.777 123.648 4.849 126.696 ;
     RECT  4.705 25.44 4.883 27.72 ;
     RECT  4.385 109.68 4.889 117.624 ;
     RECT  4.883 26.784 4.921 27.72 ;
     RECT  4.345 28.8 4.921 39.048 ;
     RECT  4.565 121.008 4.993 121.464 ;
     RECT  4.061 122.448 4.993 122.472 ;
     RECT  4.921 26.784 5.069 39.048 ;
     RECT  4.547 17.376 5.101 17.928 ;
     RECT  4.547 19.248 5.101 23.88 ;
     RECT  4.385 108.384 5.101 108.408 ;
     RECT  5.101 19.248 5.105 24.072 ;
     RECT  4.457 10.656 5.123 16.248 ;
     RECT  4.993 121.008 5.137 122.472 ;
     RECT  4.849 123.648 5.137 126.792 ;
     RECT  4.789 56.736 5.141 100.296 ;
     RECT  4.025 40.08 5.171 44.424 ;
     RECT  5.105 23.568 5.177 24.072 ;
     RECT  5.069 26.784 5.177 37.032 ;
     RECT  5.141 56.736 5.177 94.056 ;
     RECT  4.889 109.728 5.177 114.456 ;
     RECT  4.748 118.608 5.177 119.64 ;
     RECT  5.177 119.616 5.209 119.64 ;
     RECT  4.457 9.264 5.245 9.624 ;
     RECT  4.889 115.824 5.245 117.624 ;
     RECT  5.177 26.784 5.249 28.824 ;
     RECT  5.177 56.736 5.267 92.136 ;
     RECT  5.069 38.016 5.281 39.048 ;
     RECT  5.171 40.08 5.281 44.376 ;
     RECT  3.953 0.672 5.321 0.696 ;
     RECT  5.245 115.824 5.357 118.584 ;
     RECT  5.281 38.016 5.393 44.376 ;
     RECT  5.177 30.672 5.459 37.032 ;
     RECT  5.393 41.424 5.507 44.376 ;
     RECT  3.925 3.408 5.605 7.656 ;
     RECT  5.459 34.944 5.609 37.032 ;
     RECT  4.709 46.08 5.609 54.744 ;
     RECT  5.267 56.736 5.609 73.416 ;
     RECT  5.609 56.736 5.677 73.368 ;
     RECT  4.883 25.44 5.681 25.464 ;
     RECT  5.245 9.024 5.701 9.624 ;
     RECT  5.123 10.656 5.701 13.608 ;
     RECT  4.637 101.376 5.713 103.32 ;
     RECT  5.177 109.728 5.717 112.056 ;
     RECT  5.677 55.872 5.749 73.368 ;
     RECT  5.713 101.376 5.749 103.56 ;
     RECT  5.749 55.728 5.753 73.368 ;
     RECT  5.101 108.288 5.753 108.408 ;
     RECT  5.101 17.328 5.789 17.928 ;
     RECT  5.141 95.088 5.797 100.296 ;
     RECT  5.749 101.328 5.797 103.56 ;
     RECT  5.137 121.008 5.825 126.792 ;
     RECT  5.209 119.616 5.845 120.024 ;
     RECT  5.825 121.008 5.845 122.76 ;
     RECT  5.177 24.048 5.893 24.072 ;
     RECT  5.249 26.784 5.893 28.776 ;
     RECT  5.393 38.016 5.933 40.44 ;
     RECT  5.845 119.616 5.933 122.76 ;
     RECT  5.797 95.088 5.965 103.56 ;
     RECT  4.637 104.592 5.965 107.304 ;
     RECT  5.753 108.384 6.001 108.408 ;
     RECT  5.717 109.728 6.001 110.568 ;
     RECT  5.507 41.424 6.005 44.232 ;
     RECT  5.357 115.824 6.005 117.624 ;
     RECT  5.221 129.456 6.035 129.48 ;
     RECT  5.105 19.248 6.109 22.344 ;
     RECT  5.701 9.024 6.113 13.608 ;
     RECT  5.605 3.408 6.14 7.704 ;
     RECT  6.113 9.024 6.14 13.416 ;
     RECT  5.893 25.968 6.217 28.776 ;
     RECT  5.177 93.552 6.217 94.056 ;
     RECT  5.965 95.088 6.217 107.304 ;
     RECT  6.14 3.408 6.227 13.416 ;
     RECT  5.123 14.832 6.256 16.248 ;
     RECT  5.933 119.616 6.289 120.024 ;
     RECT  6.005 117.504 6.325 117.624 ;
     RECT  6.289 119.088 6.325 120.024 ;
     RECT  6.325 117.504 6.329 120.024 ;
     RECT  5.825 123.984 6.329 126.792 ;
     RECT  6.227 3.408 6.365 7.896 ;
     RECT  6.217 25.968 6.371 29.496 ;
     RECT  6.217 93.552 6.373 107.304 ;
     RECT  5.933 38.16 6.397 40.44 ;
     RECT  6.005 41.424 6.397 41.448 ;
     RECT  5.609 37.008 6.401 37.032 ;
     RECT  6.005 42.432 6.401 44.232 ;
     RECT  6.256 14.784 6.419 16.248 ;
     RECT  6.371 27.312 6.419 29.496 ;
     RECT  5.789 17.52 6.433 17.928 ;
     RECT  5.609 49.488 6.433 54.744 ;
     RECT  5.753 55.728 6.433 58.728 ;
     RECT  5.459 30.672 6.505 33.96 ;
     RECT  5.177 113.472 6.505 114.456 ;
     RECT  6.005 115.824 6.541 116.472 ;
     RECT  6.505 113.424 6.563 114.456 ;
     RECT  5.717 111.552 6.581 112.056 ;
     RECT  6.329 123.984 6.581 126.696 ;
     RECT  6.505 30.48 6.611 33.96 ;
     RECT  5.609 46.08 6.661 48.36 ;
     RECT  6.419 27.312 6.707 29.352 ;
     RECT  5.267 74.976 6.716 92.136 ;
     RECT  6.373 93.216 6.716 107.304 ;
     RECT  6.661 45.312 6.719 48.36 ;
     RECT  6.433 49.488 6.719 58.728 ;
     RECT  6.433 17.52 6.721 17.976 ;
     RECT  6.707 27.744 6.761 29.352 ;
     RECT  6.721 17.52 6.793 18.264 ;
     RECT  6.371 25.968 6.797 26.184 ;
     RECT  6.761 29.04 6.803 29.352 ;
     RECT  6.719 45.312 6.803 58.728 ;
     RECT  6.109 19.248 6.829 22.488 ;
     RECT  5.893 24.048 6.829 24.12 ;
     RECT  6.829 24.048 6.853 24.168 ;
     RECT  6.793 17.424 6.865 18.264 ;
     RECT  5.753 59.76 6.865 73.368 ;
     RECT  6.865 17.376 6.901 18.264 ;
     RECT  6.829 19.248 6.901 22.824 ;
     RECT  6.853 24.048 6.937 24.504 ;
     RECT  6.797 25.968 6.937 26.04 ;
     RECT  6.716 74.976 6.937 107.304 ;
     RECT  6.541 115.68 6.973 116.472 ;
     RECT  5.609 34.944 7.004 36.024 ;
     RECT  6.937 74.688 7.009 107.304 ;
     RECT  6.611 31.344 7.045 33.96 ;
     RECT  7.004 34.944 7.045 36.696 ;
     RECT  6.865 59.76 7.045 73.56 ;
     RECT  7.009 74.592 7.045 107.304 ;
     RECT  6.227 8.976 7.081 13.416 ;
     RECT  6.563 113.424 7.081 114.36 ;
     RECT  6.397 38.16 7.093 41.448 ;
     RECT  6.401 42.432 7.093 42.792 ;
     RECT  6.001 108.384 7.093 110.568 ;
     RECT  6.581 111.552 7.093 112.008 ;
     RECT  6.803 49.728 7.189 58.728 ;
     RECT  5.933 121.008 7.333 122.76 ;
     RECT  7.189 49.728 7.369 58.776 ;
     RECT  7.045 59.76 7.369 107.304 ;
     RECT  7.093 108.384 7.369 112.008 ;
     RECT  7.093 38.16 7.397 42.792 ;
     RECT  6.401 43.824 7.397 44.232 ;
     RECT  6.419 14.88 7.405 16.248 ;
     RECT  7.405 14.832 7.477 16.248 ;
     RECT  6.901 17.376 7.477 22.824 ;
     RECT  7.397 38.16 7.477 44.232 ;
     RECT  7.477 38.112 7.549 44.232 ;
     RECT  6.803 45.312 7.549 48.696 ;
     RECT  6.973 115.44 7.549 116.472 ;
     RECT  6.329 117.504 7.549 119.544 ;
     RECT  7.333 120.528 7.621 122.76 ;
     RECT  6.581 123.984 7.621 126.6 ;
     RECT  6.365 3.408 7.808 7.704 ;
     RECT  7.081 8.976 7.808 13.656 ;
     RECT  7.477 14.832 7.808 22.824 ;
     RECT  6.937 24.048 7.808 26.04 ;
     RECT  6.761 27.744 7.808 27.768 ;
     RECT  6.803 29.328 7.808 29.352 ;
     RECT  7.045 31.344 7.808 36.696 ;
     RECT  7.549 38.112 7.808 48.696 ;
     RECT  7.369 49.728 7.808 112.008 ;
     RECT  7.081 113.28 7.808 114.36 ;
     RECT  7.549 115.44 7.808 119.544 ;
     RECT  7.621 120.528 7.808 126.6 ;
     RECT  7.808 2.148 7.912 127.452 ;
     RECT  7.912 2.418 8.104 127.182 ;
     RECT  8.104 43.824 8.201 46.056 ;
     RECT  8.104 113.28 8.201 114.36 ;
     RECT  8.104 14.64 8.243 19.368 ;
     RECT  8.104 31.68 8.273 35.304 ;
     RECT  8.104 23.76 8.281 26.04 ;
     RECT  7.813 128.784 8.293 128.808 ;
     RECT  8.104 109.68 8.309 111.912 ;
     RECT  8.243 15.264 8.339 19.368 ;
     RECT  8.104 10.656 8.531 13.656 ;
     RECT  8.281 23.76 8.561 25.032 ;
     RECT  8.104 70.56 8.561 90.312 ;
     RECT  8.561 23.856 8.572 25.032 ;
     RECT  8.572 23.856 8.597 24.168 ;
     RECT  8.561 70.56 8.705 84.84 ;
     RECT  8.104 116.448 8.705 119.544 ;
     RECT  8.104 55.488 8.957 69.48 ;
     RECT  8.339 15.264 9.029 19.32 ;
     RECT  9.029 17.376 9.059 19.32 ;
     RECT  8.309 111.648 9.065 111.912 ;
     RECT  8.104 120.816 9.097 126.792 ;
     RECT  8.705 73.296 9.137 84.84 ;
     RECT  8.957 55.488 9.155 69.288 ;
     RECT  8.705 70.56 9.203 71.976 ;
     RECT  8.705 116.448 9.203 119.496 ;
     RECT  8.293 128.208 9.205 128.808 ;
     RECT  9.137 73.296 9.209 80.52 ;
     RECT  9.155 55.488 9.251 58.872 ;
     RECT  9.097 120.48 9.313 126.792 ;
     RECT  8.273 31.68 9.491 33.96 ;
     RECT  8.104 47.424 9.493 48.408 ;
     RECT  8.104 49.728 9.493 49.848 ;
     RECT  9.203 118.944 9.497 119.496 ;
     RECT  8.104 30.192 9.587 30.216 ;
     RECT  8.104 37.584 9.635 38.52 ;
     RECT  9.209 73.344 9.635 80.52 ;
     RECT  9.155 60 9.683 69.288 ;
     RECT  8.104 94.848 9.685 99.48 ;
     RECT  8.104 100.56 9.685 103.32 ;
     RECT  8.273 35.28 9.731 35.304 ;
     RECT  8.104 51.456 9.749 52.344 ;
     RECT  9.205 128.208 9.749 129.48 ;
     RECT  9.493 47.424 9.821 49.848 ;
     RECT  8.104 104.544 9.857 108.648 ;
     RECT  9.491 31.728 9.875 33.96 ;
     RECT  8.104 39.84 9.923 39.864 ;
     RECT  9.635 37.968 9.971 38.52 ;
     RECT  9.749 128.208 10.001 128.232 ;
     RECT  8.104 41.424 10.019 42.216 ;
     RECT  8.597 24.096 10.067 24.168 ;
     RECT  9.971 37.968 10.115 38.184 ;
     RECT  9.203 71.088 10.261 71.976 ;
     RECT  9.635 73.344 10.261 76.632 ;
     RECT  9.875 31.728 10.307 33.816 ;
     RECT  9.749 129.456 10.348 129.48 ;
     RECT  9.685 94.848 10.357 103.32 ;
     RECT  8.104 20.592 10.403 22.488 ;
     RECT  10.307 31.728 10.499 32.28 ;
     RECT  8.104 93.216 10.501 93.576 ;
     RECT  10.357 94.56 10.501 103.32 ;
     RECT  10.499 31.776 10.547 32.28 ;
     RECT  9.683 60 10.685 66.36 ;
     RECT  10.685 61.968 10.691 66.36 ;
     RECT  10.261 70.704 10.691 71.976 ;
     RECT  9.635 77.664 10.691 80.52 ;
     RECT  9.059 17.376 10.739 19.272 ;
     RECT  9.029 15.264 10.789 16.344 ;
     RECT  10.739 17.376 10.789 19.032 ;
     RECT  9.251 56.496 10.789 58.872 ;
     RECT  8.531 10.656 10.825 13.608 ;
     RECT  10.691 79.152 10.825 80.52 ;
     RECT  8.104 53.328 10.865 54.504 ;
     RECT  10.067 24.096 10.883 24.12 ;
     RECT  8.281 26.016 11.075 26.04 ;
     RECT  10.261 73.248 11.257 76.632 ;
     RECT  10.691 77.664 11.257 77.928 ;
     RECT  8.104 4.128 11.459 7.704 ;
     RECT  10.691 61.968 11.941 66.264 ;
     RECT  9.683 67.536 11.941 69.288 ;
     RECT  11.257 73.248 12.097 77.928 ;
     RECT  12.037 129.456 12.809 129.48 ;
     RECT  9.313 120.48 13.057 127.032 ;
     RECT  11.459 4.176 13.208 7.704 ;
     RECT  8.104 9.024 13.208 9.624 ;
     RECT  10.825 10.656 13.208 13.656 ;
     RECT  10.789 15.264 13.208 19.032 ;
     RECT  10.403 20.592 13.208 20.616 ;
     RECT  10.403 21.936 13.208 22.488 ;
     RECT  10.547 31.776 13.208 31.992 ;
     RECT  10.307 33.792 13.208 33.816 ;
     RECT  10.115 37.968 13.208 38.136 ;
     RECT  10.019 41.664 13.208 42.216 ;
     RECT  8.201 43.824 13.208 46.008 ;
     RECT  9.821 47.424 13.208 48.408 ;
     RECT  9.821 49.728 13.208 49.848 ;
     RECT  9.749 51.456 13.208 51.528 ;
     RECT  10.865 53.328 13.208 54.408 ;
     RECT  9.251 55.488 13.208 55.512 ;
     RECT  10.789 56.496 13.208 58.968 ;
     RECT  10.685 60 13.208 60.84 ;
     RECT  11.941 61.968 13.208 69.288 ;
     RECT  10.691 71.088 13.208 71.976 ;
     RECT  12.097 73.248 13.208 76.248 ;
     RECT  12.097 77.328 13.208 77.928 ;
     RECT  10.825 79.152 13.208 80.616 ;
     RECT  9.137 81.648 13.208 84.84 ;
     RECT  8.561 85.92 13.208 90.312 ;
     RECT  8.104 91.44 13.208 92.136 ;
     RECT  10.501 93.216 13.208 103.32 ;
     RECT  9.857 104.544 13.208 106.056 ;
     RECT  9.857 107.04 13.208 108.648 ;
     RECT  8.309 109.68 13.208 110.52 ;
     RECT  9.065 111.84 13.208 111.912 ;
     RECT  8.201 114.096 13.208 114.36 ;
     RECT  9.203 116.448 13.208 117.624 ;
     RECT  9.497 118.992 13.208 119.496 ;
     RECT  13.057 120.48 13.208 127.704 ;
     RECT  13.208 2.148 13.283 127.704 ;
     RECT  13.283 2.148 13.312 127.452 ;
     RECT  13.312 2.418 13.504 127.182 ;
     RECT  13.504 10.656 13.955 13.656 ;
     RECT  14.204 128.832 14.291 128.856 ;
     RECT  13.504 77.328 16.124 80.52 ;
     RECT  13.504 81.648 16.124 84.84 ;
     RECT  13.504 15.264 16.547 16.344 ;
     RECT  15.677 129.456 17.237 129.48 ;
     RECT  13.504 21.936 17.953 23.304 ;
     RECT  13.504 33.792 18.181 33.816 ;
     RECT  16.124 77.328 18.469 84.84 ;
     RECT  13.504 4.176 18.608 7.704 ;
     RECT  13.504 9.024 18.608 9.624 ;
     RECT  13.955 10.656 18.608 13.416 ;
     RECT  16.547 15.264 18.608 15.864 ;
     RECT  13.504 17.328 18.608 19.032 ;
     RECT  13.504 20.592 18.608 20.616 ;
     RECT  17.953 21.936 18.608 23.352 ;
     RECT  13.504 31.776 18.608 31.992 ;
     RECT  18.181 33.792 18.608 33.912 ;
     RECT  13.504 37.968 18.608 38.136 ;
     RECT  13.504 41.664 18.608 42.216 ;
     RECT  13.504 43.824 18.608 46.008 ;
     RECT  13.504 47.424 18.608 48.408 ;
     RECT  13.504 49.728 18.608 49.848 ;
     RECT  13.504 51.456 18.608 51.528 ;
     RECT  13.504 53.328 18.608 54.504 ;
     RECT  13.504 55.488 18.608 55.512 ;
     RECT  13.504 56.496 18.608 58.968 ;
     RECT  13.504 60 18.608 60.84 ;
     RECT  13.504 61.968 18.608 69.288 ;
     RECT  13.504 71.088 18.608 71.976 ;
     RECT  13.504 73.248 18.608 76.248 ;
     RECT  18.469 77.328 18.608 84.888 ;
     RECT  13.504 85.92 18.608 90.312 ;
     RECT  13.504 91.44 18.608 92.136 ;
     RECT  13.504 93.216 18.608 103.32 ;
     RECT  13.504 104.544 18.608 106.056 ;
     RECT  13.504 107.04 18.608 108.648 ;
     RECT  13.504 109.68 18.608 110.52 ;
     RECT  13.504 111.84 18.608 111.912 ;
     RECT  13.504 114.096 18.608 114.36 ;
     RECT  13.504 116.448 18.608 117.624 ;
     RECT  13.504 118.992 18.608 119.496 ;
     RECT  13.504 120.48 18.608 127.032 ;
     RECT  18.469 129.456 18.707 129.48 ;
     RECT  18.608 2.148 18.712 127.452 ;
     RECT  18.712 2.418 18.904 127.182 ;
     RECT  18.904 21.936 19.667 23.304 ;
     RECT  18.904 77.328 20.195 84.936 ;
     RECT  20.609 129.456 20.693 129.48 ;
     RECT  20.195 77.328 21.493 84.84 ;
     RECT  18.904 85.92 21.493 90.312 ;
     RECT  21.596 128.832 21.683 128.856 ;
     RECT  18.904 60 22.124 60.84 ;
     RECT  18.904 61.968 22.124 69.288 ;
     RECT  22.124 60 22.211 69.288 ;
     RECT  21.493 77.328 22.745 90.312 ;
     RECT  18.904 53.328 22.853 54.504 ;
     RECT  22.745 77.328 23.929 85.944 ;
     RECT  22.745 87.072 23.929 90.312 ;
     RECT  18.904 4.176 24.008 7.704 ;
     RECT  18.904 9.024 24.008 9.624 ;
     RECT  18.904 10.656 24.008 13.416 ;
     RECT  18.904 15.264 24.008 15.864 ;
     RECT  18.904 17.328 24.008 19.032 ;
     RECT  18.904 20.592 24.008 20.616 ;
     RECT  19.667 21.936 24.008 22.488 ;
     RECT  18.904 31.392 24.008 31.992 ;
     RECT  18.904 33.888 24.008 33.912 ;
     RECT  18.904 37.968 24.008 38.136 ;
     RECT  18.904 41.664 24.008 42.216 ;
     RECT  18.904 43.824 24.008 46.008 ;
     RECT  18.904 47.424 24.008 48.408 ;
     RECT  18.904 49.728 24.008 49.848 ;
     RECT  18.904 51.456 24.008 51.528 ;
     RECT  22.853 53.328 24.008 54.408 ;
     RECT  18.904 55.488 24.008 55.512 ;
     RECT  18.904 56.496 24.008 58.968 ;
     RECT  22.211 60 24.008 60.84 ;
     RECT  22.211 61.968 24.008 69.288 ;
     RECT  18.904 71.088 24.008 71.976 ;
     RECT  18.904 73.248 24.008 76.248 ;
     RECT  23.929 77.328 24.008 90.312 ;
     RECT  18.904 91.44 24.008 92.136 ;
     RECT  18.904 93.216 24.008 103.32 ;
     RECT  18.904 104.544 24.008 106.056 ;
     RECT  18.904 107.04 24.008 108.648 ;
     RECT  18.904 109.68 24.008 110.52 ;
     RECT  18.904 111.84 24.008 111.912 ;
     RECT  18.904 114.096 24.008 114.36 ;
     RECT  18.904 116.448 24.008 117.624 ;
     RECT  18.904 118.992 24.008 119.496 ;
     RECT  18.904 120.48 24.008 127.032 ;
     RECT  24.008 2.148 24.112 127.452 ;
     RECT  24.112 2.418 24.304 127.182 ;
     RECT  23.093 129.456 24.419 129.48 ;
     RECT  24.304 77.328 25.532 90.312 ;
     RECT  24.304 91.44 25.532 92.136 ;
     RECT  25.532 77.328 27.025 92.136 ;
     RECT  24.304 93.216 27.025 103.32 ;
     RECT  27.025 77.328 27.109 103.32 ;
     RECT  27.109 77.328 27.353 92.136 ;
     RECT  26.549 129.456 27.605 129.48 ;
     RECT  27.353 91.44 28.037 92.136 ;
     RECT  28.037 91.92 28.465 92.136 ;
     RECT  27.109 93.216 28.465 103.32 ;
     RECT  24.304 4.176 29.408 7.704 ;
     RECT  24.304 9.024 29.408 9.624 ;
     RECT  24.304 10.656 29.408 13.416 ;
     RECT  24.304 15.264 29.408 15.864 ;
     RECT  24.304 17.328 29.408 19.032 ;
     RECT  24.304 20.592 29.408 20.616 ;
     RECT  24.304 21.936 29.408 22.488 ;
     RECT  24.304 31.392 29.408 31.992 ;
     RECT  24.304 33.888 29.408 33.912 ;
     RECT  24.304 37.968 29.408 38.136 ;
     RECT  24.304 41.664 29.408 42.216 ;
     RECT  24.304 43.824 29.408 46.008 ;
     RECT  24.304 47.424 29.408 48.408 ;
     RECT  24.304 49.728 29.408 49.848 ;
     RECT  24.304 51.456 29.408 51.528 ;
     RECT  24.304 53.328 29.408 54.504 ;
     RECT  24.304 55.488 29.408 55.512 ;
     RECT  24.304 56.496 29.408 58.968 ;
     RECT  24.304 60 29.408 60.84 ;
     RECT  24.304 61.968 29.408 69.288 ;
     RECT  24.304 71.088 29.408 71.976 ;
     RECT  24.304 73.248 29.408 76.248 ;
     RECT  27.353 77.328 29.408 90.312 ;
     RECT  28.465 91.92 29.408 103.32 ;
     RECT  24.304 104.544 29.408 106.056 ;
     RECT  24.304 107.04 29.408 108.648 ;
     RECT  24.304 109.68 29.408 110.52 ;
     RECT  24.304 111.84 29.408 111.912 ;
     RECT  24.304 114.096 29.408 114.36 ;
     RECT  24.304 116.448 29.408 117.624 ;
     RECT  24.304 118.992 29.408 119.496 ;
     RECT  24.304 120.48 29.408 127.032 ;
     RECT  29.408 2.148 29.512 127.452 ;
     RECT  29.512 2.418 29.704 127.182 ;
     RECT  29.689 0.096 29.891 0.12 ;
     RECT  29.269 129.456 30.089 129.48 ;
     RECT  29.704 33.888 30.515 33.912 ;
     RECT  29.704 36.72 30.556 36.84 ;
     RECT  29.704 53.328 30.809 54.504 ;
     RECT  32.444 128.832 32.531 128.856 ;
     RECT  29.704 43.824 33.157 46.008 ;
     RECT  29.704 47.424 33.157 48.408 ;
     RECT  29.704 31.392 33.203 31.992 ;
     RECT  32.965 129.456 33.545 129.48 ;
     RECT  29.704 4.176 34.808 7.704 ;
     RECT  29.704 9.024 34.808 9.624 ;
     RECT  29.704 10.656 34.808 13.416 ;
     RECT  29.704 15.264 34.808 15.864 ;
     RECT  29.704 17.328 34.808 19.032 ;
     RECT  29.704 20.592 34.808 20.616 ;
     RECT  29.704 21.936 34.808 22.488 ;
     RECT  33.203 31.776 34.808 31.992 ;
     RECT  30.556 36.816 34.808 36.84 ;
     RECT  29.704 37.968 34.808 38.136 ;
     RECT  29.704 41.664 34.808 42.216 ;
     RECT  33.157 43.824 34.808 48.408 ;
     RECT  29.704 49.728 34.808 49.848 ;
     RECT  29.704 51.456 34.808 51.528 ;
     RECT  30.809 53.328 34.808 54.408 ;
     RECT  29.704 55.488 34.808 55.512 ;
     RECT  29.704 56.496 34.808 58.968 ;
     RECT  29.704 60 34.808 60.84 ;
     RECT  29.704 61.968 34.808 69.288 ;
     RECT  29.704 71.088 34.808 71.976 ;
     RECT  29.704 73.248 34.808 76.248 ;
     RECT  29.704 77.328 34.808 90.312 ;
     RECT  29.704 91.92 34.808 103.32 ;
     RECT  29.704 104.544 34.808 106.056 ;
     RECT  29.704 107.04 34.808 108.648 ;
     RECT  29.704 109.68 34.808 110.52 ;
     RECT  29.704 111.84 34.808 111.912 ;
     RECT  29.704 114.096 34.808 114.36 ;
     RECT  29.704 116.448 34.808 117.624 ;
     RECT  29.704 118.992 34.808 119.496 ;
     RECT  29.704 120.48 34.808 127.032 ;
     RECT  34.808 2.148 34.912 127.452 ;
     RECT  34.912 2.418 35.104 127.182 ;
     RECT  35.104 3.936 35.219 7.704 ;
     RECT  34.981 129.456 35.219 129.48 ;
     RECT  35.104 36.816 35.597 36.84 ;
     RECT  36.188 129.504 36.275 129.528 ;
     RECT  36.428 128.832 36.515 129.48 ;
     RECT  35.104 43.824 36.893 48.408 ;
     RECT  36.515 129.456 37.001 129.48 ;
     RECT  35.104 53.328 37.177 54.504 ;
     RECT  35.104 55.488 37.177 55.512 ;
     RECT  35.104 91.92 38.396 103.32 ;
     RECT  35.104 104.544 38.396 106.056 ;
     RECT  35.104 15.264 38.828 15.864 ;
     RECT  38.828 14.88 38.869 15.864 ;
     RECT  38.869 14.88 38.915 16.248 ;
     RECT  38.915 15.264 39.233 16.248 ;
     RECT  35.104 9.024 39.548 9.624 ;
     RECT  35.104 10.656 39.548 13.416 ;
     RECT  35.219 4.176 39.913 7.704 ;
     RECT  39.548 9.024 39.913 13.416 ;
     RECT  39.877 128.832 39.971 128.856 ;
     RECT  35.104 26.496 40.093 26.52 ;
     RECT  38.869 2.832 40.165 2.856 ;
     RECT  40.165 2.016 40.208 2.856 ;
     RECT  39.913 4.176 40.208 13.416 ;
     RECT  39.233 15.264 40.208 15.864 ;
     RECT  35.104 17.328 40.208 19.032 ;
     RECT  35.104 20.592 40.208 20.616 ;
     RECT  35.104 21.936 40.208 22.488 ;
     RECT  40.093 26.496 40.208 26.616 ;
     RECT  35.104 31.776 40.208 31.992 ;
     RECT  37.105 36.768 40.208 36.792 ;
     RECT  35.104 37.968 40.208 38.136 ;
     RECT  35.104 41.664 40.208 42.216 ;
     RECT  36.893 43.824 40.208 46.008 ;
     RECT  36.893 47.424 40.208 48.408 ;
     RECT  35.104 49.728 40.208 49.848 ;
     RECT  35.104 51.456 40.208 51.528 ;
     RECT  37.177 53.328 40.208 55.512 ;
     RECT  35.104 56.496 40.208 58.968 ;
     RECT  35.104 60 40.208 60.84 ;
     RECT  35.104 61.968 40.208 69.288 ;
     RECT  35.104 71.088 40.208 71.976 ;
     RECT  35.104 73.248 40.208 76.248 ;
     RECT  35.104 77.328 40.208 90.312 ;
     RECT  38.396 91.92 40.208 106.056 ;
     RECT  35.104 107.04 40.208 108.648 ;
     RECT  35.104 109.68 40.208 110.52 ;
     RECT  35.104 111.84 40.208 111.912 ;
     RECT  35.104 114.096 40.208 114.36 ;
     RECT  35.104 116.448 40.208 117.624 ;
     RECT  35.104 118.992 40.208 119.496 ;
     RECT  35.104 120.48 40.208 127.032 ;
     RECT  40.208 2.016 40.312 127.452 ;
     RECT  40.069 129.456 40.451 129.48 ;
     RECT  40.312 2.016 40.504 127.182 ;
     RECT  40.504 14.784 40.78 15.864 ;
     RECT  40.748 1.68 40.835 1.704 ;
     RECT  40.504 91.92 41.141 108.648 ;
     RECT  41.209 0.096 41.293 0.12 ;
     RECT  40.504 4.176 41.465 9.624 ;
     RECT  40.504 20.592 41.785 20.616 ;
     RECT  41.701 2.304 41.789 2.328 ;
     RECT  40.504 21.936 41.893 22.488 ;
     RECT  42.001 0.528 42.179 0.552 ;
     RECT  40.504 36.768 42.253 36.792 ;
     RECT  40.504 37.968 42.253 38.136 ;
     RECT  40.504 26.592 42.577 26.616 ;
     RECT  42.577 26.592 42.617 27.336 ;
     RECT  42.469 30.288 42.757 30.312 ;
     RECT  40.504 43.824 42.757 46.008 ;
     RECT  40.504 17.328 42.764 19.032 ;
     RECT  40.504 31.776 42.764 31.992 ;
     RECT  42.757 30.288 42.785 30.408 ;
     RECT  42.785 30.288 42.796 30.744 ;
     RECT  40.504 53.328 42.797 55.512 ;
     RECT  41.141 105.216 42.797 108.648 ;
     RECT  41.785 20.496 42.805 20.616 ;
     RECT  41.893 21.792 42.805 22.488 ;
     RECT  42.764 24.864 42.805 24.888 ;
     RECT  40.504 34.08 42.833 34.104 ;
     RECT  42.764 17.328 42.851 19.512 ;
     RECT  42.805 20.496 42.851 22.488 ;
     RECT  42.805 24.864 42.851 25.464 ;
     RECT  42.617 26.64 42.851 27.336 ;
     RECT  42.796 30.24 42.892 30.744 ;
     RECT  42.851 20.592 42.977 22.488 ;
     RECT  42.977 21.792 43.085 22.488 ;
     RECT  42.797 107.28 43.297 108.648 ;
     RECT  42.851 26.64 43.301 26.664 ;
     RECT  43.297 107.28 43.409 108.696 ;
     RECT  42.605 0.096 43.553 0.12 ;
     RECT  40.504 41.664 43.693 42.216 ;
     RECT  42.757 43.296 43.693 46.008 ;
     RECT  42.851 25.44 43.724 25.464 ;
     RECT  43.724 25.44 43.811 26.28 ;
     RECT  43.409 107.52 43.829 108.696 ;
     RECT  40.504 109.68 43.829 110.52 ;
     RECT  43.811 25.44 43.913 25.464 ;
     RECT  42.764 31.776 43.949 32.76 ;
     RECT  43.949 31.776 44.021 31.992 ;
     RECT  40.504 47.424 44.053 48.408 ;
     RECT  40.504 49.728 44.053 49.848 ;
     RECT  42.253 36.768 44.252 38.136 ;
     RECT  44.252 36.144 44.339 38.136 ;
     RECT  44.261 33.024 44.345 33.048 ;
     RECT  42.892 30.384 44.381 30.744 ;
     RECT  44.377 1.728 44.461 1.752 ;
     RECT  43.585 0.528 44.915 0.552 ;
     RECT  44.339 36.768 45.097 38.136 ;
     RECT  45.529 2.016 45.608 2.04 ;
     RECT  41.465 4.176 45.608 7.704 ;
     RECT  41.465 9.024 45.608 9.624 ;
     RECT  40.504 10.656 45.608 13.416 ;
     RECT  40.78 15.264 45.608 15.864 ;
     RECT  42.851 17.328 45.608 19.032 ;
     RECT  42.977 20.592 45.608 20.616 ;
     RECT  43.085 21.936 45.608 22.488 ;
     RECT  44.381 30.384 45.608 30.408 ;
     RECT  44.021 31.776 45.608 31.8 ;
     RECT  45.097 36.768 45.608 38.184 ;
     RECT  44.732 39.216 45.608 39.24 ;
     RECT  43.693 41.664 45.608 46.008 ;
     RECT  44.053 47.424 45.608 49.848 ;
     RECT  40.504 51.456 45.608 51.528 ;
     RECT  42.797 53.328 45.608 54.408 ;
     RECT  42.797 55.44 45.608 55.512 ;
     RECT  40.504 56.496 45.608 58.968 ;
     RECT  40.504 60 45.608 60.84 ;
     RECT  40.504 61.968 45.608 69.288 ;
     RECT  40.504 71.088 45.608 71.976 ;
     RECT  40.504 73.248 45.608 76.248 ;
     RECT  40.504 77.328 45.608 90.312 ;
     RECT  41.141 91.92 45.608 103.608 ;
     RECT  42.797 105.216 45.608 106.2 ;
     RECT  43.829 107.52 45.608 110.52 ;
     RECT  40.504 111.84 45.608 111.912 ;
     RECT  40.504 114.096 45.608 114.36 ;
     RECT  40.504 116.448 45.608 117.624 ;
     RECT  40.504 118.992 45.608 119.496 ;
     RECT  40.504 120.48 45.608 127.032 ;
     RECT  45.608 2.016 45.712 127.452 ;
     RECT  45.712 2.016 45.827 127.182 ;
     RECT  45.827 2.418 45.904 127.182 ;
     RECT  45.904 30.24 46.019 30.408 ;
     RECT  45.904 38.112 46.019 38.184 ;
     RECT  45.904 41.664 46.019 48.504 ;
     RECT  45.904 107.52 46.019 111.912 ;
     RECT  45.829 129.456 46.019 129.48 ;
     RECT  46.019 30.24 46.115 30.264 ;
     RECT  45.904 36.864 46.163 37.032 ;
     RECT  46.019 43.824 46.259 48.504 ;
     RECT  46.259 43.824 46.361 48.456 ;
     RECT  45.904 49.728 47.117 50.136 ;
     RECT  46.019 107.52 47.149 110.52 ;
     RECT  46.019 111.696 47.149 111.912 ;
     RECT  47.117 49.728 47.293 49.944 ;
     RECT  46.361 46.752 47.297 48.456 ;
     RECT  47.257 128.832 47.363 128.856 ;
     RECT  46.019 41.664 47.365 42.216 ;
     RECT  46.361 43.824 47.365 45.48 ;
     RECT  47.297 47.424 47.373 48.456 ;
     RECT  47.293 49.536 47.373 49.944 ;
     RECT  47.149 107.52 47.725 111.912 ;
     RECT  45.904 53.328 47.749 54.504 ;
     RECT  45.904 55.488 47.749 55.512 ;
     RECT  45.904 61.968 47.761 69.288 ;
     RECT  47.725 107.52 47.761 112.152 ;
     RECT  47.373 47.424 47.829 49.944 ;
     RECT  47.761 107.52 47.845 112.872 ;
     RECT  45.904 56.496 47.977 58.968 ;
     RECT  45.904 60 47.977 60.84 ;
     RECT  47.977 56.496 48.083 60.84 ;
     RECT  47.749 53.328 48.133 55.512 ;
     RECT  48.083 56.496 48.133 58.968 ;
     RECT  45.904 120.48 48.293 127.032 ;
     RECT  48.133 53.328 48.341 58.968 ;
     RECT  48.293 120.48 48.377 127.656 ;
     RECT  48.341 53.328 48.413 54.696 ;
     RECT  48.413 53.328 48.485 54.648 ;
     RECT  48.083 60 48.62 60.84 ;
     RECT  47.761 61.872 48.62 69.288 ;
     RECT  48.62 60 49.571 69.288 ;
     RECT  45.269 0.096 49.925 0.12 ;
     RECT  45.904 114.096 50.341 114.36 ;
     RECT  50.341 114.096 50.437 114.408 ;
     RECT  45.904 17.328 50.713 19.032 ;
     RECT  45.904 4.176 51.008 7.704 ;
     RECT  45.904 9.024 51.008 9.624 ;
     RECT  45.904 10.656 51.008 13.416 ;
     RECT  45.904 15.264 51.008 15.864 ;
     RECT  50.713 17.184 51.008 19.032 ;
     RECT  45.904 20.592 51.008 20.616 ;
     RECT  45.904 21.936 51.008 22.488 ;
     RECT  45.904 31.776 51.008 31.8 ;
     RECT  46.163 37.008 51.008 37.032 ;
     RECT  46.019 38.112 51.008 38.136 ;
     RECT  45.904 39.216 51.008 39.24 ;
     RECT  47.365 41.664 51.008 45.48 ;
     RECT  47.829 47.424 51.008 49.752 ;
     RECT  45.904 51.456 51.008 51.528 ;
     RECT  48.485 53.328 51.008 54.408 ;
     RECT  48.341 56.256 51.008 58.968 ;
     RECT  49.571 60 51.008 60.84 ;
     RECT  49.571 61.968 51.008 69.288 ;
     RECT  45.904 71.088 51.008 71.976 ;
     RECT  45.904 73.248 51.008 76.248 ;
     RECT  45.904 77.328 51.008 90.312 ;
     RECT  45.904 91.92 51.008 103.608 ;
     RECT  45.904 105.216 51.008 106.2 ;
     RECT  47.845 107.52 51.008 112.152 ;
     RECT  50.437 114.048 51.008 114.408 ;
     RECT  45.904 116.448 51.008 117.624 ;
     RECT  45.904 118.992 51.008 119.496 ;
     RECT  48.377 120.48 51.008 127.128 ;
     RECT  51.008 2.148 51.112 127.452 ;
     RECT  51.112 2.418 51.145 127.452 ;
     RECT  51.145 2.418 51.299 127.56 ;
     RECT  51.299 2.418 51.304 127.182 ;
     RECT  51.304 3.936 52.229 7.704 ;
     RECT  51.304 107.52 52.979 112.152 ;
     RECT  51.304 9.024 53.017 9.624 ;
     RECT  51.304 116.448 53.027 117.624 ;
     RECT  51.304 105.216 53.029 106.2 ;
     RECT  51.304 61.968 53.057 69.288 ;
     RECT  53.057 61.968 53.093 68.136 ;
     RECT  51.304 37.008 53.125 37.032 ;
     RECT  51.304 38.112 53.125 38.136 ;
     RECT  51.304 71.088 53.221 71.976 ;
     RECT  51.304 73.248 53.221 76.248 ;
     RECT  52.981 33.264 53.269 33.288 ;
     RECT  53.125 37.008 53.317 38.136 ;
     RECT  53.027 117.216 53.413 117.624 ;
     RECT  53.093 61.968 53.453 67.704 ;
     RECT  51.304 41.664 53.509 45.48 ;
     RECT  52.979 107.52 53.653 110.808 ;
     RECT  53.365 34.896 53.701 34.92 ;
     RECT  53.317 36.384 53.701 38.136 ;
     RECT  53.029 104.928 53.749 106.2 ;
     RECT  53.653 107.472 53.749 110.808 ;
     RECT  53.269 33.264 53.845 33.816 ;
     RECT  53.701 34.896 53.845 38.136 ;
     RECT  53.413 117.216 53.852 117.96 ;
     RECT  53.852 117.216 53.881 118.008 ;
     RECT  51.304 118.992 53.881 119.496 ;
     RECT  51.304 31.776 53.893 31.8 ;
     RECT  51.304 77.328 53.941 90.312 ;
     RECT  51.304 53.328 54.025 54.504 ;
     RECT  51.304 15.264 54.097 15.864 ;
     RECT  53.941 77.328 54.131 90.648 ;
     RECT  51.304 21.936 54.133 22.488 ;
     RECT  51.304 51.456 54.133 51.528 ;
     RECT  54.025 53.232 54.133 54.504 ;
     RECT  51.304 91.92 54.227 103.608 ;
     RECT  51.304 47.424 54.241 49.752 ;
     RECT  54.133 50.736 54.241 54.504 ;
     RECT  53.509 41.136 54.277 45.48 ;
     RECT  53.057 69.264 54.277 69.288 ;
     RECT  52.229 4.176 54.317 7.704 ;
     RECT  54.277 41.136 54.323 45.72 ;
     RECT  51.304 56.256 54.349 58.968 ;
     RECT  52.979 111.888 54.421 112.152 ;
     RECT  54.241 47.424 54.533 54.504 ;
     RECT  54.097 14.832 54.601 15.864 ;
     RECT  51.304 17.184 54.601 19.032 ;
     RECT  54.317 4.176 54.637 4.536 ;
     RECT  54.317 5.52 54.673 7.704 ;
     RECT  53.017 8.832 54.673 9.624 ;
     RECT  51.304 20.592 54.709 20.616 ;
     RECT  54.133 21.936 54.709 22.632 ;
     RECT  51.304 120.48 54.709 127.128 ;
     RECT  54.349 56.208 54.745 58.968 ;
     RECT  51.304 60 54.745 60.84 ;
     RECT  53.845 33.264 54.749 38.136 ;
     RECT  54.637 3.744 54.803 4.536 ;
     RECT  54.517 26.256 54.805 26.28 ;
     RECT  54.803 4.176 54.844 4.536 ;
     RECT  54.709 20.592 54.853 22.632 ;
     RECT  54.421 111.888 54.925 112.872 ;
     RECT  51.304 114.048 54.925 114.408 ;
     RECT  54.673 5.52 54.965 9.624 ;
     RECT  54.277 69.264 55.033 69.528 ;
     RECT  54.601 14.832 55.037 19.032 ;
     RECT  53.453 67.536 55.069 67.704 ;
     RECT  53.893 31.44 55.093 31.8 ;
     RECT  54.749 33.264 55.093 36.936 ;
     RECT  54.533 54.336 55.1 54.504 ;
     RECT  54.853 20.592 55.141 23.304 ;
     RECT  55.1 54.336 55.187 54.648 ;
     RECT  54.131 77.328 55.187 90.312 ;
     RECT  53.221 71.088 55.249 76.248 ;
     RECT  55.187 77.328 55.249 77.976 ;
     RECT  53.881 117.216 55.333 119.496 ;
     RECT  54.709 120.48 55.333 127.656 ;
     RECT  54.533 47.424 55.357 53.352 ;
     RECT  54.749 37.92 55.429 38.136 ;
     RECT  51.304 39.216 55.429 39.24 ;
     RECT  55.033 68.928 55.501 69.528 ;
     RECT  53.749 104.928 55.525 110.808 ;
     RECT  54.925 111.888 55.525 114.408 ;
     RECT  54.965 6.576 55.58 9.624 ;
     RECT  51.304 10.656 55.58 13.416 ;
     RECT  54.323 45.6 55.609 45.72 ;
     RECT  55.357 46.752 55.609 53.352 ;
     RECT  54.323 41.136 55.645 44.616 ;
     RECT  54.745 56.208 55.669 60.84 ;
     RECT  55.669 56.208 55.681 60.936 ;
     RECT  54.844 4.224 55.861 4.536 ;
     RECT  54.965 5.52 55.861 5.544 ;
     RECT  55.141 20.592 55.861 23.832 ;
     RECT  54.229 24.912 55.861 24.936 ;
     RECT  55.069 67.488 55.933 67.704 ;
     RECT  55.501 68.736 55.933 69.528 ;
     RECT  55.525 104.928 56.005 114.408 ;
     RECT  53.453 61.968 56.101 66.264 ;
     RECT  55.933 67.488 56.101 69.528 ;
     RECT  55.58 6.576 56.149 13.416 ;
     RECT  55.037 14.832 56.149 15.864 ;
     RECT  55.861 20.592 56.149 24.936 ;
     RECT  54.805 26.016 56.149 26.28 ;
     RECT  56.005 104.928 56.156 114.6 ;
     RECT  55.333 117.216 56.156 127.656 ;
     RECT  55.187 54.336 56.185 54.504 ;
     RECT  55.681 55.584 56.185 60.936 ;
     RECT  56.156 104.928 56.197 115.368 ;
     RECT  56.156 116.4 56.197 127.656 ;
     RECT  54.227 91.92 56.257 100.104 ;
     RECT  54.227 101.088 56.257 103.608 ;
     RECT  56.257 91.92 56.285 103.608 ;
     RECT  55.861 4.224 56.408 5.544 ;
     RECT  56.149 6.576 56.408 15.864 ;
     RECT  55.037 17.376 56.408 19.032 ;
     RECT  56.149 20.592 56.408 26.28 ;
     RECT  56.365 27.936 56.408 27.96 ;
     RECT  54.421 30.336 56.408 30.36 ;
     RECT  55.093 31.44 56.408 36.936 ;
     RECT  55.429 37.92 56.408 39.24 ;
     RECT  55.645 40.944 56.408 44.616 ;
     RECT  55.609 45.6 56.408 53.352 ;
     RECT  56.185 54.336 56.408 60.936 ;
     RECT  56.101 61.968 56.408 69.528 ;
     RECT  55.249 71.088 56.408 77.976 ;
     RECT  55.187 79.248 56.408 90.312 ;
     RECT  56.285 91.92 56.408 103.8 ;
     RECT  56.197 104.928 56.408 127.656 ;
     RECT  56.408 2.148 56.512 127.656 ;
     RECT  56.512 2.418 56.704 127.656 ;
     RECT  56.704 66.864 56.729 67.32 ;
     RECT  56.704 83.28 56.801 99.72 ;
     RECT  56.801 83.28 56.819 99.624 ;
     RECT  56.704 22.8 56.867 42.36 ;
     RECT  56.704 4.896 56.945 7.464 ;
     RECT  56.704 54.336 57.011 54.84 ;
     RECT  56.819 83.28 57.011 87.672 ;
     RECT  56.945 4.896 57.017 6.312 ;
     RECT  56.704 77.28 57.053 81.72 ;
     RECT  56.704 68.736 57.059 71.976 ;
     RECT  56.867 23.28 57.089 42.36 ;
     RECT  56.704 17.376 57.125 19.08 ;
     RECT  56.729 67.296 57.125 67.32 ;
     RECT  57.059 68.736 57.155 68.952 ;
     RECT  56.704 101.088 57.161 114.552 ;
     RECT  56.819 88.656 57.196 99.624 ;
     RECT  57.089 27.648 57.197 42.36 ;
     RECT  56.704 43.488 57.197 53.352 ;
     RECT  57.197 43.488 57.203 50.136 ;
     RECT  57.155 68.736 57.203 68.856 ;
     RECT  57.196 93.024 57.233 99.624 ;
     RECT  57.161 109.824 57.233 114.552 ;
     RECT  57.197 27.648 57.244 34.584 ;
     RECT  57.197 35.808 57.251 42.36 ;
     RECT  56.704 119.664 57.251 127.656 ;
     RECT  57.017 4.896 57.269 5.496 ;
     RECT  57.196 88.656 57.269 91.944 ;
     RECT  57.089 23.28 57.341 26.376 ;
     RECT  57.269 4.896 57.413 5.304 ;
     RECT  57.341 26.256 57.413 26.376 ;
     RECT  57.203 43.488 57.413 46.344 ;
     RECT  57.244 31.44 57.449 34.584 ;
     RECT  57.197 51.408 57.449 53.352 ;
     RECT  57.233 109.824 57.449 112.728 ;
     RECT  57.053 77.28 57.485 79.752 ;
     RECT  54.601 1.152 57.517 1.176 ;
     RECT  57.449 33.888 57.521 34.584 ;
     RECT  57.203 47.328 57.587 50.136 ;
     RECT  57.233 114 57.587 114.552 ;
     RECT  56.704 56.352 57.593 60.408 ;
     RECT  57.059 70.224 57.593 71.976 ;
     RECT  57.587 47.328 57.635 49.176 ;
     RECT  57.449 53.232 57.665 53.352 ;
     RECT  57.011 54.336 57.665 54.696 ;
     RECT  57.485 77.28 57.683 77.784 ;
     RECT  56.704 61.968 57.697 65.784 ;
     RECT  56.704 10.944 57.701 16.2 ;
     RECT  57.373 129.456 57.731 129.48 ;
     RECT  57.587 114.048 57.733 114.552 ;
     RECT  56.704 115.968 57.733 117.912 ;
     RECT  57.251 37.872 57.772 42.36 ;
     RECT  56.704 8.496 57.773 9.624 ;
     RECT  57.593 56.352 57.781 57.096 ;
     RECT  57.733 115.968 57.781 118.056 ;
     RECT  57.772 40.992 57.841 42.36 ;
     RECT  57.053 81.168 57.841 81.72 ;
     RECT  57.251 35.808 57.845 36.504 ;
     RECT  57.701 16.176 57.875 16.2 ;
     RECT  57.683 77.472 57.875 77.784 ;
     RECT  57.593 58.08 57.877 60.408 ;
     RECT  57.733 114.048 57.877 114.696 ;
     RECT  57.781 115.968 57.877 118.584 ;
     RECT  57.877 114.048 57.914 118.584 ;
     RECT  57.341 23.28 57.917 25.224 ;
     RECT  57.914 114.048 57.923 118.536 ;
     RECT  57.161 101.088 57.949 108.36 ;
     RECT  57.923 114.048 57.964 115.128 ;
     RECT  57.665 54.384 57.985 54.696 ;
     RECT  57.781 55.824 57.985 57.096 ;
     RECT  57.697 61.584 58.057 65.784 ;
     RECT  57.413 43.488 58.097 45 ;
     RECT  57.449 51.408 58.115 51.912 ;
     RECT  57.877 58.08 58.117 60.504 ;
     RECT  57.251 119.664 58.124 127.512 ;
     RECT  57.125 17.376 58.129 17.4 ;
     RECT  57.917 23.28 58.133 24.168 ;
     RECT  57.413 46.32 58.133 46.344 ;
     RECT  57.841 40.992 58.165 42.504 ;
     RECT  56.704 73.248 58.169 76.248 ;
     RECT  58.124 119.52 58.169 127.512 ;
     RECT  57.701 10.944 58.205 15.192 ;
     RECT  58.097 43.632 58.205 45 ;
     RECT  58.169 119.52 58.211 119.544 ;
     RECT  57.449 109.824 58.237 111.912 ;
     RECT  56.704 20.688 58.241 21.816 ;
     RECT  58.057 61.584 58.241 66.696 ;
     RECT  58.117 58.08 58.259 60.6 ;
     RECT  58.115 51.552 58.277 51.912 ;
     RECT  57.964 114.048 58.277 114.696 ;
     RECT  58.169 120.528 58.277 127.512 ;
     RECT  58.205 13.872 58.313 15.192 ;
     RECT  58.169 75.216 58.313 76.248 ;
     RECT  57.269 88.656 58.321 90.648 ;
     RECT  57.841 81.168 58.345 82.104 ;
     RECT  57.011 83.28 58.345 87.624 ;
     RECT  57.125 18.816 58.385 19.08 ;
     RECT  58.169 73.248 58.405 74.232 ;
     RECT  57.269 91.92 58.405 91.944 ;
     RECT  58.345 81.168 58.429 87.624 ;
     RECT  56.945 7.44 58.451 7.464 ;
     RECT  57.244 27.648 58.451 30.36 ;
     RECT  58.237 109.392 58.451 111.912 ;
     RECT  58.277 120.528 58.457 120.552 ;
     RECT  57.593 70.224 58.485 71.832 ;
     RECT  58.277 121.68 58.489 127.512 ;
     RECT  58.489 121.68 58.493 128.28 ;
     RECT  58.165 40.992 58.499 42.6 ;
     RECT  57.449 31.776 58.501 32.76 ;
     RECT  57.521 33.888 58.501 34.152 ;
     RECT  58.205 10.944 58.529 12.888 ;
     RECT  58.405 72.816 58.547 74.232 ;
     RECT  58.529 10.944 58.549 11.304 ;
     RECT  58.313 75.264 58.565 76.248 ;
     RECT  58.549 10.464 58.595 11.304 ;
     RECT  58.565 75.84 58.597 76.248 ;
     RECT  58.405 91.776 58.597 91.944 ;
     RECT  58.241 21.408 58.601 21.816 ;
     RECT  57.875 77.472 58.601 77.736 ;
     RECT  58.129 16.416 58.637 17.4 ;
     RECT  58.597 75.84 58.637 76.44 ;
     RECT  58.429 83.28 58.637 87.624 ;
     RECT  57.635 47.328 58.643 48.408 ;
     RECT  58.241 65.376 58.643 66.696 ;
     RECT  58.429 81.168 58.643 82.104 ;
     RECT  57.485 78.864 58.645 79.752 ;
     RECT  58.643 81.168 58.645 81.672 ;
     RECT  58.485 70.224 58.691 71.784 ;
     RECT  58.547 72.816 58.691 74.184 ;
     RECT  57.233 93.024 58.693 94.536 ;
     RECT  57.233 95.52 58.693 99.624 ;
     RECT  58.321 88.656 58.709 90.408 ;
     RECT  58.499 40.992 58.739 42.504 ;
     RECT  58.645 78.864 58.745 81.672 ;
     RECT  58.597 91.728 58.789 91.944 ;
     RECT  57.949 100.848 58.789 108.36 ;
     RECT  58.745 78.864 58.796 78.888 ;
     RECT  57.665 53.232 58.813 53.256 ;
     RECT  58.745 80.4 58.835 81.672 ;
     RECT  58.789 91.728 58.835 92.04 ;
     RECT  58.451 30.336 58.849 30.36 ;
     RECT  58.739 41.088 58.853 42.504 ;
     RECT  58.813 53.232 58.853 53.352 ;
     RECT  58.691 72.816 58.853 73.416 ;
     RECT  58.796 78.72 58.853 78.888 ;
     RECT  57.772 37.872 58.883 39.768 ;
     RECT  58.853 78.72 58.883 78.744 ;
     RECT  58.849 30.336 58.885 30.456 ;
     RECT  58.637 16.416 58.889 17.112 ;
     RECT  58.885 30.336 58.889 30.744 ;
     RECT  57.985 54.384 58.921 57.096 ;
     RECT  58.259 58.08 58.921 60.408 ;
     RECT  58.835 91.92 58.921 92.04 ;
     RECT  58.693 93.024 58.921 99.624 ;
     RECT  58.241 61.584 58.931 64.344 ;
     RECT  58.889 30.432 58.933 30.744 ;
     RECT  58.501 31.776 58.933 34.152 ;
     RECT  57.773 8.496 58.961 9.48 ;
     RECT  58.595 10.464 58.997 10.488 ;
     RECT  58.933 30.432 59.02 34.152 ;
     RECT  58.835 80.832 59.033 81.672 ;
     RECT  59.033 81.168 59.069 81.672 ;
     RECT  58.921 91.92 59.069 99.624 ;
     RECT  58.789 100.848 59.132 105.432 ;
     RECT  58.961 8.496 59.141 9.384 ;
     RECT  58.451 109.392 59.141 111.624 ;
     RECT  58.385 19.008 59.177 19.08 ;
     RECT  58.601 77.568 59.177 77.736 ;
     RECT  59.177 19.056 59.219 19.08 ;
     RECT  58.931 61.92 59.219 64.344 ;
     RECT  59.069 81.168 59.219 81.528 ;
     RECT  59.132 100.656 59.219 105.432 ;
     RECT  59.069 91.92 59.267 99.528 ;
     RECT  58.133 24.144 59.269 24.168 ;
     RECT  59.02 31.776 59.317 34.152 ;
     RECT  58.883 37.872 59.317 38.52 ;
     RECT  58.921 54.384 59.317 60.408 ;
     RECT  58.451 27.648 59.321 28.728 ;
     RECT  58.853 73.056 59.321 73.416 ;
     RECT  57.845 36.24 59.353 36.504 ;
     RECT  58.709 88.656 59.353 90.312 ;
     RECT  59.219 81.456 59.357 81.528 ;
     RECT  58.637 83.28 59.357 87.336 ;
     RECT  58.789 106.704 59.357 108.36 ;
     RECT  58.493 121.92 59.365 128.28 ;
     RECT  59.269 24.144 59.372 24.216 ;
     RECT  57.917 25.2 59.372 25.224 ;
     RECT  58.637 76.032 59.393 76.44 ;
     RECT  59.357 86.736 59.393 87.336 ;
     RECT  59.317 31.776 59.404 34.2 ;
     RECT  59.317 54.384 59.411 60.84 ;
     RECT  59.372 24.144 59.413 25.224 ;
     RECT  59.413 23.952 59.425 25.224 ;
     RECT  58.205 43.632 59.425 44.136 ;
     RECT  59.425 23.328 59.429 25.224 ;
     RECT  57.413 26.256 59.429 26.28 ;
     RECT  59.353 35.328 59.459 36.504 ;
     RECT  59.353 88.32 59.459 90.312 ;
     RECT  58.705 20.4 59.461 20.424 ;
     RECT  59.141 109.392 59.461 111.576 ;
     RECT  59.357 83.28 59.497 85.608 ;
     RECT  59.404 32.112 59.516 34.2 ;
     RECT  59.459 35.328 59.516 36.312 ;
     RECT  58.601 21.408 59.537 21.672 ;
     RECT  58.691 70.224 59.555 71.352 ;
     RECT  59.267 93.024 59.573 99.528 ;
     RECT  59.219 100.848 59.573 105.432 ;
     RECT  59.497 120.864 59.581 120.888 ;
     RECT  59.393 76.032 59.605 76.248 ;
     RECT  59.357 81.456 59.645 81.48 ;
     RECT  59.497 83.232 59.645 85.608 ;
     RECT  58.277 51.552 59.651 51.624 ;
     RECT  59.645 83.232 59.651 84.552 ;
     RECT  59.461 108.864 59.681 111.576 ;
     RECT  59.555 70.224 59.699 70.728 ;
     RECT  57.923 116.16 59.701 118.536 ;
     RECT  58.529 12.864 59.713 12.888 ;
     RECT  58.313 13.872 59.713 14.76 ;
     RECT  58.643 47.328 59.717 47.928 ;
     RECT  59.605 75.936 59.749 76.248 ;
     RECT  59.353 119.712 59.785 119.736 ;
     RECT  58.853 41.088 59.789 42.456 ;
     RECT  59.425 43.536 59.789 44.472 ;
     RECT  59.749 75.888 59.789 76.248 ;
     RECT  59.411 57.072 59.795 60.84 ;
     RECT  59.701 115.68 59.795 118.536 ;
     RECT  59.429 23.328 59.825 25.128 ;
     RECT  59.393 86.736 59.825 86.856 ;
     RECT  59.573 93.024 59.825 99.384 ;
     RECT  59.789 75.888 59.857 75.96 ;
     RECT  58.883 39.744 59.893 39.768 ;
     RECT  59.825 95.28 59.897 99.384 ;
     RECT  59.681 108.864 59.897 110.568 ;
     RECT  59.321 28.704 59.941 28.728 ;
     RECT  59.357 106.704 59.941 107.784 ;
     RECT  58.277 114.048 59.941 114.408 ;
     RECT  59.569 77.808 59.969 77.832 ;
     RECT  59.795 57.552 60.005 60.84 ;
     RECT  59.897 95.28 60.005 99.288 ;
     RECT  59.941 106.608 60.005 107.784 ;
     RECT  59.897 109.392 60.005 110.568 ;
     RECT  59.825 23.328 60.035 23.976 ;
     RECT  59.645 85.584 60.035 85.608 ;
     RECT  59.461 20.352 60.037 20.424 ;
     RECT  59.317 37.584 60.037 38.52 ;
     RECT  60.035 23.952 60.041 23.976 ;
     RECT  59.651 83.28 60.041 83.784 ;
     RECT  60.037 37.584 60.073 38.616 ;
     RECT  59.893 39.744 60.073 39.864 ;
     RECT  59.459 88.656 60.073 90.312 ;
     RECT  59.267 91.92 60.073 91.944 ;
     RECT  59.365 121.92 60.073 128.856 ;
     RECT  59.516 32.112 60.077 36.312 ;
     RECT  59.573 101.28 60.083 105.432 ;
     RECT  60.005 106.608 60.083 107.592 ;
     RECT  59.941 114.048 60.083 114.552 ;
     RECT  60.083 104.928 60.109 105.432 ;
     RECT  59.825 86.736 60.113 86.76 ;
     RECT  59.321 27.648 60.133 27.672 ;
     RECT  60.14 46.656 60.145 46.68 ;
     RECT  59.717 47.664 60.181 47.928 ;
     RECT  60.005 95.856 60.221 99.288 ;
     RECT  60.145 46.08 60.227 46.68 ;
     RECT  59.941 28.704 60.229 29.4 ;
     RECT  59.02 30.432 60.229 30.744 ;
     RECT  59.785 119.712 60.253 120.312 ;
     RECT  60.077 32.976 60.257 36.312 ;
     RECT  59.789 44.064 60.257 44.472 ;
     RECT  59.825 93.024 60.275 94.056 ;
     RECT  60.073 121.296 60.277 128.856 ;
     RECT  58.643 65.376 60.284 65.784 ;
     RECT  60.133 27.312 60.289 27.672 ;
     RECT  60.229 28.704 60.289 30.744 ;
     RECT  60.289 27.312 60.293 30.744 ;
     RECT  59.789 41.76 60.293 42.456 ;
     RECT  60.257 44.448 60.323 44.472 ;
     RECT  60.073 37.584 60.325 39.864 ;
     RECT  59.699 70.224 60.325 70.68 ;
     RECT  60.181 47.664 60.329 47.976 ;
     RECT  60.005 58.08 60.329 60.84 ;
     RECT  60.245 74.64 60.329 74.664 ;
     RECT  60.037 20.352 60.365 21.192 ;
     RECT  60.293 28.224 60.365 30.744 ;
     RECT  60.325 69.552 60.365 70.68 ;
     RECT  60.041 83.76 60.365 83.784 ;
     RECT  60.073 88.656 60.365 91.944 ;
     RECT  60.221 95.856 60.365 95.88 ;
     RECT  60.083 107.568 60.365 107.592 ;
     RECT  59.681 111.552 60.365 111.576 ;
     RECT  60.284 65.376 60.371 66.36 ;
     RECT  60.365 69.552 60.371 70.248 ;
     RECT  59.857 75.792 60.371 75.96 ;
     RECT  59.411 54.384 60.373 55.848 ;
     RECT  60.365 30.432 60.397 30.744 ;
     RECT  60.083 114.048 60.397 114.12 ;
     RECT  60.371 65.376 60.401 65.784 ;
     RECT  60.257 33.024 60.412 36.312 ;
     RECT  60.412 35.856 60.419 36.312 ;
     RECT  60.373 54.384 60.419 55.944 ;
     RECT  60.005 109.68 60.419 110.568 ;
     RECT  59.219 62.16 60.433 64.344 ;
     RECT  60.365 21.168 60.437 21.192 ;
     RECT  60.275 93.168 60.437 94.056 ;
     RECT  60.325 37.584 60.46 40.44 ;
     RECT  60.397 26.688 60.469 26.712 ;
     RECT  59.141 8.496 60.473 9.144 ;
     RECT  60.397 30.432 60.473 30.84 ;
     RECT  60.412 33.024 60.473 34.728 ;
     RECT  60.083 101.28 60.473 103.8 ;
     RECT  60.371 75.792 60.505 75.912 ;
     RECT  59.321 73.056 60.509 73.08 ;
     RECT  60.253 119.664 60.515 120.312 ;
     RECT  60.365 88.656 60.541 91.848 ;
     RECT  60.473 30.72 60.545 30.84 ;
     RECT  60.227 46.08 60.545 46.152 ;
     RECT  60.437 93.504 60.545 94.056 ;
     RECT  60.109 104.928 60.545 106.008 ;
     RECT  59.825 25.104 60.577 25.128 ;
     RECT  60.469 26.16 60.577 26.712 ;
     RECT  60.577 25.104 60.581 26.712 ;
     RECT  60.473 33.024 60.581 33.672 ;
     RECT  60.329 47.664 60.581 47.928 ;
     RECT  60.515 120.288 60.617 120.312 ;
     RECT  60.419 36.24 60.653 36.312 ;
     RECT  60.46 37.872 60.653 40.44 ;
     RECT  60.293 41.76 60.653 42.312 ;
     RECT  60.365 28.224 60.659 29.112 ;
     RECT  60.277 121.296 60.661 128.952 ;
     RECT  60.581 33.024 60.689 33.048 ;
     RECT  60.221 97.632 60.689 99.288 ;
     RECT  59.651 51.552 60.707 51.576 ;
     RECT  60.397 114 60.707 114.12 ;
     RECT  60.419 55.728 60.709 55.944 ;
     RECT  60.329 58.512 60.709 60.84 ;
     RECT  60.433 62.16 60.709 64.44 ;
     RECT  60.661 120.672 60.748 128.952 ;
     RECT  60.709 58.512 60.755 64.44 ;
     RECT  59.795 116.736 60.757 118.536 ;
     RECT  60.755 58.512 60.761 60.456 ;
     RECT  60.748 121.392 60.761 128.952 ;
     RECT  60.709 55.728 60.803 56.472 ;
     RECT  60.803 56.448 60.833 56.472 ;
     RECT  60.757 116.736 60.841 118.584 ;
     RECT  60.829 71.28 60.86 71.304 ;
     RECT  57.517 1.152 60.937 1.656 ;
     RECT  58.853 53.328 60.973 53.352 ;
     RECT  60.973 85.488 61.405 85.512 ;
     RECT  60.761 121.968 61.405 128.952 ;
     RECT  60.505 75.648 61.469 75.912 ;
     RECT  60.86 71.28 61.477 71.832 ;
     RECT  58.889 17.088 61.513 17.112 ;
     RECT  61.469 75.072 61.513 75.912 ;
     RECT  61.405 121.968 61.523 129.528 ;
     RECT  61.477 71.088 61.549 71.832 ;
     RECT  60.541 88.464 61.573 91.848 ;
     RECT  59.795 115.68 61.573 115.704 ;
     RECT  60.419 110.064 61.657 110.568 ;
     RECT  61.513 74.88 61.765 75.912 ;
     RECT  60.937 1.152 61.808 1.944 ;
     RECT  58.597 3.12 61.808 3.144 ;
     RECT  57.413 4.896 61.808 4.92 ;
     RECT  60.473 8.496 61.808 8.52 ;
     RECT  59.713 12.864 61.808 14.76 ;
     RECT  61.513 16.608 61.808 17.112 ;
     RECT  60.581 26.016 61.808 26.712 ;
     RECT  60.659 28.224 61.808 28.728 ;
     RECT  60.545 30.816 61.808 30.84 ;
     RECT  60.473 34.704 61.808 34.728 ;
     RECT  60.653 36.24 61.808 36.264 ;
     RECT  60.653 37.872 61.808 39.864 ;
     RECT  60.653 41.76 61.808 41.976 ;
     RECT  60.545 46.08 61.808 46.104 ;
     RECT  60.581 47.76 61.808 47.928 ;
     RECT  61.513 51.216 61.808 51.24 ;
     RECT  60.973 52.464 61.808 53.352 ;
     RECT  60.419 54.384 61.808 54.744 ;
     RECT  60.761 58.512 61.808 59.064 ;
     RECT  60.761 60.048 61.808 60.456 ;
     RECT  60.755 61.44 61.808 64.44 ;
     RECT  60.401 65.424 61.808 65.784 ;
     RECT  60.973 67.92 61.808 67.944 ;
     RECT  60.371 69.552 61.808 70.104 ;
     RECT  61.549 71.088 61.808 71.928 ;
     RECT  61.765 74.112 61.808 75.912 ;
     RECT  60.865 78.672 61.808 78.696 ;
     RECT  61.225 83.328 61.808 83.352 ;
     RECT  61.405 85.104 61.808 85.512 ;
     RECT  61.573 88.464 61.808 91.944 ;
     RECT  60.545 93.504 61.808 93.864 ;
     RECT  60.689 97.632 61.808 98.424 ;
     RECT  61.549 100.272 61.808 100.296 ;
     RECT  60.473 101.28 61.808 101.688 ;
     RECT  60.473 102.672 61.808 103.8 ;
     RECT  60.545 104.928 61.808 105.24 ;
     RECT  61.657 110.016 61.808 110.568 ;
     RECT  60.707 114.048 61.808 114.12 ;
     RECT  61.573 115.152 61.808 115.704 ;
     RECT  60.841 116.736 61.808 118.056 ;
     RECT  61.523 121.968 61.808 128.952 ;
     RECT  61.808 1.152 62.104 128.952 ;
     RECT  62.104 8.112 62.165 8.52 ;
     RECT  62.104 113.472 62.165 114.744 ;
     RECT  62.104 12.864 62.201 14.76 ;
     RECT  62.104 34.704 62.243 37.896 ;
     RECT  62.104 65.424 62.291 66.936 ;
     RECT  62.291 65.76 62.339 66.936 ;
     RECT  62.104 41.76 62.435 42.84 ;
     RECT  62.104 49.728 62.483 53.352 ;
     RECT  62.104 39.264 62.771 40.776 ;
     RECT  62.483 49.728 62.819 52.968 ;
     RECT  62.104 62.64 62.819 62.952 ;
     RECT  62.104 94.032 62.819 94.728 ;
     RECT  62.104 104.88 62.867 104.952 ;
     RECT  62.104 1.152 62.953 1.944 ;
     RECT  62.104 54.384 63.011 54.84 ;
     RECT  62.104 46.464 63.205 46.824 ;
     RECT  62.104 48 63.205 48.744 ;
     RECT  62.953 0.912 63.241 1.944 ;
     RECT  62.104 3.12 63.241 3.144 ;
     RECT  62.104 4.896 63.241 5.16 ;
     RECT  62.165 8.112 63.241 8.136 ;
     RECT  62.104 11.856 63.241 11.88 ;
     RECT  62.201 12.864 63.241 14.376 ;
     RECT  62.104 16.368 63.241 17.352 ;
     RECT  62.104 20.592 63.241 20.856 ;
     RECT  62.104 22.56 63.241 22.584 ;
     RECT  62.104 29.808 63.241 30.312 ;
     RECT  62.771 39.264 63.241 39.768 ;
     RECT  62.435 41.952 63.241 42.84 ;
     RECT  62.104 44.256 63.241 44.52 ;
     RECT  63.205 46.464 63.241 48.744 ;
     RECT  63.011 54.72 63.241 54.84 ;
     RECT  62.104 56.208 63.241 61.224 ;
     RECT  62.819 62.928 63.241 62.952 ;
     RECT  62.104 64.08 63.241 64.104 ;
     RECT  62.104 67.92 63.241 68.664 ;
     RECT  62.104 69.888 63.241 71.928 ;
     RECT  62.104 88.32 63.241 92.904 ;
     RECT  62.819 94.032 63.241 94.584 ;
     RECT  62.104 95.808 63.241 99.048 ;
     RECT  62.104 106.752 63.241 106.776 ;
     RECT  62.104 107.76 63.241 109.032 ;
     RECT  62.104 110.256 63.241 110.52 ;
     RECT  62.104 111.504 63.241 112.488 ;
     RECT  62.104 115.728 63.241 118.728 ;
     RECT  62.104 119.952 63.241 120.984 ;
     RECT  62.104 24.336 63.277 26.568 ;
     RECT  63.241 27.552 63.277 28.056 ;
     RECT  63.241 29.568 63.277 30.312 ;
     RECT  62.104 31.296 63.277 31.32 ;
     RECT  62.104 32.544 63.277 33.048 ;
     RECT  62.243 35.52 63.277 37.896 ;
     RECT  63.241 39.024 63.277 39.768 ;
     RECT  63.241 67.92 63.277 71.928 ;
     RECT  62.104 73.152 63.277 74.904 ;
     RECT  62.104 75.888 63.277 79.368 ;
     RECT  62.104 80.592 63.277 80.616 ;
     RECT  62.104 81.6 63.277 87.336 ;
     RECT  63.241 88.32 63.277 94.584 ;
     RECT  62.104 100.272 63.277 103.8 ;
     RECT  63.241 105.504 63.277 105.528 ;
     RECT  63.241 106.752 63.277 109.032 ;
     RECT  63.241 110.256 63.277 112.488 ;
     RECT  62.165 113.472 63.277 113.496 ;
     RECT  62.165 114.72 63.277 114.744 ;
     RECT  63.241 115.728 63.277 120.984 ;
     RECT  62.104 121.968 63.277 122.712 ;
     RECT  62.104 123.696 63.277 123.72 ;
     RECT  62.104 124.704 63.277 128.952 ;
     RECT  63.241 7.392 63.781 8.136 ;
     RECT  63.277 29.04 63.781 30.312 ;
     RECT  63.277 31.296 63.781 33.048 ;
     RECT  63.241 34.032 63.781 34.536 ;
     RECT  63.277 35.52 63.781 39.768 ;
     RECT  63.241 4.896 63.817 5.928 ;
     RECT  63.781 7.392 63.817 9.144 ;
     RECT  63.781 10.128 63.817 10.152 ;
     RECT  63.241 11.136 63.817 14.376 ;
     RECT  63.241 15.36 63.817 17.352 ;
     RECT  63.781 19.104 63.817 19.128 ;
     RECT  63.241 20.352 63.817 22.584 ;
     RECT  63.277 24.336 63.817 28.056 ;
     RECT  63.781 29.04 63.817 33.048 ;
     RECT  63.781 34.032 63.817 39.768 ;
     RECT  62.771 40.752 63.817 40.776 ;
     RECT  63.241 41.952 63.817 48.744 ;
     RECT  62.819 49.728 63.817 49.992 ;
     RECT  62.819 50.976 63.817 52.968 ;
     RECT  63.241 62.928 63.817 64.104 ;
     RECT  62.339 66.672 63.817 66.936 ;
     RECT  63.277 67.92 63.817 80.616 ;
     RECT  63.277 81.6 63.817 94.584 ;
     RECT  63.817 29.04 63.853 39.768 ;
     RECT  63.817 40.752 63.853 53.736 ;
     RECT  63.817 62.784 63.853 64.2 ;
     RECT  63.817 65.184 63.853 65.208 ;
     RECT  63.817 66.672 63.853 80.616 ;
     RECT  63.817 81.6 63.853 94.824 ;
     RECT  63.241 95.808 63.853 99.288 ;
     RECT  63.277 100.272 63.853 104.52 ;
     RECT  63.277 105.504 63.853 114.744 ;
     RECT  63.277 115.728 63.853 128.952 ;
     RECT  63.241 0.912 64.609 3.432 ;
     RECT  63.817 4.656 64.609 5.928 ;
     RECT  64.609 0.912 64.645 5.928 ;
     RECT  63.817 7.152 64.645 17.352 ;
     RECT  63.817 18.336 64.645 28.056 ;
     RECT  63.853 29.04 64.645 53.736 ;
     RECT  63.241 54.72 64.645 61.224 ;
     RECT  63.853 62.784 64.645 128.952 ;
     RECT  64.645 0.912 64.681 17.352 ;
     RECT  64.645 18.336 64.681 53.736 ;
     RECT  64.645 54.72 64.681 128.952 ;
     RECT  64.681 0.672 64.764 128.952 ;
    LAYER M5 ;
     RECT  40.32 0.016 49.896 0.131 ;
     RECT  40.32 0.131 42.168 0.563 ;
     RECT  43.968 0.131 45.816 0.563 ;
     RECT  40.32 0.563 41.736 1.715 ;
     RECT  44.4 0.563 44.424 1.763 ;
     RECT  29.856 0.085 29.88 2.137 ;
     RECT  40.32 1.715 40.512 2.137 ;
     RECT  45.792 0.563 45.816 2.137 ;
     RECT  2.4 2.137 2.52 2.151 ;
     RECT  7.8 2.137 7.92 2.151 ;
     RECT  13.2 2.137 13.32 2.151 ;
     RECT  18.6 2.137 18.72 2.151 ;
     RECT  24 2.137 24.12 2.151 ;
     RECT  34.8 2.137 34.92 2.151 ;
     RECT  45.6 2.137 45.816 2.151 ;
     RECT  51 2.137 51.12 2.151 ;
     RECT  56.4 2.137 56.52 2.151 ;
     RECT  61.8 2.137 61.92 2.151 ;
     RECT  41.712 1.715 41.736 2.339 ;
     RECT  7.8 2.151 8.112 3.397 ;
     RECT  34.8 2.151 35.112 3.925 ;
     RECT  51 2.151 51.312 3.925 ;
     RECT  3.84 3.925 3.864 4.165 ;
     RECT  54.768 3.733 54.792 4.211 ;
     RECT  3.84 4.165 4.008 4.405 ;
     RECT  11.424 4.117 11.448 4.453 ;
     RECT  11.424 4.453 11.976 4.499 ;
     RECT  2.4 2.151 2.712 4.501 ;
     RECT  3.84 4.405 4.296 4.501 ;
     RECT  40.2 2.137 40.512 5.077 ;
     RECT  7.152 3.397 8.112 5.219 ;
     RECT  51 3.925 51.864 5.219 ;
     RECT  51 5.219 51.312 5.605 ;
     RECT  2.4 4.501 4.296 5.653 ;
     RECT  5.76 4.405 5.784 5.653 ;
     RECT  2.4 5.653 5.784 6.133 ;
     RECT  2.4 6.133 6.744 6.181 ;
     RECT  7.8 5.219 8.112 6.181 ;
     RECT  2.4 6.181 8.112 7.189 ;
     RECT  1.968 7.189 8.112 7.333 ;
     RECT  39.984 5.077 40.512 7.427 ;
     RECT  56.4 2.151 56.712 8.485 ;
     RECT  58.416 7.429 58.44 8.485 ;
     RECT  40.08 7.427 40.512 8.579 ;
     RECT  1.92 7.333 8.112 9.061 ;
     RECT  56.4 8.485 58.44 9.061 ;
     RECT  56.4 9.061 58.488 9.109 ;
     RECT  55.632 9.109 58.488 9.395 ;
     RECT  55.632 9.395 57.864 9.491 ;
     RECT  45.6 2.151 45.912 9.493 ;
     RECT  55.632 9.491 56.712 9.779 ;
     RECT  40.2 8.579 40.512 9.925 ;
     RECT  57.84 9.491 57.864 10.453 ;
     RECT  1.92 9.061 8.424 10.693 ;
     RECT  10.656 7.669 10.68 10.933 ;
     RECT  9.648 4.213 9.672 11.125 ;
     RECT  10.656 10.933 10.824 11.125 ;
     RECT  9.648 11.125 10.824 11.171 ;
     RECT  57.84 10.453 58.584 11.315 ;
     RECT  13.2 2.151 13.512 11.893 ;
     RECT  57.84 11.315 58.152 12.035 ;
     RECT  39.6 9.925 40.512 12.181 ;
     RECT  38.88 12.181 40.512 12.227 ;
     RECT  1.056 10.693 8.424 12.277 ;
     RECT  55.728 9.779 56.712 12.517 ;
     RECT  57.84 12.035 57.864 12.517 ;
     RECT  55.728 12.517 57.864 12.901 ;
     RECT  60.384 12.901 60.408 12.949 ;
     RECT  60.384 12.949 60.6 12.997 ;
     RECT  61.8 2.151 62.112 12.997 ;
     RECT  0.864 12.277 8.424 13.285 ;
     RECT  0.768 13.285 8.424 13.429 ;
     RECT  60.384 12.997 62.112 13.715 ;
     RECT  40.2 12.227 40.512 14.773 ;
     RECT  0.768 13.429 8.52 14.819 ;
     RECT  55.68 12.901 57.864 14.867 ;
     RECT  56.4 14.867 57.864 15.251 ;
     RECT  7.296 14.819 8.52 15.253 ;
     RECT  9.648 11.171 10.68 15.253 ;
     RECT  40.2 14.773 40.728 15.493 ;
     RECT  40.2 15.493 40.824 15.779 ;
     RECT  38.88 12.227 38.904 16.259 ;
     RECT  16.512 15.493 16.536 16.309 ;
     RECT  15.984 16.309 16.536 16.355 ;
     RECT  57.84 15.251 57.864 16.405 ;
     RECT  7.296 15.253 10.68 17.221 ;
     RECT  7.296 17.221 10.824 17.365 ;
     RECT  11.952 4.499 11.976 17.365 ;
     RECT  50.88 5.605 51.312 17.843 ;
     RECT  0.768 14.819 6.312 17.941 ;
     RECT  7.296 17.365 11.976 17.941 ;
     RECT  54.72 16.405 54.744 18.179 ;
     RECT  56.4 15.251 56.712 19.045 ;
     RECT  57.84 16.405 58.824 19.045 ;
     RECT  55.008 20.581 55.032 20.725 ;
     RECT  56.4 19.045 59.208 20.725 ;
     RECT  55.008 20.725 59.208 20.869 ;
     RECT  54.912 20.869 59.208 21.445 ;
     RECT  48.336 17.797 48.36 22.259 ;
     RECT  54.72 21.445 59.208 22.597 ;
     RECT  18.6 2.151 18.912 23.269 ;
     RECT  13.2 11.893 13.944 23.315 ;
     RECT  18.6 23.269 19.656 23.317 ;
     RECT  54.144 22.597 59.208 23.317 ;
     RECT  60.576 13.715 62.112 23.317 ;
     RECT  42.816 17.989 42.84 25.429 ;
     RECT  42.816 25.429 43.8 25.475 ;
     RECT  54.144 23.317 62.112 26.005 ;
     RECT  43.776 25.475 43.8 26.291 ;
     RECT  34.8 3.925 35.208 26.531 ;
     RECT  45.6 9.493 46.104 30.275 ;
     RECT  64.656 30.757 64.68 30.899 ;
     RECT  18 23.317 19.656 31.427 ;
     RECT  54.144 26.005 62.904 31.429 ;
     RECT  42.816 27.301 42.84 32.771 ;
     RECT  53.904 31.429 62.904 33.253 ;
     RECT  18 31.427 18.912 33.827 ;
     RECT  29.4 2.137 29.88 33.877 ;
     RECT  18.192 33.827 18.912 33.923 ;
     RECT  52.992 33.253 62.904 36.229 ;
     RECT  29.4 33.877 30.504 36.755 ;
     RECT  45.6 30.275 46.008 36.853 ;
     RECT  44.304 33.013 44.328 36.997 ;
     RECT  45.6 36.853 46.152 36.997 ;
     RECT  44.304 36.997 46.152 37.043 ;
     RECT  44.304 37.043 45.912 37.859 ;
     RECT  44.736 37.859 45.912 38.003 ;
     RECT  44.784 38.003 45.912 38.149 ;
     RECT  44.784 38.149 46.008 42.803 ;
     RECT  45.072 42.803 46.008 43.861 ;
     RECT  45.072 43.861 46.248 45.971 ;
     RECT  33.168 31.381 33.192 46.547 ;
     RECT  52.992 36.229 62.952 47.557 ;
     RECT  45.264 45.971 46.248 47.845 ;
     RECT  47.28 36.997 47.304 47.845 ;
     RECT  45.072 47.845 46.248 48.515 ;
     RECT  47.28 47.845 47.448 49.909 ;
     RECT  52.944 47.557 62.952 54.373 ;
     RECT  47.28 49.909 47.784 54.661 ;
     RECT  47.28 54.661 47.928 55.045 ;
     RECT  45.072 48.515 45.912 57.155 ;
     RECT  47.28 55.045 48.168 57.299 ;
     RECT  45.6 57.155 45.912 57.637 ;
     RECT  52.944 54.373 63 58.741 ;
     RECT  48.048 57.299 48.168 60.421 ;
     RECT  47.904 60.421 48.168 60.949 ;
     RECT  47.904 60.949 48.696 61.525 ;
     RECT  47.904 61.525 49.56 61.907 ;
     RECT  48.672 61.907 49.56 62.195 ;
     RECT  64.656 62.677 64.68 62.819 ;
     RECT  22.176 61.525 22.2 63.299 ;
     RECT  49.536 62.195 49.56 63.395 ;
     RECT  29.4 36.755 29.88 65.027 ;
     RECT  51 17.843 51.312 66.085 ;
     RECT  45.6 57.637 46.44 66.515 ;
     RECT  51 66.085 51.864 67.187 ;
     RECT  0.768 17.941 11.976 67.667 ;
     RECT  51 67.187 51.768 69.011 ;
     RECT  0.768 67.667 11.064 71.797 ;
     RECT  0.144 71.797 11.064 72.659 ;
     RECT  0.816 72.659 11.064 75.205 ;
     RECT  0.816 75.205 11.4 75.925 ;
     RECT  0.816 75.925 11.688 75.973 ;
     RECT  0.816 75.973 11.976 76.885 ;
     RECT  13.2 23.315 13.512 77.557 ;
     RECT  15.984 16.355 16.008 78.083 ;
     RECT  13.2 77.557 14.232 78.613 ;
     RECT  13.2 78.613 14.472 79.427 ;
     RECT  0.816 76.885 12.072 80.099 ;
     RECT  14.736 79.477 15.96 80.245 ;
     RECT  14.736 80.245 16.2 80.485 ;
     RECT  14.736 80.485 16.824 81.059 ;
     RECT  18.6 33.923 18.912 81.637 ;
     RECT  18.192 81.637 18.912 81.733 ;
     RECT  18 81.733 18.912 82.789 ;
     RECT  17.712 82.789 18.912 83.557 ;
     RECT  21.072 83.509 21.096 83.699 ;
     RECT  17.712 83.557 19.32 84.563 ;
     RECT  21.648 85.381 21.672 85.429 ;
     RECT  17.712 84.563 19.176 86.341 ;
     RECT  20.16 84.901 20.184 86.341 ;
     RECT  21.504 85.429 21.672 86.341 ;
     RECT  21.168 86.341 21.672 87.109 ;
     RECT  21.168 87.109 22.152 88.261 ;
     RECT  21.168 88.261 22.68 88.885 ;
     RECT  24 2.151 24.312 88.885 ;
     RECT  21.168 88.885 24.408 89.461 ;
     RECT  26.544 88.885 26.568 89.605 ;
     RECT  21.168 89.461 24.648 90.037 ;
     RECT  25.68 89.605 26.568 90.037 ;
     RECT  21.168 90.037 26.568 90.277 ;
     RECT  21.168 90.277 27.336 91.043 ;
     RECT  27.312 91.043 27.336 91.235 ;
     RECT  21.168 91.043 26.136 92.293 ;
     RECT  52.944 58.741 63.096 92.915 ;
     RECT  29.4 65.027 29.712 93.445 ;
     RECT  28.368 93.445 29.712 94.021 ;
     RECT  31.824 36.805 31.848 94.115 ;
     RECT  28.08 94.021 29.712 95.509 ;
     RECT  31.056 94.597 31.08 95.509 ;
     RECT  28.08 95.509 31.08 96.565 ;
     RECT  28.08 96.565 31.56 97.429 ;
     RECT  34.8 26.531 35.112 99.253 ;
     RECT  34.464 99.253 35.112 99.685 ;
     RECT  33.984 99.685 35.112 100.069 ;
     RECT  33.984 100.069 35.208 100.261 ;
     RECT  33.984 100.261 35.496 100.645 ;
     RECT  33.984 100.645 35.976 101.605 ;
     RECT  33.984 101.605 36.936 102.707 ;
     RECT  40.2 15.779 40.512 104.149 ;
     RECT  37.44 103.141 37.992 104.245 ;
     RECT  39.408 104.149 40.512 104.245 ;
     RECT  37.44 104.245 40.512 106.309 ;
     RECT  37.44 106.309 40.92 106.549 ;
     RECT  37.44 106.549 41.448 106.837 ;
     RECT  37.44 106.837 41.928 107.701 ;
     RECT  43.824 107.557 43.848 108.181 ;
     RECT  43.392 108.181 43.848 108.323 ;
     RECT  37.44 107.701 42.408 108.469 ;
     RECT  43.392 108.323 43.416 108.469 ;
     RECT  52.944 92.915 63.048 108.707 ;
     RECT  37.44 108.469 43.416 109.381 ;
     RECT  37.44 109.381 43.896 109.813 ;
     RECT  37.44 109.813 44.376 109.957 ;
     RECT  45.6 66.515 45.912 109.957 ;
     RECT  37.44 109.957 45.912 110.869 ;
     RECT  52.944 108.707 52.968 111.059 ;
     RECT  47.472 110.245 47.496 111.203 ;
     RECT  37.44 110.869 46.008 111.685 ;
     RECT  37.44 111.685 46.872 112.837 ;
     RECT  51 69.011 51.312 114.037 ;
     RECT  50.448 114.037 51.312 114.085 ;
     RECT  0.912 80.099 12.072 116.915 ;
     RECT  52.992 116.437 53.016 117.253 ;
     RECT  54 108.707 63.048 117.253 ;
     RECT  52.992 117.253 63.048 117.443 ;
     RECT  59.376 117.443 63.048 119.747 ;
     RECT  1.008 116.915 12.072 120.613 ;
     RECT  59.424 119.747 63.048 121.909 ;
     RECT  52.992 117.443 58.392 121.957 ;
     RECT  59.376 121.909 63.048 121.957 ;
     RECT  0.912 120.613 12.072 123.491 ;
     RECT  52.992 121.957 63.048 123.731 ;
     RECT  50.352 114.085 51.312 123.779 ;
     RECT  53.52 123.731 63.048 124.883 ;
     RECT  53.952 124.883 63.048 125.027 ;
     RECT  59.184 125.027 63.048 125.747 ;
     RECT  53.952 125.027 58.152 126.035 ;
     RECT  54.48 126.035 58.152 126.517 ;
     RECT  59.184 125.747 62.76 126.517 ;
     RECT  54.48 126.517 62.76 126.947 ;
     RECT  51 123.779 51.312 127.093 ;
     RECT  54.48 126.947 62.664 127.093 ;
     RECT  28.08 97.429 32.04 127.449 ;
     RECT  13.2 79.427 13.752 127.463 ;
     RECT  28.08 127.449 29.52 127.463 ;
     RECT  37.44 112.837 47.832 127.621 ;
     RECT  48.816 127.093 62.664 127.621 ;
     RECT  63.648 127.093 63.672 127.717 ;
     RECT  13.248 127.463 13.752 128.821 ;
     RECT  14.736 81.059 15.24 128.821 ;
     RECT  30.528 127.449 32.04 128.821 ;
     RECT  33.984 102.707 36.264 128.821 ;
     RECT  37.44 127.621 62.664 128.821 ;
     RECT  63.648 127.717 64.152 128.821 ;
     RECT  0.912 123.491 9.816 129.445 ;
     RECT  10.8 123.491 12.072 129.445 ;
     RECT  13.248 128.821 15.24 129.445 ;
     RECT  16.704 81.059 16.728 129.445 ;
     RECT  17.712 86.341 20.184 129.445 ;
     RECT  21.168 92.293 27.096 129.445 ;
     RECT  28.08 127.463 29.304 129.445 ;
     RECT  30.528 128.821 32.52 129.445 ;
     RECT  33.984 128.821 64.152 129.445 ;
     RECT  0.912 129.445 64.152 129.552 ;
  END
END qfd_c_land_w258_narrow
END LIBRARY
